VERSION 5.8 ;
BUSBITCHARS "[]" ;
DIVIDERCHAR "/" ;
UNITS
    DATABASE MICRONS 1000 ;
END UNITS

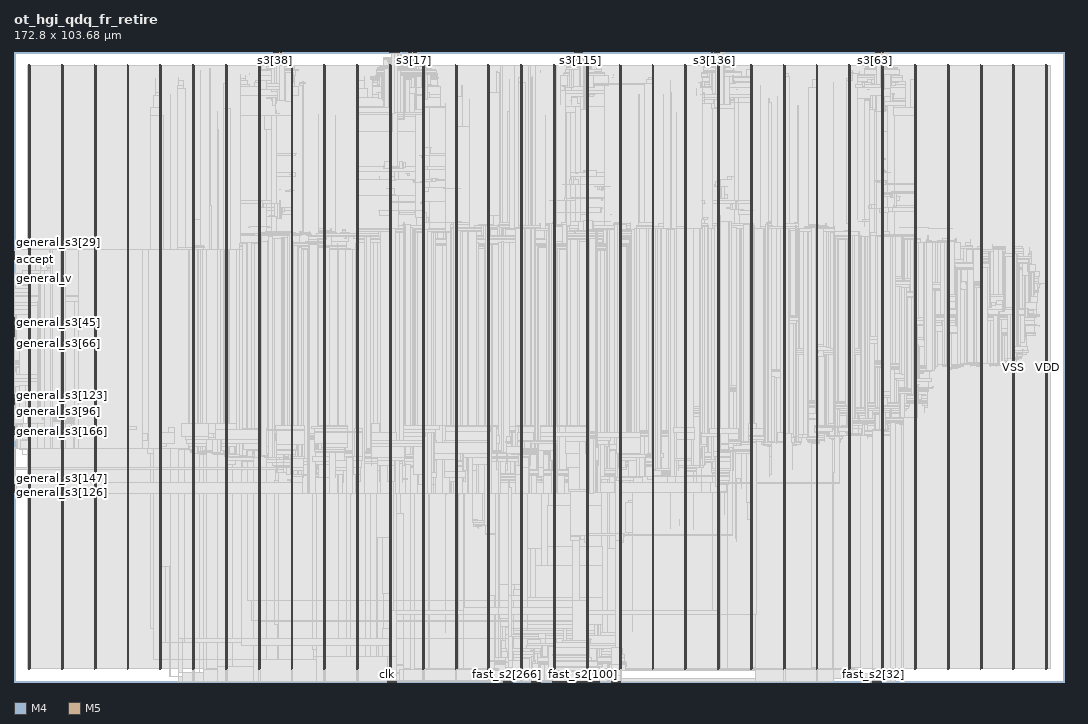
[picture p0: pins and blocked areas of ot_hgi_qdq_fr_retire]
MACRO ot_hgi_qdq_fr_retire
  FOREIGN ot_hgi_qdq_fr_retire 0 0 ;
  CLASS BLOCK ;
  SIZE 172.8 BY 103.68 ;
  PIN accept
    DIRECTION INPUT ;
    USE SIGNAL ;
    PORT
      LAYER M4 ;
        RECT  0 69.552 0.084 69.576 ;
    END
  END accept
  PIN accept_one
    DIRECTION INPUT ;
    USE SIGNAL ;
    PORT
      LAYER M4 ;
        RECT  0 69.6 0.084 69.624 ;
    END
  END accept_one
  PIN clk
    DIRECTION INPUT ;
    USE SIGNAL ;
    PORT
      LAYER M5 ;
        RECT  61.392 0 61.416 0.084 ;
    END
  END clk
  PIN fast_one
    DIRECTION INPUT ;
    USE SIGNAL ;
    PORT
      LAYER M5 ;
        RECT  61.44 0 61.464 0.084 ;
    END
  END fast_one
  PIN fast_s2[0]
    DIRECTION INPUT ;
    USE SIGNAL ;
    PORT
      LAYER M5 ;
        RECT  61.488 0 61.512 0.084 ;
    END
  END fast_s2[0]
  PIN fast_s2[100]
    DIRECTION INPUT ;
    USE SIGNAL ;
    PORT
      LAYER M5 ;
        RECT  93.552 0 93.576 0.084 ;
    END
  END fast_s2[100]
  PIN fast_s2[101]
    DIRECTION INPUT ;
    USE SIGNAL ;
    PORT
      LAYER M5 ;
        RECT  93.6 0 93.624 0.084 ;
    END
  END fast_s2[101]
  PIN fast_s2[102]
    DIRECTION INPUT ;
    USE SIGNAL ;
    PORT
      LAYER M5 ;
        RECT  93.648 0 93.672 0.084 ;
    END
  END fast_s2[102]
  PIN fast_s2[103]
    DIRECTION INPUT ;
    USE SIGNAL ;
    PORT
      LAYER M5 ;
        RECT  93.696 0 93.72 0.084 ;
    END
  END fast_s2[103]
  PIN fast_s2[104]
    DIRECTION INPUT ;
    USE SIGNAL ;
    PORT
      LAYER M5 ;
        RECT  93.744 0 93.768 0.084 ;
    END
  END fast_s2[104]
  PIN fast_s2[105]
    DIRECTION INPUT ;
    USE SIGNAL ;
    PORT
      LAYER M5 ;
        RECT  93.792 0 93.816 0.084 ;
    END
  END fast_s2[105]
  PIN fast_s2[106]
    DIRECTION INPUT ;
    USE SIGNAL ;
    PORT
      LAYER M5 ;
        RECT  93.84 0 93.864 0.084 ;
    END
  END fast_s2[106]
  PIN fast_s2[107]
    DIRECTION INPUT ;
    USE SIGNAL ;
    PORT
      LAYER M5 ;
        RECT  93.888 0 93.912 0.084 ;
    END
  END fast_s2[107]
  PIN fast_s2[108]
    DIRECTION INPUT ;
    USE SIGNAL ;
    PORT
      LAYER M5 ;
        RECT  93.936 0 93.96 0.084 ;
    END
  END fast_s2[108]
  PIN fast_s2[109]
    DIRECTION INPUT ;
    USE SIGNAL ;
    PORT
      LAYER M5 ;
        RECT  93.984 0 94.008 0.084 ;
    END
  END fast_s2[109]
  PIN fast_s2[10]
    DIRECTION INPUT ;
    USE SIGNAL ;
    PORT
      LAYER M5 ;
        RECT  61.968 0 61.992 0.084 ;
    END
  END fast_s2[10]
  PIN fast_s2[110]
    DIRECTION INPUT ;
    USE SIGNAL ;
    PORT
      LAYER M5 ;
        RECT  94.032 0 94.056 0.084 ;
    END
  END fast_s2[110]
  PIN fast_s2[111]
    DIRECTION INPUT ;
    USE SIGNAL ;
    PORT
      LAYER M5 ;
        RECT  94.08 0 94.104 0.084 ;
    END
  END fast_s2[111]
  PIN fast_s2[112]
    DIRECTION INPUT ;
    USE SIGNAL ;
    PORT
      LAYER M5 ;
        RECT  94.128 0 94.152 0.084 ;
    END
  END fast_s2[112]
  PIN fast_s2[113]
    DIRECTION INPUT ;
    USE SIGNAL ;
    PORT
      LAYER M5 ;
        RECT  94.176 0 94.2 0.084 ;
    END
  END fast_s2[113]
  PIN fast_s2[114]
    DIRECTION INPUT ;
    USE SIGNAL ;
    PORT
      LAYER M5 ;
        RECT  94.224 0 94.248 0.084 ;
    END
  END fast_s2[114]
  PIN fast_s2[115]
    DIRECTION INPUT ;
    USE SIGNAL ;
    PORT
      LAYER M5 ;
        RECT  94.272 0 94.296 0.084 ;
    END
  END fast_s2[115]
  PIN fast_s2[116]
    DIRECTION INPUT ;
    USE SIGNAL ;
    PORT
      LAYER M5 ;
        RECT  94.32 0 94.344 0.084 ;
    END
  END fast_s2[116]
  PIN fast_s2[117]
    DIRECTION INPUT ;
    USE SIGNAL ;
    PORT
      LAYER M5 ;
        RECT  94.368 0 94.392 0.084 ;
    END
  END fast_s2[117]
  PIN fast_s2[118]
    DIRECTION INPUT ;
    USE SIGNAL ;
    PORT
      LAYER M5 ;
        RECT  94.416 0 94.44 0.084 ;
    END
  END fast_s2[118]
  PIN fast_s2[119]
    DIRECTION INPUT ;
    USE SIGNAL ;
    PORT
      LAYER M5 ;
        RECT  94.464 0 94.488 0.084 ;
    END
  END fast_s2[119]
  PIN fast_s2[11]
    DIRECTION INPUT ;
    USE SIGNAL ;
    PORT
      LAYER M5 ;
        RECT  62.016 0 62.04 0.084 ;
    END
  END fast_s2[11]
  PIN fast_s2[120]
    DIRECTION INPUT ;
    USE SIGNAL ;
    PORT
      LAYER M5 ;
        RECT  94.512 0 94.536 0.084 ;
    END
  END fast_s2[120]
  PIN fast_s2[121]
    DIRECTION INPUT ;
    USE SIGNAL ;
    PORT
      LAYER M5 ;
        RECT  94.56 0 94.584 0.084 ;
    END
  END fast_s2[121]
  PIN fast_s2[122]
    DIRECTION INPUT ;
    USE SIGNAL ;
    PORT
      LAYER M5 ;
        RECT  94.608 0 94.632 0.084 ;
    END
  END fast_s2[122]
  PIN fast_s2[123]
    DIRECTION INPUT ;
    USE SIGNAL ;
    PORT
      LAYER M5 ;
        RECT  94.656 0 94.68 0.084 ;
    END
  END fast_s2[123]
  PIN fast_s2[124]
    DIRECTION INPUT ;
    USE SIGNAL ;
    PORT
      LAYER M5 ;
        RECT  94.704 0 94.728 0.084 ;
    END
  END fast_s2[124]
  PIN fast_s2[125]
    DIRECTION INPUT ;
    USE SIGNAL ;
    PORT
      LAYER M5 ;
        RECT  94.752 0 94.776 0.084 ;
    END
  END fast_s2[125]
  PIN fast_s2[126]
    DIRECTION INPUT ;
    USE SIGNAL ;
    PORT
      LAYER M5 ;
        RECT  90.192 0 90.216 0.084 ;
    END
  END fast_s2[126]
  PIN fast_s2[127]
    DIRECTION INPUT ;
    USE SIGNAL ;
    PORT
      LAYER M5 ;
        RECT  90.24 0 90.264 0.084 ;
    END
  END fast_s2[127]
  PIN fast_s2[128]
    DIRECTION INPUT ;
    USE SIGNAL ;
    PORT
      LAYER M5 ;
        RECT  90.288 0 90.312 0.084 ;
    END
  END fast_s2[128]
  PIN fast_s2[129]
    DIRECTION INPUT ;
    USE SIGNAL ;
    PORT
      LAYER M5 ;
        RECT  90.336 0 90.36 0.084 ;
    END
  END fast_s2[129]
  PIN fast_s2[12]
    DIRECTION INPUT ;
    USE SIGNAL ;
    PORT
      LAYER M5 ;
        RECT  62.064 0 62.088 0.084 ;
    END
  END fast_s2[12]
  PIN fast_s2[130]
    DIRECTION INPUT ;
    USE SIGNAL ;
    PORT
      LAYER M5 ;
        RECT  90.384 0 90.408 0.084 ;
    END
  END fast_s2[130]
  PIN fast_s2[131]
    DIRECTION INPUT ;
    USE SIGNAL ;
    PORT
      LAYER M5 ;
        RECT  90.432 0 90.456 0.084 ;
    END
  END fast_s2[131]
  PIN fast_s2[132]
    DIRECTION INPUT ;
    USE SIGNAL ;
    PORT
      LAYER M5 ;
        RECT  90.48 0 90.504 0.084 ;
    END
  END fast_s2[132]
  PIN fast_s2[133]
    DIRECTION INPUT ;
    USE SIGNAL ;
    PORT
      LAYER M5 ;
        RECT  90.528 0 90.552 0.084 ;
    END
  END fast_s2[133]
  PIN fast_s2[134]
    DIRECTION INPUT ;
    USE SIGNAL ;
    PORT
      LAYER M5 ;
        RECT  90.576 0 90.6 0.084 ;
    END
  END fast_s2[134]
  PIN fast_s2[135]
    DIRECTION INPUT ;
    USE SIGNAL ;
    PORT
      LAYER M5 ;
        RECT  90.624 0 90.648 0.084 ;
    END
  END fast_s2[135]
  PIN fast_s2[136]
    DIRECTION INPUT ;
    USE SIGNAL ;
    PORT
      LAYER M5 ;
        RECT  90.672 0 90.696 0.084 ;
    END
  END fast_s2[136]
  PIN fast_s2[137]
    DIRECTION INPUT ;
    USE SIGNAL ;
    PORT
      LAYER M5 ;
        RECT  90.72 0 90.744 0.084 ;
    END
  END fast_s2[137]
  PIN fast_s2[138]
    DIRECTION INPUT ;
    USE SIGNAL ;
    PORT
      LAYER M5 ;
        RECT  90.768 0 90.792 0.084 ;
    END
  END fast_s2[138]
  PIN fast_s2[139]
    DIRECTION INPUT ;
    USE SIGNAL ;
    PORT
      LAYER M5 ;
        RECT  90.816 0 90.84 0.084 ;
    END
  END fast_s2[139]
  PIN fast_s2[13]
    DIRECTION INPUT ;
    USE SIGNAL ;
    PORT
      LAYER M5 ;
        RECT  62.112 0 62.136 0.084 ;
    END
  END fast_s2[13]
  PIN fast_s2[140]
    DIRECTION INPUT ;
    USE SIGNAL ;
    PORT
      LAYER M5 ;
        RECT  90.864 0 90.888 0.084 ;
    END
  END fast_s2[140]
  PIN fast_s2[141]
    DIRECTION INPUT ;
    USE SIGNAL ;
    PORT
      LAYER M5 ;
        RECT  90.912 0 90.936 0.084 ;
    END
  END fast_s2[141]
  PIN fast_s2[142]
    DIRECTION INPUT ;
    USE SIGNAL ;
    PORT
      LAYER M5 ;
        RECT  90.96 0 90.984 0.084 ;
    END
  END fast_s2[142]
  PIN fast_s2[143]
    DIRECTION INPUT ;
    USE SIGNAL ;
    PORT
      LAYER M5 ;
        RECT  91.008 0 91.032 0.084 ;
    END
  END fast_s2[143]
  PIN fast_s2[144]
    DIRECTION INPUT ;
    USE SIGNAL ;
    PORT
      LAYER M5 ;
        RECT  91.056 0 91.08 0.084 ;
    END
  END fast_s2[144]
  PIN fast_s2[145]
    DIRECTION INPUT ;
    USE SIGNAL ;
    PORT
      LAYER M5 ;
        RECT  91.104 0 91.128 0.084 ;
    END
  END fast_s2[145]
  PIN fast_s2[146]
    DIRECTION INPUT ;
    USE SIGNAL ;
    PORT
      LAYER M5 ;
        RECT  91.152 0 91.176 0.084 ;
    END
  END fast_s2[146]
  PIN fast_s2[147]
    DIRECTION INPUT ;
    USE SIGNAL ;
    PORT
      LAYER M5 ;
        RECT  91.2 0 91.224 0.084 ;
    END
  END fast_s2[147]
  PIN fast_s2[148]
    DIRECTION INPUT ;
    USE SIGNAL ;
    PORT
      LAYER M5 ;
        RECT  91.248 0 91.272 0.084 ;
    END
  END fast_s2[148]
  PIN fast_s2[149]
    DIRECTION INPUT ;
    USE SIGNAL ;
    PORT
      LAYER M5 ;
        RECT  91.296 0 91.32 0.084 ;
    END
  END fast_s2[149]
  PIN fast_s2[14]
    DIRECTION INPUT ;
    USE SIGNAL ;
    PORT
      LAYER M5 ;
        RECT  62.16 0 62.184 0.084 ;
    END
  END fast_s2[14]
  PIN fast_s2[150]
    DIRECTION INPUT ;
    USE SIGNAL ;
    PORT
      LAYER M5 ;
        RECT  91.344 0 91.368 0.084 ;
    END
  END fast_s2[150]
  PIN fast_s2[151]
    DIRECTION INPUT ;
    USE SIGNAL ;
    PORT
      LAYER M5 ;
        RECT  91.392 0 91.416 0.084 ;
    END
  END fast_s2[151]
  PIN fast_s2[152]
    DIRECTION INPUT ;
    USE SIGNAL ;
    PORT
      LAYER M5 ;
        RECT  91.44 0 91.464 0.084 ;
    END
  END fast_s2[152]
  PIN fast_s2[153]
    DIRECTION INPUT ;
    USE SIGNAL ;
    PORT
      LAYER M5 ;
        RECT  91.488 0 91.512 0.084 ;
    END
  END fast_s2[153]
  PIN fast_s2[154]
    DIRECTION INPUT ;
    USE SIGNAL ;
    PORT
      LAYER M5 ;
        RECT  91.536 0 91.56 0.084 ;
    END
  END fast_s2[154]
  PIN fast_s2[155]
    DIRECTION INPUT ;
    USE SIGNAL ;
    PORT
      LAYER M5 ;
        RECT  91.584 0 91.608 0.084 ;
    END
  END fast_s2[155]
  PIN fast_s2[156]
    DIRECTION INPUT ;
    USE SIGNAL ;
    PORT
      LAYER M5 ;
        RECT  91.632 0 91.656 0.084 ;
    END
  END fast_s2[156]
  PIN fast_s2[157]
    DIRECTION INPUT ;
    USE SIGNAL ;
    PORT
      LAYER M5 ;
        RECT  91.68 0 91.704 0.084 ;
    END
  END fast_s2[157]
  PIN fast_s2[158]
    DIRECTION INPUT ;
    USE SIGNAL ;
    PORT
      LAYER M5 ;
        RECT  88.656 0 88.68 0.084 ;
    END
  END fast_s2[158]
  PIN fast_s2[159]
    DIRECTION INPUT ;
    USE SIGNAL ;
    PORT
      LAYER M5 ;
        RECT  88.704 0 88.728 0.084 ;
    END
  END fast_s2[159]
  PIN fast_s2[15]
    DIRECTION INPUT ;
    USE SIGNAL ;
    PORT
      LAYER M5 ;
        RECT  62.208 0 62.232 0.084 ;
    END
  END fast_s2[15]
  PIN fast_s2[160]
    DIRECTION INPUT ;
    USE SIGNAL ;
    PORT
      LAYER M5 ;
        RECT  88.752 0 88.776 0.084 ;
    END
  END fast_s2[160]
  PIN fast_s2[161]
    DIRECTION INPUT ;
    USE SIGNAL ;
    PORT
      LAYER M5 ;
        RECT  88.8 0 88.824 0.084 ;
    END
  END fast_s2[161]
  PIN fast_s2[162]
    DIRECTION INPUT ;
    USE SIGNAL ;
    PORT
      LAYER M5 ;
        RECT  88.848 0 88.872 0.084 ;
    END
  END fast_s2[162]
  PIN fast_s2[163]
    DIRECTION INPUT ;
    USE SIGNAL ;
    PORT
      LAYER M5 ;
        RECT  88.896 0 88.92 0.084 ;
    END
  END fast_s2[163]
  PIN fast_s2[164]
    DIRECTION INPUT ;
    USE SIGNAL ;
    PORT
      LAYER M5 ;
        RECT  88.944 0 88.968 0.084 ;
    END
  END fast_s2[164]
  PIN fast_s2[165]
    DIRECTION INPUT ;
    USE SIGNAL ;
    PORT
      LAYER M5 ;
        RECT  88.992 0 89.016 0.084 ;
    END
  END fast_s2[165]
  PIN fast_s2[166]
    DIRECTION INPUT ;
    USE SIGNAL ;
    PORT
      LAYER M5 ;
        RECT  89.04 0 89.064 0.084 ;
    END
  END fast_s2[166]
  PIN fast_s2[167]
    DIRECTION INPUT ;
    USE SIGNAL ;
    PORT
      LAYER M5 ;
        RECT  89.088 0 89.112 0.084 ;
    END
  END fast_s2[167]
  PIN fast_s2[168]
    DIRECTION INPUT ;
    USE SIGNAL ;
    PORT
      LAYER M5 ;
        RECT  89.136 0 89.16 0.084 ;
    END
  END fast_s2[168]
  PIN fast_s2[169]
    DIRECTION INPUT ;
    USE SIGNAL ;
    PORT
      LAYER M5 ;
        RECT  89.184 0 89.208 0.084 ;
    END
  END fast_s2[169]
  PIN fast_s2[16]
    DIRECTION INPUT ;
    USE SIGNAL ;
    PORT
      LAYER M5 ;
        RECT  62.256 0 62.28 0.084 ;
    END
  END fast_s2[16]
  PIN fast_s2[170]
    DIRECTION INPUT ;
    USE SIGNAL ;
    PORT
      LAYER M5 ;
        RECT  89.232 0 89.256 0.084 ;
    END
  END fast_s2[170]
  PIN fast_s2[171]
    DIRECTION INPUT ;
    USE SIGNAL ;
    PORT
      LAYER M5 ;
        RECT  89.28 0 89.304 0.084 ;
    END
  END fast_s2[171]
  PIN fast_s2[172]
    DIRECTION INPUT ;
    USE SIGNAL ;
    PORT
      LAYER M5 ;
        RECT  89.328 0 89.352 0.084 ;
    END
  END fast_s2[172]
  PIN fast_s2[173]
    DIRECTION INPUT ;
    USE SIGNAL ;
    PORT
      LAYER M5 ;
        RECT  89.376 0 89.4 0.084 ;
    END
  END fast_s2[173]
  PIN fast_s2[174]
    DIRECTION INPUT ;
    USE SIGNAL ;
    PORT
      LAYER M5 ;
        RECT  89.424 0 89.448 0.084 ;
    END
  END fast_s2[174]
  PIN fast_s2[175]
    DIRECTION INPUT ;
    USE SIGNAL ;
    PORT
      LAYER M5 ;
        RECT  89.472 0 89.496 0.084 ;
    END
  END fast_s2[175]
  PIN fast_s2[176]
    DIRECTION INPUT ;
    USE SIGNAL ;
    PORT
      LAYER M5 ;
        RECT  89.52 0 89.544 0.084 ;
    END
  END fast_s2[176]
  PIN fast_s2[177]
    DIRECTION INPUT ;
    USE SIGNAL ;
    PORT
      LAYER M5 ;
        RECT  89.568 0 89.592 0.084 ;
    END
  END fast_s2[177]
  PIN fast_s2[178]
    DIRECTION INPUT ;
    USE SIGNAL ;
    PORT
      LAYER M5 ;
        RECT  89.616 0 89.64 0.084 ;
    END
  END fast_s2[178]
  PIN fast_s2[179]
    DIRECTION INPUT ;
    USE SIGNAL ;
    PORT
      LAYER M5 ;
        RECT  89.664 0 89.688 0.084 ;
    END
  END fast_s2[179]
  PIN fast_s2[17]
    DIRECTION INPUT ;
    USE SIGNAL ;
    PORT
      LAYER M5 ;
        RECT  62.304 0 62.328 0.084 ;
    END
  END fast_s2[17]
  PIN fast_s2[180]
    DIRECTION INPUT ;
    USE SIGNAL ;
    PORT
      LAYER M5 ;
        RECT  89.712 0 89.736 0.084 ;
    END
  END fast_s2[180]
  PIN fast_s2[181]
    DIRECTION INPUT ;
    USE SIGNAL ;
    PORT
      LAYER M5 ;
        RECT  89.76 0 89.784 0.084 ;
    END
  END fast_s2[181]
  PIN fast_s2[182]
    DIRECTION INPUT ;
    USE SIGNAL ;
    PORT
      LAYER M5 ;
        RECT  89.808 0 89.832 0.084 ;
    END
  END fast_s2[182]
  PIN fast_s2[183]
    DIRECTION INPUT ;
    USE SIGNAL ;
    PORT
      LAYER M5 ;
        RECT  89.856 0 89.88 0.084 ;
    END
  END fast_s2[183]
  PIN fast_s2[184]
    DIRECTION INPUT ;
    USE SIGNAL ;
    PORT
      LAYER M5 ;
        RECT  89.904 0 89.928 0.084 ;
    END
  END fast_s2[184]
  PIN fast_s2[185]
    DIRECTION INPUT ;
    USE SIGNAL ;
    PORT
      LAYER M5 ;
        RECT  89.952 0 89.976 0.084 ;
    END
  END fast_s2[185]
  PIN fast_s2[186]
    DIRECTION INPUT ;
    USE SIGNAL ;
    PORT
      LAYER M5 ;
        RECT  90 0 90.024 0.084 ;
    END
  END fast_s2[186]
  PIN fast_s2[187]
    DIRECTION INPUT ;
    USE SIGNAL ;
    PORT
      LAYER M5 ;
        RECT  90.048 0 90.072 0.084 ;
    END
  END fast_s2[187]
  PIN fast_s2[188]
    DIRECTION INPUT ;
    USE SIGNAL ;
    PORT
      LAYER M5 ;
        RECT  90.096 0 90.12 0.084 ;
    END
  END fast_s2[188]
  PIN fast_s2[189]
    DIRECTION INPUT ;
    USE SIGNAL ;
    PORT
      LAYER M5 ;
        RECT  90.144 0 90.168 0.084 ;
    END
  END fast_s2[189]
  PIN fast_s2[18]
    DIRECTION INPUT ;
    USE SIGNAL ;
    PORT
      LAYER M5 ;
        RECT  62.352 0 62.376 0.084 ;
    END
  END fast_s2[18]
  PIN fast_s2[190]
    DIRECTION INPUT ;
    USE SIGNAL ;
    PORT
      LAYER M5 ;
        RECT  98.256 0 98.28 0.084 ;
    END
  END fast_s2[190]
  PIN fast_s2[191]
    DIRECTION INPUT ;
    USE SIGNAL ;
    PORT
      LAYER M5 ;
        RECT  98.304 0 98.328 0.084 ;
    END
  END fast_s2[191]
  PIN fast_s2[192]
    DIRECTION INPUT ;
    USE SIGNAL ;
    PORT
      LAYER M5 ;
        RECT  98.352 0 98.376 0.084 ;
    END
  END fast_s2[192]
  PIN fast_s2[193]
    DIRECTION INPUT ;
    USE SIGNAL ;
    PORT
      LAYER M5 ;
        RECT  98.4 0 98.424 0.084 ;
    END
  END fast_s2[193]
  PIN fast_s2[194]
    DIRECTION INPUT ;
    USE SIGNAL ;
    PORT
      LAYER M5 ;
        RECT  98.448 0 98.472 0.084 ;
    END
  END fast_s2[194]
  PIN fast_s2[195]
    DIRECTION INPUT ;
    USE SIGNAL ;
    PORT
      LAYER M5 ;
        RECT  98.496 0 98.52 0.084 ;
    END
  END fast_s2[195]
  PIN fast_s2[196]
    DIRECTION INPUT ;
    USE SIGNAL ;
    PORT
      LAYER M5 ;
        RECT  98.544 0 98.568 0.084 ;
    END
  END fast_s2[196]
  PIN fast_s2[197]
    DIRECTION INPUT ;
    USE SIGNAL ;
    PORT
      LAYER M5 ;
        RECT  98.592 0 98.616 0.084 ;
    END
  END fast_s2[197]
  PIN fast_s2[198]
    DIRECTION INPUT ;
    USE SIGNAL ;
    PORT
      LAYER M5 ;
        RECT  98.64 0 98.664 0.084 ;
    END
  END fast_s2[198]
  PIN fast_s2[199]
    DIRECTION INPUT ;
    USE SIGNAL ;
    PORT
      LAYER M5 ;
        RECT  98.688 0 98.712 0.084 ;
    END
  END fast_s2[199]
  PIN fast_s2[19]
    DIRECTION INPUT ;
    USE SIGNAL ;
    PORT
      LAYER M5 ;
        RECT  62.4 0 62.424 0.084 ;
    END
  END fast_s2[19]
  PIN fast_s2[1]
    DIRECTION INPUT ;
    USE SIGNAL ;
    PORT
      LAYER M5 ;
        RECT  61.536 0 61.56 0.084 ;
    END
  END fast_s2[1]
  PIN fast_s2[200]
    DIRECTION INPUT ;
    USE SIGNAL ;
    PORT
      LAYER M5 ;
        RECT  98.736 0 98.76 0.084 ;
    END
  END fast_s2[200]
  PIN fast_s2[201]
    DIRECTION INPUT ;
    USE SIGNAL ;
    PORT
      LAYER M5 ;
        RECT  98.784 0 98.808 0.084 ;
    END
  END fast_s2[201]
  PIN fast_s2[202]
    DIRECTION INPUT ;
    USE SIGNAL ;
    PORT
      LAYER M5 ;
        RECT  98.832 0 98.856 0.084 ;
    END
  END fast_s2[202]
  PIN fast_s2[203]
    DIRECTION INPUT ;
    USE SIGNAL ;
    PORT
      LAYER M5 ;
        RECT  98.88 0 98.904 0.084 ;
    END
  END fast_s2[203]
  PIN fast_s2[204]
    DIRECTION INPUT ;
    USE SIGNAL ;
    PORT
      LAYER M5 ;
        RECT  98.928 0 98.952 0.084 ;
    END
  END fast_s2[204]
  PIN fast_s2[205]
    DIRECTION INPUT ;
    USE SIGNAL ;
    PORT
      LAYER M5 ;
        RECT  98.976 0 99 0.084 ;
    END
  END fast_s2[205]
  PIN fast_s2[206]
    DIRECTION INPUT ;
    USE SIGNAL ;
    PORT
      LAYER M5 ;
        RECT  99.024 0 99.048 0.084 ;
    END
  END fast_s2[206]
  PIN fast_s2[207]
    DIRECTION INPUT ;
    USE SIGNAL ;
    PORT
      LAYER M5 ;
        RECT  99.072 0 99.096 0.084 ;
    END
  END fast_s2[207]
  PIN fast_s2[208]
    DIRECTION INPUT ;
    USE SIGNAL ;
    PORT
      LAYER M5 ;
        RECT  99.12 0 99.144 0.084 ;
    END
  END fast_s2[208]
  PIN fast_s2[209]
    DIRECTION INPUT ;
    USE SIGNAL ;
    PORT
      LAYER M5 ;
        RECT  99.168 0 99.192 0.084 ;
    END
  END fast_s2[209]
  PIN fast_s2[20]
    DIRECTION INPUT ;
    USE SIGNAL ;
    PORT
      LAYER M5 ;
        RECT  62.448 0 62.472 0.084 ;
    END
  END fast_s2[20]
  PIN fast_s2[210]
    DIRECTION INPUT ;
    USE SIGNAL ;
    PORT
      LAYER M5 ;
        RECT  99.216 0 99.24 0.084 ;
    END
  END fast_s2[210]
  PIN fast_s2[211]
    DIRECTION INPUT ;
    USE SIGNAL ;
    PORT
      LAYER M5 ;
        RECT  99.264 0 99.288 0.084 ;
    END
  END fast_s2[211]
  PIN fast_s2[212]
    DIRECTION INPUT ;
    USE SIGNAL ;
    PORT
      LAYER M5 ;
        RECT  99.312 0 99.336 0.084 ;
    END
  END fast_s2[212]
  PIN fast_s2[213]
    DIRECTION INPUT ;
    USE SIGNAL ;
    PORT
      LAYER M5 ;
        RECT  99.36 0 99.384 0.084 ;
    END
  END fast_s2[213]
  PIN fast_s2[214]
    DIRECTION INPUT ;
    USE SIGNAL ;
    PORT
      LAYER M5 ;
        RECT  99.408 0 99.432 0.084 ;
    END
  END fast_s2[214]
  PIN fast_s2[215]
    DIRECTION INPUT ;
    USE SIGNAL ;
    PORT
      LAYER M5 ;
        RECT  99.456 0 99.48 0.084 ;
    END
  END fast_s2[215]
  PIN fast_s2[216]
    DIRECTION INPUT ;
    USE SIGNAL ;
    PORT
      LAYER M5 ;
        RECT  99.504 0 99.528 0.084 ;
    END
  END fast_s2[216]
  PIN fast_s2[217]
    DIRECTION INPUT ;
    USE SIGNAL ;
    PORT
      LAYER M5 ;
        RECT  99.552 0 99.576 0.084 ;
    END
  END fast_s2[217]
  PIN fast_s2[218]
    DIRECTION INPUT ;
    USE SIGNAL ;
    PORT
      LAYER M5 ;
        RECT  99.6 0 99.624 0.084 ;
    END
  END fast_s2[218]
  PIN fast_s2[219]
    DIRECTION INPUT ;
    USE SIGNAL ;
    PORT
      LAYER M5 ;
        RECT  99.648 0 99.672 0.084 ;
    END
  END fast_s2[219]
  PIN fast_s2[21]
    DIRECTION INPUT ;
    USE SIGNAL ;
    PORT
      LAYER M5 ;
        RECT  62.496 0 62.52 0.084 ;
    END
  END fast_s2[21]
  PIN fast_s2[220]
    DIRECTION INPUT ;
    USE SIGNAL ;
    PORT
      LAYER M5 ;
        RECT  99.696 0 99.72 0.084 ;
    END
  END fast_s2[220]
  PIN fast_s2[221]
    DIRECTION INPUT ;
    USE SIGNAL ;
    PORT
      LAYER M5 ;
        RECT  99.744 0 99.768 0.084 ;
    END
  END fast_s2[221]
  PIN fast_s2[222]
    DIRECTION INPUT ;
    USE SIGNAL ;
    PORT
      LAYER M5 ;
        RECT  94.8 0 94.824 0.084 ;
    END
  END fast_s2[222]
  PIN fast_s2[223]
    DIRECTION INPUT ;
    USE SIGNAL ;
    PORT
      LAYER M5 ;
        RECT  94.848 0 94.872 0.084 ;
    END
  END fast_s2[223]
  PIN fast_s2[224]
    DIRECTION INPUT ;
    USE SIGNAL ;
    PORT
      LAYER M5 ;
        RECT  94.896 0 94.92 0.084 ;
    END
  END fast_s2[224]
  PIN fast_s2[225]
    DIRECTION INPUT ;
    USE SIGNAL ;
    PORT
      LAYER M5 ;
        RECT  94.944 0 94.968 0.084 ;
    END
  END fast_s2[225]
  PIN fast_s2[226]
    DIRECTION INPUT ;
    USE SIGNAL ;
    PORT
      LAYER M5 ;
        RECT  94.992 0 95.016 0.084 ;
    END
  END fast_s2[226]
  PIN fast_s2[227]
    DIRECTION INPUT ;
    USE SIGNAL ;
    PORT
      LAYER M5 ;
        RECT  95.04 0 95.064 0.084 ;
    END
  END fast_s2[227]
  PIN fast_s2[228]
    DIRECTION INPUT ;
    USE SIGNAL ;
    PORT
      LAYER M5 ;
        RECT  95.088 0 95.112 0.084 ;
    END
  END fast_s2[228]
  PIN fast_s2[229]
    DIRECTION INPUT ;
    USE SIGNAL ;
    PORT
      LAYER M5 ;
        RECT  95.136 0 95.16 0.084 ;
    END
  END fast_s2[229]
  PIN fast_s2[22]
    DIRECTION INPUT ;
    USE SIGNAL ;
    PORT
      LAYER M5 ;
        RECT  62.544 0 62.568 0.084 ;
    END
  END fast_s2[22]
  PIN fast_s2[230]
    DIRECTION INPUT ;
    USE SIGNAL ;
    PORT
      LAYER M5 ;
        RECT  95.184 0 95.208 0.084 ;
    END
  END fast_s2[230]
  PIN fast_s2[231]
    DIRECTION INPUT ;
    USE SIGNAL ;
    PORT
      LAYER M5 ;
        RECT  95.232 0 95.256 0.084 ;
    END
  END fast_s2[231]
  PIN fast_s2[232]
    DIRECTION INPUT ;
    USE SIGNAL ;
    PORT
      LAYER M5 ;
        RECT  95.28 0 95.304 0.084 ;
    END
  END fast_s2[232]
  PIN fast_s2[233]
    DIRECTION INPUT ;
    USE SIGNAL ;
    PORT
      LAYER M5 ;
        RECT  95.328 0 95.352 0.084 ;
    END
  END fast_s2[233]
  PIN fast_s2[234]
    DIRECTION INPUT ;
    USE SIGNAL ;
    PORT
      LAYER M5 ;
        RECT  95.376 0 95.4 0.084 ;
    END
  END fast_s2[234]
  PIN fast_s2[235]
    DIRECTION INPUT ;
    USE SIGNAL ;
    PORT
      LAYER M5 ;
        RECT  95.424 0 95.448 0.084 ;
    END
  END fast_s2[235]
  PIN fast_s2[236]
    DIRECTION INPUT ;
    USE SIGNAL ;
    PORT
      LAYER M5 ;
        RECT  95.472 0 95.496 0.084 ;
    END
  END fast_s2[236]
  PIN fast_s2[237]
    DIRECTION INPUT ;
    USE SIGNAL ;
    PORT
      LAYER M5 ;
        RECT  95.52 0 95.544 0.084 ;
    END
  END fast_s2[237]
  PIN fast_s2[238]
    DIRECTION INPUT ;
    USE SIGNAL ;
    PORT
      LAYER M5 ;
        RECT  95.568 0 95.592 0.084 ;
    END
  END fast_s2[238]
  PIN fast_s2[239]
    DIRECTION INPUT ;
    USE SIGNAL ;
    PORT
      LAYER M5 ;
        RECT  95.616 0 95.64 0.084 ;
    END
  END fast_s2[239]
  PIN fast_s2[23]
    DIRECTION INPUT ;
    USE SIGNAL ;
    PORT
      LAYER M5 ;
        RECT  62.592 0 62.616 0.084 ;
    END
  END fast_s2[23]
  PIN fast_s2[240]
    DIRECTION INPUT ;
    USE SIGNAL ;
    PORT
      LAYER M5 ;
        RECT  95.664 0 95.688 0.084 ;
    END
  END fast_s2[240]
  PIN fast_s2[241]
    DIRECTION INPUT ;
    USE SIGNAL ;
    PORT
      LAYER M5 ;
        RECT  95.712 0 95.736 0.084 ;
    END
  END fast_s2[241]
  PIN fast_s2[242]
    DIRECTION INPUT ;
    USE SIGNAL ;
    PORT
      LAYER M5 ;
        RECT  95.76 0 95.784 0.084 ;
    END
  END fast_s2[242]
  PIN fast_s2[243]
    DIRECTION INPUT ;
    USE SIGNAL ;
    PORT
      LAYER M5 ;
        RECT  95.808 0 95.832 0.084 ;
    END
  END fast_s2[243]
  PIN fast_s2[244]
    DIRECTION INPUT ;
    USE SIGNAL ;
    PORT
      LAYER M5 ;
        RECT  95.856 0 95.88 0.084 ;
    END
  END fast_s2[244]
  PIN fast_s2[245]
    DIRECTION INPUT ;
    USE SIGNAL ;
    PORT
      LAYER M5 ;
        RECT  95.904 0 95.928 0.084 ;
    END
  END fast_s2[245]
  PIN fast_s2[246]
    DIRECTION INPUT ;
    USE SIGNAL ;
    PORT
      LAYER M5 ;
        RECT  95.952 0 95.976 0.084 ;
    END
  END fast_s2[246]
  PIN fast_s2[247]
    DIRECTION INPUT ;
    USE SIGNAL ;
    PORT
      LAYER M5 ;
        RECT  96 0 96.024 0.084 ;
    END
  END fast_s2[247]
  PIN fast_s2[248]
    DIRECTION INPUT ;
    USE SIGNAL ;
    PORT
      LAYER M5 ;
        RECT  96.048 0 96.072 0.084 ;
    END
  END fast_s2[248]
  PIN fast_s2[249]
    DIRECTION INPUT ;
    USE SIGNAL ;
    PORT
      LAYER M5 ;
        RECT  96.096 0 96.12 0.084 ;
    END
  END fast_s2[249]
  PIN fast_s2[24]
    DIRECTION INPUT ;
    USE SIGNAL ;
    PORT
      LAYER M5 ;
        RECT  62.64 0 62.664 0.084 ;
    END
  END fast_s2[24]
  PIN fast_s2[250]
    DIRECTION INPUT ;
    USE SIGNAL ;
    PORT
      LAYER M5 ;
        RECT  96.144 0 96.168 0.084 ;
    END
  END fast_s2[250]
  PIN fast_s2[251]
    DIRECTION INPUT ;
    USE SIGNAL ;
    PORT
      LAYER M5 ;
        RECT  96.192 0 96.216 0.084 ;
    END
  END fast_s2[251]
  PIN fast_s2[252]
    DIRECTION INPUT ;
    USE SIGNAL ;
    PORT
      LAYER M5 ;
        RECT  96.24 0 96.264 0.084 ;
    END
  END fast_s2[252]
  PIN fast_s2[253]
    DIRECTION INPUT ;
    USE SIGNAL ;
    PORT
      LAYER M5 ;
        RECT  96.288 0 96.312 0.084 ;
    END
  END fast_s2[253]
  PIN fast_s2[254]
    DIRECTION INPUT ;
    USE SIGNAL ;
    PORT
      LAYER M5 ;
        RECT  80.592 0 80.616 0.084 ;
    END
  END fast_s2[254]
  PIN fast_s2[255]
    DIRECTION INPUT ;
    USE SIGNAL ;
    PORT
      LAYER M5 ;
        RECT  80.64 0 80.664 0.084 ;
    END
  END fast_s2[255]
  PIN fast_s2[256]
    DIRECTION INPUT ;
    USE SIGNAL ;
    PORT
      LAYER M5 ;
        RECT  80.688 0 80.712 0.084 ;
    END
  END fast_s2[256]
  PIN fast_s2[257]
    DIRECTION INPUT ;
    USE SIGNAL ;
    PORT
      LAYER M5 ;
        RECT  80.736 0 80.76 0.084 ;
    END
  END fast_s2[257]
  PIN fast_s2[258]
    DIRECTION INPUT ;
    USE SIGNAL ;
    PORT
      LAYER M5 ;
        RECT  80.784 0 80.808 0.084 ;
    END
  END fast_s2[258]
  PIN fast_s2[259]
    DIRECTION INPUT ;
    USE SIGNAL ;
    PORT
      LAYER M5 ;
        RECT  80.832 0 80.856 0.084 ;
    END
  END fast_s2[259]
  PIN fast_s2[25]
    DIRECTION INPUT ;
    USE SIGNAL ;
    PORT
      LAYER M5 ;
        RECT  62.688 0 62.712 0.084 ;
    END
  END fast_s2[25]
  PIN fast_s2[260]
    DIRECTION INPUT ;
    USE SIGNAL ;
    PORT
      LAYER M5 ;
        RECT  80.88 0 80.904 0.084 ;
    END
  END fast_s2[260]
  PIN fast_s2[261]
    DIRECTION INPUT ;
    USE SIGNAL ;
    PORT
      LAYER M5 ;
        RECT  80.928 0 80.952 0.084 ;
    END
  END fast_s2[261]
  PIN fast_s2[262]
    DIRECTION INPUT ;
    USE SIGNAL ;
    PORT
      LAYER M5 ;
        RECT  80.976 0 81 0.084 ;
    END
  END fast_s2[262]
  PIN fast_s2[263]
    DIRECTION INPUT ;
    USE SIGNAL ;
    PORT
      LAYER M5 ;
        RECT  81.024 0 81.048 0.084 ;
    END
  END fast_s2[263]
  PIN fast_s2[264]
    DIRECTION INPUT ;
    USE SIGNAL ;
    PORT
      LAYER M5 ;
        RECT  81.072 0 81.096 0.084 ;
    END
  END fast_s2[264]
  PIN fast_s2[265]
    DIRECTION INPUT ;
    USE SIGNAL ;
    PORT
      LAYER M5 ;
        RECT  81.12 0 81.144 0.084 ;
    END
  END fast_s2[265]
  PIN fast_s2[266]
    DIRECTION INPUT ;
    USE SIGNAL ;
    PORT
      LAYER M5 ;
        RECT  81.168 0 81.192 0.084 ;
    END
  END fast_s2[266]
  PIN fast_s2[267]
    DIRECTION INPUT ;
    USE SIGNAL ;
    PORT
      LAYER M5 ;
        RECT  81.216 0 81.24 0.084 ;
    END
  END fast_s2[267]
  PIN fast_s2[268]
    DIRECTION INPUT ;
    USE SIGNAL ;
    PORT
      LAYER M5 ;
        RECT  81.264 0 81.288 0.084 ;
    END
  END fast_s2[268]
  PIN fast_s2[269]
    DIRECTION INPUT ;
    USE SIGNAL ;
    PORT
      LAYER M5 ;
        RECT  81.312 0 81.336 0.084 ;
    END
  END fast_s2[269]
  PIN fast_s2[26]
    DIRECTION INPUT ;
    USE SIGNAL ;
    PORT
      LAYER M5 ;
        RECT  62.736 0 62.76 0.084 ;
    END
  END fast_s2[26]
  PIN fast_s2[270]
    DIRECTION INPUT ;
    USE SIGNAL ;
    PORT
      LAYER M5 ;
        RECT  81.36 0 81.384 0.084 ;
    END
  END fast_s2[270]
  PIN fast_s2[271]
    DIRECTION INPUT ;
    USE SIGNAL ;
    PORT
      LAYER M5 ;
        RECT  81.408 0 81.432 0.084 ;
    END
  END fast_s2[271]
  PIN fast_s2[272]
    DIRECTION INPUT ;
    USE SIGNAL ;
    PORT
      LAYER M5 ;
        RECT  81.456 0 81.48 0.084 ;
    END
  END fast_s2[272]
  PIN fast_s2[273]
    DIRECTION INPUT ;
    USE SIGNAL ;
    PORT
      LAYER M5 ;
        RECT  81.504 0 81.528 0.084 ;
    END
  END fast_s2[273]
  PIN fast_s2[274]
    DIRECTION INPUT ;
    USE SIGNAL ;
    PORT
      LAYER M5 ;
        RECT  81.552 0 81.576 0.084 ;
    END
  END fast_s2[274]
  PIN fast_s2[275]
    DIRECTION INPUT ;
    USE SIGNAL ;
    PORT
      LAYER M5 ;
        RECT  81.6 0 81.624 0.084 ;
    END
  END fast_s2[275]
  PIN fast_s2[276]
    DIRECTION INPUT ;
    USE SIGNAL ;
    PORT
      LAYER M5 ;
        RECT  81.648 0 81.672 0.084 ;
    END
  END fast_s2[276]
  PIN fast_s2[277]
    DIRECTION INPUT ;
    USE SIGNAL ;
    PORT
      LAYER M5 ;
        RECT  81.696 0 81.72 0.084 ;
    END
  END fast_s2[277]
  PIN fast_s2[278]
    DIRECTION INPUT ;
    USE SIGNAL ;
    PORT
      LAYER M5 ;
        RECT  81.744 0 81.768 0.084 ;
    END
  END fast_s2[278]
  PIN fast_s2[279]
    DIRECTION INPUT ;
    USE SIGNAL ;
    PORT
      LAYER M5 ;
        RECT  81.792 0 81.816 0.084 ;
    END
  END fast_s2[279]
  PIN fast_s2[27]
    DIRECTION INPUT ;
    USE SIGNAL ;
    PORT
      LAYER M5 ;
        RECT  62.784 0 62.808 0.084 ;
    END
  END fast_s2[27]
  PIN fast_s2[280]
    DIRECTION INPUT ;
    USE SIGNAL ;
    PORT
      LAYER M5 ;
        RECT  81.84 0 81.864 0.084 ;
    END
  END fast_s2[280]
  PIN fast_s2[281]
    DIRECTION INPUT ;
    USE SIGNAL ;
    PORT
      LAYER M5 ;
        RECT  81.888 0 81.912 0.084 ;
    END
  END fast_s2[281]
  PIN fast_s2[282]
    DIRECTION INPUT ;
    USE SIGNAL ;
    PORT
      LAYER M5 ;
        RECT  81.936 0 81.96 0.084 ;
    END
  END fast_s2[282]
  PIN fast_s2[283]
    DIRECTION INPUT ;
    USE SIGNAL ;
    PORT
      LAYER M5 ;
        RECT  81.984 0 82.008 0.084 ;
    END
  END fast_s2[283]
  PIN fast_s2[284]
    DIRECTION INPUT ;
    USE SIGNAL ;
    PORT
      LAYER M5 ;
        RECT  82.032 0 82.056 0.084 ;
    END
  END fast_s2[284]
  PIN fast_s2[285]
    DIRECTION INPUT ;
    USE SIGNAL ;
    PORT
      LAYER M5 ;
        RECT  82.08 0 82.104 0.084 ;
    END
  END fast_s2[285]
  PIN fast_s2[286]
    DIRECTION INPUT ;
    USE SIGNAL ;
    PORT
      LAYER M5 ;
        RECT  85.2 0 85.224 0.084 ;
    END
  END fast_s2[286]
  PIN fast_s2[287]
    DIRECTION INPUT ;
    USE SIGNAL ;
    PORT
      LAYER M5 ;
        RECT  85.248 0 85.272 0.084 ;
    END
  END fast_s2[287]
  PIN fast_s2[288]
    DIRECTION INPUT ;
    USE SIGNAL ;
    PORT
      LAYER M5 ;
        RECT  85.296 0 85.32 0.084 ;
    END
  END fast_s2[288]
  PIN fast_s2[289]
    DIRECTION INPUT ;
    USE SIGNAL ;
    PORT
      LAYER M5 ;
        RECT  85.344 0 85.368 0.084 ;
    END
  END fast_s2[289]
  PIN fast_s2[28]
    DIRECTION INPUT ;
    USE SIGNAL ;
    PORT
      LAYER M5 ;
        RECT  62.832 0 62.856 0.084 ;
    END
  END fast_s2[28]
  PIN fast_s2[290]
    DIRECTION INPUT ;
    USE SIGNAL ;
    PORT
      LAYER M5 ;
        RECT  85.392 0 85.416 0.084 ;
    END
  END fast_s2[290]
  PIN fast_s2[291]
    DIRECTION INPUT ;
    USE SIGNAL ;
    PORT
      LAYER M5 ;
        RECT  85.44 0 85.464 0.084 ;
    END
  END fast_s2[291]
  PIN fast_s2[292]
    DIRECTION INPUT ;
    USE SIGNAL ;
    PORT
      LAYER M5 ;
        RECT  85.488 0 85.512 0.084 ;
    END
  END fast_s2[292]
  PIN fast_s2[293]
    DIRECTION INPUT ;
    USE SIGNAL ;
    PORT
      LAYER M5 ;
        RECT  85.536 0 85.56 0.084 ;
    END
  END fast_s2[293]
  PIN fast_s2[294]
    DIRECTION INPUT ;
    USE SIGNAL ;
    PORT
      LAYER M5 ;
        RECT  85.584 0 85.608 0.084 ;
    END
  END fast_s2[294]
  PIN fast_s2[295]
    DIRECTION INPUT ;
    USE SIGNAL ;
    PORT
      LAYER M5 ;
        RECT  85.632 0 85.656 0.084 ;
    END
  END fast_s2[295]
  PIN fast_s2[296]
    DIRECTION INPUT ;
    USE SIGNAL ;
    PORT
      LAYER M5 ;
        RECT  85.68 0 85.704 0.084 ;
    END
  END fast_s2[296]
  PIN fast_s2[297]
    DIRECTION INPUT ;
    USE SIGNAL ;
    PORT
      LAYER M5 ;
        RECT  85.728 0 85.752 0.084 ;
    END
  END fast_s2[297]
  PIN fast_s2[298]
    DIRECTION INPUT ;
    USE SIGNAL ;
    PORT
      LAYER M5 ;
        RECT  85.776 0 85.8 0.084 ;
    END
  END fast_s2[298]
  PIN fast_s2[299]
    DIRECTION INPUT ;
    USE SIGNAL ;
    PORT
      LAYER M5 ;
        RECT  85.824 0 85.848 0.084 ;
    END
  END fast_s2[299]
  PIN fast_s2[29]
    DIRECTION INPUT ;
    USE SIGNAL ;
    PORT
      LAYER M5 ;
        RECT  62.88 0 62.904 0.084 ;
    END
  END fast_s2[29]
  PIN fast_s2[2]
    DIRECTION INPUT ;
    USE SIGNAL ;
    PORT
      LAYER M5 ;
        RECT  61.584 0 61.608 0.084 ;
    END
  END fast_s2[2]
  PIN fast_s2[300]
    DIRECTION INPUT ;
    USE SIGNAL ;
    PORT
      LAYER M5 ;
        RECT  85.872 0 85.896 0.084 ;
    END
  END fast_s2[300]
  PIN fast_s2[301]
    DIRECTION INPUT ;
    USE SIGNAL ;
    PORT
      LAYER M5 ;
        RECT  85.92 0 85.944 0.084 ;
    END
  END fast_s2[301]
  PIN fast_s2[302]
    DIRECTION INPUT ;
    USE SIGNAL ;
    PORT
      LAYER M5 ;
        RECT  85.968 0 85.992 0.084 ;
    END
  END fast_s2[302]
  PIN fast_s2[303]
    DIRECTION INPUT ;
    USE SIGNAL ;
    PORT
      LAYER M5 ;
        RECT  86.016 0 86.04 0.084 ;
    END
  END fast_s2[303]
  PIN fast_s2[304]
    DIRECTION INPUT ;
    USE SIGNAL ;
    PORT
      LAYER M5 ;
        RECT  86.064 0 86.088 0.084 ;
    END
  END fast_s2[304]
  PIN fast_s2[305]
    DIRECTION INPUT ;
    USE SIGNAL ;
    PORT
      LAYER M5 ;
        RECT  86.112 0 86.136 0.084 ;
    END
  END fast_s2[305]
  PIN fast_s2[306]
    DIRECTION INPUT ;
    USE SIGNAL ;
    PORT
      LAYER M5 ;
        RECT  86.16 0 86.184 0.084 ;
    END
  END fast_s2[306]
  PIN fast_s2[307]
    DIRECTION INPUT ;
    USE SIGNAL ;
    PORT
      LAYER M5 ;
        RECT  86.208 0 86.232 0.084 ;
    END
  END fast_s2[307]
  PIN fast_s2[308]
    DIRECTION INPUT ;
    USE SIGNAL ;
    PORT
      LAYER M5 ;
        RECT  86.256 0 86.28 0.084 ;
    END
  END fast_s2[308]
  PIN fast_s2[309]
    DIRECTION INPUT ;
    USE SIGNAL ;
    PORT
      LAYER M5 ;
        RECT  86.304 0 86.328 0.084 ;
    END
  END fast_s2[309]
  PIN fast_s2[30]
    DIRECTION INPUT ;
    USE SIGNAL ;
    PORT
      LAYER M5 ;
        RECT  141.264 0 141.288 0.084 ;
    END
  END fast_s2[30]
  PIN fast_s2[310]
    DIRECTION INPUT ;
    USE SIGNAL ;
    PORT
      LAYER M5 ;
        RECT  86.352 0 86.376 0.084 ;
    END
  END fast_s2[310]
  PIN fast_s2[311]
    DIRECTION INPUT ;
    USE SIGNAL ;
    PORT
      LAYER M5 ;
        RECT  86.4 0 86.424 0.084 ;
    END
  END fast_s2[311]
  PIN fast_s2[312]
    DIRECTION INPUT ;
    USE SIGNAL ;
    PORT
      LAYER M5 ;
        RECT  86.448 0 86.472 0.084 ;
    END
  END fast_s2[312]
  PIN fast_s2[313]
    DIRECTION INPUT ;
    USE SIGNAL ;
    PORT
      LAYER M5 ;
        RECT  86.496 0 86.52 0.084 ;
    END
  END fast_s2[313]
  PIN fast_s2[314]
    DIRECTION INPUT ;
    USE SIGNAL ;
    PORT
      LAYER M5 ;
        RECT  86.544 0 86.568 0.084 ;
    END
  END fast_s2[314]
  PIN fast_s2[315]
    DIRECTION INPUT ;
    USE SIGNAL ;
    PORT
      LAYER M5 ;
        RECT  86.592 0 86.616 0.084 ;
    END
  END fast_s2[315]
  PIN fast_s2[316]
    DIRECTION INPUT ;
    USE SIGNAL ;
    PORT
      LAYER M5 ;
        RECT  86.64 0 86.664 0.084 ;
    END
  END fast_s2[316]
  PIN fast_s2[317]
    DIRECTION INPUT ;
    USE SIGNAL ;
    PORT
      LAYER M5 ;
        RECT  86.688 0 86.712 0.084 ;
    END
  END fast_s2[317]
  PIN fast_s2[318]
    DIRECTION INPUT ;
    USE SIGNAL ;
    PORT
      LAYER M5 ;
        RECT  79.056 0 79.08 0.084 ;
    END
  END fast_s2[318]
  PIN fast_s2[319]
    DIRECTION INPUT ;
    USE SIGNAL ;
    PORT
      LAYER M5 ;
        RECT  79.104 0 79.128 0.084 ;
    END
  END fast_s2[319]
  PIN fast_s2[31]
    DIRECTION INPUT ;
    USE SIGNAL ;
    PORT
      LAYER M5 ;
        RECT  141.312 0 141.336 0.084 ;
    END
  END fast_s2[31]
  PIN fast_s2[320]
    DIRECTION INPUT ;
    USE SIGNAL ;
    PORT
      LAYER M5 ;
        RECT  79.152 0 79.176 0.084 ;
    END
  END fast_s2[320]
  PIN fast_s2[321]
    DIRECTION INPUT ;
    USE SIGNAL ;
    PORT
      LAYER M5 ;
        RECT  79.2 0 79.224 0.084 ;
    END
  END fast_s2[321]
  PIN fast_s2[322]
    DIRECTION INPUT ;
    USE SIGNAL ;
    PORT
      LAYER M5 ;
        RECT  79.248 0 79.272 0.084 ;
    END
  END fast_s2[322]
  PIN fast_s2[323]
    DIRECTION INPUT ;
    USE SIGNAL ;
    PORT
      LAYER M5 ;
        RECT  79.296 0 79.32 0.084 ;
    END
  END fast_s2[323]
  PIN fast_s2[324]
    DIRECTION INPUT ;
    USE SIGNAL ;
    PORT
      LAYER M5 ;
        RECT  79.344 0 79.368 0.084 ;
    END
  END fast_s2[324]
  PIN fast_s2[325]
    DIRECTION INPUT ;
    USE SIGNAL ;
    PORT
      LAYER M5 ;
        RECT  79.392 0 79.416 0.084 ;
    END
  END fast_s2[325]
  PIN fast_s2[326]
    DIRECTION INPUT ;
    USE SIGNAL ;
    PORT
      LAYER M5 ;
        RECT  79.44 0 79.464 0.084 ;
    END
  END fast_s2[326]
  PIN fast_s2[327]
    DIRECTION INPUT ;
    USE SIGNAL ;
    PORT
      LAYER M5 ;
        RECT  79.488 0 79.512 0.084 ;
    END
  END fast_s2[327]
  PIN fast_s2[328]
    DIRECTION INPUT ;
    USE SIGNAL ;
    PORT
      LAYER M5 ;
        RECT  79.536 0 79.56 0.084 ;
    END
  END fast_s2[328]
  PIN fast_s2[329]
    DIRECTION INPUT ;
    USE SIGNAL ;
    PORT
      LAYER M5 ;
        RECT  79.584 0 79.608 0.084 ;
    END
  END fast_s2[329]
  PIN fast_s2[32]
    DIRECTION INPUT ;
    USE SIGNAL ;
    PORT
      LAYER M5 ;
        RECT  141.36 0 141.384 0.084 ;
    END
  END fast_s2[32]
  PIN fast_s2[330]
    DIRECTION INPUT ;
    USE SIGNAL ;
    PORT
      LAYER M5 ;
        RECT  79.632 0 79.656 0.084 ;
    END
  END fast_s2[330]
  PIN fast_s2[331]
    DIRECTION INPUT ;
    USE SIGNAL ;
    PORT
      LAYER M5 ;
        RECT  79.68 0 79.704 0.084 ;
    END
  END fast_s2[331]
  PIN fast_s2[332]
    DIRECTION INPUT ;
    USE SIGNAL ;
    PORT
      LAYER M5 ;
        RECT  79.728 0 79.752 0.084 ;
    END
  END fast_s2[332]
  PIN fast_s2[33]
    DIRECTION INPUT ;
    USE SIGNAL ;
    PORT
      LAYER M5 ;
        RECT  141.408 0 141.432 0.084 ;
    END
  END fast_s2[33]
  PIN fast_s2[34]
    DIRECTION INPUT ;
    USE SIGNAL ;
    PORT
      LAYER M5 ;
        RECT  141.456 0 141.48 0.084 ;
    END
  END fast_s2[34]
  PIN fast_s2[35]
    DIRECTION INPUT ;
    USE SIGNAL ;
    PORT
      LAYER M5 ;
        RECT  141.504 0 141.528 0.084 ;
    END
  END fast_s2[35]
  PIN fast_s2[36]
    DIRECTION INPUT ;
    USE SIGNAL ;
    PORT
      LAYER M5 ;
        RECT  141.552 0 141.576 0.084 ;
    END
  END fast_s2[36]
  PIN fast_s2[37]
    DIRECTION INPUT ;
    USE SIGNAL ;
    PORT
      LAYER M5 ;
        RECT  141.6 0 141.624 0.084 ;
    END
  END fast_s2[37]
  PIN fast_s2[38]
    DIRECTION INPUT ;
    USE SIGNAL ;
    PORT
      LAYER M5 ;
        RECT  141.648 0 141.672 0.084 ;
    END
  END fast_s2[38]
  PIN fast_s2[39]
    DIRECTION INPUT ;
    USE SIGNAL ;
    PORT
      LAYER M5 ;
        RECT  141.696 0 141.72 0.084 ;
    END
  END fast_s2[39]
  PIN fast_s2[3]
    DIRECTION INPUT ;
    USE SIGNAL ;
    PORT
      LAYER M5 ;
        RECT  61.632 0 61.656 0.084 ;
    END
  END fast_s2[3]
  PIN fast_s2[40]
    DIRECTION INPUT ;
    USE SIGNAL ;
    PORT
      LAYER M5 ;
        RECT  141.744 0 141.768 0.084 ;
    END
  END fast_s2[40]
  PIN fast_s2[41]
    DIRECTION INPUT ;
    USE SIGNAL ;
    PORT
      LAYER M5 ;
        RECT  141.792 0 141.816 0.084 ;
    END
  END fast_s2[41]
  PIN fast_s2[42]
    DIRECTION INPUT ;
    USE SIGNAL ;
    PORT
      LAYER M5 ;
        RECT  141.84 0 141.864 0.084 ;
    END
  END fast_s2[42]
  PIN fast_s2[43]
    DIRECTION INPUT ;
    USE SIGNAL ;
    PORT
      LAYER M5 ;
        RECT  141.888 0 141.912 0.084 ;
    END
  END fast_s2[43]
  PIN fast_s2[44]
    DIRECTION INPUT ;
    USE SIGNAL ;
    PORT
      LAYER M5 ;
        RECT  141.936 0 141.96 0.084 ;
    END
  END fast_s2[44]
  PIN fast_s2[45]
    DIRECTION INPUT ;
    USE SIGNAL ;
    PORT
      LAYER M5 ;
        RECT  141.984 0 142.008 0.084 ;
    END
  END fast_s2[45]
  PIN fast_s2[46]
    DIRECTION INPUT ;
    USE SIGNAL ;
    PORT
      LAYER M5 ;
        RECT  142.032 0 142.056 0.084 ;
    END
  END fast_s2[46]
  PIN fast_s2[47]
    DIRECTION INPUT ;
    USE SIGNAL ;
    PORT
      LAYER M5 ;
        RECT  142.08 0 142.104 0.084 ;
    END
  END fast_s2[47]
  PIN fast_s2[48]
    DIRECTION INPUT ;
    USE SIGNAL ;
    PORT
      LAYER M5 ;
        RECT  142.128 0 142.152 0.084 ;
    END
  END fast_s2[48]
  PIN fast_s2[49]
    DIRECTION INPUT ;
    USE SIGNAL ;
    PORT
      LAYER M5 ;
        RECT  142.176 0 142.2 0.084 ;
    END
  END fast_s2[49]
  PIN fast_s2[4]
    DIRECTION INPUT ;
    USE SIGNAL ;
    PORT
      LAYER M5 ;
        RECT  61.68 0 61.704 0.084 ;
    END
  END fast_s2[4]
  PIN fast_s2[50]
    DIRECTION INPUT ;
    USE SIGNAL ;
    PORT
      LAYER M5 ;
        RECT  142.224 0 142.248 0.084 ;
    END
  END fast_s2[50]
  PIN fast_s2[51]
    DIRECTION INPUT ;
    USE SIGNAL ;
    PORT
      LAYER M5 ;
        RECT  142.272 0 142.296 0.084 ;
    END
  END fast_s2[51]
  PIN fast_s2[52]
    DIRECTION INPUT ;
    USE SIGNAL ;
    PORT
      LAYER M5 ;
        RECT  142.32 0 142.344 0.084 ;
    END
  END fast_s2[52]
  PIN fast_s2[53]
    DIRECTION INPUT ;
    USE SIGNAL ;
    PORT
      LAYER M5 ;
        RECT  142.368 0 142.392 0.084 ;
    END
  END fast_s2[53]
  PIN fast_s2[54]
    DIRECTION INPUT ;
    USE SIGNAL ;
    PORT
      LAYER M5 ;
        RECT  142.416 0 142.44 0.084 ;
    END
  END fast_s2[54]
  PIN fast_s2[55]
    DIRECTION INPUT ;
    USE SIGNAL ;
    PORT
      LAYER M5 ;
        RECT  142.464 0 142.488 0.084 ;
    END
  END fast_s2[55]
  PIN fast_s2[56]
    DIRECTION INPUT ;
    USE SIGNAL ;
    PORT
      LAYER M5 ;
        RECT  142.512 0 142.536 0.084 ;
    END
  END fast_s2[56]
  PIN fast_s2[57]
    DIRECTION INPUT ;
    USE SIGNAL ;
    PORT
      LAYER M5 ;
        RECT  142.56 0 142.584 0.084 ;
    END
  END fast_s2[57]
  PIN fast_s2[58]
    DIRECTION INPUT ;
    USE SIGNAL ;
    PORT
      LAYER M5 ;
        RECT  142.608 0 142.632 0.084 ;
    END
  END fast_s2[58]
  PIN fast_s2[59]
    DIRECTION INPUT ;
    USE SIGNAL ;
    PORT
      LAYER M5 ;
        RECT  142.656 0 142.68 0.084 ;
    END
  END fast_s2[59]
  PIN fast_s2[5]
    DIRECTION INPUT ;
    USE SIGNAL ;
    PORT
      LAYER M5 ;
        RECT  61.728 0 61.752 0.084 ;
    END
  END fast_s2[5]
  PIN fast_s2[60]
    DIRECTION INPUT ;
    USE SIGNAL ;
    PORT
      LAYER M5 ;
        RECT  142.704 0 142.728 0.084 ;
    END
  END fast_s2[60]
  PIN fast_s2[61]
    DIRECTION INPUT ;
    USE SIGNAL ;
    PORT
      LAYER M5 ;
        RECT  142.752 0 142.776 0.084 ;
    END
  END fast_s2[61]
  PIN fast_s2[62]
    DIRECTION INPUT ;
    USE SIGNAL ;
    PORT
      LAYER M5 ;
        RECT  91.728 0 91.752 0.084 ;
    END
  END fast_s2[62]
  PIN fast_s2[63]
    DIRECTION INPUT ;
    USE SIGNAL ;
    PORT
      LAYER M5 ;
        RECT  91.776 0 91.8 0.084 ;
    END
  END fast_s2[63]
  PIN fast_s2[64]
    DIRECTION INPUT ;
    USE SIGNAL ;
    PORT
      LAYER M5 ;
        RECT  91.824 0 91.848 0.084 ;
    END
  END fast_s2[64]
  PIN fast_s2[65]
    DIRECTION INPUT ;
    USE SIGNAL ;
    PORT
      LAYER M5 ;
        RECT  91.872 0 91.896 0.084 ;
    END
  END fast_s2[65]
  PIN fast_s2[66]
    DIRECTION INPUT ;
    USE SIGNAL ;
    PORT
      LAYER M5 ;
        RECT  91.92 0 91.944 0.084 ;
    END
  END fast_s2[66]
  PIN fast_s2[67]
    DIRECTION INPUT ;
    USE SIGNAL ;
    PORT
      LAYER M5 ;
        RECT  91.968 0 91.992 0.084 ;
    END
  END fast_s2[67]
  PIN fast_s2[68]
    DIRECTION INPUT ;
    USE SIGNAL ;
    PORT
      LAYER M5 ;
        RECT  92.016 0 92.04 0.084 ;
    END
  END fast_s2[68]
  PIN fast_s2[69]
    DIRECTION INPUT ;
    USE SIGNAL ;
    PORT
      LAYER M5 ;
        RECT  92.064 0 92.088 0.084 ;
    END
  END fast_s2[69]
  PIN fast_s2[6]
    DIRECTION INPUT ;
    USE SIGNAL ;
    PORT
      LAYER M5 ;
        RECT  61.776 0 61.8 0.084 ;
    END
  END fast_s2[6]
  PIN fast_s2[70]
    DIRECTION INPUT ;
    USE SIGNAL ;
    PORT
      LAYER M5 ;
        RECT  92.112 0 92.136 0.084 ;
    END
  END fast_s2[70]
  PIN fast_s2[71]
    DIRECTION INPUT ;
    USE SIGNAL ;
    PORT
      LAYER M5 ;
        RECT  92.16 0 92.184 0.084 ;
    END
  END fast_s2[71]
  PIN fast_s2[72]
    DIRECTION INPUT ;
    USE SIGNAL ;
    PORT
      LAYER M5 ;
        RECT  92.208 0 92.232 0.084 ;
    END
  END fast_s2[72]
  PIN fast_s2[73]
    DIRECTION INPUT ;
    USE SIGNAL ;
    PORT
      LAYER M5 ;
        RECT  92.256 0 92.28 0.084 ;
    END
  END fast_s2[73]
  PIN fast_s2[74]
    DIRECTION INPUT ;
    USE SIGNAL ;
    PORT
      LAYER M5 ;
        RECT  92.304 0 92.328 0.084 ;
    END
  END fast_s2[74]
  PIN fast_s2[75]
    DIRECTION INPUT ;
    USE SIGNAL ;
    PORT
      LAYER M5 ;
        RECT  92.352 0 92.376 0.084 ;
    END
  END fast_s2[75]
  PIN fast_s2[76]
    DIRECTION INPUT ;
    USE SIGNAL ;
    PORT
      LAYER M5 ;
        RECT  92.4 0 92.424 0.084 ;
    END
  END fast_s2[76]
  PIN fast_s2[77]
    DIRECTION INPUT ;
    USE SIGNAL ;
    PORT
      LAYER M5 ;
        RECT  92.448 0 92.472 0.084 ;
    END
  END fast_s2[77]
  PIN fast_s2[78]
    DIRECTION INPUT ;
    USE SIGNAL ;
    PORT
      LAYER M5 ;
        RECT  92.496 0 92.52 0.084 ;
    END
  END fast_s2[78]
  PIN fast_s2[79]
    DIRECTION INPUT ;
    USE SIGNAL ;
    PORT
      LAYER M5 ;
        RECT  92.544 0 92.568 0.084 ;
    END
  END fast_s2[79]
  PIN fast_s2[7]
    DIRECTION INPUT ;
    USE SIGNAL ;
    PORT
      LAYER M5 ;
        RECT  61.824 0 61.848 0.084 ;
    END
  END fast_s2[7]
  PIN fast_s2[80]
    DIRECTION INPUT ;
    USE SIGNAL ;
    PORT
      LAYER M5 ;
        RECT  92.592 0 92.616 0.084 ;
    END
  END fast_s2[80]
  PIN fast_s2[81]
    DIRECTION INPUT ;
    USE SIGNAL ;
    PORT
      LAYER M5 ;
        RECT  92.64 0 92.664 0.084 ;
    END
  END fast_s2[81]
  PIN fast_s2[82]
    DIRECTION INPUT ;
    USE SIGNAL ;
    PORT
      LAYER M5 ;
        RECT  92.688 0 92.712 0.084 ;
    END
  END fast_s2[82]
  PIN fast_s2[83]
    DIRECTION INPUT ;
    USE SIGNAL ;
    PORT
      LAYER M5 ;
        RECT  92.736 0 92.76 0.084 ;
    END
  END fast_s2[83]
  PIN fast_s2[84]
    DIRECTION INPUT ;
    USE SIGNAL ;
    PORT
      LAYER M5 ;
        RECT  92.784 0 92.808 0.084 ;
    END
  END fast_s2[84]
  PIN fast_s2[85]
    DIRECTION INPUT ;
    USE SIGNAL ;
    PORT
      LAYER M5 ;
        RECT  92.832 0 92.856 0.084 ;
    END
  END fast_s2[85]
  PIN fast_s2[86]
    DIRECTION INPUT ;
    USE SIGNAL ;
    PORT
      LAYER M5 ;
        RECT  92.88 0 92.904 0.084 ;
    END
  END fast_s2[86]
  PIN fast_s2[87]
    DIRECTION INPUT ;
    USE SIGNAL ;
    PORT
      LAYER M5 ;
        RECT  92.928 0 92.952 0.084 ;
    END
  END fast_s2[87]
  PIN fast_s2[88]
    DIRECTION INPUT ;
    USE SIGNAL ;
    PORT
      LAYER M5 ;
        RECT  92.976 0 93 0.084 ;
    END
  END fast_s2[88]
  PIN fast_s2[89]
    DIRECTION INPUT ;
    USE SIGNAL ;
    PORT
      LAYER M5 ;
        RECT  93.024 0 93.048 0.084 ;
    END
  END fast_s2[89]
  PIN fast_s2[8]
    DIRECTION INPUT ;
    USE SIGNAL ;
    PORT
      LAYER M5 ;
        RECT  61.872 0 61.896 0.084 ;
    END
  END fast_s2[8]
  PIN fast_s2[90]
    DIRECTION INPUT ;
    USE SIGNAL ;
    PORT
      LAYER M5 ;
        RECT  93.072 0 93.096 0.084 ;
    END
  END fast_s2[90]
  PIN fast_s2[91]
    DIRECTION INPUT ;
    USE SIGNAL ;
    PORT
      LAYER M5 ;
        RECT  93.12 0 93.144 0.084 ;
    END
  END fast_s2[91]
  PIN fast_s2[92]
    DIRECTION INPUT ;
    USE SIGNAL ;
    PORT
      LAYER M5 ;
        RECT  93.168 0 93.192 0.084 ;
    END
  END fast_s2[92]
  PIN fast_s2[93]
    DIRECTION INPUT ;
    USE SIGNAL ;
    PORT
      LAYER M5 ;
        RECT  93.216 0 93.24 0.084 ;
    END
  END fast_s2[93]
  PIN fast_s2[94]
    DIRECTION INPUT ;
    USE SIGNAL ;
    PORT
      LAYER M5 ;
        RECT  93.264 0 93.288 0.084 ;
    END
  END fast_s2[94]
  PIN fast_s2[95]
    DIRECTION INPUT ;
    USE SIGNAL ;
    PORT
      LAYER M5 ;
        RECT  93.312 0 93.336 0.084 ;
    END
  END fast_s2[95]
  PIN fast_s2[96]
    DIRECTION INPUT ;
    USE SIGNAL ;
    PORT
      LAYER M5 ;
        RECT  93.36 0 93.384 0.084 ;
    END
  END fast_s2[96]
  PIN fast_s2[97]
    DIRECTION INPUT ;
    USE SIGNAL ;
    PORT
      LAYER M5 ;
        RECT  93.408 0 93.432 0.084 ;
    END
  END fast_s2[97]
  PIN fast_s2[98]
    DIRECTION INPUT ;
    USE SIGNAL ;
    PORT
      LAYER M5 ;
        RECT  93.456 0 93.48 0.084 ;
    END
  END fast_s2[98]
  PIN fast_s2[99]
    DIRECTION INPUT ;
    USE SIGNAL ;
    PORT
      LAYER M5 ;
        RECT  93.504 0 93.528 0.084 ;
    END
  END fast_s2[99]
  PIN fast_s2[9]
    DIRECTION INPUT ;
    USE SIGNAL ;
    PORT
      LAYER M5 ;
        RECT  61.92 0 61.944 0.084 ;
    END
  END fast_s2[9]
  PIN fast_v
    DIRECTION INPUT ;
    USE SIGNAL ;
    PORT
      LAYER M5 ;
        RECT  79.776 0 79.8 0.084 ;
    END
  END fast_v
  PIN general_s3[0]
    DIRECTION INPUT ;
    USE SIGNAL ;
    PORT
      LAYER M4 ;
        RECT  0 69.648 0.084 69.672 ;
    END
  END general_s3[0]
  PIN general_s3[100]
    DIRECTION INPUT ;
    USE SIGNAL ;
    PORT
      LAYER M4 ;
        RECT  0 46.032 0.084 46.056 ;
    END
  END general_s3[100]
  PIN general_s3[101]
    DIRECTION INPUT ;
    USE SIGNAL ;
    PORT
      LAYER M4 ;
        RECT  0 46.08 0.084 46.104 ;
    END
  END general_s3[101]
  PIN general_s3[102]
    DIRECTION INPUT ;
    USE SIGNAL ;
    PORT
      LAYER M4 ;
        RECT  0 46.128 0.084 46.152 ;
    END
  END general_s3[102]
  PIN general_s3[103]
    DIRECTION INPUT ;
    USE SIGNAL ;
    PORT
      LAYER M4 ;
        RECT  0 46.176 0.084 46.2 ;
    END
  END general_s3[103]
  PIN general_s3[104]
    DIRECTION INPUT ;
    USE SIGNAL ;
    PORT
      LAYER M4 ;
        RECT  0 46.224 0.084 46.248 ;
    END
  END general_s3[104]
  PIN general_s3[105]
    DIRECTION INPUT ;
    USE SIGNAL ;
    PORT
      LAYER M4 ;
        RECT  0 46.272 0.084 46.296 ;
    END
  END general_s3[105]
  PIN general_s3[106]
    DIRECTION INPUT ;
    USE SIGNAL ;
    PORT
      LAYER M4 ;
        RECT  0 46.32 0.084 46.344 ;
    END
  END general_s3[106]
  PIN general_s3[107]
    DIRECTION INPUT ;
    USE SIGNAL ;
    PORT
      LAYER M4 ;
        RECT  0 46.368 0.084 46.392 ;
    END
  END general_s3[107]
  PIN general_s3[108]
    DIRECTION INPUT ;
    USE SIGNAL ;
    PORT
      LAYER M4 ;
        RECT  0 46.416 0.084 46.44 ;
    END
  END general_s3[108]
  PIN general_s3[109]
    DIRECTION INPUT ;
    USE SIGNAL ;
    PORT
      LAYER M4 ;
        RECT  0 46.464 0.084 46.488 ;
    END
  END general_s3[109]
  PIN general_s3[10]
    DIRECTION INPUT ;
    USE SIGNAL ;
    PORT
      LAYER M4 ;
        RECT  0 70.128 0.084 70.152 ;
    END
  END general_s3[10]
  PIN general_s3[110]
    DIRECTION INPUT ;
    USE SIGNAL ;
    PORT
      LAYER M4 ;
        RECT  0 46.512 0.084 46.536 ;
    END
  END general_s3[110]
  PIN general_s3[111]
    DIRECTION INPUT ;
    USE SIGNAL ;
    PORT
      LAYER M4 ;
        RECT  0 46.56 0.084 46.584 ;
    END
  END general_s3[111]
  PIN general_s3[112]
    DIRECTION INPUT ;
    USE SIGNAL ;
    PORT
      LAYER M4 ;
        RECT  0 46.608 0.084 46.632 ;
    END
  END general_s3[112]
  PIN general_s3[113]
    DIRECTION INPUT ;
    USE SIGNAL ;
    PORT
      LAYER M4 ;
        RECT  0 46.656 0.084 46.68 ;
    END
  END general_s3[113]
  PIN general_s3[114]
    DIRECTION INPUT ;
    USE SIGNAL ;
    PORT
      LAYER M4 ;
        RECT  0 46.704 0.084 46.728 ;
    END
  END general_s3[114]
  PIN general_s3[115]
    DIRECTION INPUT ;
    USE SIGNAL ;
    PORT
      LAYER M4 ;
        RECT  0 46.752 0.084 46.776 ;
    END
  END general_s3[115]
  PIN general_s3[116]
    DIRECTION INPUT ;
    USE SIGNAL ;
    PORT
      LAYER M4 ;
        RECT  0 46.8 0.084 46.824 ;
    END
  END general_s3[116]
  PIN general_s3[117]
    DIRECTION INPUT ;
    USE SIGNAL ;
    PORT
      LAYER M4 ;
        RECT  0 46.848 0.084 46.872 ;
    END
  END general_s3[117]
  PIN general_s3[118]
    DIRECTION INPUT ;
    USE SIGNAL ;
    PORT
      LAYER M4 ;
        RECT  0 46.896 0.084 46.92 ;
    END
  END general_s3[118]
  PIN general_s3[119]
    DIRECTION INPUT ;
    USE SIGNAL ;
    PORT
      LAYER M4 ;
        RECT  0 46.944 0.084 46.968 ;
    END
  END general_s3[119]
  PIN general_s3[11]
    DIRECTION INPUT ;
    USE SIGNAL ;
    PORT
      LAYER M4 ;
        RECT  0 70.176 0.084 70.2 ;
    END
  END general_s3[11]
  PIN general_s3[120]
    DIRECTION INPUT ;
    USE SIGNAL ;
    PORT
      LAYER M4 ;
        RECT  0 46.992 0.084 47.016 ;
    END
  END general_s3[120]
  PIN general_s3[121]
    DIRECTION INPUT ;
    USE SIGNAL ;
    PORT
      LAYER M4 ;
        RECT  0 47.04 0.084 47.064 ;
    END
  END general_s3[121]
  PIN general_s3[122]
    DIRECTION INPUT ;
    USE SIGNAL ;
    PORT
      LAYER M4 ;
        RECT  0 47.088 0.084 47.112 ;
    END
  END general_s3[122]
  PIN general_s3[123]
    DIRECTION INPUT ;
    USE SIGNAL ;
    PORT
      LAYER M4 ;
        RECT  0 47.136 0.084 47.16 ;
    END
  END general_s3[123]
  PIN general_s3[124]
    DIRECTION INPUT ;
    USE SIGNAL ;
    PORT
      LAYER M4 ;
        RECT  0 47.184 0.084 47.208 ;
    END
  END general_s3[124]
  PIN general_s3[125]
    DIRECTION INPUT ;
    USE SIGNAL ;
    PORT
      LAYER M4 ;
        RECT  0 47.232 0.084 47.256 ;
    END
  END general_s3[125]
  PIN general_s3[126]
    DIRECTION INPUT ;
    USE SIGNAL ;
    PORT
      LAYER M4 ;
        RECT  0 31.152 0.084 31.176 ;
    END
  END general_s3[126]
  PIN general_s3[127]
    DIRECTION INPUT ;
    USE SIGNAL ;
    PORT
      LAYER M4 ;
        RECT  0 31.2 0.084 31.224 ;
    END
  END general_s3[127]
  PIN general_s3[128]
    DIRECTION INPUT ;
    USE SIGNAL ;
    PORT
      LAYER M4 ;
        RECT  0 31.248 0.084 31.272 ;
    END
  END general_s3[128]
  PIN general_s3[129]
    DIRECTION INPUT ;
    USE SIGNAL ;
    PORT
      LAYER M4 ;
        RECT  0 31.296 0.084 31.32 ;
    END
  END general_s3[129]
  PIN general_s3[12]
    DIRECTION INPUT ;
    USE SIGNAL ;
    PORT
      LAYER M4 ;
        RECT  0 70.224 0.084 70.248 ;
    END
  END general_s3[12]
  PIN general_s3[130]
    DIRECTION INPUT ;
    USE SIGNAL ;
    PORT
      LAYER M4 ;
        RECT  0 31.344 0.084 31.368 ;
    END
  END general_s3[130]
  PIN general_s3[131]
    DIRECTION INPUT ;
    USE SIGNAL ;
    PORT
      LAYER M4 ;
        RECT  0 31.392 0.084 31.416 ;
    END
  END general_s3[131]
  PIN general_s3[132]
    DIRECTION INPUT ;
    USE SIGNAL ;
    PORT
      LAYER M4 ;
        RECT  0 31.44 0.084 31.464 ;
    END
  END general_s3[132]
  PIN general_s3[133]
    DIRECTION INPUT ;
    USE SIGNAL ;
    PORT
      LAYER M4 ;
        RECT  0 31.488 0.084 31.512 ;
    END
  END general_s3[133]
  PIN general_s3[134]
    DIRECTION INPUT ;
    USE SIGNAL ;
    PORT
      LAYER M4 ;
        RECT  0 31.536 0.084 31.56 ;
    END
  END general_s3[134]
  PIN general_s3[135]
    DIRECTION INPUT ;
    USE SIGNAL ;
    PORT
      LAYER M4 ;
        RECT  0 31.584 0.084 31.608 ;
    END
  END general_s3[135]
  PIN general_s3[136]
    DIRECTION INPUT ;
    USE SIGNAL ;
    PORT
      LAYER M4 ;
        RECT  0 31.632 0.084 31.656 ;
    END
  END general_s3[136]
  PIN general_s3[137]
    DIRECTION INPUT ;
    USE SIGNAL ;
    PORT
      LAYER M4 ;
        RECT  0 31.68 0.084 31.704 ;
    END
  END general_s3[137]
  PIN general_s3[138]
    DIRECTION INPUT ;
    USE SIGNAL ;
    PORT
      LAYER M4 ;
        RECT  0 31.728 0.084 31.752 ;
    END
  END general_s3[138]
  PIN general_s3[139]
    DIRECTION INPUT ;
    USE SIGNAL ;
    PORT
      LAYER M4 ;
        RECT  0 31.776 0.084 31.8 ;
    END
  END general_s3[139]
  PIN general_s3[13]
    DIRECTION INPUT ;
    USE SIGNAL ;
    PORT
      LAYER M4 ;
        RECT  0 70.272 0.084 70.296 ;
    END
  END general_s3[13]
  PIN general_s3[140]
    DIRECTION INPUT ;
    USE SIGNAL ;
    PORT
      LAYER M4 ;
        RECT  0 31.824 0.084 31.848 ;
    END
  END general_s3[140]
  PIN general_s3[141]
    DIRECTION INPUT ;
    USE SIGNAL ;
    PORT
      LAYER M4 ;
        RECT  0 31.872 0.084 31.896 ;
    END
  END general_s3[141]
  PIN general_s3[142]
    DIRECTION INPUT ;
    USE SIGNAL ;
    PORT
      LAYER M4 ;
        RECT  0 31.92 0.084 31.944 ;
    END
  END general_s3[142]
  PIN general_s3[143]
    DIRECTION INPUT ;
    USE SIGNAL ;
    PORT
      LAYER M4 ;
        RECT  0 31.968 0.084 31.992 ;
    END
  END general_s3[143]
  PIN general_s3[144]
    DIRECTION INPUT ;
    USE SIGNAL ;
    PORT
      LAYER M4 ;
        RECT  0 32.016 0.084 32.04 ;
    END
  END general_s3[144]
  PIN general_s3[145]
    DIRECTION INPUT ;
    USE SIGNAL ;
    PORT
      LAYER M4 ;
        RECT  0 32.064 0.084 32.088 ;
    END
  END general_s3[145]
  PIN general_s3[146]
    DIRECTION INPUT ;
    USE SIGNAL ;
    PORT
      LAYER M4 ;
        RECT  0 32.112 0.084 32.136 ;
    END
  END general_s3[146]
  PIN general_s3[147]
    DIRECTION INPUT ;
    USE SIGNAL ;
    PORT
      LAYER M4 ;
        RECT  0 32.16 0.084 32.184 ;
    END
  END general_s3[147]
  PIN general_s3[148]
    DIRECTION INPUT ;
    USE SIGNAL ;
    PORT
      LAYER M4 ;
        RECT  0 32.208 0.084 32.232 ;
    END
  END general_s3[148]
  PIN general_s3[149]
    DIRECTION INPUT ;
    USE SIGNAL ;
    PORT
      LAYER M4 ;
        RECT  0 32.256 0.084 32.28 ;
    END
  END general_s3[149]
  PIN general_s3[14]
    DIRECTION INPUT ;
    USE SIGNAL ;
    PORT
      LAYER M4 ;
        RECT  0 70.32 0.084 70.344 ;
    END
  END general_s3[14]
  PIN general_s3[150]
    DIRECTION INPUT ;
    USE SIGNAL ;
    PORT
      LAYER M4 ;
        RECT  0 32.304 0.084 32.328 ;
    END
  END general_s3[150]
  PIN general_s3[151]
    DIRECTION INPUT ;
    USE SIGNAL ;
    PORT
      LAYER M4 ;
        RECT  0 32.352 0.084 32.376 ;
    END
  END general_s3[151]
  PIN general_s3[152]
    DIRECTION INPUT ;
    USE SIGNAL ;
    PORT
      LAYER M4 ;
        RECT  0 32.4 0.084 32.424 ;
    END
  END general_s3[152]
  PIN general_s3[153]
    DIRECTION INPUT ;
    USE SIGNAL ;
    PORT
      LAYER M4 ;
        RECT  0 32.448 0.084 32.472 ;
    END
  END general_s3[153]
  PIN general_s3[154]
    DIRECTION INPUT ;
    USE SIGNAL ;
    PORT
      LAYER M4 ;
        RECT  0 32.496 0.084 32.52 ;
    END
  END general_s3[154]
  PIN general_s3[155]
    DIRECTION INPUT ;
    USE SIGNAL ;
    PORT
      LAYER M4 ;
        RECT  0 32.544 0.084 32.568 ;
    END
  END general_s3[155]
  PIN general_s3[156]
    DIRECTION INPUT ;
    USE SIGNAL ;
    PORT
      LAYER M4 ;
        RECT  0 32.592 0.084 32.616 ;
    END
  END general_s3[156]
  PIN general_s3[157]
    DIRECTION INPUT ;
    USE SIGNAL ;
    PORT
      LAYER M4 ;
        RECT  0 32.64 0.084 32.664 ;
    END
  END general_s3[157]
  PIN general_s3[158]
    DIRECTION INPUT ;
    USE SIGNAL ;
    PORT
      LAYER M4 ;
        RECT  0 40.752 0.084 40.776 ;
    END
  END general_s3[158]
  PIN general_s3[159]
    DIRECTION INPUT ;
    USE SIGNAL ;
    PORT
      LAYER M4 ;
        RECT  0 40.8 0.084 40.824 ;
    END
  END general_s3[159]
  PIN general_s3[15]
    DIRECTION INPUT ;
    USE SIGNAL ;
    PORT
      LAYER M4 ;
        RECT  0 70.368 0.084 70.392 ;
    END
  END general_s3[15]
  PIN general_s3[160]
    DIRECTION INPUT ;
    USE SIGNAL ;
    PORT
      LAYER M4 ;
        RECT  0 40.848 0.084 40.872 ;
    END
  END general_s3[160]
  PIN general_s3[161]
    DIRECTION INPUT ;
    USE SIGNAL ;
    PORT
      LAYER M4 ;
        RECT  0 40.896 0.084 40.92 ;
    END
  END general_s3[161]
  PIN general_s3[162]
    DIRECTION INPUT ;
    USE SIGNAL ;
    PORT
      LAYER M4 ;
        RECT  0 40.944 0.084 40.968 ;
    END
  END general_s3[162]
  PIN general_s3[163]
    DIRECTION INPUT ;
    USE SIGNAL ;
    PORT
      LAYER M4 ;
        RECT  0 40.992 0.084 41.016 ;
    END
  END general_s3[163]
  PIN general_s3[164]
    DIRECTION INPUT ;
    USE SIGNAL ;
    PORT
      LAYER M4 ;
        RECT  0 41.04 0.084 41.064 ;
    END
  END general_s3[164]
  PIN general_s3[165]
    DIRECTION INPUT ;
    USE SIGNAL ;
    PORT
      LAYER M4 ;
        RECT  0 41.088 0.084 41.112 ;
    END
  END general_s3[165]
  PIN general_s3[166]
    DIRECTION INPUT ;
    USE SIGNAL ;
    PORT
      LAYER M4 ;
        RECT  0 41.136 0.084 41.16 ;
    END
  END general_s3[166]
  PIN general_s3[167]
    DIRECTION INPUT ;
    USE SIGNAL ;
    PORT
      LAYER M4 ;
        RECT  0 41.184 0.084 41.208 ;
    END
  END general_s3[167]
  PIN general_s3[168]
    DIRECTION INPUT ;
    USE SIGNAL ;
    PORT
      LAYER M4 ;
        RECT  0 41.232 0.084 41.256 ;
    END
  END general_s3[168]
  PIN general_s3[169]
    DIRECTION INPUT ;
    USE SIGNAL ;
    PORT
      LAYER M4 ;
        RECT  0 41.28 0.084 41.304 ;
    END
  END general_s3[169]
  PIN general_s3[16]
    DIRECTION INPUT ;
    USE SIGNAL ;
    PORT
      LAYER M4 ;
        RECT  0 70.416 0.084 70.44 ;
    END
  END general_s3[16]
  PIN general_s3[170]
    DIRECTION INPUT ;
    USE SIGNAL ;
    PORT
      LAYER M4 ;
        RECT  0 41.328 0.084 41.352 ;
    END
  END general_s3[170]
  PIN general_s3[171]
    DIRECTION INPUT ;
    USE SIGNAL ;
    PORT
      LAYER M4 ;
        RECT  0 41.376 0.084 41.4 ;
    END
  END general_s3[171]
  PIN general_s3[172]
    DIRECTION INPUT ;
    USE SIGNAL ;
    PORT
      LAYER M4 ;
        RECT  0 41.424 0.084 41.448 ;
    END
  END general_s3[172]
  PIN general_s3[173]
    DIRECTION INPUT ;
    USE SIGNAL ;
    PORT
      LAYER M4 ;
        RECT  0 41.472 0.084 41.496 ;
    END
  END general_s3[173]
  PIN general_s3[174]
    DIRECTION INPUT ;
    USE SIGNAL ;
    PORT
      LAYER M4 ;
        RECT  0 41.52 0.084 41.544 ;
    END
  END general_s3[174]
  PIN general_s3[175]
    DIRECTION INPUT ;
    USE SIGNAL ;
    PORT
      LAYER M4 ;
        RECT  0 41.568 0.084 41.592 ;
    END
  END general_s3[175]
  PIN general_s3[176]
    DIRECTION INPUT ;
    USE SIGNAL ;
    PORT
      LAYER M4 ;
        RECT  0 41.616 0.084 41.64 ;
    END
  END general_s3[176]
  PIN general_s3[177]
    DIRECTION INPUT ;
    USE SIGNAL ;
    PORT
      LAYER M4 ;
        RECT  0 41.664 0.084 41.688 ;
    END
  END general_s3[177]
  PIN general_s3[178]
    DIRECTION INPUT ;
    USE SIGNAL ;
    PORT
      LAYER M4 ;
        RECT  0 41.712 0.084 41.736 ;
    END
  END general_s3[178]
  PIN general_s3[179]
    DIRECTION INPUT ;
    USE SIGNAL ;
    PORT
      LAYER M4 ;
        RECT  0 41.76 0.084 41.784 ;
    END
  END general_s3[179]
  PIN general_s3[17]
    DIRECTION INPUT ;
    USE SIGNAL ;
    PORT
      LAYER M4 ;
        RECT  0 70.464 0.084 70.488 ;
    END
  END general_s3[17]
  PIN general_s3[180]
    DIRECTION INPUT ;
    USE SIGNAL ;
    PORT
      LAYER M4 ;
        RECT  0 41.808 0.084 41.832 ;
    END
  END general_s3[180]
  PIN general_s3[181]
    DIRECTION INPUT ;
    USE SIGNAL ;
    PORT
      LAYER M4 ;
        RECT  0 41.856 0.084 41.88 ;
    END
  END general_s3[181]
  PIN general_s3[182]
    DIRECTION INPUT ;
    USE SIGNAL ;
    PORT
      LAYER M4 ;
        RECT  0 41.904 0.084 41.928 ;
    END
  END general_s3[182]
  PIN general_s3[183]
    DIRECTION INPUT ;
    USE SIGNAL ;
    PORT
      LAYER M4 ;
        RECT  0 41.952 0.084 41.976 ;
    END
  END general_s3[183]
  PIN general_s3[184]
    DIRECTION INPUT ;
    USE SIGNAL ;
    PORT
      LAYER M4 ;
        RECT  0 42 0.084 42.024 ;
    END
  END general_s3[184]
  PIN general_s3[185]
    DIRECTION INPUT ;
    USE SIGNAL ;
    PORT
      LAYER M4 ;
        RECT  0 42.048 0.084 42.072 ;
    END
  END general_s3[185]
  PIN general_s3[186]
    DIRECTION INPUT ;
    USE SIGNAL ;
    PORT
      LAYER M4 ;
        RECT  0 42.096 0.084 42.12 ;
    END
  END general_s3[186]
  PIN general_s3[187]
    DIRECTION INPUT ;
    USE SIGNAL ;
    PORT
      LAYER M4 ;
        RECT  0 42.144 0.084 42.168 ;
    END
  END general_s3[187]
  PIN general_s3[188]
    DIRECTION INPUT ;
    USE SIGNAL ;
    PORT
      LAYER M4 ;
        RECT  0 42.192 0.084 42.216 ;
    END
  END general_s3[188]
  PIN general_s3[189]
    DIRECTION INPUT ;
    USE SIGNAL ;
    PORT
      LAYER M4 ;
        RECT  0 42.24 0.084 42.264 ;
    END
  END general_s3[189]
  PIN general_s3[18]
    DIRECTION INPUT ;
    USE SIGNAL ;
    PORT
      LAYER M4 ;
        RECT  0 70.512 0.084 70.536 ;
    END
  END general_s3[18]
  PIN general_s3[19]
    DIRECTION INPUT ;
    USE SIGNAL ;
    PORT
      LAYER M4 ;
        RECT  0 70.56 0.084 70.584 ;
    END
  END general_s3[19]
  PIN general_s3[1]
    DIRECTION INPUT ;
    USE SIGNAL ;
    PORT
      LAYER M4 ;
        RECT  0 69.696 0.084 69.72 ;
    END
  END general_s3[1]
  PIN general_s3[20]
    DIRECTION INPUT ;
    USE SIGNAL ;
    PORT
      LAYER M4 ;
        RECT  0 70.608 0.084 70.632 ;
    END
  END general_s3[20]
  PIN general_s3[21]
    DIRECTION INPUT ;
    USE SIGNAL ;
    PORT
      LAYER M4 ;
        RECT  0 70.656 0.084 70.68 ;
    END
  END general_s3[21]
  PIN general_s3[22]
    DIRECTION INPUT ;
    USE SIGNAL ;
    PORT
      LAYER M4 ;
        RECT  0 70.704 0.084 70.728 ;
    END
  END general_s3[22]
  PIN general_s3[23]
    DIRECTION INPUT ;
    USE SIGNAL ;
    PORT
      LAYER M4 ;
        RECT  0 70.752 0.084 70.776 ;
    END
  END general_s3[23]
  PIN general_s3[24]
    DIRECTION INPUT ;
    USE SIGNAL ;
    PORT
      LAYER M4 ;
        RECT  0 70.8 0.084 70.824 ;
    END
  END general_s3[24]
  PIN general_s3[25]
    DIRECTION INPUT ;
    USE SIGNAL ;
    PORT
      LAYER M4 ;
        RECT  0 70.848 0.084 70.872 ;
    END
  END general_s3[25]
  PIN general_s3[26]
    DIRECTION INPUT ;
    USE SIGNAL ;
    PORT
      LAYER M4 ;
        RECT  0 70.896 0.084 70.92 ;
    END
  END general_s3[26]
  PIN general_s3[27]
    DIRECTION INPUT ;
    USE SIGNAL ;
    PORT
      LAYER M4 ;
        RECT  0 70.944 0.084 70.968 ;
    END
  END general_s3[27]
  PIN general_s3[28]
    DIRECTION INPUT ;
    USE SIGNAL ;
    PORT
      LAYER M4 ;
        RECT  0 70.992 0.084 71.016 ;
    END
  END general_s3[28]
  PIN general_s3[29]
    DIRECTION INPUT ;
    USE SIGNAL ;
    PORT
      LAYER M4 ;
        RECT  0 71.04 0.084 71.064 ;
    END
  END general_s3[29]
  PIN general_s3[2]
    DIRECTION INPUT ;
    USE SIGNAL ;
    PORT
      LAYER M4 ;
        RECT  0 69.744 0.084 69.768 ;
    END
  END general_s3[2]
  PIN general_s3[30]
    DIRECTION INPUT ;
    USE SIGNAL ;
    PORT
      LAYER M4 ;
        RECT  0 58.416 0.084 58.44 ;
    END
  END general_s3[30]
  PIN general_s3[31]
    DIRECTION INPUT ;
    USE SIGNAL ;
    PORT
      LAYER M4 ;
        RECT  0 58.464 0.084 58.488 ;
    END
  END general_s3[31]
  PIN general_s3[32]
    DIRECTION INPUT ;
    USE SIGNAL ;
    PORT
      LAYER M4 ;
        RECT  0 58.512 0.084 58.536 ;
    END
  END general_s3[32]
  PIN general_s3[33]
    DIRECTION INPUT ;
    USE SIGNAL ;
    PORT
      LAYER M4 ;
        RECT  0 58.56 0.084 58.584 ;
    END
  END general_s3[33]
  PIN general_s3[34]
    DIRECTION INPUT ;
    USE SIGNAL ;
    PORT
      LAYER M4 ;
        RECT  0 58.608 0.084 58.632 ;
    END
  END general_s3[34]
  PIN general_s3[35]
    DIRECTION INPUT ;
    USE SIGNAL ;
    PORT
      LAYER M4 ;
        RECT  0 58.656 0.084 58.68 ;
    END
  END general_s3[35]
  PIN general_s3[36]
    DIRECTION INPUT ;
    USE SIGNAL ;
    PORT
      LAYER M4 ;
        RECT  0 58.704 0.084 58.728 ;
    END
  END general_s3[36]
  PIN general_s3[37]
    DIRECTION INPUT ;
    USE SIGNAL ;
    PORT
      LAYER M4 ;
        RECT  0 58.752 0.084 58.776 ;
    END
  END general_s3[37]
  PIN general_s3[38]
    DIRECTION INPUT ;
    USE SIGNAL ;
    PORT
      LAYER M4 ;
        RECT  0 58.8 0.084 58.824 ;
    END
  END general_s3[38]
  PIN general_s3[39]
    DIRECTION INPUT ;
    USE SIGNAL ;
    PORT
      LAYER M4 ;
        RECT  0 58.848 0.084 58.872 ;
    END
  END general_s3[39]
  PIN general_s3[3]
    DIRECTION INPUT ;
    USE SIGNAL ;
    PORT
      LAYER M4 ;
        RECT  0 69.792 0.084 69.816 ;
    END
  END general_s3[3]
  PIN general_s3[40]
    DIRECTION INPUT ;
    USE SIGNAL ;
    PORT
      LAYER M4 ;
        RECT  0 58.896 0.084 58.92 ;
    END
  END general_s3[40]
  PIN general_s3[41]
    DIRECTION INPUT ;
    USE SIGNAL ;
    PORT
      LAYER M4 ;
        RECT  0 58.944 0.084 58.968 ;
    END
  END general_s3[41]
  PIN general_s3[42]
    DIRECTION INPUT ;
    USE SIGNAL ;
    PORT
      LAYER M4 ;
        RECT  0 58.992 0.084 59.016 ;
    END
  END general_s3[42]
  PIN general_s3[43]
    DIRECTION INPUT ;
    USE SIGNAL ;
    PORT
      LAYER M4 ;
        RECT  0 59.04 0.084 59.064 ;
    END
  END general_s3[43]
  PIN general_s3[44]
    DIRECTION INPUT ;
    USE SIGNAL ;
    PORT
      LAYER M4 ;
        RECT  0 59.088 0.084 59.112 ;
    END
  END general_s3[44]
  PIN general_s3[45]
    DIRECTION INPUT ;
    USE SIGNAL ;
    PORT
      LAYER M4 ;
        RECT  0 59.136 0.084 59.16 ;
    END
  END general_s3[45]
  PIN general_s3[46]
    DIRECTION INPUT ;
    USE SIGNAL ;
    PORT
      LAYER M4 ;
        RECT  0 59.184 0.084 59.208 ;
    END
  END general_s3[46]
  PIN general_s3[47]
    DIRECTION INPUT ;
    USE SIGNAL ;
    PORT
      LAYER M4 ;
        RECT  0 59.232 0.084 59.256 ;
    END
  END general_s3[47]
  PIN general_s3[48]
    DIRECTION INPUT ;
    USE SIGNAL ;
    PORT
      LAYER M4 ;
        RECT  0 59.28 0.084 59.304 ;
    END
  END general_s3[48]
  PIN general_s3[49]
    DIRECTION INPUT ;
    USE SIGNAL ;
    PORT
      LAYER M4 ;
        RECT  0 59.328 0.084 59.352 ;
    END
  END general_s3[49]
  PIN general_s3[4]
    DIRECTION INPUT ;
    USE SIGNAL ;
    PORT
      LAYER M4 ;
        RECT  0 69.84 0.084 69.864 ;
    END
  END general_s3[4]
  PIN general_s3[50]
    DIRECTION INPUT ;
    USE SIGNAL ;
    PORT
      LAYER M4 ;
        RECT  0 59.376 0.084 59.4 ;
    END
  END general_s3[50]
  PIN general_s3[51]
    DIRECTION INPUT ;
    USE SIGNAL ;
    PORT
      LAYER M4 ;
        RECT  0 59.424 0.084 59.448 ;
    END
  END general_s3[51]
  PIN general_s3[52]
    DIRECTION INPUT ;
    USE SIGNAL ;
    PORT
      LAYER M4 ;
        RECT  0 59.472 0.084 59.496 ;
    END
  END general_s3[52]
  PIN general_s3[53]
    DIRECTION INPUT ;
    USE SIGNAL ;
    PORT
      LAYER M4 ;
        RECT  0 59.52 0.084 59.544 ;
    END
  END general_s3[53]
  PIN general_s3[54]
    DIRECTION INPUT ;
    USE SIGNAL ;
    PORT
      LAYER M4 ;
        RECT  0 59.568 0.084 59.592 ;
    END
  END general_s3[54]
  PIN general_s3[55]
    DIRECTION INPUT ;
    USE SIGNAL ;
    PORT
      LAYER M4 ;
        RECT  0 59.616 0.084 59.64 ;
    END
  END general_s3[55]
  PIN general_s3[56]
    DIRECTION INPUT ;
    USE SIGNAL ;
    PORT
      LAYER M4 ;
        RECT  0 59.664 0.084 59.688 ;
    END
  END general_s3[56]
  PIN general_s3[57]
    DIRECTION INPUT ;
    USE SIGNAL ;
    PORT
      LAYER M4 ;
        RECT  0 59.712 0.084 59.736 ;
    END
  END general_s3[57]
  PIN general_s3[58]
    DIRECTION INPUT ;
    USE SIGNAL ;
    PORT
      LAYER M4 ;
        RECT  0 59.76 0.084 59.784 ;
    END
  END general_s3[58]
  PIN general_s3[59]
    DIRECTION INPUT ;
    USE SIGNAL ;
    PORT
      LAYER M4 ;
        RECT  0 59.808 0.084 59.832 ;
    END
  END general_s3[59]
  PIN general_s3[5]
    DIRECTION INPUT ;
    USE SIGNAL ;
    PORT
      LAYER M4 ;
        RECT  0 69.888 0.084 69.912 ;
    END
  END general_s3[5]
  PIN general_s3[60]
    DIRECTION INPUT ;
    USE SIGNAL ;
    PORT
      LAYER M4 ;
        RECT  0 59.856 0.084 59.88 ;
    END
  END general_s3[60]
  PIN general_s3[61]
    DIRECTION INPUT ;
    USE SIGNAL ;
    PORT
      LAYER M4 ;
        RECT  0 59.904 0.084 59.928 ;
    END
  END general_s3[61]
  PIN general_s3[62]
    DIRECTION INPUT ;
    USE SIGNAL ;
    PORT
      LAYER M4 ;
        RECT  0 56.88 0.084 56.904 ;
    END
  END general_s3[62]
  PIN general_s3[63]
    DIRECTION INPUT ;
    USE SIGNAL ;
    PORT
      LAYER M4 ;
        RECT  0 56.928 0.084 56.952 ;
    END
  END general_s3[63]
  PIN general_s3[64]
    DIRECTION INPUT ;
    USE SIGNAL ;
    PORT
      LAYER M4 ;
        RECT  0 56.976 0.084 57 ;
    END
  END general_s3[64]
  PIN general_s3[65]
    DIRECTION INPUT ;
    USE SIGNAL ;
    PORT
      LAYER M4 ;
        RECT  0 57.024 0.084 57.048 ;
    END
  END general_s3[65]
  PIN general_s3[66]
    DIRECTION INPUT ;
    USE SIGNAL ;
    PORT
      LAYER M4 ;
        RECT  0 57.072 0.084 57.096 ;
    END
  END general_s3[66]
  PIN general_s3[67]
    DIRECTION INPUT ;
    USE SIGNAL ;
    PORT
      LAYER M4 ;
        RECT  0 57.12 0.084 57.144 ;
    END
  END general_s3[67]
  PIN general_s3[68]
    DIRECTION INPUT ;
    USE SIGNAL ;
    PORT
      LAYER M4 ;
        RECT  0 57.168 0.084 57.192 ;
    END
  END general_s3[68]
  PIN general_s3[69]
    DIRECTION INPUT ;
    USE SIGNAL ;
    PORT
      LAYER M4 ;
        RECT  0 57.216 0.084 57.24 ;
    END
  END general_s3[69]
  PIN general_s3[6]
    DIRECTION INPUT ;
    USE SIGNAL ;
    PORT
      LAYER M4 ;
        RECT  0 69.936 0.084 69.96 ;
    END
  END general_s3[6]
  PIN general_s3[70]
    DIRECTION INPUT ;
    USE SIGNAL ;
    PORT
      LAYER M4 ;
        RECT  0 57.264 0.084 57.288 ;
    END
  END general_s3[70]
  PIN general_s3[71]
    DIRECTION INPUT ;
    USE SIGNAL ;
    PORT
      LAYER M4 ;
        RECT  0 57.312 0.084 57.336 ;
    END
  END general_s3[71]
  PIN general_s3[72]
    DIRECTION INPUT ;
    USE SIGNAL ;
    PORT
      LAYER M4 ;
        RECT  0 57.36 0.084 57.384 ;
    END
  END general_s3[72]
  PIN general_s3[73]
    DIRECTION INPUT ;
    USE SIGNAL ;
    PORT
      LAYER M4 ;
        RECT  0 57.408 0.084 57.432 ;
    END
  END general_s3[73]
  PIN general_s3[74]
    DIRECTION INPUT ;
    USE SIGNAL ;
    PORT
      LAYER M4 ;
        RECT  0 57.456 0.084 57.48 ;
    END
  END general_s3[74]
  PIN general_s3[75]
    DIRECTION INPUT ;
    USE SIGNAL ;
    PORT
      LAYER M4 ;
        RECT  0 57.504 0.084 57.528 ;
    END
  END general_s3[75]
  PIN general_s3[76]
    DIRECTION INPUT ;
    USE SIGNAL ;
    PORT
      LAYER M4 ;
        RECT  0 57.552 0.084 57.576 ;
    END
  END general_s3[76]
  PIN general_s3[77]
    DIRECTION INPUT ;
    USE SIGNAL ;
    PORT
      LAYER M4 ;
        RECT  0 57.6 0.084 57.624 ;
    END
  END general_s3[77]
  PIN general_s3[78]
    DIRECTION INPUT ;
    USE SIGNAL ;
    PORT
      LAYER M4 ;
        RECT  0 57.648 0.084 57.672 ;
    END
  END general_s3[78]
  PIN general_s3[79]
    DIRECTION INPUT ;
    USE SIGNAL ;
    PORT
      LAYER M4 ;
        RECT  0 57.696 0.084 57.72 ;
    END
  END general_s3[79]
  PIN general_s3[7]
    DIRECTION INPUT ;
    USE SIGNAL ;
    PORT
      LAYER M4 ;
        RECT  0 69.984 0.084 70.008 ;
    END
  END general_s3[7]
  PIN general_s3[80]
    DIRECTION INPUT ;
    USE SIGNAL ;
    PORT
      LAYER M4 ;
        RECT  0 57.744 0.084 57.768 ;
    END
  END general_s3[80]
  PIN general_s3[81]
    DIRECTION INPUT ;
    USE SIGNAL ;
    PORT
      LAYER M4 ;
        RECT  0 57.792 0.084 57.816 ;
    END
  END general_s3[81]
  PIN general_s3[82]
    DIRECTION INPUT ;
    USE SIGNAL ;
    PORT
      LAYER M4 ;
        RECT  0 57.84 0.084 57.864 ;
    END
  END general_s3[82]
  PIN general_s3[83]
    DIRECTION INPUT ;
    USE SIGNAL ;
    PORT
      LAYER M4 ;
        RECT  0 57.888 0.084 57.912 ;
    END
  END general_s3[83]
  PIN general_s3[84]
    DIRECTION INPUT ;
    USE SIGNAL ;
    PORT
      LAYER M4 ;
        RECT  0 57.936 0.084 57.96 ;
    END
  END general_s3[84]
  PIN general_s3[85]
    DIRECTION INPUT ;
    USE SIGNAL ;
    PORT
      LAYER M4 ;
        RECT  0 57.984 0.084 58.008 ;
    END
  END general_s3[85]
  PIN general_s3[86]
    DIRECTION INPUT ;
    USE SIGNAL ;
    PORT
      LAYER M4 ;
        RECT  0 58.032 0.084 58.056 ;
    END
  END general_s3[86]
  PIN general_s3[87]
    DIRECTION INPUT ;
    USE SIGNAL ;
    PORT
      LAYER M4 ;
        RECT  0 58.08 0.084 58.104 ;
    END
  END general_s3[87]
  PIN general_s3[88]
    DIRECTION INPUT ;
    USE SIGNAL ;
    PORT
      LAYER M4 ;
        RECT  0 58.128 0.084 58.152 ;
    END
  END general_s3[88]
  PIN general_s3[89]
    DIRECTION INPUT ;
    USE SIGNAL ;
    PORT
      LAYER M4 ;
        RECT  0 58.176 0.084 58.2 ;
    END
  END general_s3[89]
  PIN general_s3[8]
    DIRECTION INPUT ;
    USE SIGNAL ;
    PORT
      LAYER M4 ;
        RECT  0 70.032 0.084 70.056 ;
    END
  END general_s3[8]
  PIN general_s3[90]
    DIRECTION INPUT ;
    USE SIGNAL ;
    PORT
      LAYER M4 ;
        RECT  0 58.224 0.084 58.248 ;
    END
  END general_s3[90]
  PIN general_s3[91]
    DIRECTION INPUT ;
    USE SIGNAL ;
    PORT
      LAYER M4 ;
        RECT  0 58.272 0.084 58.296 ;
    END
  END general_s3[91]
  PIN general_s3[92]
    DIRECTION INPUT ;
    USE SIGNAL ;
    PORT
      LAYER M4 ;
        RECT  0 58.32 0.084 58.344 ;
    END
  END general_s3[92]
  PIN general_s3[93]
    DIRECTION INPUT ;
    USE SIGNAL ;
    PORT
      LAYER M4 ;
        RECT  0 58.368 0.084 58.392 ;
    END
  END general_s3[93]
  PIN general_s3[94]
    DIRECTION INPUT ;
    USE SIGNAL ;
    PORT
      LAYER M4 ;
        RECT  0 45.744 0.084 45.768 ;
    END
  END general_s3[94]
  PIN general_s3[95]
    DIRECTION INPUT ;
    USE SIGNAL ;
    PORT
      LAYER M4 ;
        RECT  0 45.792 0.084 45.816 ;
    END
  END general_s3[95]
  PIN general_s3[96]
    DIRECTION INPUT ;
    USE SIGNAL ;
    PORT
      LAYER M4 ;
        RECT  0 45.84 0.084 45.864 ;
    END
  END general_s3[96]
  PIN general_s3[97]
    DIRECTION INPUT ;
    USE SIGNAL ;
    PORT
      LAYER M4 ;
        RECT  0 45.888 0.084 45.912 ;
    END
  END general_s3[97]
  PIN general_s3[98]
    DIRECTION INPUT ;
    USE SIGNAL ;
    PORT
      LAYER M4 ;
        RECT  0 45.936 0.084 45.96 ;
    END
  END general_s3[98]
  PIN general_s3[99]
    DIRECTION INPUT ;
    USE SIGNAL ;
    PORT
      LAYER M4 ;
        RECT  0 45.984 0.084 46.008 ;
    END
  END general_s3[99]
  PIN general_s3[9]
    DIRECTION INPUT ;
    USE SIGNAL ;
    PORT
      LAYER M4 ;
        RECT  0 70.08 0.084 70.104 ;
    END
  END general_s3[9]
  PIN general_v
    DIRECTION INPUT ;
    USE SIGNAL ;
    PORT
      LAYER M4 ;
        RECT  0 66.432 0.084 66.456 ;
    END
    PORT
      LAYER M4 ;
        RECT  0.06 66.432 0.133 66.456 ;
    END
  END general_v
  PIN overflow
    DIRECTION OUTPUT ;
    USE SIGNAL ;
    PORT
      LAYER M5 ;
        RECT  64.944 103.596 64.968 103.68 ;
    END
  END overflow
  PIN rst_n
    DIRECTION INPUT ;
    USE SIGNAL ;
    PORT
      LAYER M5 ;
        RECT  79.824 0 79.848 0.084 ;
    END
  END rst_n
  PIN s3[0]
    DIRECTION OUTPUT ;
    USE SIGNAL ;
    PORT
      LAYER M5 ;
        RECT  64.992 103.596 65.016 103.68 ;
    END
  END s3[0]
  PIN s3[100]
    DIRECTION OUTPUT ;
    USE SIGNAL ;
    PORT
      LAYER M5 ;
        RECT  92.448 103.596 92.472 103.68 ;
    END
  END s3[100]
  PIN s3[101]
    DIRECTION OUTPUT ;
    USE SIGNAL ;
    PORT
      LAYER M5 ;
        RECT  92.496 103.596 92.52 103.68 ;
    END
  END s3[101]
  PIN s3[102]
    DIRECTION OUTPUT ;
    USE SIGNAL ;
    PORT
      LAYER M5 ;
        RECT  92.544 103.596 92.568 103.68 ;
    END
  END s3[102]
  PIN s3[103]
    DIRECTION OUTPUT ;
    USE SIGNAL ;
    PORT
      LAYER M5 ;
        RECT  92.592 103.596 92.616 103.68 ;
    END
  END s3[103]
  PIN s3[104]
    DIRECTION OUTPUT ;
    USE SIGNAL ;
    PORT
      LAYER M5 ;
        RECT  92.64 103.596 92.664 103.68 ;
    END
  END s3[104]
  PIN s3[105]
    DIRECTION OUTPUT ;
    USE SIGNAL ;
    PORT
      LAYER M5 ;
        RECT  92.688 103.596 92.712 103.68 ;
    END
  END s3[105]
  PIN s3[106]
    DIRECTION OUTPUT ;
    USE SIGNAL ;
    PORT
      LAYER M5 ;
        RECT  92.736 103.596 92.76 103.68 ;
    END
  END s3[106]
  PIN s3[107]
    DIRECTION OUTPUT ;
    USE SIGNAL ;
    PORT
      LAYER M5 ;
        RECT  92.784 103.596 92.808 103.68 ;
    END
  END s3[107]
  PIN s3[108]
    DIRECTION OUTPUT ;
    USE SIGNAL ;
    PORT
      LAYER M5 ;
        RECT  92.832 103.596 92.856 103.68 ;
    END
  END s3[108]
  PIN s3[109]
    DIRECTION OUTPUT ;
    USE SIGNAL ;
    PORT
      LAYER M5 ;
        RECT  92.88 103.596 92.904 103.68 ;
    END
  END s3[109]
  PIN s3[10]
    DIRECTION OUTPUT ;
    USE SIGNAL ;
    PORT
      LAYER M5 ;
        RECT  65.472 103.596 65.496 103.68 ;
    END
  END s3[10]
  PIN s3[110]
    DIRECTION OUTPUT ;
    USE SIGNAL ;
    PORT
      LAYER M5 ;
        RECT  92.928 103.596 92.952 103.68 ;
    END
  END s3[110]
  PIN s3[111]
    DIRECTION OUTPUT ;
    USE SIGNAL ;
    PORT
      LAYER M5 ;
        RECT  92.976 103.596 93 103.68 ;
    END
  END s3[111]
  PIN s3[112]
    DIRECTION OUTPUT ;
    USE SIGNAL ;
    PORT
      LAYER M5 ;
        RECT  93.024 103.596 93.048 103.68 ;
    END
  END s3[112]
  PIN s3[113]
    DIRECTION OUTPUT ;
    USE SIGNAL ;
    PORT
      LAYER M5 ;
        RECT  93.072 103.596 93.096 103.68 ;
    END
  END s3[113]
  PIN s3[114]
    DIRECTION OUTPUT ;
    USE SIGNAL ;
    PORT
      LAYER M5 ;
        RECT  93.12 103.596 93.144 103.68 ;
    END
  END s3[114]
  PIN s3[115]
    DIRECTION OUTPUT ;
    USE SIGNAL ;
    PORT
      LAYER M5 ;
        RECT  93.168 103.596 93.192 103.68 ;
    END
  END s3[115]
  PIN s3[116]
    DIRECTION OUTPUT ;
    USE SIGNAL ;
    PORT
      LAYER M5 ;
        RECT  93.216 103.596 93.24 103.68 ;
    END
  END s3[116]
  PIN s3[117]
    DIRECTION OUTPUT ;
    USE SIGNAL ;
    PORT
      LAYER M5 ;
        RECT  93.264 103.596 93.288 103.68 ;
    END
  END s3[117]
  PIN s3[118]
    DIRECTION OUTPUT ;
    USE SIGNAL ;
    PORT
      LAYER M5 ;
        RECT  93.312 103.596 93.336 103.68 ;
    END
  END s3[118]
  PIN s3[119]
    DIRECTION OUTPUT ;
    USE SIGNAL ;
    PORT
      LAYER M5 ;
        RECT  93.36 103.596 93.384 103.68 ;
    END
  END s3[119]
  PIN s3[11]
    DIRECTION OUTPUT ;
    USE SIGNAL ;
    PORT
      LAYER M5 ;
        RECT  65.52 103.596 65.544 103.68 ;
    END
  END s3[11]
  PIN s3[120]
    DIRECTION OUTPUT ;
    USE SIGNAL ;
    PORT
      LAYER M5 ;
        RECT  93.408 103.596 93.432 103.68 ;
    END
  END s3[120]
  PIN s3[121]
    DIRECTION OUTPUT ;
    USE SIGNAL ;
    PORT
      LAYER M5 ;
        RECT  93.456 103.596 93.48 103.68 ;
    END
  END s3[121]
  PIN s3[122]
    DIRECTION OUTPUT ;
    USE SIGNAL ;
    PORT
      LAYER M5 ;
        RECT  93.504 103.596 93.528 103.68 ;
    END
  END s3[122]
  PIN s3[123]
    DIRECTION OUTPUT ;
    USE SIGNAL ;
    PORT
      LAYER M5 ;
        RECT  93.552 103.596 93.576 103.68 ;
    END
  END s3[123]
  PIN s3[124]
    DIRECTION OUTPUT ;
    USE SIGNAL ;
    PORT
      LAYER M5 ;
        RECT  93.6 103.596 93.624 103.68 ;
    END
  END s3[124]
  PIN s3[125]
    DIRECTION OUTPUT ;
    USE SIGNAL ;
    PORT
      LAYER M5 ;
        RECT  93.648 103.596 93.672 103.68 ;
    END
  END s3[125]
  PIN s3[126]
    DIRECTION OUTPUT ;
    USE SIGNAL ;
    PORT
      LAYER M5 ;
        RECT  93.696 103.596 93.72 103.68 ;
    END
  END s3[126]
  PIN s3[127]
    DIRECTION OUTPUT ;
    USE SIGNAL ;
    PORT
      LAYER M5 ;
        RECT  114.864 103.596 114.888 103.68 ;
    END
  END s3[127]
  PIN s3[128]
    DIRECTION OUTPUT ;
    USE SIGNAL ;
    PORT
      LAYER M5 ;
        RECT  114.912 103.596 114.936 103.68 ;
    END
  END s3[128]
  PIN s3[129]
    DIRECTION OUTPUT ;
    USE SIGNAL ;
    PORT
      LAYER M5 ;
        RECT  114.96 103.596 114.984 103.68 ;
    END
  END s3[129]
  PIN s3[12]
    DIRECTION OUTPUT ;
    USE SIGNAL ;
    PORT
      LAYER M5 ;
        RECT  65.568 103.596 65.592 103.68 ;
    END
  END s3[12]
  PIN s3[130]
    DIRECTION OUTPUT ;
    USE SIGNAL ;
    PORT
      LAYER M5 ;
        RECT  115.008 103.596 115.032 103.68 ;
    END
  END s3[130]
  PIN s3[131]
    DIRECTION OUTPUT ;
    USE SIGNAL ;
    PORT
      LAYER M5 ;
        RECT  115.056 103.596 115.08 103.68 ;
    END
  END s3[131]
  PIN s3[132]
    DIRECTION OUTPUT ;
    USE SIGNAL ;
    PORT
      LAYER M5 ;
        RECT  115.104 103.596 115.128 103.68 ;
    END
  END s3[132]
  PIN s3[133]
    DIRECTION OUTPUT ;
    USE SIGNAL ;
    PORT
      LAYER M5 ;
        RECT  115.152 103.596 115.176 103.68 ;
    END
  END s3[133]
  PIN s3[134]
    DIRECTION OUTPUT ;
    USE SIGNAL ;
    PORT
      LAYER M5 ;
        RECT  115.2 103.596 115.224 103.68 ;
    END
  END s3[134]
  PIN s3[135]
    DIRECTION OUTPUT ;
    USE SIGNAL ;
    PORT
      LAYER M5 ;
        RECT  115.248 103.596 115.272 103.68 ;
    END
  END s3[135]
  PIN s3[136]
    DIRECTION OUTPUT ;
    USE SIGNAL ;
    PORT
      LAYER M5 ;
        RECT  115.296 103.596 115.32 103.68 ;
    END
  END s3[136]
  PIN s3[137]
    DIRECTION OUTPUT ;
    USE SIGNAL ;
    PORT
      LAYER M5 ;
        RECT  115.344 103.596 115.368 103.68 ;
    END
  END s3[137]
  PIN s3[138]
    DIRECTION OUTPUT ;
    USE SIGNAL ;
    PORT
      LAYER M5 ;
        RECT  115.392 103.596 115.416 103.68 ;
    END
  END s3[138]
  PIN s3[139]
    DIRECTION OUTPUT ;
    USE SIGNAL ;
    PORT
      LAYER M5 ;
        RECT  115.44 103.596 115.464 103.68 ;
    END
  END s3[139]
  PIN s3[13]
    DIRECTION OUTPUT ;
    USE SIGNAL ;
    PORT
      LAYER M5 ;
        RECT  65.616 103.596 65.64 103.68 ;
    END
  END s3[13]
  PIN s3[140]
    DIRECTION OUTPUT ;
    USE SIGNAL ;
    PORT
      LAYER M5 ;
        RECT  115.488 103.596 115.512 103.68 ;
    END
  END s3[140]
  PIN s3[141]
    DIRECTION OUTPUT ;
    USE SIGNAL ;
    PORT
      LAYER M5 ;
        RECT  115.536 103.596 115.56 103.68 ;
    END
  END s3[141]
  PIN s3[142]
    DIRECTION OUTPUT ;
    USE SIGNAL ;
    PORT
      LAYER M5 ;
        RECT  115.584 103.596 115.608 103.68 ;
    END
  END s3[142]
  PIN s3[143]
    DIRECTION OUTPUT ;
    USE SIGNAL ;
    PORT
      LAYER M5 ;
        RECT  115.632 103.596 115.656 103.68 ;
    END
  END s3[143]
  PIN s3[144]
    DIRECTION OUTPUT ;
    USE SIGNAL ;
    PORT
      LAYER M5 ;
        RECT  115.68 103.596 115.704 103.68 ;
    END
  END s3[144]
  PIN s3[145]
    DIRECTION OUTPUT ;
    USE SIGNAL ;
    PORT
      LAYER M5 ;
        RECT  115.728 103.596 115.752 103.68 ;
    END
  END s3[145]
  PIN s3[146]
    DIRECTION OUTPUT ;
    USE SIGNAL ;
    PORT
      LAYER M5 ;
        RECT  115.776 103.596 115.8 103.68 ;
    END
  END s3[146]
  PIN s3[147]
    DIRECTION OUTPUT ;
    USE SIGNAL ;
    PORT
      LAYER M5 ;
        RECT  115.824 103.596 115.848 103.68 ;
    END
  END s3[147]
  PIN s3[148]
    DIRECTION OUTPUT ;
    USE SIGNAL ;
    PORT
      LAYER M5 ;
        RECT  115.872 103.596 115.896 103.68 ;
    END
  END s3[148]
  PIN s3[149]
    DIRECTION OUTPUT ;
    USE SIGNAL ;
    PORT
      LAYER M5 ;
        RECT  115.92 103.596 115.944 103.68 ;
    END
  END s3[149]
  PIN s3[14]
    DIRECTION OUTPUT ;
    USE SIGNAL ;
    PORT
      LAYER M5 ;
        RECT  65.664 103.596 65.688 103.68 ;
    END
  END s3[14]
  PIN s3[150]
    DIRECTION OUTPUT ;
    USE SIGNAL ;
    PORT
      LAYER M5 ;
        RECT  115.968 103.596 115.992 103.68 ;
    END
  END s3[150]
  PIN s3[151]
    DIRECTION OUTPUT ;
    USE SIGNAL ;
    PORT
      LAYER M5 ;
        RECT  116.016 103.596 116.04 103.68 ;
    END
  END s3[151]
  PIN s3[152]
    DIRECTION OUTPUT ;
    USE SIGNAL ;
    PORT
      LAYER M5 ;
        RECT  116.064 103.596 116.088 103.68 ;
    END
  END s3[152]
  PIN s3[153]
    DIRECTION OUTPUT ;
    USE SIGNAL ;
    PORT
      LAYER M5 ;
        RECT  116.112 103.596 116.136 103.68 ;
    END
  END s3[153]
  PIN s3[154]
    DIRECTION OUTPUT ;
    USE SIGNAL ;
    PORT
      LAYER M5 ;
        RECT  116.16 103.596 116.184 103.68 ;
    END
  END s3[154]
  PIN s3[155]
    DIRECTION OUTPUT ;
    USE SIGNAL ;
    PORT
      LAYER M5 ;
        RECT  116.208 103.596 116.232 103.68 ;
    END
  END s3[155]
  PIN s3[156]
    DIRECTION OUTPUT ;
    USE SIGNAL ;
    PORT
      LAYER M5 ;
        RECT  116.256 103.596 116.28 103.68 ;
    END
  END s3[156]
  PIN s3[157]
    DIRECTION OUTPUT ;
    USE SIGNAL ;
    PORT
      LAYER M5 ;
        RECT  116.304 103.596 116.328 103.68 ;
    END
  END s3[157]
  PIN s3[158]
    DIRECTION OUTPUT ;
    USE SIGNAL ;
    PORT
      LAYER M5 ;
        RECT  116.352 103.596 116.376 103.68 ;
    END
  END s3[158]
  PIN s3[159]
    DIRECTION OUTPUT ;
    USE SIGNAL ;
    PORT
      LAYER M5 ;
        RECT  61.872 103.596 61.896 103.68 ;
    END
  END s3[159]
  PIN s3[15]
    DIRECTION OUTPUT ;
    USE SIGNAL ;
    PORT
      LAYER M5 ;
        RECT  65.712 103.596 65.736 103.68 ;
    END
  END s3[15]
  PIN s3[160]
    DIRECTION OUTPUT ;
    USE SIGNAL ;
    PORT
      LAYER M5 ;
        RECT  61.92 103.596 61.944 103.68 ;
    END
  END s3[160]
  PIN s3[161]
    DIRECTION OUTPUT ;
    USE SIGNAL ;
    PORT
      LAYER M5 ;
        RECT  61.968 103.596 61.992 103.68 ;
    END
  END s3[161]
  PIN s3[162]
    DIRECTION OUTPUT ;
    USE SIGNAL ;
    PORT
      LAYER M5 ;
        RECT  62.016 103.596 62.04 103.68 ;
    END
  END s3[162]
  PIN s3[163]
    DIRECTION OUTPUT ;
    USE SIGNAL ;
    PORT
      LAYER M5 ;
        RECT  62.064 103.596 62.088 103.68 ;
    END
  END s3[163]
  PIN s3[164]
    DIRECTION OUTPUT ;
    USE SIGNAL ;
    PORT
      LAYER M5 ;
        RECT  62.112 103.596 62.136 103.68 ;
    END
  END s3[164]
  PIN s3[165]
    DIRECTION OUTPUT ;
    USE SIGNAL ;
    PORT
      LAYER M5 ;
        RECT  62.16 103.596 62.184 103.68 ;
    END
  END s3[165]
  PIN s3[166]
    DIRECTION OUTPUT ;
    USE SIGNAL ;
    PORT
      LAYER M5 ;
        RECT  62.208 103.596 62.232 103.68 ;
    END
  END s3[166]
  PIN s3[167]
    DIRECTION OUTPUT ;
    USE SIGNAL ;
    PORT
      LAYER M5 ;
        RECT  62.256 103.596 62.28 103.68 ;
    END
  END s3[167]
  PIN s3[168]
    DIRECTION OUTPUT ;
    USE SIGNAL ;
    PORT
      LAYER M5 ;
        RECT  62.304 103.596 62.328 103.68 ;
    END
  END s3[168]
  PIN s3[169]
    DIRECTION OUTPUT ;
    USE SIGNAL ;
    PORT
      LAYER M5 ;
        RECT  62.352 103.596 62.376 103.68 ;
    END
  END s3[169]
  PIN s3[16]
    DIRECTION OUTPUT ;
    USE SIGNAL ;
    PORT
      LAYER M5 ;
        RECT  65.76 103.596 65.784 103.68 ;
    END
  END s3[16]
  PIN s3[170]
    DIRECTION OUTPUT ;
    USE SIGNAL ;
    PORT
      LAYER M5 ;
        RECT  62.4 103.596 62.424 103.68 ;
    END
  END s3[170]
  PIN s3[171]
    DIRECTION OUTPUT ;
    USE SIGNAL ;
    PORT
      LAYER M5 ;
        RECT  62.448 103.596 62.472 103.68 ;
    END
  END s3[171]
  PIN s3[172]
    DIRECTION OUTPUT ;
    USE SIGNAL ;
    PORT
      LAYER M5 ;
        RECT  62.496 103.596 62.52 103.68 ;
    END
  END s3[172]
  PIN s3[173]
    DIRECTION OUTPUT ;
    USE SIGNAL ;
    PORT
      LAYER M5 ;
        RECT  62.544 103.596 62.568 103.68 ;
    END
  END s3[173]
  PIN s3[174]
    DIRECTION OUTPUT ;
    USE SIGNAL ;
    PORT
      LAYER M5 ;
        RECT  62.592 103.596 62.616 103.68 ;
    END
  END s3[174]
  PIN s3[175]
    DIRECTION OUTPUT ;
    USE SIGNAL ;
    PORT
      LAYER M5 ;
        RECT  62.64 103.596 62.664 103.68 ;
    END
  END s3[175]
  PIN s3[176]
    DIRECTION OUTPUT ;
    USE SIGNAL ;
    PORT
      LAYER M5 ;
        RECT  62.688 103.596 62.712 103.68 ;
    END
  END s3[176]
  PIN s3[177]
    DIRECTION OUTPUT ;
    USE SIGNAL ;
    PORT
      LAYER M5 ;
        RECT  62.736 103.596 62.76 103.68 ;
    END
  END s3[177]
  PIN s3[178]
    DIRECTION OUTPUT ;
    USE SIGNAL ;
    PORT
      LAYER M5 ;
        RECT  62.784 103.596 62.808 103.68 ;
    END
  END s3[178]
  PIN s3[179]
    DIRECTION OUTPUT ;
    USE SIGNAL ;
    PORT
      LAYER M5 ;
        RECT  62.832 103.596 62.856 103.68 ;
    END
  END s3[179]
  PIN s3[17]
    DIRECTION OUTPUT ;
    USE SIGNAL ;
    PORT
      LAYER M5 ;
        RECT  65.808 103.596 65.832 103.68 ;
    END
  END s3[17]
  PIN s3[180]
    DIRECTION OUTPUT ;
    USE SIGNAL ;
    PORT
      LAYER M5 ;
        RECT  62.88 103.596 62.904 103.68 ;
    END
  END s3[180]
  PIN s3[181]
    DIRECTION OUTPUT ;
    USE SIGNAL ;
    PORT
      LAYER M5 ;
        RECT  62.928 103.596 62.952 103.68 ;
    END
  END s3[181]
  PIN s3[182]
    DIRECTION OUTPUT ;
    USE SIGNAL ;
    PORT
      LAYER M5 ;
        RECT  62.976 103.596 63 103.68 ;
    END
  END s3[182]
  PIN s3[183]
    DIRECTION OUTPUT ;
    USE SIGNAL ;
    PORT
      LAYER M5 ;
        RECT  63.024 103.596 63.048 103.68 ;
    END
  END s3[183]
  PIN s3[184]
    DIRECTION OUTPUT ;
    USE SIGNAL ;
    PORT
      LAYER M5 ;
        RECT  63.072 103.596 63.096 103.68 ;
    END
  END s3[184]
  PIN s3[185]
    DIRECTION OUTPUT ;
    USE SIGNAL ;
    PORT
      LAYER M5 ;
        RECT  63.12 103.596 63.144 103.68 ;
    END
  END s3[185]
  PIN s3[186]
    DIRECTION OUTPUT ;
    USE SIGNAL ;
    PORT
      LAYER M5 ;
        RECT  63.168 103.596 63.192 103.68 ;
    END
  END s3[186]
  PIN s3[187]
    DIRECTION OUTPUT ;
    USE SIGNAL ;
    PORT
      LAYER M5 ;
        RECT  63.216 103.596 63.24 103.68 ;
    END
  END s3[187]
  PIN s3[188]
    DIRECTION OUTPUT ;
    USE SIGNAL ;
    PORT
      LAYER M5 ;
        RECT  63.264 103.596 63.288 103.68 ;
    END
  END s3[188]
  PIN s3[189]
    DIRECTION OUTPUT ;
    USE SIGNAL ;
    PORT
      LAYER M5 ;
        RECT  63.312 103.596 63.336 103.68 ;
    END
  END s3[189]
  PIN s3[18]
    DIRECTION OUTPUT ;
    USE SIGNAL ;
    PORT
      LAYER M5 ;
        RECT  65.856 103.596 65.88 103.68 ;
    END
  END s3[18]
  PIN s3[19]
    DIRECTION OUTPUT ;
    USE SIGNAL ;
    PORT
      LAYER M5 ;
        RECT  65.904 103.596 65.928 103.68 ;
    END
  END s3[19]
  PIN s3[1]
    DIRECTION OUTPUT ;
    USE SIGNAL ;
    PORT
      LAYER M5 ;
        RECT  65.04 103.596 65.064 103.68 ;
    END
  END s3[1]
  PIN s3[20]
    DIRECTION OUTPUT ;
    USE SIGNAL ;
    PORT
      LAYER M5 ;
        RECT  65.952 103.596 65.976 103.68 ;
    END
  END s3[20]
  PIN s3[21]
    DIRECTION OUTPUT ;
    USE SIGNAL ;
    PORT
      LAYER M5 ;
        RECT  66 103.596 66.024 103.68 ;
    END
  END s3[21]
  PIN s3[22]
    DIRECTION OUTPUT ;
    USE SIGNAL ;
    PORT
      LAYER M5 ;
        RECT  66.048 103.596 66.072 103.68 ;
    END
  END s3[22]
  PIN s3[23]
    DIRECTION OUTPUT ;
    USE SIGNAL ;
    PORT
      LAYER M5 ;
        RECT  66.096 103.596 66.12 103.68 ;
    END
  END s3[23]
  PIN s3[24]
    DIRECTION OUTPUT ;
    USE SIGNAL ;
    PORT
      LAYER M5 ;
        RECT  66.144 103.596 66.168 103.68 ;
    END
  END s3[24]
  PIN s3[25]
    DIRECTION OUTPUT ;
    USE SIGNAL ;
    PORT
      LAYER M5 ;
        RECT  66.192 103.596 66.216 103.68 ;
    END
  END s3[25]
  PIN s3[26]
    DIRECTION OUTPUT ;
    USE SIGNAL ;
    PORT
      LAYER M5 ;
        RECT  66.24 103.596 66.264 103.68 ;
    END
  END s3[26]
  PIN s3[27]
    DIRECTION OUTPUT ;
    USE SIGNAL ;
    PORT
      LAYER M5 ;
        RECT  66.288 103.596 66.312 103.68 ;
    END
  END s3[27]
  PIN s3[28]
    DIRECTION OUTPUT ;
    USE SIGNAL ;
    PORT
      LAYER M5 ;
        RECT  66.336 103.596 66.36 103.68 ;
    END
  END s3[28]
  PIN s3[29]
    DIRECTION OUTPUT ;
    USE SIGNAL ;
    PORT
      LAYER M5 ;
        RECT  66.384 103.596 66.408 103.68 ;
    END
  END s3[29]
  PIN s3[2]
    DIRECTION OUTPUT ;
    USE SIGNAL ;
    PORT
      LAYER M5 ;
        RECT  65.088 103.596 65.112 103.68 ;
    END
  END s3[2]
  PIN s3[30]
    DIRECTION OUTPUT ;
    USE SIGNAL ;
    PORT
      LAYER M5 ;
        RECT  66.432 103.596 66.456 103.68 ;
    END
  END s3[30]
  PIN s3[31]
    DIRECTION OUTPUT ;
    USE SIGNAL ;
    PORT
      LAYER M5 ;
        RECT  42.672 103.596 42.696 103.68 ;
    END
  END s3[31]
  PIN s3[32]
    DIRECTION OUTPUT ;
    USE SIGNAL ;
    PORT
      LAYER M5 ;
        RECT  42.72 103.596 42.744 103.68 ;
    END
  END s3[32]
  PIN s3[33]
    DIRECTION OUTPUT ;
    USE SIGNAL ;
    PORT
      LAYER M5 ;
        RECT  42.768 103.596 42.792 103.68 ;
    END
  END s3[33]
  PIN s3[34]
    DIRECTION OUTPUT ;
    USE SIGNAL ;
    PORT
      LAYER M5 ;
        RECT  42.816 103.596 42.84 103.68 ;
    END
  END s3[34]
  PIN s3[35]
    DIRECTION OUTPUT ;
    USE SIGNAL ;
    PORT
      LAYER M5 ;
        RECT  42.864 103.596 42.888 103.68 ;
    END
  END s3[35]
  PIN s3[36]
    DIRECTION OUTPUT ;
    USE SIGNAL ;
    PORT
      LAYER M5 ;
        RECT  42.912 103.596 42.936 103.68 ;
    END
  END s3[36]
  PIN s3[37]
    DIRECTION OUTPUT ;
    USE SIGNAL ;
    PORT
      LAYER M5 ;
        RECT  42.96 103.596 42.984 103.68 ;
    END
  END s3[37]
  PIN s3[38]
    DIRECTION OUTPUT ;
    USE SIGNAL ;
    PORT
      LAYER M5 ;
        RECT  43.008 103.596 43.032 103.68 ;
    END
  END s3[38]
  PIN s3[39]
    DIRECTION OUTPUT ;
    USE SIGNAL ;
    PORT
      LAYER M5 ;
        RECT  43.056 103.596 43.08 103.68 ;
    END
  END s3[39]
  PIN s3[3]
    DIRECTION OUTPUT ;
    USE SIGNAL ;
    PORT
      LAYER M5 ;
        RECT  65.136 103.596 65.16 103.68 ;
    END
  END s3[3]
  PIN s3[40]
    DIRECTION OUTPUT ;
    USE SIGNAL ;
    PORT
      LAYER M5 ;
        RECT  43.104 103.596 43.128 103.68 ;
    END
  END s3[40]
  PIN s3[41]
    DIRECTION OUTPUT ;
    USE SIGNAL ;
    PORT
      LAYER M5 ;
        RECT  43.152 103.596 43.176 103.68 ;
    END
  END s3[41]
  PIN s3[42]
    DIRECTION OUTPUT ;
    USE SIGNAL ;
    PORT
      LAYER M5 ;
        RECT  43.2 103.596 43.224 103.68 ;
    END
  END s3[42]
  PIN s3[43]
    DIRECTION OUTPUT ;
    USE SIGNAL ;
    PORT
      LAYER M5 ;
        RECT  43.248 103.596 43.272 103.68 ;
    END
  END s3[43]
  PIN s3[44]
    DIRECTION OUTPUT ;
    USE SIGNAL ;
    PORT
      LAYER M5 ;
        RECT  43.296 103.596 43.32 103.68 ;
    END
  END s3[44]
  PIN s3[45]
    DIRECTION OUTPUT ;
    USE SIGNAL ;
    PORT
      LAYER M5 ;
        RECT  43.344 103.596 43.368 103.68 ;
    END
  END s3[45]
  PIN s3[46]
    DIRECTION OUTPUT ;
    USE SIGNAL ;
    PORT
      LAYER M5 ;
        RECT  43.392 103.596 43.416 103.68 ;
    END
  END s3[46]
  PIN s3[47]
    DIRECTION OUTPUT ;
    USE SIGNAL ;
    PORT
      LAYER M5 ;
        RECT  43.44 103.596 43.464 103.68 ;
    END
  END s3[47]
  PIN s3[48]
    DIRECTION OUTPUT ;
    USE SIGNAL ;
    PORT
      LAYER M5 ;
        RECT  43.488 103.596 43.512 103.68 ;
    END
  END s3[48]
  PIN s3[49]
    DIRECTION OUTPUT ;
    USE SIGNAL ;
    PORT
      LAYER M5 ;
        RECT  43.536 103.596 43.56 103.68 ;
    END
  END s3[49]
  PIN s3[4]
    DIRECTION OUTPUT ;
    USE SIGNAL ;
    PORT
      LAYER M5 ;
        RECT  65.184 103.596 65.208 103.68 ;
    END
  END s3[4]
  PIN s3[50]
    DIRECTION OUTPUT ;
    USE SIGNAL ;
    PORT
      LAYER M5 ;
        RECT  43.584 103.596 43.608 103.68 ;
    END
  END s3[50]
  PIN s3[51]
    DIRECTION OUTPUT ;
    USE SIGNAL ;
    PORT
      LAYER M5 ;
        RECT  43.632 103.596 43.656 103.68 ;
    END
  END s3[51]
  PIN s3[52]
    DIRECTION OUTPUT ;
    USE SIGNAL ;
    PORT
      LAYER M5 ;
        RECT  43.68 103.596 43.704 103.68 ;
    END
  END s3[52]
  PIN s3[53]
    DIRECTION OUTPUT ;
    USE SIGNAL ;
    PORT
      LAYER M5 ;
        RECT  43.728 103.596 43.752 103.68 ;
    END
  END s3[53]
  PIN s3[54]
    DIRECTION OUTPUT ;
    USE SIGNAL ;
    PORT
      LAYER M5 ;
        RECT  43.776 103.596 43.8 103.68 ;
    END
  END s3[54]
  PIN s3[55]
    DIRECTION OUTPUT ;
    USE SIGNAL ;
    PORT
      LAYER M5 ;
        RECT  43.824 103.596 43.848 103.68 ;
    END
  END s3[55]
  PIN s3[56]
    DIRECTION OUTPUT ;
    USE SIGNAL ;
    PORT
      LAYER M5 ;
        RECT  43.872 103.596 43.896 103.68 ;
    END
  END s3[56]
  PIN s3[57]
    DIRECTION OUTPUT ;
    USE SIGNAL ;
    PORT
      LAYER M5 ;
        RECT  43.92 103.596 43.944 103.68 ;
    END
  END s3[57]
  PIN s3[58]
    DIRECTION OUTPUT ;
    USE SIGNAL ;
    PORT
      LAYER M5 ;
        RECT  43.968 103.596 43.992 103.68 ;
    END
  END s3[58]
  PIN s3[59]
    DIRECTION OUTPUT ;
    USE SIGNAL ;
    PORT
      LAYER M5 ;
        RECT  44.016 103.596 44.04 103.68 ;
    END
  END s3[59]
  PIN s3[5]
    DIRECTION OUTPUT ;
    USE SIGNAL ;
    PORT
      LAYER M5 ;
        RECT  65.232 103.596 65.256 103.68 ;
    END
  END s3[5]
  PIN s3[60]
    DIRECTION OUTPUT ;
    USE SIGNAL ;
    PORT
      LAYER M5 ;
        RECT  44.064 103.596 44.088 103.68 ;
    END
  END s3[60]
  PIN s3[61]
    DIRECTION OUTPUT ;
    USE SIGNAL ;
    PORT
      LAYER M5 ;
        RECT  44.112 103.596 44.136 103.68 ;
    END
  END s3[61]
  PIN s3[62]
    DIRECTION OUTPUT ;
    USE SIGNAL ;
    PORT
      LAYER M5 ;
        RECT  44.16 103.596 44.184 103.68 ;
    END
  END s3[62]
  PIN s3[63]
    DIRECTION OUTPUT ;
    USE SIGNAL ;
    PORT
      LAYER M5 ;
        RECT  141.744 103.596 141.768 103.68 ;
    END
  END s3[63]
  PIN s3[64]
    DIRECTION OUTPUT ;
    USE SIGNAL ;
    PORT
      LAYER M5 ;
        RECT  141.792 103.596 141.816 103.68 ;
    END
  END s3[64]
  PIN s3[65]
    DIRECTION OUTPUT ;
    USE SIGNAL ;
    PORT
      LAYER M5 ;
        RECT  141.84 103.596 141.864 103.68 ;
    END
  END s3[65]
  PIN s3[66]
    DIRECTION OUTPUT ;
    USE SIGNAL ;
    PORT
      LAYER M5 ;
        RECT  141.888 103.596 141.912 103.68 ;
    END
  END s3[66]
  PIN s3[67]
    DIRECTION OUTPUT ;
    USE SIGNAL ;
    PORT
      LAYER M5 ;
        RECT  141.936 103.596 141.96 103.68 ;
    END
  END s3[67]
  PIN s3[68]
    DIRECTION OUTPUT ;
    USE SIGNAL ;
    PORT
      LAYER M5 ;
        RECT  141.984 103.596 142.008 103.68 ;
    END
  END s3[68]
  PIN s3[69]
    DIRECTION OUTPUT ;
    USE SIGNAL ;
    PORT
      LAYER M5 ;
        RECT  142.032 103.596 142.056 103.68 ;
    END
  END s3[69]
  PIN s3[6]
    DIRECTION OUTPUT ;
    USE SIGNAL ;
    PORT
      LAYER M5 ;
        RECT  65.28 103.596 65.304 103.68 ;
    END
  END s3[6]
  PIN s3[70]
    DIRECTION OUTPUT ;
    USE SIGNAL ;
    PORT
      LAYER M5 ;
        RECT  142.08 103.596 142.104 103.68 ;
    END
  END s3[70]
  PIN s3[71]
    DIRECTION OUTPUT ;
    USE SIGNAL ;
    PORT
      LAYER M5 ;
        RECT  142.128 103.596 142.152 103.68 ;
    END
  END s3[71]
  PIN s3[72]
    DIRECTION OUTPUT ;
    USE SIGNAL ;
    PORT
      LAYER M5 ;
        RECT  142.176 103.596 142.2 103.68 ;
    END
  END s3[72]
  PIN s3[73]
    DIRECTION OUTPUT ;
    USE SIGNAL ;
    PORT
      LAYER M5 ;
        RECT  142.224 103.596 142.248 103.68 ;
    END
  END s3[73]
  PIN s3[74]
    DIRECTION OUTPUT ;
    USE SIGNAL ;
    PORT
      LAYER M5 ;
        RECT  142.272 103.596 142.296 103.68 ;
    END
  END s3[74]
  PIN s3[75]
    DIRECTION OUTPUT ;
    USE SIGNAL ;
    PORT
      LAYER M5 ;
        RECT  142.32 103.596 142.344 103.68 ;
    END
  END s3[75]
  PIN s3[76]
    DIRECTION OUTPUT ;
    USE SIGNAL ;
    PORT
      LAYER M5 ;
        RECT  142.368 103.596 142.392 103.68 ;
    END
  END s3[76]
  PIN s3[77]
    DIRECTION OUTPUT ;
    USE SIGNAL ;
    PORT
      LAYER M5 ;
        RECT  142.416 103.596 142.44 103.68 ;
    END
  END s3[77]
  PIN s3[78]
    DIRECTION OUTPUT ;
    USE SIGNAL ;
    PORT
      LAYER M5 ;
        RECT  142.464 103.596 142.488 103.68 ;
    END
  END s3[78]
  PIN s3[79]
    DIRECTION OUTPUT ;
    USE SIGNAL ;
    PORT
      LAYER M5 ;
        RECT  142.512 103.596 142.536 103.68 ;
    END
  END s3[79]
  PIN s3[7]
    DIRECTION OUTPUT ;
    USE SIGNAL ;
    PORT
      LAYER M5 ;
        RECT  65.328 103.596 65.352 103.68 ;
    END
  END s3[7]
  PIN s3[80]
    DIRECTION OUTPUT ;
    USE SIGNAL ;
    PORT
      LAYER M5 ;
        RECT  142.56 103.596 142.584 103.68 ;
    END
  END s3[80]
  PIN s3[81]
    DIRECTION OUTPUT ;
    USE SIGNAL ;
    PORT
      LAYER M5 ;
        RECT  142.608 103.596 142.632 103.68 ;
    END
  END s3[81]
  PIN s3[82]
    DIRECTION OUTPUT ;
    USE SIGNAL ;
    PORT
      LAYER M5 ;
        RECT  142.656 103.596 142.68 103.68 ;
    END
  END s3[82]
  PIN s3[83]
    DIRECTION OUTPUT ;
    USE SIGNAL ;
    PORT
      LAYER M5 ;
        RECT  142.704 103.596 142.728 103.68 ;
    END
  END s3[83]
  PIN s3[84]
    DIRECTION OUTPUT ;
    USE SIGNAL ;
    PORT
      LAYER M5 ;
        RECT  142.752 103.596 142.776 103.68 ;
    END
  END s3[84]
  PIN s3[85]
    DIRECTION OUTPUT ;
    USE SIGNAL ;
    PORT
      LAYER M5 ;
        RECT  142.8 103.596 142.824 103.68 ;
    END
  END s3[85]
  PIN s3[86]
    DIRECTION OUTPUT ;
    USE SIGNAL ;
    PORT
      LAYER M5 ;
        RECT  142.848 103.596 142.872 103.68 ;
    END
  END s3[86]
  PIN s3[87]
    DIRECTION OUTPUT ;
    USE SIGNAL ;
    PORT
      LAYER M5 ;
        RECT  142.896 103.596 142.92 103.68 ;
    END
  END s3[87]
  PIN s3[88]
    DIRECTION OUTPUT ;
    USE SIGNAL ;
    PORT
      LAYER M5 ;
        RECT  142.944 103.596 142.968 103.68 ;
    END
  END s3[88]
  PIN s3[89]
    DIRECTION OUTPUT ;
    USE SIGNAL ;
    PORT
      LAYER M5 ;
        RECT  142.992 103.596 143.016 103.68 ;
    END
  END s3[89]
  PIN s3[8]
    DIRECTION OUTPUT ;
    USE SIGNAL ;
    PORT
      LAYER M5 ;
        RECT  65.376 103.596 65.4 103.68 ;
    END
  END s3[8]
  PIN s3[90]
    DIRECTION OUTPUT ;
    USE SIGNAL ;
    PORT
      LAYER M5 ;
        RECT  143.04 103.596 143.064 103.68 ;
    END
  END s3[90]
  PIN s3[91]
    DIRECTION OUTPUT ;
    USE SIGNAL ;
    PORT
      LAYER M5 ;
        RECT  143.088 103.596 143.112 103.68 ;
    END
  END s3[91]
  PIN s3[92]
    DIRECTION OUTPUT ;
    USE SIGNAL ;
    PORT
      LAYER M5 ;
        RECT  143.136 103.596 143.16 103.68 ;
    END
  END s3[92]
  PIN s3[93]
    DIRECTION OUTPUT ;
    USE SIGNAL ;
    PORT
      LAYER M5 ;
        RECT  143.184 103.596 143.208 103.68 ;
    END
  END s3[93]
  PIN s3[94]
    DIRECTION OUTPUT ;
    USE SIGNAL ;
    PORT
      LAYER M5 ;
        RECT  143.232 103.596 143.256 103.68 ;
    END
  END s3[94]
  PIN s3[95]
    DIRECTION OUTPUT ;
    USE SIGNAL ;
    PORT
      LAYER M5 ;
        RECT  92.208 103.596 92.232 103.68 ;
    END
  END s3[95]
  PIN s3[96]
    DIRECTION OUTPUT ;
    USE SIGNAL ;
    PORT
      LAYER M5 ;
        RECT  92.256 103.596 92.28 103.68 ;
    END
  END s3[96]
  PIN s3[97]
    DIRECTION OUTPUT ;
    USE SIGNAL ;
    PORT
      LAYER M5 ;
        RECT  92.304 103.596 92.328 103.68 ;
    END
  END s3[97]
  PIN s3[98]
    DIRECTION OUTPUT ;
    USE SIGNAL ;
    PORT
      LAYER M5 ;
        RECT  92.352 103.596 92.376 103.68 ;
    END
  END s3[98]
  PIN s3[99]
    DIRECTION OUTPUT ;
    USE SIGNAL ;
    PORT
      LAYER M5 ;
        RECT  92.4 103.596 92.424 103.68 ;
    END
  END s3[99]
  PIN s3[9]
    DIRECTION OUTPUT ;
    USE SIGNAL ;
    PORT
      LAYER M5 ;
        RECT  65.424 103.596 65.448 103.68 ;
    END
  END s3[9]
  PIN s3_v
    DIRECTION OUTPUT ;
    USE SIGNAL ;
    PORT
      LAYER M5 ;
        RECT  63.36 103.596 63.384 103.68 ;
    END
  END s3_v
  PIN VDD
    DIRECTION INOUT ;
    USE POWER ;
    PORT
      LAYER M5 ;
        RECT  169.992 2.151 170.112 101.529 ;
        RECT  164.592 2.151 164.712 101.529 ;
        RECT  159.192 2.151 159.312 101.529 ;
        RECT  153.792 2.151 153.912 101.529 ;
        RECT  148.392 2.151 148.512 101.529 ;
        RECT  142.992 2.151 143.112 101.529 ;
        RECT  137.592 2.151 137.712 101.529 ;
        RECT  132.192 2.151 132.312 101.529 ;
        RECT  126.792 2.151 126.912 101.529 ;
        RECT  121.392 2.151 121.512 101.529 ;
        RECT  115.992 2.151 116.112 101.529 ;
        RECT  110.592 2.151 110.712 101.529 ;
        RECT  105.192 2.151 105.312 101.529 ;
        RECT  99.792 2.151 99.912 101.529 ;
        RECT  94.392 2.151 94.512 101.529 ;
        RECT  88.992 2.151 89.112 101.529 ;
        RECT  83.592 2.151 83.712 101.529 ;
        RECT  78.192 2.151 78.312 101.529 ;
        RECT  72.792 2.151 72.912 101.529 ;
        RECT  67.392 2.151 67.512 101.529 ;
        RECT  61.992 2.151 62.112 101.529 ;
        RECT  56.592 2.151 56.712 101.529 ;
        RECT  51.192 2.151 51.312 101.529 ;
        RECT  45.792 2.151 45.912 101.529 ;
        RECT  40.392 2.151 40.512 101.529 ;
        RECT  34.992 2.151 35.112 101.529 ;
        RECT  29.592 2.151 29.712 101.529 ;
        RECT  24.192 2.151 24.312 101.529 ;
        RECT  18.792 2.151 18.912 101.529 ;
        RECT  13.392 2.151 13.512 101.529 ;
        RECT  7.992 2.151 8.112 101.529 ;
        RECT  2.592 2.151 2.712 101.529 ;
    END
  END VDD
  PIN VSS
    DIRECTION INOUT ;
    USE GROUND ;
    PORT
      LAYER M5 ;
        RECT  169.8 2.137 169.92 101.543 ;
        RECT  164.4 2.137 164.52 101.543 ;
        RECT  159 2.137 159.12 101.543 ;
        RECT  153.6 2.137 153.72 101.543 ;
        RECT  148.2 2.137 148.32 101.543 ;
        RECT  142.8 2.137 142.92 101.543 ;
        RECT  137.4 2.137 137.52 101.543 ;
        RECT  132 2.137 132.12 101.543 ;
        RECT  126.6 2.137 126.72 101.543 ;
        RECT  121.2 2.137 121.32 101.543 ;
        RECT  115.8 2.137 115.92 101.543 ;
        RECT  110.4 2.137 110.52 101.543 ;
        RECT  105 2.137 105.12 101.543 ;
        RECT  99.6 2.137 99.72 101.543 ;
        RECT  94.2 2.137 94.32 101.543 ;
        RECT  88.8 2.137 88.92 101.543 ;
        RECT  83.4 2.137 83.52 101.543 ;
        RECT  78 2.137 78.12 101.543 ;
        RECT  72.6 2.137 72.72 101.543 ;
        RECT  67.2 2.137 67.32 101.543 ;
        RECT  61.8 2.137 61.92 101.543 ;
        RECT  56.4 2.137 56.52 101.543 ;
        RECT  51 2.137 51.12 101.543 ;
        RECT  45.6 2.137 45.72 101.543 ;
        RECT  40.2 2.137 40.32 101.543 ;
        RECT  34.8 2.137 34.92 101.543 ;
        RECT  29.4 2.137 29.52 101.543 ;
        RECT  24 2.137 24.12 101.543 ;
        RECT  18.6 2.137 18.72 101.543 ;
        RECT  13.2 2.137 13.32 101.543 ;
        RECT  7.8 2.137 7.92 101.543 ;
        RECT  2.4 2.137 2.52 101.543 ;
    END
  END VSS
  # OT_OBS_CLOSED layer=M5 d_um=1.536 added=1022
  OBS
    LAYER RVTN ;
     RECT  2.16 2.16 170.64 2.295 ;
     RECT  2.16 2.565 170.64 2.835 ;
     RECT  2.16 3.105 170.64 3.375 ;
     RECT  2.16 3.645 170.64 3.915 ;
     RECT  2.16 4.185 170.64 4.455 ;
     RECT  2.16 4.725 170.64 4.995 ;
     RECT  2.16 5.265 170.64 5.535 ;
     RECT  2.16 5.805 170.64 6.075 ;
     RECT  2.16 6.345 170.64 6.615 ;
     RECT  2.16 6.885 170.64 7.155 ;
     RECT  2.16 7.425 170.64 7.695 ;
     RECT  2.16 7.965 170.64 8.235 ;
     RECT  2.16 8.505 170.64 8.775 ;
     RECT  2.16 9.045 170.64 9.315 ;
     RECT  2.16 9.585 170.64 9.855 ;
     RECT  2.16 10.125 170.64 10.395 ;
     RECT  2.16 10.665 170.64 10.935 ;
     RECT  2.16 11.205 170.64 11.475 ;
     RECT  2.16 11.745 170.64 12.015 ;
     RECT  2.16 12.285 170.64 12.555 ;
     RECT  2.16 12.825 170.64 13.095 ;
     RECT  2.16 13.365 170.64 13.635 ;
     RECT  2.16 13.905 170.64 14.175 ;
     RECT  2.16 14.445 170.64 14.715 ;
     RECT  2.16 14.985 170.64 15.255 ;
     RECT  2.16 15.525 170.64 15.795 ;
     RECT  2.16 16.065 170.64 16.335 ;
     RECT  2.16 16.605 170.64 16.875 ;
     RECT  2.16 17.145 170.64 17.415 ;
     RECT  2.16 17.685 170.64 17.955 ;
     RECT  2.16 18.225 170.64 18.495 ;
     RECT  2.16 18.765 170.64 19.035 ;
     RECT  2.16 19.305 170.64 19.575 ;
     RECT  2.16 19.845 170.64 20.115 ;
     RECT  2.16 20.385 170.64 20.655 ;
     RECT  2.16 20.925 170.64 21.195 ;
     RECT  2.16 21.465 170.64 21.735 ;
     RECT  2.16 22.005 170.64 22.275 ;
     RECT  2.16 22.545 170.64 22.815 ;
     RECT  2.16 23.085 170.64 23.355 ;
     RECT  2.16 23.625 170.64 23.895 ;
     RECT  2.16 24.165 170.64 24.435 ;
     RECT  2.16 24.705 170.64 24.975 ;
     RECT  2.16 25.245 170.64 25.515 ;
     RECT  2.16 25.785 170.64 26.055 ;
     RECT  2.16 26.325 170.64 26.595 ;
     RECT  2.16 26.865 170.64 27.135 ;
     RECT  2.16 27.405 170.64 27.675 ;
     RECT  2.16 27.945 170.64 28.215 ;
     RECT  2.16 28.485 170.64 28.755 ;
     RECT  2.16 29.025 170.64 29.295 ;
     RECT  2.16 29.565 170.64 29.835 ;
     RECT  2.16 30.105 170.64 30.375 ;
     RECT  2.16 30.645 170.64 30.915 ;
     RECT  2.16 31.185 170.64 31.455 ;
     RECT  2.16 31.725 170.64 31.995 ;
     RECT  2.16 32.265 170.64 32.535 ;
     RECT  2.16 32.805 170.64 33.075 ;
     RECT  2.16 33.345 170.64 33.615 ;
     RECT  2.16 33.885 170.64 34.155 ;
     RECT  2.16 34.425 170.64 34.695 ;
     RECT  2.16 34.965 170.64 35.235 ;
     RECT  2.16 35.505 170.64 35.775 ;
     RECT  2.16 36.045 170.64 36.315 ;
     RECT  2.16 36.585 170.64 36.855 ;
     RECT  2.16 37.125 170.64 37.395 ;
     RECT  2.16 37.665 170.64 37.935 ;
     RECT  2.16 38.205 170.64 38.475 ;
     RECT  2.16 38.745 170.64 39.015 ;
     RECT  2.16 39.285 170.64 39.555 ;
     RECT  2.16 39.825 170.64 40.095 ;
     RECT  2.16 40.365 170.64 40.635 ;
     RECT  2.16 40.905 170.64 41.175 ;
     RECT  2.16 41.445 170.64 41.715 ;
     RECT  2.16 41.985 170.64 42.255 ;
     RECT  2.16 42.525 170.64 42.795 ;
     RECT  2.16 43.065 170.64 43.335 ;
     RECT  2.16 43.605 170.64 43.875 ;
     RECT  2.16 44.145 170.64 44.415 ;
     RECT  2.16 44.685 170.64 44.955 ;
     RECT  2.16 45.225 170.64 45.495 ;
     RECT  2.16 45.765 170.64 46.035 ;
     RECT  2.16 46.305 170.64 46.575 ;
     RECT  2.16 46.845 170.64 47.115 ;
     RECT  2.16 47.385 170.64 47.655 ;
     RECT  2.16 47.925 170.64 48.195 ;
     RECT  2.16 48.465 170.64 48.735 ;
     RECT  2.16 49.005 170.64 49.275 ;
     RECT  2.16 49.545 170.64 49.815 ;
     RECT  2.16 50.085 170.64 50.355 ;
     RECT  2.16 50.625 170.64 50.895 ;
     RECT  2.16 51.165 170.64 51.435 ;
     RECT  2.16 51.705 170.64 51.975 ;
     RECT  2.16 52.245 170.64 52.515 ;
     RECT  2.16 52.785 170.64 53.055 ;
     RECT  2.16 53.325 170.64 53.595 ;
     RECT  2.16 53.865 170.64 54.135 ;
     RECT  2.16 54.405 170.64 54.675 ;
     RECT  2.16 54.945 170.64 55.215 ;
     RECT  2.16 55.485 170.64 55.755 ;
     RECT  2.16 56.025 170.64 56.295 ;
     RECT  2.16 56.565 170.64 56.835 ;
     RECT  2.16 57.105 170.64 57.375 ;
     RECT  2.16 57.645 170.64 57.915 ;
     RECT  2.16 58.185 170.64 58.455 ;
     RECT  2.16 58.725 170.64 58.995 ;
     RECT  2.16 59.265 170.64 59.535 ;
     RECT  2.16 59.805 170.64 60.075 ;
     RECT  2.16 60.345 170.64 60.615 ;
     RECT  2.16 60.885 170.64 61.155 ;
     RECT  2.16 61.425 170.64 61.695 ;
     RECT  2.16 61.965 170.64 62.235 ;
     RECT  2.16 62.505 170.64 62.775 ;
     RECT  2.16 63.045 170.64 63.315 ;
     RECT  2.16 63.585 170.64 63.855 ;
     RECT  2.16 64.125 170.64 64.395 ;
     RECT  2.16 64.665 170.64 64.935 ;
     RECT  2.16 65.205 170.64 65.475 ;
     RECT  2.16 65.745 170.64 66.015 ;
     RECT  2.16 66.285 170.64 66.555 ;
     RECT  2.16 66.825 170.64 67.095 ;
     RECT  2.16 67.365 170.64 67.635 ;
     RECT  2.16 67.905 170.64 68.175 ;
     RECT  2.16 68.445 170.64 68.715 ;
     RECT  2.16 68.985 170.64 69.255 ;
     RECT  2.16 69.525 170.64 69.795 ;
     RECT  2.16 70.065 170.64 70.335 ;
     RECT  2.16 70.605 170.64 70.875 ;
     RECT  2.16 71.145 170.64 71.415 ;
     RECT  2.16 71.685 170.64 71.955 ;
     RECT  2.16 72.225 170.64 72.495 ;
     RECT  2.16 72.765 170.64 73.035 ;
     RECT  2.16 73.305 170.64 73.575 ;
     RECT  2.16 73.845 170.64 74.115 ;
     RECT  2.16 74.385 170.64 74.655 ;
     RECT  2.16 74.925 170.64 75.195 ;
     RECT  2.16 75.465 170.64 75.735 ;
     RECT  2.16 76.005 170.64 76.275 ;
     RECT  2.16 76.545 170.64 76.815 ;
     RECT  2.16 77.085 170.64 77.355 ;
     RECT  2.16 77.625 170.64 77.895 ;
     RECT  2.16 78.165 170.64 78.435 ;
     RECT  2.16 78.705 170.64 78.975 ;
     RECT  2.16 79.245 170.64 79.515 ;
     RECT  2.16 79.785 170.64 80.055 ;
     RECT  2.16 80.325 170.64 80.595 ;
     RECT  2.16 80.865 170.64 81.135 ;
     RECT  2.16 81.405 170.64 81.675 ;
     RECT  2.16 81.945 170.64 82.215 ;
     RECT  2.16 82.485 170.64 82.755 ;
     RECT  2.16 83.025 170.64 83.295 ;
     RECT  2.16 83.565 170.64 83.835 ;
     RECT  2.16 84.105 170.64 84.375 ;
     RECT  2.16 84.645 170.64 84.915 ;
     RECT  2.16 85.185 170.64 85.455 ;
     RECT  2.16 85.725 170.64 85.995 ;
     RECT  2.16 86.265 170.64 86.535 ;
     RECT  2.16 86.805 170.64 87.075 ;
     RECT  2.16 87.345 170.64 87.615 ;
     RECT  2.16 87.885 170.64 88.155 ;
     RECT  2.16 88.425 170.64 88.695 ;
     RECT  2.16 88.965 170.64 89.235 ;
     RECT  2.16 89.505 170.64 89.775 ;
     RECT  2.16 90.045 170.64 90.315 ;
     RECT  2.16 90.585 170.64 90.855 ;
     RECT  2.16 91.125 170.64 91.395 ;
     RECT  2.16 91.665 170.64 91.935 ;
     RECT  2.16 92.205 170.64 92.475 ;
     RECT  2.16 92.745 170.64 93.015 ;
     RECT  2.16 93.285 170.64 93.555 ;
     RECT  2.16 93.825 170.64 94.095 ;
     RECT  2.16 94.365 170.64 94.635 ;
     RECT  2.16 94.905 170.64 95.175 ;
     RECT  2.16 95.445 170.64 95.715 ;
     RECT  2.16 95.985 170.64 96.255 ;
     RECT  2.16 96.525 170.64 96.795 ;
     RECT  2.16 97.065 170.64 97.335 ;
     RECT  2.16 97.605 170.64 97.875 ;
     RECT  2.16 98.145 170.64 98.415 ;
     RECT  2.16 98.685 170.64 98.955 ;
     RECT  2.16 99.225 170.64 99.495 ;
     RECT  2.16 99.765 170.64 100.035 ;
     RECT  2.16 100.305 170.64 100.575 ;
     RECT  2.16 100.845 170.64 101.115 ;
     RECT  2.16 101.385 170.64 101.52 ;
    LAYER RVTP ;
     RECT  2.16 2.295 170.64 2.565 ;
     RECT  2.16 2.835 170.64 3.105 ;
     RECT  2.16 3.375 170.64 3.645 ;
     RECT  2.16 3.915 170.64 4.185 ;
     RECT  2.16 4.455 170.64 4.725 ;
     RECT  2.16 4.995 170.64 5.265 ;
     RECT  2.16 5.535 170.64 5.805 ;
     RECT  2.16 6.075 170.64 6.345 ;
     RECT  2.16 6.615 170.64 6.885 ;
     RECT  2.16 7.155 170.64 7.425 ;
     RECT  2.16 7.695 170.64 7.965 ;
     RECT  2.16 8.235 170.64 8.505 ;
     RECT  2.16 8.775 170.64 9.045 ;
     RECT  2.16 9.315 170.64 9.585 ;
     RECT  2.16 9.855 170.64 10.125 ;
     RECT  2.16 10.395 170.64 10.665 ;
     RECT  2.16 10.935 170.64 11.205 ;
     RECT  2.16 11.475 170.64 11.745 ;
     RECT  2.16 12.015 170.64 12.285 ;
     RECT  2.16 12.555 170.64 12.825 ;
     RECT  2.16 13.095 170.64 13.365 ;
     RECT  2.16 13.635 170.64 13.905 ;
     RECT  2.16 14.175 170.64 14.445 ;
     RECT  2.16 14.715 170.64 14.985 ;
     RECT  2.16 15.255 170.64 15.525 ;
     RECT  2.16 15.795 170.64 16.065 ;
     RECT  2.16 16.335 170.64 16.605 ;
     RECT  2.16 16.875 170.64 17.145 ;
     RECT  2.16 17.415 170.64 17.685 ;
     RECT  2.16 17.955 170.64 18.225 ;
     RECT  2.16 18.495 170.64 18.765 ;
     RECT  2.16 19.035 170.64 19.305 ;
     RECT  2.16 19.575 170.64 19.845 ;
     RECT  2.16 20.115 170.64 20.385 ;
     RECT  2.16 20.655 170.64 20.925 ;
     RECT  2.16 21.195 170.64 21.465 ;
     RECT  2.16 21.735 170.64 22.005 ;
     RECT  2.16 22.275 170.64 22.545 ;
     RECT  2.16 22.815 170.64 23.085 ;
     RECT  2.16 23.355 170.64 23.625 ;
     RECT  2.16 23.895 170.64 24.165 ;
     RECT  2.16 24.435 170.64 24.705 ;
     RECT  2.16 24.975 170.64 25.245 ;
     RECT  2.16 25.515 170.64 25.785 ;
     RECT  2.16 26.055 170.64 26.325 ;
     RECT  2.16 26.595 170.64 26.865 ;
     RECT  2.16 27.135 170.64 27.405 ;
     RECT  2.16 27.675 170.64 27.945 ;
     RECT  2.16 28.215 170.64 28.485 ;
     RECT  2.16 28.755 170.64 29.025 ;
     RECT  2.16 29.295 170.64 29.565 ;
     RECT  2.16 29.835 170.64 30.105 ;
     RECT  2.16 30.375 170.64 30.645 ;
     RECT  2.16 30.915 170.64 31.185 ;
     RECT  2.16 31.455 170.64 31.725 ;
     RECT  2.16 31.995 170.64 32.265 ;
     RECT  2.16 32.535 170.64 32.805 ;
     RECT  2.16 33.075 170.64 33.345 ;
     RECT  2.16 33.615 170.64 33.885 ;
     RECT  2.16 34.155 170.64 34.425 ;
     RECT  2.16 34.695 170.64 34.965 ;
     RECT  2.16 35.235 170.64 35.505 ;
     RECT  2.16 35.775 170.64 36.045 ;
     RECT  2.16 36.315 170.64 36.585 ;
     RECT  2.16 36.855 170.64 37.125 ;
     RECT  2.16 37.395 170.64 37.665 ;
     RECT  2.16 37.935 170.64 38.205 ;
     RECT  2.16 38.475 170.64 38.745 ;
     RECT  2.16 39.015 170.64 39.285 ;
     RECT  2.16 39.555 170.64 39.825 ;
     RECT  2.16 40.095 170.64 40.365 ;
     RECT  2.16 40.635 170.64 40.905 ;
     RECT  2.16 41.175 170.64 41.445 ;
     RECT  2.16 41.715 170.64 41.985 ;
     RECT  2.16 42.255 170.64 42.525 ;
     RECT  2.16 42.795 170.64 43.065 ;
     RECT  2.16 43.335 170.64 43.605 ;
     RECT  2.16 43.875 170.64 44.145 ;
     RECT  2.16 44.415 170.64 44.685 ;
     RECT  2.16 44.955 170.64 45.225 ;
     RECT  2.16 45.495 170.64 45.765 ;
     RECT  2.16 46.035 170.64 46.305 ;
     RECT  2.16 46.575 170.64 46.845 ;
     RECT  2.16 47.115 170.64 47.385 ;
     RECT  2.16 47.655 170.64 47.925 ;
     RECT  2.16 48.195 170.64 48.465 ;
     RECT  2.16 48.735 170.64 49.005 ;
     RECT  2.16 49.275 170.64 49.545 ;
     RECT  2.16 49.815 170.64 50.085 ;
     RECT  2.16 50.355 170.64 50.625 ;
     RECT  2.16 50.895 170.64 51.165 ;
     RECT  2.16 51.435 170.64 51.705 ;
     RECT  2.16 51.975 170.64 52.245 ;
     RECT  2.16 52.515 170.64 52.785 ;
     RECT  2.16 53.055 170.64 53.325 ;
     RECT  2.16 53.595 170.64 53.865 ;
     RECT  2.16 54.135 170.64 54.405 ;
     RECT  2.16 54.675 170.64 54.945 ;
     RECT  2.16 55.215 170.64 55.485 ;
     RECT  2.16 55.755 170.64 56.025 ;
     RECT  2.16 56.295 170.64 56.565 ;
     RECT  2.16 56.835 170.64 57.105 ;
     RECT  2.16 57.375 170.64 57.645 ;
     RECT  2.16 57.915 170.64 58.185 ;
     RECT  2.16 58.455 170.64 58.725 ;
     RECT  2.16 58.995 170.64 59.265 ;
     RECT  2.16 59.535 170.64 59.805 ;
     RECT  2.16 60.075 170.64 60.345 ;
     RECT  2.16 60.615 170.64 60.885 ;
     RECT  2.16 61.155 170.64 61.425 ;
     RECT  2.16 61.695 170.64 61.965 ;
     RECT  2.16 62.235 170.64 62.505 ;
     RECT  2.16 62.775 170.64 63.045 ;
     RECT  2.16 63.315 170.64 63.585 ;
     RECT  2.16 63.855 170.64 64.125 ;
     RECT  2.16 64.395 170.64 64.665 ;
     RECT  2.16 64.935 170.64 65.205 ;
     RECT  2.16 65.475 170.64 65.745 ;
     RECT  2.16 66.015 170.64 66.285 ;
     RECT  2.16 66.555 170.64 66.825 ;
     RECT  2.16 67.095 170.64 67.365 ;
     RECT  2.16 67.635 170.64 67.905 ;
     RECT  2.16 68.175 170.64 68.445 ;
     RECT  2.16 68.715 170.64 68.985 ;
     RECT  2.16 69.255 170.64 69.525 ;
     RECT  2.16 69.795 170.64 70.065 ;
     RECT  2.16 70.335 170.64 70.605 ;
     RECT  2.16 70.875 170.64 71.145 ;
     RECT  2.16 71.415 170.64 71.685 ;
     RECT  2.16 71.955 170.64 72.225 ;
     RECT  2.16 72.495 170.64 72.765 ;
     RECT  2.16 73.035 170.64 73.305 ;
     RECT  2.16 73.575 170.64 73.845 ;
     RECT  2.16 74.115 170.64 74.385 ;
     RECT  2.16 74.655 170.64 74.925 ;
     RECT  2.16 75.195 170.64 75.465 ;
     RECT  2.16 75.735 170.64 76.005 ;
     RECT  2.16 76.275 170.64 76.545 ;
     RECT  2.16 76.815 170.64 77.085 ;
     RECT  2.16 77.355 170.64 77.625 ;
     RECT  2.16 77.895 170.64 78.165 ;
     RECT  2.16 78.435 170.64 78.705 ;
     RECT  2.16 78.975 170.64 79.245 ;
     RECT  2.16 79.515 170.64 79.785 ;
     RECT  2.16 80.055 170.64 80.325 ;
     RECT  2.16 80.595 170.64 80.865 ;
     RECT  2.16 81.135 170.64 81.405 ;
     RECT  2.16 81.675 170.64 81.945 ;
     RECT  2.16 82.215 170.64 82.485 ;
     RECT  2.16 82.755 170.64 83.025 ;
     RECT  2.16 83.295 170.64 83.565 ;
     RECT  2.16 83.835 170.64 84.105 ;
     RECT  2.16 84.375 170.64 84.645 ;
     RECT  2.16 84.915 170.64 85.185 ;
     RECT  2.16 85.455 170.64 85.725 ;
     RECT  2.16 85.995 170.64 86.265 ;
     RECT  2.16 86.535 170.64 86.805 ;
     RECT  2.16 87.075 170.64 87.345 ;
     RECT  2.16 87.615 170.64 87.885 ;
     RECT  2.16 88.155 170.64 88.425 ;
     RECT  2.16 88.695 170.64 88.965 ;
     RECT  2.16 89.235 170.64 89.505 ;
     RECT  2.16 89.775 170.64 90.045 ;
     RECT  2.16 90.315 170.64 90.585 ;
     RECT  2.16 90.855 170.64 91.125 ;
     RECT  2.16 91.395 170.64 91.665 ;
     RECT  2.16 91.935 170.64 92.205 ;
     RECT  2.16 92.475 170.64 92.745 ;
     RECT  2.16 93.015 170.64 93.285 ;
     RECT  2.16 93.555 170.64 93.825 ;
     RECT  2.16 94.095 170.64 94.365 ;
     RECT  2.16 94.635 170.64 94.905 ;
     RECT  2.16 95.175 170.64 95.445 ;
     RECT  2.16 95.715 170.64 95.985 ;
     RECT  2.16 96.255 170.64 96.525 ;
     RECT  2.16 96.795 170.64 97.065 ;
     RECT  2.16 97.335 170.64 97.605 ;
     RECT  2.16 97.875 170.64 98.145 ;
     RECT  2.16 98.415 170.64 98.685 ;
     RECT  2.16 98.955 170.64 99.225 ;
     RECT  2.16 99.495 170.64 99.765 ;
     RECT  2.16 100.035 170.64 100.305 ;
     RECT  2.16 100.575 170.64 100.845 ;
     RECT  2.16 101.115 170.64 101.385 ;
    LAYER M1 ;
     RECT  2.16 2.151 170.64 101.529 ;
    LAYER M2 ;
     RECT  0.031 66.726 0.067 66.744 ;
     RECT  0.067 41.571 0.103 41.589 ;
     RECT  0.031 46.116 0.103 46.134 ;
     RECT  0.031 58.581 0.103 58.869 ;
     RECT  0.103 31.581 0.139 31.599 ;
     RECT  0.103 41.571 0.139 41.976 ;
     RECT  0.031 57.006 0.139 57.024 ;
     RECT  0.067 57.816 0.139 57.834 ;
     RECT  0.103 58.581 0.139 59.409 ;
     RECT  0.031 60.246 0.139 60.264 ;
     RECT  0.139 41.571 0.167 42.588 ;
     RECT  0.139 57.006 0.167 60.264 ;
     RECT  0.067 44.226 0.175 44.244 ;
     RECT  0.067 62.631 0.175 62.649 ;
     RECT  0.103 63.396 0.175 63.414 ;
     RECT  0.103 46.116 0.203 46.872 ;
     RECT  0.067 66.726 0.203 67.194 ;
     RECT  0.139 31.536 0.211 32.094 ;
     RECT  0.139 69.426 0.211 69.444 ;
     RECT  0.203 46.116 0.239 46.8 ;
     RECT  0.167 58.464 0.239 60.264 ;
     RECT  0.175 40.446 0.247 40.464 ;
     RECT  0.031 61.236 0.247 61.254 ;
     RECT  0.031 34.74 0.275 34.758 ;
     RECT  0.211 31.536 0.283 32.256 ;
     RECT  0.211 69.381 0.283 69.444 ;
     RECT  0.175 33.354 0.311 33.444 ;
     RECT  0.167 41.886 0.311 42.588 ;
     RECT  0.247 61.236 0.347 61.614 ;
     RECT  0.175 62.631 0.383 63.414 ;
     RECT  0.283 31.122 0.391 32.256 ;
     RECT  0.391 31.122 0.419 32.364 ;
     RECT  0.167 57.348 0.419 57.708 ;
     RECT  0.239 46.782 0.455 46.8 ;
     RECT  0.419 57.546 0.455 57.708 ;
     RECT  0.247 40.41 0.499 40.464 ;
     RECT  0.499 40.41 0.535 40.824 ;
     RECT  0.283 68.886 0.535 69.444 ;
     RECT  0.383 62.631 0.563 62.649 ;
     RECT  0.419 31.77 0.571 32.364 ;
     RECT  0.311 33.354 0.571 33.372 ;
     RECT  0.239 58.464 0.599 60.174 ;
     RECT  0.463 38.826 0.823 38.844 ;
     RECT  0.535 40.176 0.859 40.824 ;
     RECT  0.859 39.906 0.895 40.824 ;
     RECT  0.103 51.714 0.895 51.732 ;
     RECT  0.895 39.906 0.995 41.004 ;
     RECT  0.535 55.836 1.471 55.854 ;
     RECT  1.363 47.16 1.507 47.178 ;
     RECT  1.003 65.556 1.507 65.574 ;
     RECT  1.507 47.052 1.579 47.178 ;
     RECT  0.931 48.006 1.579 48.024 ;
     RECT  1.543 64.674 1.579 64.692 ;
     RECT  1.975 52.992 2.011 53.01 ;
     RECT  0.283 53.838 2.011 53.856 ;
     RECT  0.599 58.464 2.047 58.482 ;
     RECT  0.895 51.714 2.155 51.768 ;
     RECT  2.011 52.992 2.155 53.856 ;
     RECT  0.571 31.77 2.16 33.372 ;
     RECT  1.399 37.476 2.16 37.494 ;
     RECT  0.823 38.25 2.16 38.844 ;
     RECT  0.995 39.906 2.16 40.824 ;
     RECT  0.311 42.57 2.16 42.588 ;
     RECT  0.175 44.226 2.16 44.748 ;
     RECT  1.435 45.81 2.16 45.828 ;
     RECT  1.579 47.052 2.16 48.024 ;
     RECT  2.083 49.356 2.16 49.374 ;
     RECT  2.155 51.714 2.16 53.856 ;
     RECT  0.859 54.612 2.16 54.63 ;
     RECT  1.471 55.836 2.16 56.358 ;
     RECT  0.455 57.69 2.16 57.708 ;
     RECT  2.047 58.464 2.16 58.716 ;
     RECT  0.599 59.85 2.16 60.174 ;
     RECT  0.347 61.236 2.16 61.524 ;
     RECT  0.383 63.396 2.16 63.414 ;
     RECT  1.579 64.206 2.16 64.692 ;
     RECT  1.507 65.556 2.16 65.97 ;
     RECT  0.203 67.176 2.16 67.194 ;
     RECT  0.535 68.886 2.16 69.516 ;
     RECT  0.175 70.506 2.16 70.524 ;
     RECT  2.16 2.151 41.503 101.529 ;
     RECT  42.079 102.546 42.179 102.564 ;
     RECT  41.503 1.422 43.411 101.529 ;
     RECT  43.411 1.422 43.547 101.574 ;
     RECT  60.763 102.546 60.835 102.564 ;
     RECT  60.835 102.51 60.935 102.564 ;
     RECT  60.935 102.546 60.971 102.564 ;
     RECT  43.547 1.422 62.123 101.529 ;
     RECT  57.811 0.036 65.263 0.054 ;
     RECT  65.263 0.036 65.911 0.09 ;
     RECT  62.123 2.151 79.987 101.529 ;
     RECT  79.987 2.034 80.375 101.529 ;
     RECT  80.375 2.106 82.291 101.529 ;
     RECT  82.291 2.034 84.631 101.529 ;
     RECT  84.631 1.998 84.955 101.529 ;
     RECT  84.955 1.926 85.883 101.529 ;
     RECT  65.911 0.036 86.683 0.126 ;
     RECT  86.683 0.036 86.719 0.432 ;
     RECT  86.719 0.036 86.819 0.468 ;
     RECT  86.819 0.036 86.855 0.432 ;
     RECT  86.855 0.036 89.131 0.126 ;
     RECT  89.131 0.036 89.231 0.324 ;
     RECT  85.883 1.998 89.339 101.529 ;
     RECT  89.231 0.036 90.499 0.126 ;
     RECT  90.499 0.036 90.599 0.549 ;
     RECT  91.435 102.546 92.551 102.564 ;
     RECT  92.551 102.474 92.795 102.564 ;
     RECT  92.795 102.546 93.371 102.564 ;
     RECT  90.599 0.036 93.947 0.126 ;
     RECT  93.947 0.072 94.199 0.126 ;
     RECT  94.199 0.108 94.235 0.126 ;
     RECT  89.339 2.034 96.035 101.529 ;
     RECT  96.035 2.07 96.107 101.529 ;
     RECT  96.107 2.106 96.179 101.529 ;
     RECT  96.115 0.216 96.323 0.234 ;
     RECT  98.563 0.531 99.743 0.549 ;
     RECT  115.303 102.591 115.339 102.609 ;
     RECT  115.339 102.51 115.439 102.609 ;
     RECT  96.179 2.151 116.239 101.529 ;
     RECT  116.347 102.546 116.519 102.564 ;
     RECT  116.239 2.151 117.419 101.574 ;
     RECT  143.239 102.546 143.843 102.564 ;
     RECT  117.419 2.151 170.64 101.529 ;
    LAYER M3 ;
     RECT  93.924 0.031 93.942 0.067 ;
     RECT  78.732 0.043 78.75 0.091 ;
     RECT  86.112 0.043 86.13 0.091 ;
     RECT  91.908 0.043 91.926 0.091 ;
     RECT  93.924 0.067 94.194 0.091 ;
     RECT  65.268 0.067 65.286 0.103 ;
     RECT  27.108 0.091 27.126 0.139 ;
     RECT  61.92 0.091 61.938 0.139 ;
     RECT  82.656 0.043 82.674 0.139 ;
     RECT  86.112 0.091 86.418 0.139 ;
     RECT  89.28 0.091 89.298 0.139 ;
     RECT  91.62 0.091 91.926 0.139 ;
     RECT  93.456 0.091 94.554 0.139 ;
     RECT  96.084 0.043 96.102 0.139 ;
     RECT  99.864 0.043 99.882 0.139 ;
     RECT  99.756 0.139 99.882 0.173 ;
     RECT  141.516 0.043 141.534 0.173 ;
     RECT  61.272 0.139 61.938 0.187 ;
     RECT  86.04 0.139 86.526 0.187 ;
     RECT  89.172 0.139 90.198 0.187 ;
     RECT  91.044 0.139 91.926 0.187 ;
     RECT  95.976 0.139 96.102 0.187 ;
     RECT  131.22 0.139 131.238 0.187 ;
     RECT  143.964 0.139 143.982 0.187 ;
     RECT  61.272 0.187 62.118 0.235 ;
     RECT  99.756 0.173 99.774 0.235 ;
     RECT  61.164 0.235 62.118 0.269 ;
     RECT  86.04 0.187 87.246 0.283 ;
     RECT  89.172 0.187 91.926 0.283 ;
     RECT  78.66 0.091 78.75 0.317 ;
     RECT  89.136 0.283 91.926 0.329 ;
     RECT  89.172 0.329 91.926 0.331 ;
     RECT  98.604 0.043 98.622 0.331 ;
     RECT  82.08 0.139 82.674 0.379 ;
     RECT  98.568 0.331 98.622 0.379 ;
     RECT  84.924 0.379 84.942 0.427 ;
     RECT  85.824 0.283 87.246 0.427 ;
     RECT  93.348 0.139 95.166 0.427 ;
     RECT  95.976 0.187 96.318 0.427 ;
     RECT  97.992 0.379 98.622 0.427 ;
     RECT  58.716 0.331 58.734 0.461 ;
     RECT  61.992 0.269 62.118 0.461 ;
     RECT  82.08 0.379 82.962 0.475 ;
     RECT  93.348 0.427 96.318 0.475 ;
     RECT  93.348 0.475 96.606 0.509 ;
     RECT  61.164 0.269 61.254 0.523 ;
     RECT  78.732 0.317 78.75 0.523 ;
     RECT  80.028 0.139 80.046 0.523 ;
     RECT  80.964 0.187 80.982 0.523 ;
     RECT  97.74 0.427 98.622 0.523 ;
     RECT  99.36 0.235 99.774 0.523 ;
     RECT  89.172 0.331 91.962 0.557 ;
     RECT  89.172 0.557 91.278 0.605 ;
     RECT  84.924 0.427 87.498 0.763 ;
     RECT  57.816 0.031 57.834 0.859 ;
     RECT  63.252 0.235 63.27 0.907 ;
     RECT  57.816 0.859 57.978 0.955 ;
     RECT  35.64 0.235 35.658 1.003 ;
     RECT  78.732 0.523 80.046 1.051 ;
     RECT  78.624 1.051 80.046 1.099 ;
     RECT  80.856 0.523 80.982 1.099 ;
     RECT  97.74 0.523 99.774 1.099 ;
     RECT  84.924 0.763 88.218 1.147 ;
     RECT  146.376 0.811 146.394 1.147 ;
     RECT  143.352 0.187 143.982 1.195 ;
     RECT  57.816 0.955 58.482 1.387 ;
     RECT  97.704 1.099 99.774 1.387 ;
     RECT  62.028 0.461 62.118 1.445 ;
     RECT  27.036 0.139 27.126 1.483 ;
     RECT  62.964 0.907 63.27 1.483 ;
     RECT  64.116 0.187 64.134 1.483 ;
     RECT  84.348 1.147 88.218 1.723 ;
     RECT  89.208 0.605 91.278 1.723 ;
     RECT  31.644 0.187 31.662 1.963 ;
     RECT  138.24 0.811 138.258 1.963 ;
     RECT  139.356 0.523 139.374 1.963 ;
     RECT  35.64 1.003 35.91 2.011 ;
     RECT  93.348 0.509 93.834 2.101 ;
     RECT  35.568 2.011 35.91 2.143 ;
     RECT  60.696 0.523 61.254 2.143 ;
     RECT  62.028 1.445 62.046 2.143 ;
     RECT  73.152 1.003 73.17 2.143 ;
     RECT  78.624 1.099 80.982 2.143 ;
     RECT  81.9 0.475 82.962 2.143 ;
     RECT  92.628 2.101 93.834 2.143 ;
     RECT  94.572 0.509 96.606 2.143 ;
     RECT  131.22 0.187 131.49 2.143 ;
     RECT  143.352 1.195 144.306 2.143 ;
     RECT  92.628 2.143 96.606 2.263 ;
     RECT  59.616 1.435 59.634 2.299 ;
     RECT  78.015 2.143 80.982 2.299 ;
     RECT  81.9 2.143 83.505 2.299 ;
     RECT  84.348 1.723 91.638 2.299 ;
     RECT  97.704 1.387 99.954 2.371 ;
     RECT  2.415 2.143 2.505 2.413 ;
     RECT  7.815 2.143 7.905 2.413 ;
     RECT  13.215 2.143 13.305 2.413 ;
     RECT  18.615 2.143 18.705 2.413 ;
     RECT  24.015 2.143 24.105 2.413 ;
     RECT  29.415 2.143 29.505 2.413 ;
     RECT  40.215 2.143 40.305 2.413 ;
     RECT  45.615 2.143 45.705 2.413 ;
     RECT  51.015 2.143 51.105 2.413 ;
     RECT  56.415 2.143 56.505 2.413 ;
     RECT  60.696 2.143 62.046 2.413 ;
     RECT  67.215 2.143 67.305 2.413 ;
     RECT  105.015 2.143 105.105 2.413 ;
     RECT  110.415 2.143 110.505 2.413 ;
     RECT  115.815 2.143 115.905 2.413 ;
     RECT  121.215 2.143 121.305 2.413 ;
     RECT  122.04 1.387 122.058 2.413 ;
     RECT  126.615 2.143 126.705 2.413 ;
     RECT  131.22 2.143 132.105 2.413 ;
     RECT  137.415 2.143 137.505 2.413 ;
     RECT  138.24 1.963 139.374 2.413 ;
     RECT  148.215 2.143 148.305 2.413 ;
     RECT  153.615 2.143 153.705 2.413 ;
     RECT  159.015 2.143 159.105 2.413 ;
     RECT  164.415 2.143 164.505 2.413 ;
     RECT  169.815 2.143 169.905 2.413 ;
     RECT  59.616 2.299 59.85 2.533 ;
     RECT  92.52 2.263 96.606 2.533 ;
     RECT  97.704 2.371 100.494 2.533 ;
     RECT  78.015 2.299 91.638 2.605 ;
     RECT  97.704 2.533 100.746 2.641 ;
     RECT  59.616 2.533 59.886 2.731 ;
     RECT  60.696 2.413 62.097 2.731 ;
     RECT  62.964 1.483 64.134 2.731 ;
     RECT  60.696 2.731 64.134 2.831 ;
     RECT  78.015 2.605 91.746 2.839 ;
     RECT  92.52 2.533 96.894 2.839 ;
     RECT  78.015 2.839 96.894 2.911 ;
     RECT  78.015 2.911 96.93 3.073 ;
     RECT  97.704 2.641 100.818 3.073 ;
     RECT  78.015 3.073 100.818 3.173 ;
     RECT  78.015 3.173 100.674 3.245 ;
     RECT  81.9 3.245 100.674 3.299 ;
     RECT  78.015 3.245 80.982 3.335 ;
     RECT  82.26 3.299 100.674 3.407 ;
     RECT  78.015 3.335 80.946 3.605 ;
     RECT  79.128 3.605 80.946 3.965 ;
     RECT  82.26 3.407 100.53 4.019 ;
     RECT  80.028 3.965 80.946 4.081 ;
     RECT  80.028 4.081 81.198 4.109 ;
     RECT  49.284 0.811 49.302 4.219 ;
     RECT  82.26 4.019 100.458 4.487 ;
     RECT  80.172 4.109 81.198 4.955 ;
     RECT  82.26 4.487 100.098 5.071 ;
     RECT  49.284 4.219 49.842 5.341 ;
     RECT  81.936 5.071 100.098 5.459 ;
     RECT  80.172 4.955 80.982 5.531 ;
     RECT  82.26 5.459 100.098 5.531 ;
     RECT  84.42 5.531 100.098 5.567 ;
     RECT  84.42 5.567 99.897 6.035 ;
     RECT  84.492 6.035 99.897 6.341 ;
     RECT  57.816 1.387 58.626 6.379 ;
     RECT  34.815 2.143 35.91 6.511 ;
     RECT  45.615 2.413 45.897 6.511 ;
     RECT  56.415 2.413 56.697 6.511 ;
     RECT  24.015 2.413 24.297 6.523 ;
     RECT  34.704 6.511 35.91 6.557 ;
     RECT  45.504 6.511 45.897 6.557 ;
     RECT  56.304 6.511 56.697 6.557 ;
     RECT  57.816 6.379 58.734 6.557 ;
     RECT  59.616 2.731 59.958 6.719 ;
     RECT  80.172 5.531 80.946 6.817 ;
     RECT  80.064 6.817 80.946 6.845 ;
     RECT  84.492 6.341 86.706 6.989 ;
     RECT  27.036 1.483 27.774 7.147 ;
     RECT  82.26 5.531 83.697 7.231 ;
     RECT  84.492 6.989 86.382 7.231 ;
     RECT  82.26 7.231 86.382 7.435 ;
     RECT  87.48 6.341 99.897 7.691 ;
     RECT  80.856 6.845 80.946 7.771 ;
     RECT  81.936 7.435 86.382 7.771 ;
     RECT  80.856 7.771 86.382 7.889 ;
     RECT  82.26 7.889 86.382 7.933 ;
     RECT  87.48 7.691 95.562 7.933 ;
     RECT  96.588 7.691 99.897 8.159 ;
     RECT  82.26 7.933 95.562 8.465 ;
     RECT  84.492 8.465 95.562 8.501 ;
     RECT  23.004 3.643 23.022 8.815 ;
     RECT  60.696 2.831 62.097 8.843 ;
     RECT  80.856 7.889 81.486 9.041 ;
     RECT  80.064 6.845 80.082 9.121 ;
     RECT  80.856 9.041 81.378 9.121 ;
     RECT  43.452 1.993 43.47 9.391 ;
     RECT  84.528 8.501 95.562 9.481 ;
     RECT  96.588 8.159 96.858 9.481 ;
     RECT  40.215 2.413 40.497 10.027 ;
     RECT  39.348 3.115 39.366 10.123 ;
     RECT  40.215 10.027 40.59 10.157 ;
     RECT  80.064 9.121 81.378 10.471 ;
     RECT  74.016 0.379 74.034 12.235 ;
     RECT  39.024 10.123 39.366 13.339 ;
     RECT  101.736 8.275 101.754 13.945 ;
     RECT  84.528 9.481 96.858 13.973 ;
     RECT  78.015 3.605 78.297 14.215 ;
     RECT  79.128 3.965 79.182 14.215 ;
     RECT  60.732 8.843 62.097 14.521 ;
     RECT  82.26 8.465 83.697 15.215 ;
     RECT  79.92 10.471 81.378 15.979 ;
     RECT  82.332 15.215 83.697 15.979 ;
     RECT  24.015 6.523 24.93 19.075 ;
     RECT  25.668 0.907 25.686 19.075 ;
     RECT  85.824 13.973 96.858 19.103 ;
     RECT  84.528 13.973 84.942 21.901 ;
     RECT  85.824 19.103 86.778 21.901 ;
     RECT  97.74 8.159 99.897 21.965 ;
     RECT  87.876 19.103 96.858 22.271 ;
     RECT  99.036 21.965 99.897 22.891 ;
     RECT  118.836 23.053 118.854 23.629 ;
     RECT  59.616 6.719 59.886 23.701 ;
     RECT  60.696 14.521 62.097 23.701 ;
     RECT  99.036 22.891 100.35 23.947 ;
     RECT  78.015 14.215 79.182 24.331 ;
     RECT  101.736 13.945 101.826 24.331 ;
     RECT  99.036 23.947 100.422 24.359 ;
     RECT  77.652 24.331 79.182 24.431 ;
     RECT  101.16 24.331 101.826 24.637 ;
     RECT  76.428 25.321 76.446 25.411 ;
     RECT  76.356 25.411 76.446 25.591 ;
     RECT  75.636 25.591 76.878 25.861 ;
     RECT  77.652 24.431 78.297 25.861 ;
     RECT  75.636 25.861 78.297 26.257 ;
     RECT  75.492 26.257 78.297 26.519 ;
     RECT  75.492 26.519 77.274 26.555 ;
     RECT  75.492 26.555 77.13 26.627 ;
     RECT  75.492 26.627 76.23 26.663 ;
     RECT  75.492 26.663 75.51 26.717 ;
     RECT  121.215 2.413 122.058 26.761 ;
     RECT  109.476 25.717 109.494 26.825 ;
     RECT  62.964 2.831 64.134 27.671 ;
     RECT  87.876 22.271 96.606 29.093 ;
     RECT  120.672 26.761 122.058 29.461 ;
     RECT  100.62 24.637 101.826 29.525 ;
     RECT  101.16 29.525 101.826 29.939 ;
     RECT  55.404 0.331 55.422 30.811 ;
     RECT  71.064 8.131 71.082 30.811 ;
     RECT  72.615 2.143 73.17 30.811 ;
     RECT  55.404 30.811 55.494 30.839 ;
     RECT  71.064 30.811 71.154 30.839 ;
     RECT  0.396 31.099 0.414 31.117 ;
     RECT  0.288 31.117 0.414 31.147 ;
     RECT  114.912 11.659 114.93 31.147 ;
     RECT  116.856 27.643 116.874 31.147 ;
     RECT  13.215 2.413 13.497 31.243 ;
     RECT  24.015 19.075 25.686 31.243 ;
     RECT  34.815 6.557 35.91 31.243 ;
     RECT  45.615 6.557 45.897 31.243 ;
     RECT  67.215 2.413 67.497 31.243 ;
     RECT  78.015 26.519 78.297 31.243 ;
     RECT  110.415 2.413 110.697 31.243 ;
     RECT  2.415 2.413 2.697 31.261 ;
     RECT  114.588 31.147 114.93 31.277 ;
     RECT  84.528 21.901 86.778 31.289 ;
     RECT  110.304 31.243 110.697 31.289 ;
     RECT  115.815 2.413 116.097 31.387 ;
     RECT  116.856 31.147 117.306 31.387 ;
     RECT  0.288 31.147 0.486 31.435 ;
     RECT  111.744 25.141 111.762 31.435 ;
     RECT  0.144 31.435 0.486 31.576 ;
     RECT  2.304 31.261 2.697 31.627 ;
     RECT  97.74 21.965 98.01 31.627 ;
     RECT  99.036 24.359 99.897 31.627 ;
     RECT  2.304 31.627 2.79 31.657 ;
     RECT  77.112 26.627 77.13 31.723 ;
     RECT  77.904 31.243 78.297 31.723 ;
     RECT  101.736 29.939 101.826 31.723 ;
     RECT  2.304 31.657 2.898 31.757 ;
     RECT  97.74 31.627 99.897 31.757 ;
     RECT  0.108 31.576 0.486 31.765 ;
     RECT  7.815 2.413 8.097 31.867 ;
     RECT  18.615 2.413 18.897 31.867 ;
     RECT  29.415 2.413 29.697 31.867 ;
     RECT  40.215 10.157 40.497 31.867 ;
     RECT  51.015 2.413 51.297 31.867 ;
     RECT  56.415 6.557 56.697 31.867 ;
     RECT  72.615 30.811 73.242 31.867 ;
     RECT  97.74 31.757 98.01 31.867 ;
     RECT  57.816 6.557 58.626 31.915 ;
     RECT  7.704 31.867 8.097 31.919 ;
     RECT  18.504 31.867 18.897 31.919 ;
     RECT  29.304 31.867 29.697 31.919 ;
     RECT  40.104 31.867 40.497 31.919 ;
     RECT  56.304 31.867 56.697 31.919 ;
     RECT  71.136 30.839 71.154 31.927 ;
     RECT  54.648 1.579 54.666 31.963 ;
     RECT  55.476 30.839 55.494 31.963 ;
     RECT  74.016 12.235 74.07 31.999 ;
     RECT  50.904 31.867 51.297 32.071 ;
     RECT  70.524 31.927 71.154 32.071 ;
     RECT  84.528 31.289 85.554 32.161 ;
     RECT  86.364 31.289 86.778 32.161 ;
     RECT  101.736 31.723 102.042 32.161 ;
     RECT  4.536 31.999 4.554 32.189 ;
     RECT  119.664 31.765 119.682 32.197 ;
     RECT  77.112 31.723 78.297 32.225 ;
     RECT  65.268 0.103 65.934 32.233 ;
     RECT  108.036 25.321 108.054 32.233 ;
     RECT  57.816 31.915 58.662 32.269 ;
     RECT  59.616 23.701 62.097 32.269 ;
     RECT  67.104 31.243 67.497 32.269 ;
     RECT  68.292 1.579 68.31 32.269 ;
     RECT  65.268 32.233 66.33 32.305 ;
     RECT  67.104 32.269 68.958 32.305 ;
     RECT  111.744 31.435 112.302 32.305 ;
     RECT  50.724 32.071 51.297 32.333 ;
     RECT  54.648 31.963 55.494 32.341 ;
     RECT  70.452 32.071 71.154 32.341 ;
     RECT  0.108 31.765 0.558 32.347 ;
     RECT  34.704 31.243 35.91 32.431 ;
     RECT  72.504 31.867 73.242 32.431 ;
     RECT  74.016 31.999 74.142 32.431 ;
     RECT  115.815 31.387 117.306 32.431 ;
     RECT  65.268 32.305 68.958 32.443 ;
     RECT  62.964 27.671 63.558 32.467 ;
     RECT  2.304 31.757 2.697 32.477 ;
     RECT  13.104 31.243 13.497 32.477 ;
     RECT  23.904 31.243 25.686 32.477 ;
     RECT  34.632 32.431 35.91 32.477 ;
     RECT  53.46 7.099 53.478 32.491 ;
     RECT  70.38 32.341 71.154 32.539 ;
     RECT  99.036 31.757 99.897 32.539 ;
     RECT  54.612 32.341 55.494 32.575 ;
     RECT  57.816 32.269 62.097 32.575 ;
     RECT  62.964 32.467 63.918 32.575 ;
     RECT  57.816 32.575 63.918 32.611 ;
     RECT  65.268 32.443 69.282 32.611 ;
     RECT  70.272 32.539 71.154 32.611 ;
     RECT  72.504 32.431 74.142 32.635 ;
     RECT  0.108 32.347 0.594 32.639 ;
     RECT  54.612 32.575 55.638 32.701 ;
     RECT  56.415 31.919 56.697 32.701 ;
     RECT  84.528 32.161 86.778 32.731 ;
     RECT  70.236 32.611 71.154 32.737 ;
     RECT  108.036 32.233 108.126 32.737 ;
     RECT  84.492 32.731 86.778 32.773 ;
     RECT  70.2 32.737 71.154 32.809 ;
     RECT  119.664 32.197 119.718 32.809 ;
     RECT  79.92 15.979 83.697 32.827 ;
     RECT  84.456 32.773 86.778 32.827 ;
     RECT  101.304 32.161 102.042 32.837 ;
     RECT  107.568 32.737 108.126 32.845 ;
     RECT  108.864 32.299 108.882 32.845 ;
     RECT  106.02 31.483 106.038 32.873 ;
     RECT  70.164 32.809 71.154 32.881 ;
     RECT  71.892 32.635 74.142 32.881 ;
     RECT  54.612 32.701 56.826 32.971 ;
     RECT  57.816 32.611 69.282 32.971 ;
     RECT  70.164 32.881 74.142 32.971 ;
     RECT  87.948 29.093 96.606 33.007 ;
     RECT  57.816 32.971 74.142 33.043 ;
     RECT  87.66 33.007 96.606 33.043 ;
     RECT  77.112 32.225 77.13 33.067 ;
     RECT  99.036 32.539 100.098 33.067 ;
     RECT  41.508 1.417 41.526 33.079 ;
     RECT  53.46 32.491 53.802 33.079 ;
     RECT  54.612 32.971 57.006 33.079 ;
     RECT  76.716 33.067 77.13 33.079 ;
     RECT  79.164 24.431 79.182 33.079 ;
     RECT  79.92 32.827 86.778 33.079 ;
     RECT  98.892 33.067 100.098 33.079 ;
     RECT  101.304 32.837 102.006 33.079 ;
     RECT  41.508 33.079 41.598 33.107 ;
     RECT  42.948 9.391 43.47 33.107 ;
     RECT  49.068 5.341 49.842 33.115 ;
     RECT  51.015 32.333 51.297 33.115 ;
     RECT  53.46 33.079 57.006 33.115 ;
     RECT  57.78 33.043 74.142 33.115 ;
     RECT  79.164 33.079 86.778 33.115 ;
     RECT  87.516 33.043 96.606 33.115 ;
     RECT  45.504 31.243 45.897 33.151 ;
     RECT  53.46 33.115 74.25 33.163 ;
     RECT  49.068 33.115 51.297 33.241 ;
     RECT  75.708 33.079 77.13 33.241 ;
     RECT  115.815 32.431 117.594 33.241 ;
     RECT  52.344 33.241 52.362 33.277 ;
     RECT  49.068 33.241 51.354 33.313 ;
     RECT  52.344 33.277 52.47 33.313 ;
     RECT  75.708 33.241 77.166 33.313 ;
     RECT  49.068 33.313 52.47 33.349 ;
     RECT  75.204 33.313 77.166 33.349 ;
     RECT  78.015 32.225 78.297 33.349 ;
     RECT  79.164 33.115 96.606 33.349 ;
     RECT  97.596 31.867 98.01 33.349 ;
     RECT  45.036 33.151 45.897 33.377 ;
     RECT  79.164 33.349 98.01 33.377 ;
     RECT  79.164 33.377 86.85 33.385 ;
     RECT  105.015 2.413 105.297 33.385 ;
     RECT  75.204 33.349 78.39 33.403 ;
     RECT  49.068 33.349 52.578 33.421 ;
     RECT  53.46 33.163 74.322 33.421 ;
     RECT  118.656 23.629 118.854 33.421 ;
     RECT  119.628 32.809 119.718 33.421 ;
     RECT  0.108 32.639 0.306 33.449 ;
     RECT  75.168 33.403 78.39 33.547 ;
     RECT  47.448 33.547 47.466 33.583 ;
     RECT  49.068 33.421 74.322 33.583 ;
     RECT  75.132 33.547 78.39 33.583 ;
     RECT  47.448 33.583 78.39 33.619 ;
     RECT  79.128 33.385 86.85 33.619 ;
     RECT  98.892 33.079 102.006 33.655 ;
     RECT  103.356 32.611 103.374 33.655 ;
     RECT  107.568 32.845 108.882 33.781 ;
     RECT  45.615 33.377 45.897 33.817 ;
     RECT  107.568 33.781 108.918 33.817 ;
     RECT  45.615 33.817 46.35 33.853 ;
     RECT  45.615 33.853 46.53 33.889 ;
     RECT  47.448 33.619 86.85 33.889 ;
     RECT  98.892 33.655 103.374 33.889 ;
     RECT  104.328 33.385 105.297 33.889 ;
     RECT  114.912 31.277 114.93 33.961 ;
     RECT  87.588 33.377 98.01 34.051 ;
     RECT  98.892 33.889 105.297 34.051 ;
     RECT  107.568 33.817 109.026 34.087 ;
     RECT  45.615 33.889 86.85 34.123 ;
     RECT  107.568 34.087 109.278 34.123 ;
     RECT  107.136 34.123 109.278 34.159 ;
     RECT  107.136 34.159 109.386 34.171 ;
     RECT  44.892 34.123 86.85 34.195 ;
     RECT  87.588 34.051 105.297 34.195 ;
     RECT  107.136 34.171 109.458 34.195 ;
     RECT  124.308 33.853 124.326 34.195 ;
     RECT  114.912 33.961 115.002 34.231 ;
     RECT  115.815 33.241 117.81 34.231 ;
     RECT  110.415 31.289 110.697 34.321 ;
     RECT  44.892 34.195 105.297 34.349 ;
     RECT  106.524 34.195 109.458 34.393 ;
     RECT  110.376 34.321 110.697 34.393 ;
     RECT  44.892 34.349 83.697 34.465 ;
     RECT  114.912 34.231 117.81 34.465 ;
     RECT  43.02 33.107 43.47 34.501 ;
     RECT  44.46 34.465 83.697 34.501 ;
     RECT  106.524 34.393 110.697 34.501 ;
     RECT  134.784 0.091 134.802 34.501 ;
     RECT  106.488 34.501 110.697 34.591 ;
     RECT  111.744 32.305 112.374 34.591 ;
     RECT  0.108 33.449 0.27 34.735 ;
     RECT  0.036 34.735 0.27 34.763 ;
     RECT  37.404 5.995 37.422 34.771 ;
     RECT  84.456 34.349 105.297 34.771 ;
     RECT  106.488 34.591 112.374 34.771 ;
     RECT  114.804 34.465 117.81 34.771 ;
     RECT  37.404 34.771 37.53 34.799 ;
     RECT  13.215 32.477 13.497 35.032 ;
     RECT  24.015 32.477 25.686 35.032 ;
     RECT  34.815 32.477 35.91 35.032 ;
     RECT  13.104 35.032 13.497 35.069 ;
     RECT  23.904 35.032 25.686 35.069 ;
     RECT  34.704 35.032 35.91 35.069 ;
     RECT  114.804 34.771 117.882 35.069 ;
     RECT  84.456 34.771 112.374 35.195 ;
     RECT  0.036 34.763 0.198 35.261 ;
     RECT  84.6 35.195 112.374 35.275 ;
     RECT  113.112 31.147 113.13 35.275 ;
     RECT  84.6 35.275 113.13 35.311 ;
     RECT  84.6 35.311 113.454 35.357 ;
     RECT  43.02 34.501 83.697 35.401 ;
     RECT  84.6 35.357 87.066 35.429 ;
     RECT  42.948 35.401 83.697 35.437 ;
     RECT  84.744 35.429 87.066 35.537 ;
     RECT  84.78 35.537 87.066 35.573 ;
     RECT  42.84 35.437 83.697 35.581 ;
     RECT  87.804 35.357 113.454 35.581 ;
     RECT  42.588 35.581 83.697 35.609 ;
     RECT  87.804 35.581 113.526 35.659 ;
     RECT  87.804 35.659 113.634 35.779 ;
     RECT  34.815 35.069 35.91 35.851 ;
     RECT  42.588 35.609 46.854 36.077 ;
     RECT  84.816 35.573 87.066 36.085 ;
     RECT  87.804 35.779 113.742 36.085 ;
     RECT  41.58 33.107 41.598 36.121 ;
     RECT  42.588 36.077 46.746 36.121 ;
     RECT  84.816 36.085 113.742 36.121 ;
     RECT  114.804 35.069 114.93 36.121 ;
     RECT  37.512 34.799 37.53 36.211 ;
     RECT  38.448 13.339 39.366 36.211 ;
     RECT  84.816 36.121 114.93 36.283 ;
     RECT  115.815 35.069 117.882 36.283 ;
     RECT  47.592 35.609 83.697 36.355 ;
     RECT  34.815 35.851 36.486 36.517 ;
     RECT  37.512 36.211 39.366 36.517 ;
     RECT  41.58 36.121 46.746 36.653 ;
     RECT  44.424 36.653 46.746 36.823 ;
     RECT  47.484 36.355 83.697 36.823 ;
     RECT  34.815 36.517 39.366 36.931 ;
     RECT  40.215 31.919 40.497 36.931 ;
     RECT  41.58 36.653 43.686 36.931 ;
     RECT  44.424 36.823 83.697 36.931 ;
     RECT  84.816 36.283 117.882 36.931 ;
     RECT  44.424 36.931 117.882 37.037 ;
     RECT  34.815 36.931 40.497 37.057 ;
     RECT  41.22 36.931 43.686 37.057 ;
     RECT  124.308 34.195 124.722 37.085 ;
     RECT  34.815 37.057 43.686 37.147 ;
     RECT  33.48 2.539 33.498 37.363 ;
     RECT  30.456 1.531 30.474 37.399 ;
     RECT  31.212 1.963 31.662 37.399 ;
     RECT  33.48 37.363 33.93 37.435 ;
     RECT  34.704 37.147 43.686 37.435 ;
     RECT  29.415 31.919 29.697 37.561 ;
     RECT  30.456 37.399 31.662 37.561 ;
     RECT  118.656 33.421 119.718 37.597 ;
     RECT  120.528 29.461 122.058 37.597 ;
     RECT  32.832 37.435 43.686 37.633 ;
     RECT  22.5 8.815 23.022 37.669 ;
     RECT  32.544 37.633 43.686 37.669 ;
     RECT  44.424 37.037 106.362 37.669 ;
     RECT  29.415 37.561 31.662 37.741 ;
     RECT  107.1 37.037 117.882 37.741 ;
     RECT  29.088 37.741 31.662 37.831 ;
     RECT  32.544 37.669 106.362 37.831 ;
     RECT  29.088 37.831 106.362 37.867 ;
     RECT  107.1 37.741 117.918 37.867 ;
     RECT  28.98 37.867 117.918 38.011 ;
     RECT  118.656 37.597 122.058 38.011 ;
     RECT  28.98 38.011 122.058 38.173 ;
     RECT  1.404 37.471 1.422 38.245 ;
     RECT  28.8 38.173 122.058 38.245 ;
     RECT  27.036 7.147 28.026 38.281 ;
     RECT  28.764 38.245 122.058 38.281 ;
     RECT  0.036 35.261 0.054 38.525 ;
     RECT  2.415 32.477 2.697 38.539 ;
     RECT  2.415 38.539 2.79 38.717 ;
     RECT  135.9 32.731 135.918 38.749 ;
     RECT  141.732 1.675 141.75 38.749 ;
     RECT  141.732 38.749 141.822 38.777 ;
     RECT  0.828 38.245 1.422 38.821 ;
     RECT  21.996 37.669 23.022 38.821 ;
     RECT  24.015 35.069 25.686 38.821 ;
     RECT  124.38 37.085 124.722 38.821 ;
     RECT  24.015 38.821 26.19 38.947 ;
     RECT  124.02 38.821 124.722 38.947 ;
     RECT  128.088 35.041 128.106 38.947 ;
     RECT  128.088 38.947 128.718 39.019 ;
     RECT  21.996 38.821 23.058 39.055 ;
     RECT  128.088 39.019 128.754 39.055 ;
     RECT  24.015 38.947 26.298 39.091 ;
     RECT  27.036 38.281 122.058 39.091 ;
     RECT  123.3 38.947 124.722 39.091 ;
     RECT  131.22 2.413 132.297 39.325 ;
     RECT  24.015 39.091 122.058 39.353 ;
     RECT  123.084 39.091 124.722 39.355 ;
     RECT  125.46 39.325 125.55 39.355 ;
     RECT  128.088 39.055 129.438 39.361 ;
     RECT  123.084 39.355 125.55 39.451 ;
     RECT  126.615 2.413 126.897 39.451 ;
     RECT  127.908 39.361 129.438 39.451 ;
     RECT  131.22 39.325 132.57 39.451 ;
     RECT  135.828 38.749 135.918 39.451 ;
     RECT  24.015 39.353 43.254 39.515 ;
     RECT  21.996 39.055 23.094 39.523 ;
     RECT  44.064 39.353 122.058 39.523 ;
     RECT  123.084 39.451 126.897 39.523 ;
     RECT  24.015 39.515 43.074 39.56 ;
     RECT  130.824 39.451 132.57 39.595 ;
     RECT  130.752 39.595 132.57 39.631 ;
     RECT  0.468 38.821 1.422 39.739 ;
     RECT  24.015 39.56 43.038 39.749 ;
     RECT  130.644 39.631 132.57 39.757 ;
     RECT  133.308 39.631 133.326 39.757 ;
     RECT  21.996 39.523 23.166 39.829 ;
     RECT  134.784 34.501 135.018 39.829 ;
     RECT  135.828 39.451 135.99 39.865 ;
     RECT  21.996 39.829 23.238 39.901 ;
     RECT  130.644 39.757 133.326 39.901 ;
     RECT  134.604 39.829 135.018 39.901 ;
     RECT  135.828 39.865 136.134 39.901 ;
     RECT  135.828 39.901 136.206 40.027 ;
     RECT  44.064 39.523 126.897 40.135 ;
     RECT  134.46 39.901 135.018 40.135 ;
     RECT  127.908 39.451 129.654 40.171 ;
     RECT  130.428 39.901 133.326 40.171 ;
     RECT  24.015 39.749 43.002 40.199 ;
     RECT  21.996 39.901 23.274 40.261 ;
     RECT  24.015 40.199 31.986 40.261 ;
     RECT  44.064 40.135 126.954 40.261 ;
     RECT  127.908 40.171 133.326 40.289 ;
     RECT  135.828 40.027 136.314 40.333 ;
     RECT  43.992 40.261 126.954 40.363 ;
     RECT  140.472 40.027 140.49 40.369 ;
     RECT  141.804 38.777 141.822 40.369 ;
     RECT  134.172 40.135 135.018 40.441 ;
     RECT  135.828 40.333 136.53 40.441 ;
     RECT  0.144 39.739 1.422 40.469 ;
     RECT  13.215 35.069 13.497 40.531 ;
     RECT  137.415 2.413 139.374 40.531 ;
     RECT  142.815 2.143 144.306 40.531 ;
     RECT  18.615 31.919 18.897 40.567 ;
     RECT  43.992 40.363 126.99 40.567 ;
     RECT  134.172 40.441 136.53 40.567 ;
     RECT  137.376 40.531 139.59 40.567 ;
     RECT  13.104 40.531 13.497 40.603 ;
     RECT  43.884 40.567 126.99 40.603 ;
     RECT  134.136 40.567 139.59 40.603 ;
     RECT  140.472 40.369 141.822 40.603 ;
     RECT  130.572 40.289 133.326 40.631 ;
     RECT  13.104 40.603 13.842 40.639 ;
     RECT  21.168 40.531 21.186 40.639 ;
     RECT  2.415 38.717 2.697 40.675 ;
     RECT  21.168 40.639 21.222 40.675 ;
     RECT  134.136 40.603 141.822 40.675 ;
     RECT  142.668 40.531 144.306 40.675 ;
     RECT  21.132 40.675 21.222 40.699 ;
     RECT  2.415 40.675 2.862 40.829 ;
     RECT  32.76 40.199 43.002 40.837 ;
     RECT  43.884 40.603 127.026 40.837 ;
     RECT  17.028 40.801 17.442 40.873 ;
     RECT  13.068 40.639 13.842 40.909 ;
     RECT  0.144 40.469 1.062 40.925 ;
     RECT  12.132 40.945 12.15 40.981 ;
     RECT  13.068 40.909 14.166 40.981 ;
     RECT  0.144 40.925 0.99 41.009 ;
     RECT  0.144 41.009 0.918 41.021 ;
     RECT  12.132 40.981 14.166 41.021 ;
     RECT  17.028 40.873 17.658 41.071 ;
     RECT  32.76 40.837 127.026 41.071 ;
     RECT  18.615 40.567 19.566 41.107 ;
     RECT  21.096 40.699 21.222 41.107 ;
     RECT  21.996 40.261 31.986 41.107 ;
     RECT  32.724 41.071 127.026 41.107 ;
     RECT  127.908 40.289 129.798 41.107 ;
     RECT  12.564 41.021 14.166 41.143 ;
     RECT  15.948 41.071 17.838 41.143 ;
     RECT  21.096 41.107 127.026 41.143 ;
     RECT  131.112 40.631 133.326 41.215 ;
     RECT  134.136 40.675 144.306 41.215 ;
     RECT  18.615 41.107 20.214 41.251 ;
     RECT  21.096 41.143 127.062 41.251 ;
     RECT  12.564 41.143 14.526 41.279 ;
     RECT  7.815 31.919 8.097 41.341 ;
     RECT  18.615 41.251 127.062 41.377 ;
     RECT  127.908 41.107 130.374 41.377 ;
     RECT  18.615 41.377 130.374 41.405 ;
     RECT  9.684 41.179 10.278 41.413 ;
     RECT  18.615 41.405 126.897 41.449 ;
     RECT  2.415 40.829 2.697 41.512 ;
     RECT  12.852 41.279 14.526 41.521 ;
     RECT  15.264 41.143 17.838 41.521 ;
     RECT  0.144 41.021 0.882 41.566 ;
     RECT  12.852 41.521 17.838 41.639 ;
     RECT  9.684 41.413 10.386 41.647 ;
     RECT  7.815 41.341 8.154 41.719 ;
     RECT  127.656 41.405 130.374 41.719 ;
     RECT  131.112 41.215 144.306 41.719 ;
     RECT  9.576 41.647 10.386 41.755 ;
     RECT  7.704 41.719 8.154 41.917 ;
     RECT  18.576 41.449 126.897 42.061 ;
     RECT  12.852 41.639 17.694 42.139 ;
     RECT  18.468 42.061 126.897 42.181 ;
     RECT  127.656 41.719 144.306 42.181 ;
     RECT  12.204 42.139 17.694 42.223 ;
     RECT  7.416 41.917 8.154 42.295 ;
     RECT  146.016 1.147 146.394 42.295 ;
     RECT  7.38 42.295 8.154 42.331 ;
     RECT  5.148 42.421 5.166 42.475 ;
     RECT  12.06 42.223 17.694 42.475 ;
     RECT  18.468 42.181 144.306 42.475 ;
     RECT  0.072 41.566 0.882 42.523 ;
     RECT  9.144 41.755 10.386 42.601 ;
     RECT  145.044 0.043 145.062 42.601 ;
     RECT  145.8 42.295 146.394 42.601 ;
     RECT  7.38 42.331 8.334 42.715 ;
     RECT  3.888 42.571 3.906 42.719 ;
     RECT  2.304 41.512 2.697 42.755 ;
     RECT  7.344 42.715 8.334 42.763 ;
     RECT  9.144 42.601 10.566 42.763 ;
     RECT  12.06 42.475 144.306 42.763 ;
     RECT  145.044 42.601 146.394 42.763 ;
     RECT  5.148 42.475 5.202 42.799 ;
     RECT  12.06 42.763 146.466 42.835 ;
     RECT  7.272 42.763 10.566 42.952 ;
     RECT  6.48 42.871 6.498 42.961 ;
     RECT  6.372 42.961 6.498 42.997 ;
     RECT  7.272 42.952 10.854 42.997 ;
     RECT  11.844 42.835 146.466 42.997 ;
     RECT  6.372 42.997 10.854 43.033 ;
     RECT  11.808 42.997 146.466 43.069 ;
     RECT  5.04 42.799 5.202 43.105 ;
     RECT  5.04 43.105 5.238 43.141 ;
     RECT  6.192 43.033 10.854 43.141 ;
     RECT  5.04 43.141 10.854 43.267 ;
     RECT  4.68 43.267 10.854 43.295 ;
     RECT  6.156 43.295 10.854 43.303 ;
     RECT  11.628 43.069 146.466 43.373 ;
     RECT  6.156 43.303 10.89 43.387 ;
     RECT  11.628 43.373 14.526 43.387 ;
     RECT  4.68 43.295 4.698 43.501 ;
     RECT  6.156 43.387 14.526 43.529 ;
     RECT  148.215 2.413 148.497 43.537 ;
     RECT  6.192 43.529 14.526 44.107 ;
     RECT  15.372 43.373 146.466 44.107 ;
     RECT  6.192 44.107 146.466 44.141 ;
     RECT  4.464 43.501 4.698 44.185 ;
     RECT  15.48 44.141 146.466 44.221 ;
     RECT  0.072 42.523 1.494 44.249 ;
     RECT  15.48 44.221 146.502 44.299 ;
     RECT  15.48 44.299 146.574 44.375 ;
     RECT  2.415 42.755 2.697 44.443 ;
     RECT  6.192 44.141 14.742 44.443 ;
     RECT  5.724 44.443 14.742 44.483 ;
     RECT  2.415 44.443 2.898 44.491 ;
     RECT  4.464 44.185 4.77 44.491 ;
     RECT  5.724 44.483 14.562 44.491 ;
     RECT  15.516 44.375 146.574 44.653 ;
     RECT  4.176 44.491 14.562 44.725 ;
     RECT  15.516 44.653 146.718 44.725 ;
     RECT  3.996 44.725 14.562 44.753 ;
     RECT  2.415 44.491 3.222 44.761 ;
     RECT  3.996 44.753 14.526 44.761 ;
     RECT  2.415 44.761 14.526 45.023 ;
     RECT  15.516 44.725 146.862 45.031 ;
     RECT  149.832 44.419 149.85 45.193 ;
     RECT  15.516 45.031 147.222 45.265 ;
     RECT  15.48 45.265 147.222 45.301 ;
     RECT  15.48 45.301 147.294 45.391 ;
     RECT  149.832 45.193 150.282 45.463 ;
     RECT  3.996 45.023 14.526 45.493 ;
     RECT  15.444 45.391 147.294 45.493 ;
     RECT  0.108 44.249 1.494 45.643 ;
     RECT  148.215 43.537 148.698 45.697 ;
     RECT  3.996 45.493 147.294 45.769 ;
     RECT  148.215 45.697 148.734 45.769 ;
     RECT  0.072 45.643 1.494 45.787 ;
     RECT  2.415 45.023 3.258 45.787 ;
     RECT  3.996 45.769 148.734 45.841 ;
     RECT  149.58 45.463 150.282 45.841 ;
     RECT  0.072 45.787 3.258 45.931 ;
     RECT  3.996 45.841 150.282 45.931 ;
     RECT  0.072 45.931 150.282 46.111 ;
     RECT  0.036 46.111 150.282 46.337 ;
     RECT  0.036 46.337 14.382 46.607 ;
     RECT  15.444 46.337 150.282 46.607 ;
     RECT  15.516 46.607 150.282 47.075 ;
     RECT  15.552 47.075 150.282 47.821 ;
     RECT  15.408 47.821 150.534 47.893 ;
     RECT  15.084 47.893 150.534 48.071 ;
     RECT  0.036 46.607 14.238 48.091 ;
     RECT  15.012 48.071 150.534 48.127 ;
     RECT  0.036 48.091 14.274 48.163 ;
     RECT  15.012 48.127 150.57 48.163 ;
     RECT  0.036 48.163 150.57 48.235 ;
     RECT  0.036 48.235 150.606 48.271 ;
     RECT  0.036 48.271 151.146 48.533 ;
     RECT  151.236 48.541 151.254 48.695 ;
     RECT  0.036 48.533 150.498 49.477 ;
     RECT  0.036 49.477 151.074 50.009 ;
     RECT  0.036 50.009 150.678 51.061 ;
     RECT  0.036 51.061 150.93 51.205 ;
     RECT  0.036 51.205 151.182 51.307 ;
     RECT  153.615 2.413 153.897 51.475 ;
     RECT  153.615 51.475 154.278 51.511 ;
     RECT  153.615 51.511 154.458 51.601 ;
     RECT  155.196 51.511 155.214 51.601 ;
     RECT  0.036 51.307 151.434 51.673 ;
     RECT  153.615 51.601 155.214 51.739 ;
     RECT  0.036 51.673 151.686 51.773 ;
     RECT  153.576 51.739 155.214 51.781 ;
     RECT  0.072 51.773 151.686 51.871 ;
     RECT  153.576 51.781 155.79 51.871 ;
     RECT  159.015 2.413 159.297 51.871 ;
     RECT  158.544 51.871 159.297 51.907 ;
     RECT  153.432 51.871 156.294 51.943 ;
     RECT  153.144 51.943 156.294 51.979 ;
     RECT  158.544 51.907 159.39 51.979 ;
     RECT  163.332 51.907 163.35 51.979 ;
     RECT  152.784 51.979 156.294 52.015 ;
     RECT  160.704 51.907 160.722 52.015 ;
     RECT  163.224 51.979 163.35 52.015 ;
     RECT  157.356 51.943 157.374 52.051 ;
     RECT  158.472 51.979 159.39 52.051 ;
     RECT  160.704 52.015 160.758 52.051 ;
     RECT  161.712 51.907 161.73 52.051 ;
     RECT  162.468 51.907 162.486 52.051 ;
     RECT  160.704 52.051 162.486 52.141 ;
     RECT  152.784 52.015 156.33 52.177 ;
     RECT  152.784 52.177 156.474 52.213 ;
     RECT  152.748 52.213 156.474 52.249 ;
     RECT  157.356 52.051 159.39 52.249 ;
     RECT  160.524 52.141 162.486 52.285 ;
     RECT  0.072 51.871 152.01 52.321 ;
     RECT  152.748 52.249 159.39 52.321 ;
     RECT  160.488 52.285 162.486 52.321 ;
     RECT  163.224 52.015 163.386 52.321 ;
     RECT  0.072 52.321 159.39 52.447 ;
     RECT  160.488 52.321 163.386 52.447 ;
     RECT  0.072 52.447 163.386 52.591 ;
     RECT  0.072 52.591 163.458 52.681 ;
     RECT  164.415 2.413 164.697 52.825 ;
     RECT  0.072 52.681 163.566 52.987 ;
     RECT  164.304 52.825 165.006 53.131 ;
     RECT  0.036 52.987 163.566 53.227 ;
     RECT  164.304 53.131 165.33 53.227 ;
     RECT  0.036 53.227 165.33 53.257 ;
     RECT  0.036 53.257 165.618 53.293 ;
     RECT  0.036 53.293 165.726 53.393 ;
     RECT  133.092 53.393 165.726 53.555 ;
     RECT  133.164 53.555 165.726 53.563 ;
     RECT  133.164 53.563 165.942 53.833 ;
     RECT  133.164 53.833 166.626 54.175 ;
     RECT  0.036 53.393 132.297 54.301 ;
     RECT  0.036 54.301 132.354 54.571 ;
     RECT  133.164 54.175 167.022 54.571 ;
     RECT  0.036 54.571 167.022 54.599 ;
     RECT  0.036 54.599 166.842 55.283 ;
     RECT  0.036 55.283 136.17 56.371 ;
     RECT  137.124 55.283 166.698 56.371 ;
     RECT  0.036 56.371 166.698 57.029 ;
     RECT  0.108 57.029 166.698 57.181 ;
     RECT  0.108 57.181 167.094 57.335 ;
     RECT  4.5 57.335 167.094 57.403 ;
     RECT  168.12 57.019 168.138 57.403 ;
     RECT  4.5 57.403 168.138 57.569 ;
     RECT  0.108 57.335 3.33 57.811 ;
     RECT  0.072 57.811 3.33 58.576 ;
     RECT  4.5 57.569 167.886 58.657 ;
     RECT  168.804 58.531 168.822 58.657 ;
     RECT  4.5 58.657 168.822 58.685 ;
     RECT  4.5 58.685 6.39 58.699 ;
     RECT  7.308 58.685 168.822 58.721 ;
     RECT  0.036 58.576 3.33 58.801 ;
     RECT  4.356 58.699 6.39 58.801 ;
     RECT  7.308 58.721 168.318 58.829 ;
     RECT  0.036 58.801 6.39 59.431 ;
     RECT  7.308 58.829 167.922 59.431 ;
     RECT  0.036 59.431 167.922 60.007 ;
     RECT  0.036 60.007 168.282 60.151 ;
     RECT  0.036 60.151 168.822 60.269 ;
     RECT  0.072 60.269 168.822 60.413 ;
     RECT  0.072 60.413 168.246 61.231 ;
     RECT  0.036 61.231 168.246 62.509 ;
     RECT  0.036 62.509 168.498 63.419 ;
     RECT  0.036 63.419 166.122 64.049 ;
     RECT  167.004 63.419 168.498 64.165 ;
     RECT  167.004 64.165 168.534 64.201 ;
     RECT  138.96 64.049 166.122 64.229 ;
     RECT  138.96 64.229 158.094 64.301 ;
     RECT  167.004 64.201 168.606 64.561 ;
     RECT  139.104 64.301 158.094 64.589 ;
     RECT  166.968 64.561 168.606 64.733 ;
     RECT  139.104 64.589 155.862 64.769 ;
     RECT  158.868 64.229 166.122 64.891 ;
     RECT  166.968 64.733 167.922 64.891 ;
     RECT  0.036 64.049 138.222 65.101 ;
     RECT  156.744 64.589 158.094 65.281 ;
     RECT  158.868 64.891 167.922 65.281 ;
     RECT  168.66 64.939 168.678 65.371 ;
     RECT  156.744 65.281 167.922 65.399 ;
     RECT  0.036 65.101 138.294 65.407 ;
     RECT  139.104 64.769 155.718 65.407 ;
     RECT  168.66 65.371 169.002 65.549 ;
     RECT  156.744 65.399 166.122 65.551 ;
     RECT  166.896 65.399 167.922 65.551 ;
     RECT  168.66 65.549 168.678 65.551 ;
     RECT  156.672 65.551 166.122 65.677 ;
     RECT  0.036 65.407 155.718 65.911 ;
     RECT  156.6 65.677 166.122 65.911 ;
     RECT  166.896 65.551 168.678 65.939 ;
     RECT  0.036 65.911 166.122 66.047 ;
     RECT  166.896 65.939 168.606 66.361 ;
     RECT  0.036 66.047 166.05 66.389 ;
     RECT  166.788 66.361 168.606 66.479 ;
     RECT  4.32 66.389 166.05 66.659 ;
     RECT  0.036 66.389 3.546 66.749 ;
     RECT  4.68 66.659 166.05 66.785 ;
     RECT  166.932 66.479 168.606 66.793 ;
     RECT  4.824 66.785 166.014 66.929 ;
     RECT  4.824 66.929 159.714 67.019 ;
     RECT  160.488 66.929 166.014 67.163 ;
     RECT  5.148 67.019 159.714 67.181 ;
     RECT  0.072 66.749 3.546 67.199 ;
     RECT  166.932 66.793 168.714 67.567 ;
     RECT  166.86 67.567 168.714 67.595 ;
     RECT  5.436 67.181 159.714 67.675 ;
     RECT  160.488 67.163 165.978 67.675 ;
     RECT  5.436 67.675 165.978 67.981 ;
     RECT  5.436 67.981 166.05 68.143 ;
     RECT  5.364 68.143 166.05 68.251 ;
     RECT  4.5 68.071 4.518 68.347 ;
     RECT  4.356 68.347 4.518 68.369 ;
     RECT  166.86 67.595 168.174 68.639 ;
     RECT  4.356 68.369 4.374 68.675 ;
     RECT  166.86 68.639 168.03 68.783 ;
     RECT  5.292 68.251 166.05 68.791 ;
     RECT  166.86 68.783 167.418 68.791 ;
     RECT  5.292 68.791 167.418 68.945 ;
     RECT  11.592 68.945 167.418 68.957 ;
     RECT  0.18 67.199 3.546 68.981 ;
     RECT  5.292 68.945 10.854 68.981 ;
     RECT  7.056 68.981 10.854 69.215 ;
     RECT  0.18 68.981 3.33 69.404 ;
     RECT  0.18 69.404 0.918 69.421 ;
     RECT  5.292 68.981 5.706 69.449 ;
     RECT  11.592 68.957 21.726 69.485 ;
     RECT  5.292 69.449 5.562 69.521 ;
     RECT  22.464 68.957 167.418 69.565 ;
     RECT  7.416 69.215 10.854 69.629 ;
     RECT  14.436 69.485 21.726 69.677 ;
     RECT  5.292 69.521 5.346 69.691 ;
     RECT  11.592 69.485 13.497 69.719 ;
     RECT  14.436 69.677 21.654 69.719 ;
     RECT  22.464 69.565 167.526 69.719 ;
     RECT  11.592 69.719 12.15 69.755 ;
     RECT  14.436 69.719 21.546 69.755 ;
     RECT  56.088 69.719 167.526 69.755 ;
     RECT  12.924 69.719 13.497 69.791 ;
     RECT  0.144 69.421 0.918 69.821 ;
     RECT  22.464 69.719 55.35 69.863 ;
     RECT  14.436 69.755 21.474 69.899 ;
     RECT  36.612 69.863 55.35 69.917 ;
     RECT  7.815 69.629 10.854 69.989 ;
     RECT  18.072 69.899 21.474 69.989 ;
     RECT  56.088 69.755 167.49 69.989 ;
     RECT  1.98 69.404 3.33 70.013 ;
     RECT  22.464 69.863 35.802 70.013 ;
     RECT  56.088 69.989 166.122 70.025 ;
     RECT  0.18 69.821 0.918 70.061 ;
     RECT  7.815 69.989 8.298 70.061 ;
     RECT  22.464 70.013 35.55 70.061 ;
     RECT  9.108 69.989 10.854 70.097 ;
     RECT  36.756 69.917 55.35 70.097 ;
     RECT  2.304 70.013 3.33 70.109 ;
     RECT  22.536 70.061 35.55 70.133 ;
     RECT  9.108 70.097 9.918 70.259 ;
     RECT  10.836 70.097 10.854 70.259 ;
     RECT  14.436 69.899 17.334 70.259 ;
     RECT  18.072 69.989 21.114 70.259 ;
     RECT  26.712 70.133 35.55 70.259 ;
     RECT  9.108 70.259 9.666 70.295 ;
     RECT  14.436 70.259 15.426 70.295 ;
     RECT  16.416 70.259 17.118 70.295 ;
     RECT  5.148 69.691 5.346 70.301 ;
     RECT  9.54 70.295 9.666 70.301 ;
     RECT  18.072 70.259 20.394 70.367 ;
     RECT  166.896 69.989 167.454 70.367 ;
     RECT  13.104 69.791 13.497 70.375 ;
     RECT  9.648 70.301 9.666 70.397 ;
     RECT  22.536 70.133 25.866 70.403 ;
     RECT  18.504 70.367 20.394 70.439 ;
     RECT  167.004 70.367 167.454 70.439 ;
     RECT  0.18 70.061 0.882 70.445 ;
     RECT  7.815 70.061 8.19 70.493 ;
     RECT  13.104 70.375 13.59 70.493 ;
     RECT  15.084 70.295 15.426 70.529 ;
     RECT  19.656 70.439 20.394 70.529 ;
     RECT  26.892 70.259 35.55 70.529 ;
     RECT  56.124 70.025 166.122 70.529 ;
     RECT  32.184 70.529 35.55 70.565 ;
     RECT  0.18 70.445 0.378 70.589 ;
     RECT  16.416 70.295 16.434 70.589 ;
     RECT  163.908 70.529 166.122 70.601 ;
     RECT  5.148 70.301 5.274 70.637 ;
     RECT  26.892 70.529 31.338 70.637 ;
     RECT  32.184 70.565 33.714 70.637 ;
     RECT  15.408 70.529 15.426 70.673 ;
     RECT  7.815 70.493 8.097 70.747 ;
     RECT  2.304 70.109 2.862 70.799 ;
     RECT  7.704 70.747 8.097 70.799 ;
     RECT  13.104 70.493 13.497 70.799 ;
     RECT  18.504 70.439 18.897 70.799 ;
     RECT  36.936 70.097 55.35 70.835 ;
     RECT  0.18 70.589 0.342 70.877 ;
     RECT  36.936 70.835 40.626 70.907 ;
     RECT  167.148 70.439 167.454 70.907 ;
     RECT  164.415 70.601 166.122 70.915 ;
     RECT  0.18 70.877 0.234 70.939 ;
     RECT  2.415 70.799 2.862 71.069 ;
     RECT  56.124 70.529 163.098 71.105 ;
     RECT  0.144 70.939 0.234 71.165 ;
     RECT  32.22 70.637 33.714 71.177 ;
     RECT  0.144 71.165 0.162 71.213 ;
     RECT  22.536 70.403 25.83 71.213 ;
     RECT  160.74 71.105 163.098 71.213 ;
     RECT  56.124 71.105 159.297 71.339 ;
     RECT  160.992 71.213 163.098 71.347 ;
     RECT  41.4 70.835 55.35 71.411 ;
     RECT  164.415 70.915 166.194 71.411 ;
     RECT  26.892 70.637 31.122 71.447 ;
     RECT  29.088 71.447 31.122 71.491 ;
     RECT  29.088 71.491 31.338 71.519 ;
     RECT  160.992 71.347 163.206 71.519 ;
     RECT  167.148 70.907 167.166 71.519 ;
     RECT  29.415 71.519 31.338 71.609 ;
     RECT  56.124 71.339 157.734 71.609 ;
     RECT  56.124 71.609 155.79 71.645 ;
     RECT  158.508 71.339 159.297 71.645 ;
     RECT  164.415 71.411 165.978 71.645 ;
     RECT  37.044 70.907 40.626 71.689 ;
     RECT  41.4 71.411 54.702 71.689 ;
     RECT  160.992 71.519 163.17 71.717 ;
     RECT  162.144 71.717 163.062 71.753 ;
     RECT  165.96 71.645 165.978 71.753 ;
     RECT  29.415 71.609 31.23 71.789 ;
     RECT  156.672 71.609 157.734 71.789 ;
     RECT  56.16 71.645 155.79 71.795 ;
     RECT  37.044 71.689 54.702 71.879 ;
     RECT  56.16 71.795 155.754 72.059 ;
     RECT  160.992 71.717 161.01 72.059 ;
     RECT  56.16 72.059 155.682 72.149 ;
     RECT  37.08 71.879 51.297 72.221 ;
     RECT  156.672 71.789 157.482 72.257 ;
     RECT  150.084 72.149 155.682 72.269 ;
     RECT  150.084 72.269 155.61 72.293 ;
     RECT  156.672 72.257 156.69 72.293 ;
     RECT  157.428 72.257 157.482 72.293 ;
     RECT  37.26 72.221 51.297 72.329 ;
     RECT  52.308 71.879 54.702 72.427 ;
     RECT  150.084 72.293 155.142 72.455 ;
     RECT  151.92 72.455 155.142 72.527 ;
     RECT  47.988 72.329 51.297 72.563 ;
     RECT  151.92 72.527 155.106 72.563 ;
     RECT  52.308 72.427 54.846 72.571 ;
     RECT  150.228 72.455 150.93 72.689 ;
     RECT  152.028 72.563 155.106 72.689 ;
     RECT  150.228 72.689 150.822 72.725 ;
     RECT  152.028 72.689 152.046 72.725 ;
     RECT  150.228 72.725 150.426 72.761 ;
     RECT  154.836 72.689 155.106 72.833 ;
     RECT  157.464 72.293 157.482 72.833 ;
     RECT  48.42 72.563 51.297 72.841 ;
     RECT  56.415 72.149 149.166 72.869 ;
     RECT  56.415 72.869 149.13 72.959 ;
     RECT  152.784 72.689 153.897 72.959 ;
     RECT  154.944 72.833 155.106 72.959 ;
     RECT  56.415 72.959 148.497 72.995 ;
     RECT  152.784 72.959 152.802 72.995 ;
     RECT  154.944 72.959 154.962 72.995 ;
     RECT  56.415 72.995 139.086 73.039 ;
     RECT  52.308 72.571 55.062 73.237 ;
     RECT  55.908 73.039 139.086 73.237 ;
     RECT  139.932 72.995 148.497 73.265 ;
     RECT  139.932 73.265 139.986 73.301 ;
     RECT  139.932 73.301 139.95 73.337 ;
     RECT  48.42 72.841 51.39 73.381 ;
     RECT  52.308 73.237 139.086 73.381 ;
     RECT  140.724 73.265 148.497 73.409 ;
     RECT  150.408 72.761 150.426 73.409 ;
     RECT  48.42 73.381 139.086 73.499 ;
     RECT  48.42 73.499 101.862 73.507 ;
     RECT  37.26 72.329 47.034 73.531 ;
     RECT  48.204 73.507 101.862 73.535 ;
     RECT  142.815 73.409 148.497 73.643 ;
     RECT  37.26 73.531 47.358 73.651 ;
     RECT  48.204 73.535 49.014 73.651 ;
     RECT  37.26 73.651 49.014 73.679 ;
     RECT  37.26 73.679 48.87 73.769 ;
     RECT  49.824 73.535 101.862 73.769 ;
     RECT  49.824 73.769 53.01 73.805 ;
     RECT  53.748 73.769 55.494 73.805 ;
     RECT  56.415 73.769 101.718 73.805 ;
     RECT  37.26 73.769 46.278 73.841 ;
     RECT  49.86 73.805 53.01 73.841 ;
     RECT  140.724 73.409 142.002 73.913 ;
     RECT  41.328 73.841 46.278 73.949 ;
     RECT  47.052 73.769 48.87 73.949 ;
     RECT  53.748 73.805 55.206 73.949 ;
     RECT  48.6 73.949 48.762 74.039 ;
     RECT  50.112 73.841 53.01 74.039 ;
     RECT  41.328 73.949 45.897 74.075 ;
     RECT  47.052 73.949 47.574 74.075 ;
     RECT  48.6 74.039 48.618 74.075 ;
     RECT  102.708 73.499 139.086 74.075 ;
     RECT  139.068 74.075 139.086 74.093 ;
     RECT  112.176 74.075 135.414 74.111 ;
     RECT  136.728 74.075 138.222 74.111 ;
     RECT  142.815 73.643 144.018 74.111 ;
     RECT  50.112 74.039 52.938 74.183 ;
     RECT  122.796 74.111 135.414 74.183 ;
     RECT  56.415 73.805 101.682 74.219 ;
     RECT  50.112 74.183 52.182 74.309 ;
     RECT  54.072 73.949 54.594 74.309 ;
     RECT  136.728 74.111 137.697 74.309 ;
     RECT  71.892 74.219 101.682 74.345 ;
     RECT  54.144 74.309 54.594 74.417 ;
     RECT  112.176 74.111 121.95 74.417 ;
     RECT  112.212 74.417 121.95 74.429 ;
     RECT  112.428 74.429 121.95 74.453 ;
     RECT  112.86 74.453 121.95 74.489 ;
     RECT  56.415 74.219 70.974 74.525 ;
     RECT  50.112 74.309 51.297 74.579 ;
     RECT  52.164 74.309 52.182 74.579 ;
     RECT  112.932 74.489 121.95 74.579 ;
     RECT  122.796 74.183 135.09 74.579 ;
     RECT  71.892 74.345 101.466 74.615 ;
     RECT  102.708 74.075 110.97 74.615 ;
     RECT  113.184 74.579 121.95 74.615 ;
     RECT  56.415 74.525 67.497 74.621 ;
     RECT  82.476 74.615 86.634 74.621 ;
     RECT  122.796 74.579 129.258 74.624 ;
     RECT  68.22 74.525 70.974 74.651 ;
     RECT  102.708 74.615 110.697 74.651 ;
     RECT  113.184 74.615 121.914 74.651 ;
     RECT  122.796 74.624 129.078 74.651 ;
     RECT  102.708 74.651 108.126 74.669 ;
     RECT  102.708 74.669 106.902 74.683 ;
     RECT  82.548 74.621 86.634 74.687 ;
     RECT  114.948 74.651 121.914 74.687 ;
     RECT  82.584 74.687 86.634 74.759 ;
     RECT  41.58 74.075 42.354 74.821 ;
     RECT  71.892 74.615 81.486 74.849 ;
     RECT  130.104 74.579 135.09 74.849 ;
     RECT  41.58 74.821 42.39 74.861 ;
     RECT  150.48 74.683 150.498 74.861 ;
     RECT  102.42 74.683 106.902 74.885 ;
     RECT  108.972 74.651 110.697 74.885 ;
     RECT  122.796 74.651 129.042 74.885 ;
     RECT  122.796 74.885 125.874 74.921 ;
     RECT  108.972 74.885 109.422 74.957 ;
     RECT  130.104 74.849 134.118 74.957 ;
     RECT  122.796 74.921 124.866 74.993 ;
     RECT  134.892 74.849 135.09 74.993 ;
     RECT  125.712 74.921 125.874 75.029 ;
     RECT  130.14 74.957 134.118 75.029 ;
     RECT  87.444 74.615 101.466 75.091 ;
     RECT  75.744 74.849 81.486 75.119 ;
     RECT  82.98 74.759 86.634 75.119 ;
     RECT  87.444 75.091 101.538 75.119 ;
     RECT  113.184 74.651 114.174 75.119 ;
     RECT  123.696 74.993 124.866 75.119 ;
     RECT  130.68 75.029 133.686 75.119 ;
     RECT  63.288 74.621 67.497 75.155 ;
     RECT  79.704 75.119 81.486 75.155 ;
     RECT  82.98 75.119 85.626 75.155 ;
     RECT  87.444 75.119 97.686 75.155 ;
     RECT  102.42 74.885 105.297 75.155 ;
     RECT  123.696 75.119 124.722 75.155 ;
     RECT  130.68 75.119 132.462 75.155 ;
     RECT  75.744 75.119 78.966 75.191 ;
     RECT  114.948 74.687 121.806 75.191 ;
     RECT  79.812 75.155 81.486 75.227 ;
     RECT  130.68 75.155 132.318 75.227 ;
     RECT  71.892 74.849 74.97 75.263 ;
     RECT  76.464 75.191 78.966 75.263 ;
     RECT  77.724 75.263 78.966 75.299 ;
     RECT  87.444 75.155 90.846 75.299 ;
     RECT  86.436 75.119 86.634 75.389 ;
     RECT  98.676 75.119 101.538 75.389 ;
     RECT  113.184 75.119 114.102 75.389 ;
     RECT  123.912 75.155 124.722 75.389 ;
     RECT  87.444 75.299 89.334 75.395 ;
     RECT  98.676 75.389 100.458 75.425 ;
     RECT  106.02 74.885 106.902 75.425 ;
     RECT  113.184 75.389 114.03 75.425 ;
     RECT  114.948 75.191 121.734 75.425 ;
     RECT  133.56 75.119 133.686 75.425 ;
     RECT  106.02 75.425 106.038 75.497 ;
     RECT  133.56 75.425 133.578 75.497 ;
     RECT  137.415 74.309 137.697 75.505 ;
     RECT  86.616 75.389 86.634 75.533 ;
     RECT  98.676 75.425 99.897 75.533 ;
     RECT  114.948 75.425 121.497 75.533 ;
     RECT  126.615 74.885 129.042 75.533 ;
     RECT  79.956 75.227 81.486 75.569 ;
     RECT  90.108 75.299 90.846 75.569 ;
     RECT  128.412 75.533 129.042 75.569 ;
     RECT  88.596 75.395 89.334 75.659 ;
     RECT  98.856 75.533 99.897 75.659 ;
     RECT  101.448 75.389 101.538 75.659 ;
     RECT  102.852 75.155 105.297 75.659 ;
     RECT  71.964 75.263 74.97 75.677 ;
     RECT  98.856 75.659 98.874 75.695 ;
     RECT  101.448 75.659 101.466 75.695 ;
     RECT  123.912 75.389 124.65 75.695 ;
     RECT  88.815 75.659 89.19 75.731 ;
     RECT  124.236 75.695 124.65 75.731 ;
     RECT  91.656 75.155 97.146 75.821 ;
     RECT  139.896 74.929 139.914 75.835 ;
     RECT  140.724 73.913 140.742 75.835 ;
     RECT  29.415 71.789 30.654 76.109 ;
     RECT  113.184 75.425 113.562 76.109 ;
     RECT  139.896 75.835 140.742 76.115 ;
     RECT  113.292 76.109 113.562 76.165 ;
     RECT  113.292 76.165 113.922 76.205 ;
     RECT  114.192 76.363 114.21 76.469 ;
     RECT  41.58 74.861 42.354 76.621 ;
     RECT  41.58 76.621 42.462 76.685 ;
     RECT  78.015 75.299 78.966 76.819 ;
     RECT  79.956 75.569 79.974 76.819 ;
     RECT  43.236 74.075 45.897 76.885 ;
     RECT  63.288 75.155 66.222 76.891 ;
     RECT  119.34 75.533 121.497 76.891 ;
     RECT  63.288 76.891 66.366 76.939 ;
     RECT  67.215 75.155 67.497 76.939 ;
     RECT  98.136 76.939 98.154 77.009 ;
     RECT  90.828 75.569 90.846 77.227 ;
     RECT  142.815 74.111 143.766 77.251 ;
     RECT  90.252 77.227 90.846 77.275 ;
     RECT  89.928 77.275 90.846 77.279 ;
     RECT  63.288 76.939 67.497 77.309 ;
     RECT  89.928 77.279 89.946 77.315 ;
     RECT  142.815 77.251 143.874 77.467 ;
     RECT  144.828 73.643 148.497 77.467 ;
     RECT  41.58 76.685 42.354 77.515 ;
     RECT  43.164 76.885 45.897 77.515 ;
     RECT  41.58 77.515 45.897 77.555 ;
     RECT  63.288 77.309 66.366 77.597 ;
     RECT  140.724 76.115 140.742 77.947 ;
     RECT  142.815 77.467 148.497 78.089 ;
     RECT  140.688 77.947 140.742 78.359 ;
     RECT  144.792 78.089 148.497 78.359 ;
     RECT  32.22 71.177 32.49 78.395 ;
     RECT  140.724 78.359 140.742 78.511 ;
     RECT  141.552 73.913 142.002 78.511 ;
     RECT  140.724 78.511 142.002 78.653 ;
     RECT  37.26 73.841 40.497 78.667 ;
     RECT  41.58 77.555 42.354 78.667 ;
     RECT  67.215 77.309 67.497 78.667 ;
     RECT  113.292 76.205 113.31 78.667 ;
     RECT  114.948 75.533 118.494 78.781 ;
     RECT  119.268 76.891 121.497 78.781 ;
     RECT  63.288 77.597 66.15 78.859 ;
     RECT  66.924 78.667 67.497 78.899 ;
     RECT  63.252 78.859 66.15 79.045 ;
     RECT  67.14 78.899 67.497 79.051 ;
     RECT  68.4 74.651 70.974 79.051 ;
     RECT  67.14 79.051 70.974 79.079 ;
     RECT  62.928 79.045 66.15 79.085 ;
     RECT  113.292 78.667 113.346 79.141 ;
     RECT  114.948 78.781 121.497 79.181 ;
     RECT  37.26 78.667 42.354 79.229 ;
     RECT  113.292 79.141 113.634 79.229 ;
     RECT  90.828 77.279 90.846 79.243 ;
     RECT  91.656 75.821 92.466 79.243 ;
     RECT  90.828 79.243 92.466 79.591 ;
     RECT  93.204 75.821 97.146 79.591 ;
     RECT  90.828 79.591 97.146 79.619 ;
     RECT  91.656 79.619 97.146 79.805 ;
     RECT  56.415 74.621 62.154 80.131 ;
     RECT  63.288 79.085 66.15 80.131 ;
     RECT  142.815 78.089 143.766 80.203 ;
     RECT  142.815 80.203 143.874 80.395 ;
     RECT  144.828 78.359 148.497 80.395 ;
     RECT  142.815 80.395 148.497 80.519 ;
     RECT  144.612 80.519 148.497 80.717 ;
     RECT  67.215 79.079 70.974 81.341 ;
     RECT  142.815 80.519 143.766 81.835 ;
     RECT  144.828 80.717 148.497 81.835 ;
     RECT  91.656 79.805 92.466 81.841 ;
     RECT  93.204 79.805 97.146 81.841 ;
     RECT  91.656 81.841 97.146 81.917 ;
     RECT  142.815 81.835 148.497 82.061 ;
     RECT  67.215 81.341 67.497 82.219 ;
     RECT  142.815 82.061 143.766 82.219 ;
     RECT  67.176 82.219 67.497 82.291 ;
     RECT  141.552 78.653 142.002 82.291 ;
     RECT  142.776 82.219 143.766 82.291 ;
     RECT  66.888 82.291 67.497 82.445 ;
     RECT  141.552 82.291 143.766 82.541 ;
     RECT  67.215 82.445 67.497 82.561 ;
     RECT  68.4 81.341 70.974 82.561 ;
     RECT  56.415 80.131 66.15 82.637 ;
     RECT  67.215 82.561 70.974 82.637 ;
     RECT  91.656 81.917 92.466 83.191 ;
     RECT  93.204 81.917 97.146 83.191 ;
     RECT  43.236 77.555 45.897 83.227 ;
     RECT  43.236 83.227 46.242 83.789 ;
     RECT  91.656 83.191 97.146 83.789 ;
     RECT  142.815 82.541 143.766 83.803 ;
     RECT  142.812 83.803 143.766 84.029 ;
     RECT  56.415 82.637 62.55 84.073 ;
     RECT  63.288 82.637 66.15 84.073 ;
     RECT  67.215 82.637 67.497 84.379 ;
     RECT  68.4 82.637 70.974 84.379 ;
     RECT  56.415 84.073 66.15 84.839 ;
     RECT  67.215 84.379 70.974 84.839 ;
     RECT  67.215 84.839 67.497 86.299 ;
     RECT  43.236 83.789 45.897 86.635 ;
     RECT  67.215 86.299 67.626 86.635 ;
     RECT  68.4 84.839 70.974 86.635 ;
     RECT  43.236 86.635 46.206 86.965 ;
     RECT  67.215 86.635 70.974 86.999 ;
     RECT  43.236 86.965 46.53 87.005 ;
     RECT  56.415 84.839 62.154 90.625 ;
     RECT  142.815 84.029 143.766 90.625 ;
     RECT  63.036 84.839 66.15 90.653 ;
     RECT  41.58 79.229 42.354 90.895 ;
     RECT  33.552 71.177 33.714 90.923 ;
     RECT  72.615 75.677 74.97 91.499 ;
     RECT  63.108 90.653 66.15 93.091 ;
     RECT  37.26 79.229 40.497 93.181 ;
     RECT  41.292 90.895 42.354 93.181 ;
     RECT  43.236 87.005 45.897 93.181 ;
     RECT  144.828 82.061 148.497 93.181 ;
     RECT  22.536 71.213 24.534 93.209 ;
     RECT  52.92 74.183 52.938 93.209 ;
     RECT  87.444 75.395 87.462 93.245 ;
     RECT  50.112 74.579 50.13 93.317 ;
     RECT  56.415 90.625 62.226 93.361 ;
     RECT  63.036 93.091 66.15 93.361 ;
     RECT  67.215 86.999 67.497 93.361 ;
     RECT  56.415 93.361 62.298 93.721 ;
     RECT  63.036 93.361 67.497 93.721 ;
     RECT  90.828 79.619 90.846 93.757 ;
     RECT  91.656 83.789 92.466 93.757 ;
     RECT  108.972 74.957 108.99 93.785 ;
     RECT  141.552 82.541 142.002 93.835 ;
     RECT  81.252 75.569 81.486 93.857 ;
     RECT  33.552 90.923 33.57 93.929 ;
     RECT  141.552 93.835 142.038 94.027 ;
     RECT  142.815 90.625 143.802 94.027 ;
     RECT  141.552 94.027 143.802 94.171 ;
     RECT  140.724 78.653 140.742 94.261 ;
     RECT  141.48 94.171 143.802 94.261 ;
     RECT  34.524 70.565 35.55 94.433 ;
     RECT  114.948 79.181 118.494 94.441 ;
     RECT  144.684 93.181 148.497 94.469 ;
     RECT  56.415 93.721 67.497 94.567 ;
     RECT  68.4 86.999 70.974 94.567 ;
     RECT  22.536 93.209 24.297 94.595 ;
     RECT  90.828 93.757 92.466 94.675 ;
     RECT  93.204 83.789 97.146 94.675 ;
     RECT  56.415 94.567 70.974 94.739 ;
     RECT  129.024 75.569 129.042 94.901 ;
     RECT  140.724 94.261 143.802 94.945 ;
     RECT  144.684 94.469 146.754 94.945 ;
     RECT  32.22 78.395 32.274 95.009 ;
     RECT  113.292 79.229 113.31 95.179 ;
     RECT  70.956 94.739 70.974 95.279 ;
     RECT  114.732 94.441 118.494 95.323 ;
     RECT  114.48 95.323 118.494 95.341 ;
     RECT  119.268 79.181 121.497 95.341 ;
     RECT  124.236 75.731 124.614 95.369 ;
     RECT  114.48 95.341 121.497 95.441 ;
     RECT  140.724 94.945 146.754 95.477 ;
     RECT  113.292 95.179 113.67 95.683 ;
     RECT  114.48 95.441 118.494 95.683 ;
     RECT  139.896 76.115 139.914 95.755 ;
     RECT  140.724 95.477 146.718 95.755 ;
     RECT  74.952 91.499 74.97 95.819 ;
     RECT  138.78 76.081 138.798 96.025 ;
     RECT  124.236 95.369 124.254 96.053 ;
     RECT  138.78 96.025 139.086 96.061 ;
     RECT  139.896 95.755 146.718 96.061 ;
     RECT  113.292 95.683 118.494 96.187 ;
     RECT  119.268 95.441 121.497 96.187 ;
     RECT  106.812 75.425 106.902 96.215 ;
     RECT  56.415 94.739 70.218 96.251 ;
     RECT  72.615 91.499 73.746 96.359 ;
     RECT  125.712 75.029 125.73 96.359 ;
     RECT  37.26 93.181 45.897 96.529 ;
     RECT  22.896 94.595 24.297 96.557 ;
     RECT  37.26 96.529 46.278 96.601 ;
     RECT  102.852 75.659 102.87 96.629 ;
     RECT  106.884 96.215 106.902 96.629 ;
     RECT  113.292 96.187 121.497 96.667 ;
     RECT  58.968 96.251 70.218 96.719 ;
     RECT  113.076 96.667 121.497 96.719 ;
     RECT  25.812 71.213 25.83 96.755 ;
     RECT  90.828 94.675 97.146 96.835 ;
     RECT  108 74.669 108.126 97.025 ;
     RECT  23.256 96.557 24.297 97.097 ;
     RECT  78.015 76.819 79.974 97.097 ;
     RECT  90 94.981 90.018 97.375 ;
     RECT  90.756 96.835 97.146 97.375 ;
     RECT  26.892 71.447 28.242 97.637 ;
     RECT  112.284 96.601 112.302 97.637 ;
     RECT  56.415 96.251 58.122 97.709 ;
     RECT  113.292 96.719 121.497 97.771 ;
     RECT  138.78 96.061 146.718 97.843 ;
     RECT  130.68 75.227 132.297 97.871 ;
     RECT  58.968 96.719 70.146 97.979 ;
     RECT  37.26 96.601 46.746 98.069 ;
     RECT  58.968 97.979 69.822 98.105 ;
     RECT  90 97.375 97.146 98.149 ;
     RECT  26.892 97.637 27.846 98.213 ;
     RECT  122.796 74.993 122.814 98.213 ;
     RECT  47.556 74.075 47.574 98.221 ;
     RECT  73.728 96.359 73.746 98.249 ;
     RECT  138.528 97.843 146.718 98.339 ;
     RECT  37.26 98.069 38.79 98.375 ;
     RECT  103.788 75.659 105.297 98.429 ;
     RECT  47.052 98.221 47.574 98.491 ;
     RECT  34.524 94.433 35.097 98.519 ;
     RECT  47.052 98.491 47.934 98.609 ;
     RECT  112.968 97.771 121.497 98.617 ;
     RECT  82.98 75.155 84.114 98.645 ;
     RECT  112.788 98.617 121.497 98.669 ;
     RECT  39.6 98.069 46.17 98.717 ;
     RECT  134.892 74.993 134.91 98.717 ;
     RECT  113.22 98.669 121.497 98.765 ;
     RECT  47.556 98.609 47.574 98.789 ;
     RECT  138.78 98.339 146.718 98.879 ;
     RECT  27.108 98.213 27.846 98.951 ;
     RECT  56.415 97.709 57.69 98.951 ;
     RECT  108 97.025 108.018 98.951 ;
     RECT  39.744 98.717 46.17 99.023 ;
     RECT  137.052 75.505 137.697 99.031 ;
     RECT  37.26 98.375 38.466 99.059 ;
     RECT  104.076 98.429 105.297 99.149 ;
     RECT  131.364 97.871 132.297 99.149 ;
     RECT  147.6 94.469 148.497 99.149 ;
     RECT  81.468 93.857 81.486 99.185 ;
     RECT  58.968 98.105 69.678 99.229 ;
     RECT  37.26 99.059 38.07 99.293 ;
     RECT  58.716 99.229 69.678 99.301 ;
     RECT  23.256 97.097 23.274 99.329 ;
     RECT  137.052 99.031 138.006 99.329 ;
     RECT  58.716 99.301 69.786 99.391 ;
     RECT  85.212 75.155 85.302 99.419 ;
     RECT  82.98 98.645 83.697 99.455 ;
     RECT  58.716 99.391 69.858 99.491 ;
     RECT  104.472 99.149 105.297 99.491 ;
     RECT  138.78 98.879 146.286 99.491 ;
     RECT  27.108 98.951 27.126 99.527 ;
     RECT  113.256 98.765 121.497 99.535 ;
     RECT  98.568 99.463 98.586 99.563 ;
     RECT  57.672 98.951 57.69 99.599 ;
     RECT  58.716 99.491 69.714 99.599 ;
     RECT  59.364 99.599 69.714 99.689 ;
     RECT  85.284 99.419 85.302 99.725 ;
     RECT  113.22 99.535 121.497 99.725 ;
     RECT  126.615 75.533 127.602 99.725 ;
     RECT  59.544 99.689 69.714 99.761 ;
     RECT  138.78 99.491 146.214 99.761 ;
     RECT  40.215 99.023 46.17 99.805 ;
     RECT  38.052 99.293 38.07 99.833 ;
     RECT  138.78 99.761 145.746 99.833 ;
     RECT  90 98.149 97.758 99.869 ;
     RECT  59.58 99.761 69.714 99.959 ;
     RECT  37.26 99.293 37.278 100.031 ;
     RECT  98.604 99.769 98.622 100.031 ;
     RECT  138.78 99.833 145.674 100.031 ;
     RECT  137.415 99.329 138.006 100.075 ;
     RECT  138.78 100.031 139.158 100.075 ;
     RECT  38.772 100.003 38.79 100.103 ;
     RECT  59.58 99.959 69.678 100.103 ;
     RECT  137.415 100.075 139.158 100.103 ;
     RECT  90.36 99.869 97.146 100.139 ;
     RECT  126.615 99.725 127.422 100.139 ;
     RECT  90.648 100.139 97.146 100.229 ;
     RECT  113.22 99.725 119.79 100.229 ;
     RECT  137.415 100.103 138.15 100.229 ;
     RECT  90.828 100.229 97.146 100.265 ;
     RECT  139.068 100.103 139.158 100.265 ;
     RECT  113.4 100.229 119.646 100.301 ;
     RECT  59.58 100.103 69.606 100.337 ;
     RECT  79.488 97.097 79.974 100.373 ;
     RECT  79.488 100.373 79.506 100.409 ;
     RECT  113.436 100.301 119.646 100.499 ;
     RECT  113.436 100.499 118.854 100.535 ;
     RECT  139.068 100.265 139.086 100.535 ;
     RECT  86.652 100.381 86.67 100.571 ;
     RECT  30.636 76.109 30.654 100.607 ;
     RECT  113.436 100.535 118.638 100.607 ;
     RECT  59.688 100.337 69.606 100.643 ;
     RECT  40.215 99.805 46.35 100.651 ;
     RECT  137.415 100.229 138.006 100.679 ;
     RECT  40.215 100.651 46.746 100.769 ;
     RECT  59.688 100.643 69.39 100.769 ;
     RECT  90.828 100.265 96.714 100.769 ;
     RECT  120.528 99.725 121.497 100.805 ;
     RECT  40.215 100.769 46.098 100.841 ;
     RECT  59.796 100.769 69.39 100.841 ;
     RECT  140.04 100.031 145.674 100.841 ;
     RECT  41.508 100.841 46.098 100.925 ;
     RECT  32.256 95.009 32.274 100.949 ;
     RECT  59.796 100.841 68.742 101.039 ;
     RECT  140.04 100.841 145.458 101.039 ;
     RECT  59.796 101.039 68.526 101.075 ;
     RECT  95.94 100.769 96.714 101.075 ;
     RECT  113.436 100.607 118.458 101.111 ;
     RECT  140.112 101.039 145.458 101.111 ;
     RECT  90.972 100.769 95.058 101.147 ;
     RECT  96.696 101.075 96.714 101.183 ;
     RECT  140.112 101.111 144.774 101.183 ;
     RECT  40.215 100.841 40.77 101.219 ;
     RECT  95.94 101.075 95.958 101.219 ;
     RECT  2.415 71.069 2.697 101.267 ;
     RECT  7.815 70.799 8.097 101.267 ;
     RECT  13.215 70.799 13.497 101.267 ;
     RECT  18.615 70.799 18.897 101.267 ;
     RECT  24.015 97.097 24.297 101.267 ;
     RECT  29.415 76.109 29.697 101.267 ;
     RECT  34.815 98.519 35.097 101.267 ;
     RECT  40.215 101.219 40.497 101.267 ;
     RECT  51.015 74.579 51.297 101.267 ;
     RECT  56.415 98.951 56.697 101.267 ;
     RECT  72.615 96.359 72.897 101.267 ;
     RECT  78.015 97.097 78.297 101.267 ;
     RECT  83.415 99.455 83.697 101.267 ;
     RECT  88.815 75.731 89.097 101.267 ;
     RECT  99.615 75.659 99.897 101.267 ;
     RECT  105.015 99.491 105.297 101.267 ;
     RECT  110.415 74.885 110.697 101.267 ;
     RECT  121.215 100.805 121.497 101.267 ;
     RECT  126.615 100.139 126.897 101.267 ;
     RECT  132.015 99.149 132.297 101.267 ;
     RECT  137.415 100.679 137.697 101.267 ;
     RECT  148.215 99.149 148.497 101.267 ;
     RECT  153.615 72.959 153.897 101.267 ;
     RECT  159.015 71.645 159.297 101.267 ;
     RECT  164.415 71.645 164.697 101.267 ;
     RECT  169.815 2.413 170.097 101.267 ;
     RECT  41.616 100.925 46.098 101.309 ;
     RECT  60.228 101.075 68.526 101.309 ;
     RECT  90.972 101.147 94.986 101.309 ;
     RECT  140.112 101.183 144.702 101.309 ;
     RECT  42.84 101.309 45.705 101.345 ;
     RECT  60.228 101.309 67.662 101.345 ;
     RECT  68.508 101.309 68.526 101.345 ;
     RECT  113.436 101.111 118.386 101.345 ;
     RECT  140.256 101.309 144.702 101.345 ;
     RECT  60.768 101.345 67.554 101.381 ;
     RECT  90.972 101.309 94.878 101.381 ;
     RECT  91.152 101.381 94.878 101.417 ;
     RECT  113.904 101.345 118.386 101.417 ;
     RECT  140.796 101.345 144.702 101.417 ;
     RECT  64.8 101.381 67.554 101.453 ;
     RECT  91.44 101.417 94.878 101.453 ;
     RECT  113.904 101.417 118.134 101.453 ;
     RECT  141.336 101.417 144.018 101.453 ;
     RECT  42.84 101.345 44.766 101.459 ;
     RECT  2.415 101.267 2.505 101.537 ;
     RECT  7.815 101.267 7.905 101.537 ;
     RECT  13.215 101.267 13.305 101.537 ;
     RECT  18.615 101.267 18.705 101.537 ;
     RECT  24.015 101.267 24.105 101.537 ;
     RECT  29.415 101.267 29.505 101.537 ;
     RECT  34.815 101.267 34.905 101.537 ;
     RECT  40.215 101.267 40.305 101.537 ;
     RECT  45.615 101.345 45.705 101.537 ;
     RECT  51.015 101.267 51.105 101.537 ;
     RECT  56.415 101.267 56.505 101.537 ;
     RECT  67.215 101.453 67.305 101.537 ;
     RECT  72.615 101.267 72.705 101.537 ;
     RECT  78.015 101.267 78.105 101.537 ;
     RECT  83.415 101.267 83.505 101.537 ;
     RECT  88.815 101.267 88.905 101.537 ;
     RECT  91.44 101.453 94.305 101.537 ;
     RECT  99.615 101.267 99.705 101.537 ;
     RECT  105.015 101.267 105.105 101.537 ;
     RECT  110.415 101.267 110.505 101.537 ;
     RECT  121.215 101.267 121.305 101.537 ;
     RECT  126.615 101.267 126.705 101.537 ;
     RECT  132.015 101.267 132.105 101.537 ;
     RECT  137.415 101.267 137.505 101.537 ;
     RECT  148.215 101.267 148.305 101.537 ;
     RECT  153.615 101.267 153.705 101.537 ;
     RECT  159.015 101.267 159.105 101.537 ;
     RECT  164.415 101.267 164.505 101.537 ;
     RECT  169.815 101.267 169.905 101.537 ;
     RECT  42.84 101.459 44.19 101.549 ;
     RECT  114.336 101.453 118.134 101.579 ;
     RECT  114.336 101.579 117.27 101.693 ;
     RECT  91.44 101.537 93.978 102.077 ;
     RECT  114.336 101.693 116.838 102.077 ;
     RECT  118.116 101.579 118.134 102.077 ;
     RECT  91.44 102.077 93.834 102.317 ;
     RECT  60.768 101.381 64.026 102.509 ;
     RECT  42.084 101.309 42.102 102.541 ;
     RECT  141.372 101.453 144.018 102.557 ;
     RECT  42.084 102.541 42.174 102.569 ;
     RECT  60.768 102.509 63.81 102.569 ;
     RECT  91.44 102.317 93.798 102.569 ;
     RECT  91.656 102.569 93.798 102.605 ;
     RECT  114.444 102.077 116.838 102.605 ;
     RECT  141.408 102.557 144.018 102.605 ;
     RECT  42.156 102.569 42.174 102.653 ;
     RECT  43.02 101.549 44.19 102.653 ;
     RECT  64.944 101.453 66.438 102.653 ;
     RECT  114.444 102.605 115.506 102.653 ;
     RECT  141.408 102.605 142.506 102.653 ;
     RECT  60.84 102.569 63.81 102.701 ;
     RECT  91.656 102.605 93.222 102.701 ;
     RECT  115.344 102.653 115.506 102.701 ;
     RECT  61.272 102.701 63.81 102.749 ;
     RECT  114.444 102.653 114.462 102.749 ;
     RECT  115.452 102.701 115.506 102.749 ;
     RECT  141.66 102.653 142.506 102.749 ;
     RECT  61.272 102.749 61.29 102.797 ;
     RECT  92.376 102.701 93.222 102.797 ;
     RECT  115.488 102.749 115.506 102.845 ;
     RECT  92.376 102.797 92.79 103.373 ;
     RECT  65.304 102.653 66.438 103.421 ;
     RECT  116.244 102.605 116.838 103.421 ;
     RECT  43.056 102.653 43.29 103.469 ;
     RECT  62.172 102.749 63.81 103.469 ;
     RECT  92.376 103.373 92.394 103.469 ;
     RECT  143.244 102.605 143.838 103.469 ;
     RECT  43.056 103.469 43.074 103.517 ;
     RECT  44.172 102.653 44.19 103.517 ;
     RECT  62.172 103.469 62.586 103.517 ;
     RECT  63.792 103.469 63.81 103.517 ;
     RECT  65.412 103.421 66.114 103.517 ;
     RECT  116.496 103.421 116.838 103.517 ;
     RECT  142.056 102.749 142.506 103.517 ;
     RECT  143.244 103.469 143.262 103.517 ;
     RECT  116.82 103.517 116.838 103.565 ;
    LAYER M4 ;
     RECT  0.06 45.744 0.061 47.256 ;
     RECT  0.025 52.992 0.061 53.016 ;
     RECT  0.06 31.152 0.133 32.664 ;
     RECT  0.061 45.648 0.133 47.256 ;
     RECT  0.061 52.992 0.133 53.88 ;
     RECT  0.06 56.88 0.133 59.928 ;
     RECT  0.06 69.552 0.133 71.064 ;
     RECT  0.097 34.944 0.169 34.968 ;
     RECT  0.133 45.264 0.169 47.256 ;
     RECT  0.133 56.88 0.169 60.36 ;
     RECT  0.025 51.744 0.205 51.768 ;
     RECT  0.169 64.704 0.205 64.728 ;
     RECT  0.06 40.752 0.241 42.264 ;
     RECT  0.169 44.448 0.241 47.976 ;
     RECT  0.241 43.92 0.277 47.976 ;
     RECT  0.133 31.152 0.385 32.856 ;
     RECT  0.133 39.744 0.421 39.768 ;
     RECT  0.241 40.752 0.421 42.312 ;
     RECT  0.205 51.408 0.421 51.768 ;
     RECT  0.169 56.304 0.421 60.36 ;
     RECT  0.421 50.64 0.457 51.768 ;
     RECT  0.025 38.496 0.565 38.52 ;
     RECT  0.421 39.744 0.565 42.312 ;
     RECT  0.277 43.92 0.889 48.696 ;
     RECT  0.457 50.544 0.961 51.768 ;
     RECT  0.133 52.992 0.961 55.272 ;
     RECT  0.565 38.496 1.073 42.312 ;
     RECT  0.133 66.432 1.393 67.176 ;
     RECT  1.073 40.752 1.465 42.312 ;
     RECT  0.889 43.92 1.969 48.744 ;
     RECT  0.385 31.104 2.408 32.856 ;
     RECT  0.169 34.944 2.408 35.256 ;
     RECT  1.073 38.496 2.408 39.768 ;
     RECT  1.465 40.752 2.408 42.552 ;
     RECT  1.969 43.92 2.408 48.792 ;
     RECT  0.961 50.544 2.408 55.272 ;
     RECT  0.421 56.304 2.408 60.408 ;
     RECT  0.061 61.968 2.408 61.992 ;
     RECT  0.241 63.6 2.408 63.624 ;
     RECT  0.205 64.704 2.408 65.208 ;
     RECT  1.393 66.432 2.408 67.656 ;
     RECT  0.133 69.552 2.408 71.208 ;
     RECT  2.408 2.148 2.512 101.532 ;
     RECT  2.512 2.418 2.704 101.262 ;
     RECT  2.704 50.592 3.841 61.992 ;
     RECT  2.704 38.496 3.877 42.552 ;
     RECT  2.704 43.92 3.877 49.464 ;
     RECT  3.841 50.592 3.877 62.568 ;
     RECT  3.877 43.92 3.985 62.568 ;
     RECT  2.704 63.6 3.985 65.976 ;
     RECT  3.985 43.92 4.273 65.976 ;
     RECT  4.273 43.92 4.309 66.12 ;
     RECT  2.704 67.152 4.309 67.656 ;
     RECT  4.309 43.92 4.396 68.376 ;
     RECT  3.877 38.496 5.065 42.6 ;
     RECT  4.396 43.92 5.065 67.656 ;
     RECT  2.704 69.552 5.821 71.208 ;
     RECT  5.065 38.496 5.929 67.656 ;
     RECT  5.821 68.736 5.929 71.208 ;
     RECT  5.929 38.496 6.371 71.208 ;
     RECT  6.371 38.496 7.729 42.792 ;
     RECT  6.371 43.776 7.729 71.208 ;
     RECT  2.704 31.104 7.808 32.856 ;
     RECT  2.704 35.04 7.808 35.256 ;
     RECT  7.729 38.496 7.808 71.208 ;
     RECT  7.808 2.148 7.912 101.532 ;
     RECT  7.912 2.418 8.104 101.262 ;
     RECT  8.104 38.496 8.417 71.208 ;
     RECT  8.417 43.92 8.531 71.208 ;
     RECT  8.417 38.496 9.817 42.6 ;
     RECT  9.817 38.496 9.925 42.744 ;
     RECT  8.531 43.92 9.925 62.616 ;
     RECT  9.925 38.496 10.645 62.616 ;
     RECT  8.531 63.6 10.645 71.208 ;
     RECT  8.104 31.104 13.208 32.856 ;
     RECT  8.104 35.04 13.208 35.256 ;
     RECT  10.645 38.496 13.208 71.208 ;
     RECT  13.208 2.148 13.312 101.532 ;
     RECT  13.312 2.418 13.504 101.262 ;
     RECT  13.504 31.104 18.608 32.856 ;
     RECT  13.504 35.04 18.608 35.256 ;
     RECT  13.504 38.496 18.608 71.208 ;
     RECT  18.608 2.148 18.712 101.532 ;
     RECT  18.712 2.418 18.904 101.262 ;
     RECT  18.904 38.496 21.125 71.208 ;
     RECT  21.125 38.496 22.129 39.768 ;
     RECT  21.125 40.848 22.129 71.208 ;
     RECT  22.993 3.648 24.008 3.672 ;
     RECT  18.904 31.104 24.008 32.856 ;
     RECT  18.904 35.04 24.008 35.256 ;
     RECT  22.129 38.496 24.008 71.208 ;
     RECT  24.008 2.148 24.112 101.532 ;
     RECT  24.112 2.418 24.304 101.262 ;
     RECT  25.657 0.912 27.025 0.936 ;
     RECT  27.025 0.144 27.097 0.936 ;
     RECT  27.097 0.096 27.745 0.936 ;
     RECT  24.304 6.528 27.997 6.552 ;
     RECT  24.304 38.496 28.789 71.256 ;
     RECT  28.789 38.448 28.861 71.256 ;
     RECT  27.745 0.096 29.408 1.512 ;
     RECT  24.304 3.648 29.408 3.672 ;
     RECT  27.997 6.528 29.408 7.176 ;
     RECT  24.304 31.104 29.408 32.856 ;
     RECT  24.304 35.04 29.408 35.256 ;
     RECT  28.861 38.256 29.408 71.256 ;
     RECT  29.408 0.096 29.512 101.532 ;
     RECT  29.512 0.096 29.704 101.262 ;
     RECT  29.704 37.584 30.275 71.256 ;
     RECT  30.275 37.92 30.377 71.256 ;
     RECT  30.377 37.92 30.701 71.208 ;
     RECT  30.701 38.016 30.989 71.208 ;
     RECT  29.704 0.096 31.201 1.56 ;
     RECT  30.989 38.16 31.745 71.208 ;
     RECT  31.745 38.16 32.677 39.912 ;
     RECT  31.201 0.096 33.469 1.992 ;
     RECT  32.677 37.728 33.541 39.912 ;
     RECT  31.745 40.896 33.541 71.208 ;
     RECT  33.541 37.728 34.009 71.208 ;
     RECT  34.009 37.68 34.513 71.208 ;
     RECT  34.513 37.632 34.693 71.208 ;
     RECT  33.469 0.096 34.808 2.568 ;
     RECT  29.704 3.648 34.808 3.672 ;
     RECT  29.704 6.528 34.808 7.176 ;
     RECT  29.704 31.104 34.808 32.856 ;
     RECT  29.704 35.04 34.808 35.256 ;
     RECT  34.693 37.152 34.808 71.208 ;
     RECT  34.808 0.096 34.912 101.532 ;
     RECT  34.912 0.096 35.104 101.262 ;
     RECT  35.104 37.152 35.237 71.208 ;
     RECT  35.237 37.536 35.417 71.208 ;
     RECT  35.417 37.536 36.349 39.768 ;
     RECT  36.349 37.44 36.385 39.768 ;
     RECT  36.385 37.44 36.601 39.816 ;
     RECT  35.417 40.896 36.601 71.208 ;
     RECT  36.601 37.44 37.141 71.208 ;
     RECT  35.104 6.528 37.393 7.176 ;
     RECT  37.141 37.2 37.525 71.208 ;
     RECT  37.525 37.2 38.185 72.168 ;
     RECT  38.185 37.2 38.405 72.312 ;
     RECT  38.629 74.832 38.761 74.856 ;
     RECT  38.761 74.832 38.801 74.952 ;
     RECT  38.405 38.112 39.053 72.312 ;
     RECT  35.104 0.096 39.337 2.568 ;
     RECT  35.104 3.648 39.337 3.672 ;
     RECT  39.157 37.008 39.625 37.032 ;
     RECT  39.053 38.112 39.625 72.168 ;
     RECT  38.509 73.536 39.637 73.56 ;
     RECT  39.337 0.096 40.208 3.672 ;
     RECT  37.393 6 40.208 7.176 ;
     RECT  39.013 10.128 40.208 10.152 ;
     RECT  38.437 13.344 40.208 13.368 ;
     RECT  35.104 31.104 40.208 32.856 ;
     RECT  35.104 35.04 40.208 35.256 ;
     RECT  39.625 37.008 40.208 72.168 ;
     RECT  39.637 73.536 40.208 73.8 ;
     RECT  38.801 74.928 40.208 74.952 ;
     RECT  40.208 0.096 40.312 101.532 ;
     RECT  40.312 0.096 40.504 101.262 ;
     RECT  40.504 10.032 40.601 10.152 ;
     RECT  40.504 37.344 40.739 73.896 ;
     RECT  40.504 96.48 40.931 96.504 ;
     RECT  40.504 78.048 40.969 79.224 ;
     RECT  40.969 78.048 41.027 78.744 ;
     RECT  40.504 97.488 41.603 99.048 ;
     RECT  40.739 37.344 41.701 72.456 ;
     RECT  40.739 73.872 41.747 73.896 ;
     RECT  41.701 37.344 41.804 72.6 ;
     RECT  41.804 36.672 41.821 72.6 ;
     RECT  41.821 36.672 41.891 73.272 ;
     RECT  40.504 74.928 42.005 74.952 ;
     RECT  41.027 78.048 42.325 78.072 ;
     RECT  41.557 96.096 42.361 96.12 ;
     RECT  41.603 98.496 42.361 99.048 ;
     RECT  42.325 74.832 42.412 74.856 ;
     RECT  42.073 76.704 42.421 76.728 ;
     RECT  41.603 97.488 42.428 97.512 ;
     RECT  42.361 98.496 42.433 99.768 ;
     RECT  41.497 100.896 42.433 100.92 ;
     RECT  41.891 37.008 42.467 73.272 ;
     RECT  42.361 95.664 42.469 96.12 ;
     RECT  42.433 98.496 42.829 100.92 ;
     RECT  42.145 102.624 42.853 102.648 ;
     RECT  42.421 76.656 42.901 76.728 ;
     RECT  42.325 78.048 42.901 78.696 ;
     RECT  42.467 37.008 42.941 72.984 ;
     RECT  42.469 94.8 43.009 96.12 ;
     RECT  43.009 94.032 43.091 96.12 ;
     RECT  43.091 94.032 43.093 94.056 ;
     RECT  43.093 93.504 43.139 94.056 ;
     RECT  42.829 98.496 43.139 101.544 ;
     RECT  40.504 35.04 43.196 35.256 ;
     RECT  43.139 98.496 43.229 101.496 ;
     RECT  43.091 95.136 43.235 96.12 ;
     RECT  43.196 35.04 43.237 35.304 ;
     RECT  43.237 34.512 43.283 35.304 ;
     RECT  43.235 95.664 43.297 96.12 ;
     RECT  42.853 102.624 43.325 103.512 ;
     RECT  42.901 76.656 43.369 78.696 ;
     RECT  43.297 95.664 43.369 96.264 ;
     RECT  42.428 97.248 43.369 97.512 ;
     RECT  43.283 34.512 43.373 35.256 ;
     RECT  43.325 102.528 43.409 103.512 ;
     RECT  43.369 95.664 43.619 97.512 ;
     RECT  43.139 93.504 43.667 93.528 ;
     RECT  43.619 95.76 43.717 97.512 ;
     RECT  43.229 98.496 43.717 101.448 ;
     RECT  43.369 76.32 43.757 78.696 ;
     RECT  42.941 37.008 43.811 39.768 ;
     RECT  43.724 81.024 43.811 81.048 ;
     RECT  43.757 76.32 43.841 79.224 ;
     RECT  43.841 76.32 43.955 78.072 ;
     RECT  42.941 40.896 43.981 72.984 ;
     RECT  43.981 40.896 44.125 73.128 ;
     RECT  43.955 76.944 44.129 78.072 ;
     RECT  43.409 102.576 44.129 103.512 ;
     RECT  44.129 103.488 44.201 103.512 ;
     RECT  43.811 37.152 44.377 39.768 ;
     RECT  44.125 40.752 44.377 73.128 ;
     RECT  43.373 35.04 44.389 35.256 ;
     RECT  44.129 77.424 44.453 78.072 ;
     RECT  44.377 37.152 44.461 73.128 ;
     RECT  43.717 95.76 44.525 101.448 ;
     RECT  44.461 37.152 44.561 39.768 ;
     RECT  44.525 95.76 44.684 100.296 ;
     RECT  44.389 34.512 44.881 35.256 ;
     RECT  44.461 40.752 44.989 73.128 ;
     RECT  44.561 37.152 45.133 39.672 ;
     RECT  45.133 37.104 45.169 39.672 ;
     RECT  44.725 80.784 45.301 80.808 ;
     RECT  44.989 40.752 45.308 73.56 ;
     RECT  44.881 34.128 45.493 35.256 ;
     RECT  45.493 34.128 45.529 35.352 ;
     RECT  45.169 36.864 45.529 39.672 ;
     RECT  40.504 0.096 45.608 3.672 ;
     RECT  40.504 6 45.608 7.176 ;
     RECT  40.601 10.032 45.608 10.056 ;
     RECT  40.504 13.344 45.608 13.368 ;
     RECT  40.504 31.104 45.608 32.856 ;
     RECT  45.529 34.128 45.608 39.672 ;
     RECT  45.308 40.752 45.608 74.04 ;
     RECT  44.453 78.048 45.608 78.072 ;
     RECT  45.301 80.784 45.608 81.048 ;
     RECT  45.397 83.52 45.608 83.544 ;
     RECT  44.684 95.568 45.608 100.296 ;
     RECT  44.525 101.424 45.608 101.448 ;
     RECT  45.608 0.096 45.712 101.532 ;
     RECT  45.712 0.096 45.904 101.262 ;
     RECT  45.904 98.64 46.019 100.344 ;
     RECT  45.904 34.128 46.073 72.456 ;
     RECT  46.019 99.552 46.181 99.576 ;
     RECT  45.904 80.832 46.211 80.856 ;
     RECT  45.904 83.232 46.253 83.784 ;
     RECT  46.253 83.76 46.259 83.784 ;
     RECT  45.904 86.64 46.261 87 ;
     RECT  45.904 73.536 46.547 73.656 ;
     RECT  46.261 86.976 46.547 87 ;
     RECT  45.904 96.48 46.547 96.504 ;
     RECT  46.073 34.128 46.588 71.88 ;
     RECT  46.588 37.056 46.739 71.88 ;
     RECT  46.588 34.128 46.793 36.072 ;
     RECT  46.739 37.056 47.363 71.496 ;
     RECT  46.547 73.536 47.369 73.56 ;
     RECT  45.904 31.104 47.437 32.856 ;
     RECT  46.793 34.128 47.437 35.736 ;
     RECT  47.363 37.056 47.653 71.256 ;
     RECT  47.437 31.104 48.373 35.736 ;
     RECT  47.653 36.768 48.373 71.256 ;
     RECT  48.373 31.104 48.409 71.256 ;
     RECT  47.977 72.528 48.409 72.552 ;
     RECT  48.409 31.104 48.557 72.552 ;
     RECT  48.557 40.896 48.611 72.552 ;
     RECT  48.557 31.104 49.673 39.912 ;
     RECT  49.673 34.656 49.781 39.912 ;
     RECT  45.904 0.096 49.813 3.672 ;
     RECT  49.781 35.04 49.921 39.912 ;
     RECT  48.611 40.896 49.921 72.072 ;
     RECT  49.921 35.04 49.985 72.072 ;
     RECT  49.985 35.04 50.033 73.032 ;
     RECT  49.813 0.096 51.008 4.248 ;
     RECT  45.904 6 51.008 7.176 ;
     RECT  45.904 10.032 51.008 10.056 ;
     RECT  45.904 13.344 51.008 13.368 ;
     RECT  49.673 31.104 51.008 33.672 ;
     RECT  50.033 35.04 51.008 71.544 ;
     RECT  50.033 73.008 51.008 73.032 ;
     RECT  50.317 74.16 51.008 74.184 ;
     RECT  51.008 0.096 51.112 101.532 ;
     RECT  51.112 0.096 51.304 101.262 ;
     RECT  51.304 74.064 51.635 74.184 ;
     RECT  51.304 31.104 51.905 71.496 ;
     RECT  51.905 31.104 53.228 71.256 ;
     RECT  53.228 31.104 53.315 72.168 ;
     RECT  53.233 73.536 53.317 73.56 ;
     RECT  53.315 31.104 53.481 71.208 ;
     RECT  53.481 31.104 53.987 37.512 ;
     RECT  53.481 38.496 54.529 71.208 ;
     RECT  54.385 72.96 54.637 72.984 ;
     RECT  53.987 31.104 54.641 37.032 ;
     RECT  54.637 72.96 54.749 73.56 ;
     RECT  54.641 31.104 55.789 36.984 ;
     RECT  54.529 38.064 55.789 71.208 ;
     RECT  55.789 31.104 56.252 71.208 ;
     RECT  51.304 0.096 56.408 4.248 ;
     RECT  51.304 6 56.408 7.176 ;
     RECT  51.304 10.032 56.408 10.056 ;
     RECT  51.304 13.344 56.408 13.368 ;
     RECT  56.252 31.104 56.408 71.304 ;
     RECT  54.749 73.536 56.408 73.56 ;
     RECT  56.408 0.096 56.512 101.532 ;
     RECT  56.512 0.096 56.704 101.262 ;
     RECT  56.704 31.104 57.733 72.408 ;
     RECT  57.733 31.104 57.737 73.272 ;
     RECT  57.737 37.92 57.953 73.272 ;
     RECT  57.953 38.496 58.691 73.272 ;
     RECT  58.691 73.248 58.705 73.272 ;
     RECT  58.705 73.248 58.745 73.368 ;
     RECT  59.065 37.104 59.101 37.128 ;
     RECT  59.101 37.008 59.137 37.128 ;
     RECT  58.691 38.496 59.137 72.264 ;
     RECT  58.957 98.688 59.245 98.712 ;
     RECT  59.245 98.688 59.785 98.952 ;
     RECT  57.737 31.104 59.821 35.88 ;
     RECT  59.137 37.008 59.821 72.264 ;
     RECT  59.677 96.96 59.929 96.984 ;
     RECT  59.857 82.704 59.989 82.728 ;
     RECT  58.745 73.344 60.044 73.368 ;
     RECT  59.929 96.864 60.044 96.984 ;
     RECT  59.965 77.568 60.085 77.592 ;
     RECT  59.785 98.4 60.085 98.952 ;
     RECT  60.085 98.064 60.109 98.952 ;
     RECT  59.989 82.656 60.133 82.728 ;
     RECT  60.133 82.656 60.179 83.112 ;
     RECT  60.179 82.704 60.22 83.112 ;
     RECT  59.821 31.104 60.397 72.264 ;
     RECT  60.044 73.344 60.397 74.088 ;
     RECT  60.044 96.048 60.469 96.984 ;
     RECT  60.109 98.064 60.469 99.672 ;
     RECT  60.469 96.048 60.577 99.72 ;
     RECT  60.721 94.512 60.793 94.536 ;
     RECT  60.577 95.712 60.793 99.72 ;
     RECT  60.853 85.056 60.865 85.08 ;
     RECT  60.865 84.576 60.901 85.08 ;
     RECT  60.829 102.672 60.937 102.696 ;
     RECT  60.793 94.512 60.997 100.2 ;
     RECT  60.901 84.576 61.045 85.176 ;
     RECT  60.997 94.512 61.045 100.92 ;
     RECT  60.937 102.624 61.261 102.696 ;
     RECT  61.261 102.624 61.441 102.792 ;
     RECT  60.22 82.704 61.525 82.728 ;
     RECT  61.045 94.512 61.669 101.016 ;
     RECT  61.441 102.048 61.669 102.792 ;
     RECT  61.669 94.512 61.729 102.792 ;
     RECT  56.704 0.096 61.808 4.248 ;
     RECT  56.704 6 61.808 7.176 ;
     RECT  56.704 10.032 61.808 10.056 ;
     RECT  56.704 13.344 61.808 13.368 ;
     RECT  60.397 31.104 61.808 74.088 ;
     RECT  60.085 76.704 61.808 77.592 ;
     RECT  61.261 81.168 61.808 81.192 ;
     RECT  61.525 82.704 61.808 82.776 ;
     RECT  61.045 84.576 61.808 85.656 ;
     RECT  61.729 94.128 61.808 102.792 ;
     RECT  61.808 0.096 61.949 102.792 ;
     RECT  61.949 0.144 62.104 102.792 ;
     RECT  62.104 93.504 62.117 102.792 ;
     RECT  62.104 2.544 62.243 3.672 ;
     RECT  62.243 2.832 62.291 3.672 ;
     RECT  62.104 0.144 62.435 1.464 ;
     RECT  62.104 82.608 62.561 83.208 ;
     RECT  62.104 6 62.579 7.176 ;
     RECT  62.579 6.384 62.627 7.176 ;
     RECT  62.104 80.16 62.627 81.192 ;
     RECT  62.627 80.16 62.668 80.472 ;
     RECT  62.117 93.504 62.675 103.512 ;
     RECT  62.627 7.104 62.689 7.176 ;
     RECT  62.668 80.16 62.689 80.232 ;
     RECT  62.291 2.832 62.723 3.144 ;
     RECT  62.561 82.608 62.723 82.728 ;
     RECT  62.689 80.16 62.741 80.184 ;
     RECT  62.723 82.608 62.764 82.632 ;
     RECT  62.723 2.832 62.819 2.856 ;
     RECT  62.104 31.104 62.819 74.616 ;
     RECT  62.104 78.864 62.957 79.08 ;
     RECT  62.675 93.744 63.173 103.512 ;
     RECT  63.173 102 63.245 103.512 ;
     RECT  62.957 78.864 63.281 78.888 ;
     RECT  62.435 0.192 63.385 1.464 ;
     RECT  62.104 77.568 63.385 77.592 ;
     RECT  62.104 84.576 63.457 84.6 ;
     RECT  63.445 85.584 63.457 85.608 ;
     RECT  63.385 76.992 63.491 77.592 ;
     RECT  62.819 31.104 63.497 74.04 ;
     RECT  63.245 102.48 63.533 103.512 ;
     RECT  63.173 93.744 63.569 100.68 ;
     RECT  63.533 103.488 63.821 103.512 ;
     RECT  63.457 84.576 63.885 85.608 ;
     RECT  63.885 84.576 64.037 85.512 ;
     RECT  63.533 102.48 64.037 102.504 ;
     RECT  63.569 93.744 64.115 99.816 ;
     RECT  63.205 92.64 64.141 92.664 ;
     RECT  64.115 93.744 64.141 99.192 ;
     RECT  63.385 0.192 64.145 2.04 ;
     RECT  63.497 37.056 64.165 74.04 ;
     RECT  63.889 75.216 64.165 75.24 ;
     RECT  64.165 37.056 64.172 75.24 ;
     RECT  64.141 92.64 64.225 99.192 ;
     RECT  64.172 37.056 64.259 75.624 ;
     RECT  64.225 92.64 64.259 92.664 ;
     RECT  64.225 93.744 64.403 99.192 ;
     RECT  64.037 84.72 64.451 85.512 ;
     RECT  63.497 31.104 64.505 35.88 ;
     RECT  64.259 37.056 64.505 75.24 ;
     RECT  64.405 83.664 64.741 83.688 ;
     RECT  64.837 103.488 64.933 103.512 ;
     RECT  64.741 83.28 65.009 83.688 ;
     RECT  64.892 100.896 65.016 100.92 ;
     RECT  65.016 100.896 65.069 101.496 ;
     RECT  64.933 102.624 65.069 103.512 ;
     RECT  64.403 93.744 65.117 99.096 ;
     RECT  64.505 31.104 65.189 35.736 ;
     RECT  65.189 31.104 65.333 35.496 ;
     RECT  64.505 37.44 65.333 75.24 ;
     RECT  65.117 97.92 65.365 99.096 ;
     RECT  65.333 37.44 65.657 74.808 ;
     RECT  65.069 100.896 65.795 103.512 ;
     RECT  65.657 37.44 65.797 74.664 ;
     RECT  65.653 82.608 65.797 82.632 ;
     RECT  65.797 82.224 65.843 82.632 ;
     RECT  65.797 37.392 65.905 74.664 ;
     RECT  65.905 37.344 65.941 74.664 ;
     RECT  65.365 97.92 65.941 99.528 ;
     RECT  65.117 93.744 65.945 96.888 ;
     RECT  63.491 77.568 65.989 77.592 ;
     RECT  65.989 77.232 66.013 77.592 ;
     RECT  65.941 36.96 66.035 74.664 ;
     RECT  66.035 36.96 66.085 74.04 ;
     RECT  65.795 100.896 66.089 101.448 ;
     RECT  65.945 94.176 66.092 96.888 ;
     RECT  65.941 97.92 66.092 99.672 ;
     RECT  65.795 102.576 66.125 103.512 ;
     RECT  66.092 94.176 66.179 99.672 ;
     RECT  66.089 100.896 66.193 101.352 ;
     RECT  66.179 97.92 66.229 99.672 ;
     RECT  65.333 31.104 66.409 35.352 ;
     RECT  66.085 36.576 66.409 74.04 ;
     RECT  66.125 102.576 66.449 103.416 ;
     RECT  66.449 102.576 66.457 103.32 ;
     RECT  66.457 103.296 66.515 103.32 ;
     RECT  66.193 100.848 66.517 101.352 ;
     RECT  65.843 82.224 66.877 82.248 ;
     RECT  66.757 86.592 66.997 86.616 ;
     RECT  66.229 97.92 67.021 99.72 ;
     RECT  64.145 0.24 67.208 2.04 ;
     RECT  62.689 7.104 67.208 7.128 ;
     RECT  62.104 10.032 67.208 10.056 ;
     RECT  62.104 11.136 67.208 11.688 ;
     RECT  62.104 13.344 67.208 13.368 ;
     RECT  66.409 31.104 67.208 74.04 ;
     RECT  66.013 76.464 67.208 77.592 ;
     RECT  66.913 78.672 67.208 78.696 ;
     RECT  66.877 82.224 67.208 82.44 ;
     RECT  66.997 86.304 67.208 86.616 ;
     RECT  66.179 94.176 67.208 96.6 ;
     RECT  67.021 97.92 67.208 99.768 ;
     RECT  66.517 100.752 67.208 101.352 ;
     RECT  67.208 0.24 67.312 101.532 ;
     RECT  67.312 0.24 67.349 101.352 ;
     RECT  67.349 0.24 67.504 101.262 ;
     RECT  67.504 75.648 67.619 77.592 ;
     RECT  67.504 86.304 67.637 88.008 ;
     RECT  67.504 95.904 67.745 101.16 ;
     RECT  67.619 75.648 67.811 77.304 ;
     RECT  67.745 101.136 67.853 101.16 ;
     RECT  67.745 95.904 67.997 99.96 ;
     RECT  67.504 31.104 68.003 74.52 ;
     RECT  67.504 84.384 68.033 84.792 ;
     RECT  67.997 95.904 68.099 97.032 ;
     RECT  67.811 75.648 68.147 76.488 ;
     RECT  67.504 80.688 68.147 81.336 ;
     RECT  68.033 84.768 68.357 84.792 ;
     RECT  68.099 96.144 68.393 96.936 ;
     RECT  67.637 86.592 68.435 88.008 ;
     RECT  68.435 87.168 68.465 88.008 ;
     RECT  67.997 98.304 68.501 99.96 ;
     RECT  68.501 98.304 68.537 99.192 ;
     RECT  67.504 82.416 68.629 82.632 ;
     RECT  68.629 82.416 68.677 82.824 ;
     RECT  68.393 96.144 68.723 96.168 ;
     RECT  68.537 98.304 68.723 98.328 ;
     RECT  68.003 31.104 68.771 74.088 ;
     RECT  68.465 87.984 68.789 88.008 ;
     RECT  68.677 82.416 68.819 82.92 ;
     RECT  68.771 31.104 69.005 74.04 ;
     RECT  68.819 82.416 69.395 82.824 ;
     RECT  69.005 31.104 69.401 73.944 ;
     RECT  69.395 82.656 69.437 82.824 ;
     RECT  69.401 72.96 69.725 73.944 ;
     RECT  69.725 72.96 69.731 73.896 ;
     RECT  69.437 82.8 69.761 82.824 ;
     RECT  69.401 31.104 70.481 71.784 ;
     RECT  69.731 73.008 70.693 73.896 ;
     RECT  68.147 81.312 70.693 81.336 ;
     RECT  70.693 81.168 70.733 81.336 ;
     RECT  70.693 72.912 71.017 73.896 ;
     RECT  71.017 72.816 71.125 73.896 ;
     RECT  70.481 38.304 71.233 71.784 ;
     RECT  71.125 72.768 71.233 73.896 ;
     RECT  70.481 31.104 71.629 36.888 ;
     RECT  71.629 31.104 71.773 37.032 ;
     RECT  71.233 38.304 71.773 73.896 ;
     RECT  71.773 31.104 71.989 73.896 ;
     RECT  71.989 31.104 72.325 74.664 ;
     RECT  68.147 75.648 72.325 75.672 ;
     RECT  67.504 0.24 72.608 2.04 ;
     RECT  67.504 7.104 72.608 7.128 ;
     RECT  67.504 10.032 72.608 10.056 ;
     RECT  67.504 11.136 72.608 11.688 ;
     RECT  67.504 13.344 72.608 13.368 ;
     RECT  72.325 31.104 72.608 75.672 ;
     RECT  70.733 81.168 72.608 81.192 ;
     RECT  72.608 0.24 72.712 101.532 ;
     RECT  72.712 0.24 72.904 101.262 ;
     RECT  72.904 81.168 73.523 81.192 ;
     RECT  72.904 36.528 73.541 74.328 ;
     RECT  72.904 75.792 73.564 75.816 ;
     RECT  72.904 31.104 73.868 35.544 ;
     RECT  73.541 36.528 73.868 74.088 ;
     RECT  72.904 11.136 74.041 11.688 ;
     RECT  73.868 31.104 74.653 74.088 ;
     RECT  74.653 31.104 74.765 74.376 ;
     RECT  75.445 26.688 75.532 26.712 ;
     RECT  74.765 31.104 76.169 74.184 ;
     RECT  76.169 31.104 76.493 72.264 ;
     RECT  76.169 73.488 76.885 74.184 ;
     RECT  76.705 75.168 76.885 75.192 ;
     RECT  76.885 73.488 77.317 75.192 ;
     RECT  76.493 31.104 77.461 71.304 ;
     RECT  77.461 31.104 77.533 71.64 ;
     RECT  77.317 72.768 77.533 75.192 ;
     RECT  72.904 0.24 78.008 2.04 ;
     RECT  72.904 7.104 78.008 7.128 ;
     RECT  72.904 10.032 78.008 10.056 ;
     RECT  74.041 11.136 78.008 12.264 ;
     RECT  72.904 13.344 78.008 13.368 ;
     RECT  75.985 25.824 78.008 25.848 ;
     RECT  77.533 31.104 78.008 75.192 ;
     RECT  78.008 0.24 78.112 101.532 ;
     RECT  78.112 0.24 78.304 101.262 ;
     RECT  78.304 73.536 78.419 74.712 ;
     RECT  78.304 31.104 78.545 71.976 ;
     RECT  78.545 31.104 78.617 71.928 ;
     RECT  78.304 0.24 78.649 3.432 ;
     RECT  78.649 0.096 78.721 3.432 ;
     RECT  78.617 37.632 78.797 71.928 ;
     RECT  78.721 0.048 79.139 3.432 ;
     RECT  78.419 73.536 79.525 74.472 ;
     RECT  78.797 38.16 79.657 71.928 ;
     RECT  79.729 3.936 79.813 3.96 ;
     RECT  79.525 73.536 79.913 74.952 ;
     RECT  78.617 31.104 80.021 36.312 ;
     RECT  79.657 38.16 80.161 72.312 ;
     RECT  80.161 38.16 80.197 72.408 ;
     RECT  79.913 73.536 80.197 74.76 ;
     RECT  80.197 38.16 80.305 72.504 ;
     RECT  80.197 73.488 80.381 74.76 ;
     RECT  80.381 73.488 80.489 74.712 ;
     RECT  80.305 37.728 80.633 72.504 ;
     RECT  79.139 0.048 80.881 2.856 ;
     RECT  80.489 73.488 80.885 74.568 ;
     RECT  78.304 10.032 81.025 10.056 ;
     RECT  78.304 13.344 81.397 13.368 ;
     RECT  80.021 31.104 81.413 32.856 ;
     RECT  80.633 37.728 81.493 72.408 ;
     RECT  81.413 31.104 81.497 33.096 ;
     RECT  81.493 37.584 81.539 72.408 ;
     RECT  80.021 34.32 81.677 36.312 ;
     RECT  81.781 15.984 81.865 16.008 ;
     RECT  81.539 37.584 81.889 41.016 ;
     RECT  78.304 7.104 81.925 7.128 ;
     RECT  81.925 7.104 82.019 7.464 ;
     RECT  80.881 0.048 82.021 3.24 ;
     RECT  82.021 0.048 82.069 3.432 ;
     RECT  81.889 37.488 82.108 41.016 ;
     RECT  81.677 34.32 82.321 36.264 ;
     RECT  81.497 31.104 82.465 32.856 ;
     RECT  82.321 34.176 82.465 36.264 ;
     RECT  80.885 73.488 82.465 74.472 ;
     RECT  82.108 38.496 82.501 41.016 ;
     RECT  81.539 42.048 82.501 72.408 ;
     RECT  82.501 38.496 82.565 72.408 ;
     RECT  82.465 73.488 82.565 74.616 ;
     RECT  82.069 0.048 83.408 3.528 ;
     RECT  82.019 7.104 83.408 7.128 ;
     RECT  81.349 8.784 83.408 8.808 ;
     RECT  81.025 10.032 83.408 10.104 ;
     RECT  78.304 11.136 83.408 12.264 ;
     RECT  81.397 13.344 83.408 14.28 ;
     RECT  82.465 31.104 83.408 36.264 ;
     RECT  82.108 37.488 83.408 37.512 ;
     RECT  82.565 38.496 83.408 74.616 ;
     RECT  83.408 0.048 83.512 101.532 ;
     RECT  83.512 0.048 83.704 101.262 ;
     RECT  83.704 5.232 83.837 5.256 ;
     RECT  83.704 38.496 84.089 74.616 ;
     RECT  84.089 41.712 84.197 74.616 ;
     RECT  83.704 31.104 84.733 35.256 ;
     RECT  83.704 0.048 84.769 3.816 ;
     RECT  84.733 31.104 84.769 35.448 ;
     RECT  84.769 31.104 84.805 35.544 ;
     RECT  83.704 37.056 84.805 37.368 ;
     RECT  84.769 0.048 84.841 3.912 ;
     RECT  83.704 7.104 84.913 7.128 ;
     RECT  84.805 31.104 84.917 37.368 ;
     RECT  84.197 41.952 84.997 74.616 ;
     RECT  84.913 7.056 85.025 7.128 ;
     RECT  84.985 5.136 85.093 5.16 ;
     RECT  84.917 31.104 85.169 34.056 ;
     RECT  84.841 0.048 85.237 4.056 ;
     RECT  84.089 38.496 85.237 40.584 ;
     RECT  84.997 41.952 85.237 74.712 ;
     RECT  85.237 0.048 85.573 4.152 ;
     RECT  85.093 5.136 85.573 5.496 ;
     RECT  85.573 0.048 85.637 5.496 ;
     RECT  85.237 38.496 85.637 74.712 ;
     RECT  85.637 38.496 85.781 74.616 ;
     RECT  85.781 38.496 85.853 74.52 ;
     RECT  85.169 31.104 86.033 33.912 ;
     RECT  84.917 35.04 86.065 37.368 ;
     RECT  86.065 34.944 86.101 37.368 ;
     RECT  85.853 38.496 86.101 71.88 ;
     RECT  85.637 0.048 86.141 4.632 ;
     RECT  86.101 34.944 86.147 71.88 ;
     RECT  86.141 0.096 86.177 4.632 ;
     RECT  86.033 33.888 86.245 33.912 ;
     RECT  86.147 34.944 86.245 71.544 ;
     RECT  86.245 33.888 86.332 71.544 ;
     RECT  86.177 0.096 86.357 3 ;
     RECT  86.357 0.096 86.429 2.904 ;
     RECT  86.429 0.144 86.627 2.904 ;
     RECT  86.177 4.032 86.681 4.632 ;
     RECT  86.681 4.128 86.713 4.632 ;
     RECT  86.713 4.128 86.821 5.4 ;
     RECT  86.821 4.128 87.037 5.88 ;
     RECT  86.033 31.104 87.181 32.856 ;
     RECT  86.332 33.888 87.181 37.368 ;
     RECT  87.181 31.104 87.221 37.368 ;
     RECT  86.627 0.192 87.257 2.904 ;
     RECT  85.853 72.912 87.325 74.28 ;
     RECT  86.332 38.496 87.677 71.544 ;
     RECT  87.325 72.816 87.677 74.28 ;
     RECT  87.037 4.128 87.725 5.928 ;
     RECT  87.221 35.04 87.901 37.368 ;
     RECT  87.677 38.496 87.901 74.28 ;
     RECT  87.257 0.24 87.973 2.904 ;
     RECT  87.901 35.04 88.009 74.28 ;
     RECT  87.713 75.264 88.009 75.288 ;
     RECT  87.973 0.24 88.045 3.144 ;
     RECT  87.725 4.128 88.045 5.88 ;
     RECT  88.009 35.04 88.076 75.288 ;
     RECT  87.221 31.104 88.405 33.912 ;
     RECT  88.076 35.04 88.405 75.384 ;
     RECT  88.045 0.24 88.808 5.88 ;
     RECT  85.025 7.104 88.808 7.128 ;
     RECT  83.704 8.784 88.808 8.808 ;
     RECT  83.704 10.032 88.808 10.104 ;
     RECT  83.704 11.136 88.808 12.264 ;
     RECT  83.704 13.344 88.808 13.368 ;
     RECT  88.405 31.104 88.808 75.384 ;
     RECT  88.117 79.248 88.808 79.272 ;
     RECT  88.808 0.24 88.912 101.532 ;
     RECT  88.912 0.24 89.077 101.262 ;
     RECT  89.077 0.192 89.104 101.262 ;
     RECT  89.104 0.192 89.132 7.128 ;
     RECT  89.132 0.144 89.218 7.128 ;
     RECT  89.104 31.104 89.237 71.448 ;
     RECT  89.218 0.096 89.315 7.128 ;
     RECT  89.237 31.104 89.417 71.4 ;
     RECT  89.417 34.944 89.705 71.4 ;
     RECT  89.104 72.528 90.205 75 ;
     RECT  89.104 77.28 90.229 77.304 ;
     RECT  90.205 72.528 90.277 75.288 ;
     RECT  90.229 77.232 90.371 77.304 ;
     RECT  89.315 0.144 90.457 7.128 ;
     RECT  89.104 8.784 90.457 8.808 ;
     RECT  90.277 98.064 90.496 98.088 ;
     RECT  90.496 98.016 90.529 98.088 ;
     RECT  90.529 97.488 90.637 98.088 ;
     RECT  89.104 79.248 90.661 79.272 ;
     RECT  89.417 31.104 90.677 33.912 ;
     RECT  90.637 97.392 90.721 98.088 ;
     RECT  90.277 72.192 90.899 75.288 ;
     RECT  90.661 79.248 90.899 79.8 ;
     RECT  89.705 34.944 90.961 71.16 ;
     RECT  90.899 72.192 90.961 75 ;
     RECT  90.457 0.144 91.001 8.808 ;
     RECT  90.899 79.248 91.001 79.608 ;
     RECT  90.961 34.944 91.037 75 ;
     RECT  90.721 97.776 91.105 98.088 ;
     RECT  91.033 99.744 91.105 99.768 ;
     RECT  91.001 79.584 91.289 79.608 ;
     RECT  90.325 81.888 91.429 81.912 ;
     RECT  91.105 97.776 91.465 99.768 ;
     RECT  91.249 100.752 91.465 100.776 ;
     RECT  91.037 74.112 91.475 75 ;
     RECT  91.001 0.144 91.609 7.128 ;
     RECT  90.677 33.888 91.609 33.912 ;
     RECT  91.037 34.944 91.609 72.888 ;
     RECT  91.573 95.712 91.676 95.736 ;
     RECT  91.429 81.888 91.717 82.68 ;
     RECT  91.676 95.088 91.717 95.736 ;
     RECT  91.465 97.776 91.724 100.776 ;
     RECT  91.717 95.088 91.753 95.928 ;
     RECT  91.753 95.088 91.763 96.312 ;
     RECT  91.724 97.392 91.811 100.776 ;
     RECT  91.763 95.712 91.829 96.312 ;
     RECT  91.609 0.096 91.897 7.128 ;
     RECT  91.645 102.672 92.005 102.696 ;
     RECT  91.897 0.048 92.009 7.128 ;
     RECT  91.811 97.776 92.009 100.776 ;
     RECT  92.009 97.872 92.051 100.776 ;
     RECT  92.051 97.968 92.077 100.776 ;
     RECT  91.717 81.888 92.153 83.112 ;
     RECT  91.475 74.112 92.3 74.136 ;
     RECT  92.3 74.016 92.387 74.136 ;
     RECT  92.005 102.048 92.579 103.512 ;
     RECT  91.829 96.144 92.581 96.312 ;
     RECT  90.677 31.104 92.689 32.856 ;
     RECT  91.609 33.888 92.689 72.888 ;
     RECT  92.689 74.256 92.725 74.52 ;
     RECT  92.581 96.144 92.797 96.408 ;
     RECT  92.341 83.76 92.801 83.784 ;
     RECT  92.579 102.048 92.801 103.368 ;
     RECT  92.153 81.888 92.917 82.68 ;
     RECT  92.725 74.256 92.941 74.616 ;
     RECT  92.897 75.792 92.941 75.816 ;
     RECT  92.917 81.84 92.963 82.68 ;
     RECT  92.689 31.104 93.017 72.888 ;
     RECT  92.917 79.632 93.049 79.656 ;
     RECT  93.017 31.104 93.059 72.696 ;
     RECT  92.077 97.968 93.061 100.872 ;
     RECT  91.621 23.376 93.116 23.4 ;
     RECT  91.001 8.784 93.155 8.808 ;
     RECT  93.116 23.376 93.157 23.928 ;
     RECT  92.801 102.048 93.251 102.792 ;
     RECT  93.061 97.968 93.253 100.92 ;
     RECT  93.251 102.048 93.253 102.6 ;
     RECT  90.371 77.28 93.301 77.304 ;
     RECT  92.797 95.184 93.301 96.408 ;
     RECT  93.301 94.272 93.653 96.408 ;
     RECT  93.653 94.272 93.692 96.936 ;
     RECT  93.253 97.968 93.692 102.6 ;
     RECT  92.941 74.256 93.733 75.816 ;
     RECT  93.685 84.192 93.769 84.216 ;
     RECT  93.692 94.272 93.809 102.6 ;
     RECT  92.009 7.104 93.841 7.128 ;
     RECT  93.809 94.272 93.845 102.312 ;
     RECT  93.157 23.376 93.877 24.408 ;
     RECT  93.845 94.272 93.989 102.072 ;
     RECT  92.009 0.048 94.021 6.12 ;
     RECT  93.841 7.104 94.021 7.224 ;
     RECT  94.021 0.048 94.208 7.224 ;
     RECT  89.104 10.032 94.208 10.104 ;
     RECT  89.104 11.136 94.208 12.264 ;
     RECT  89.104 13.344 94.208 13.368 ;
     RECT  93.877 23.04 94.208 24.408 ;
     RECT  93.059 31.104 94.208 72.552 ;
     RECT  93.733 74.256 94.208 75.96 ;
     RECT  93.301 76.944 94.208 77.304 ;
     RECT  93.049 79.632 94.208 79.8 ;
     RECT  92.963 81.84 94.208 81.864 ;
     RECT  93.769 84.048 94.208 84.216 ;
     RECT  93.989 94.272 94.208 101.532 ;
     RECT  94.208 0.048 94.312 101.532 ;
     RECT  94.312 0.048 94.499 101.262 ;
     RECT  94.499 1.632 94.504 101.262 ;
     RECT  94.504 1.632 94.547 7.224 ;
     RECT  94.504 96.288 94.643 96.744 ;
     RECT  94.499 0.048 94.709 0.552 ;
     RECT  94.547 1.728 94.745 7.224 ;
     RECT  94.504 31.104 94.745 73.032 ;
     RECT  94.745 6.576 94.925 7.224 ;
     RECT  94.504 100.896 94.961 100.92 ;
     RECT  94.925 6.96 94.997 6.984 ;
     RECT  94.504 74.4 95.177 75.96 ;
     RECT  94.643 96.384 95.315 96.744 ;
     RECT  94.745 31.104 95.321 40.152 ;
     RECT  94.504 97.92 95.321 99.768 ;
     RECT  95.177 74.4 95.363 75.864 ;
     RECT  95.321 99.744 95.459 99.768 ;
     RECT  95.321 97.92 95.5 98.424 ;
     RECT  94.745 41.232 95.641 73.032 ;
     RECT  95.363 74.4 95.641 74.52 ;
     RECT  95.315 96.72 95.692 96.744 ;
     RECT  95.321 31.152 95.713 40.152 ;
     RECT  95.641 41.232 95.713 74.52 ;
     RECT  94.709 0.048 95.785 0.504 ;
     RECT  94.745 1.728 95.785 5.448 ;
     RECT  94.504 83.232 95.789 84.216 ;
     RECT  95.713 31.152 95.825 74.52 ;
     RECT  95.825 72.336 95.861 74.52 ;
     RECT  95.533 81.504 95.893 81.528 ;
     RECT  95.785 0.048 95.939 5.448 ;
     RECT  95.789 83.232 95.939 83.256 ;
     RECT  95.893 81.504 95.989 81.576 ;
     RECT  95.825 31.152 96.035 71.256 ;
     RECT  95.861 72.384 96.035 74.52 ;
     RECT  95.939 1.728 96.077 5.448 ;
     RECT  95.939 0.048 96.113 0.6 ;
     RECT  96.113 0.096 96.275 0.6 ;
     RECT  96.077 1.728 96.293 2.568 ;
     RECT  95.989 81.024 96.364 81.576 ;
     RECT  96.077 4.08 96.365 5.448 ;
     RECT  96.293 1.968 96.401 2.568 ;
     RECT  96.277 79.776 96.437 79.8 ;
     RECT  96.035 31.152 96.509 70.968 ;
     RECT  94.504 77.28 96.545 78.072 ;
     RECT  96.545 77.28 96.617 78.024 ;
     RECT  95.5 98.4 96.62 98.424 ;
     RECT  96.365 4.176 96.653 5.448 ;
     RECT  96.364 81.024 96.685 81.528 ;
     RECT  96.62 98.304 96.707 98.424 ;
     RECT  95.569 100.464 96.707 100.488 ;
     RECT  96.709 79.632 96.721 79.656 ;
     RECT  96.685 80.928 96.769 81.528 ;
     RECT  96.721 79.248 96.796 79.656 ;
     RECT  96.653 5.28 96.797 5.448 ;
     RECT  96.617 78 96.803 78.024 ;
     RECT  96.796 79.248 96.805 79.272 ;
     RECT  96.035 72.384 96.829 72.84 ;
     RECT  96.797 5.28 96.941 5.304 ;
     RECT  96.769 81.024 97.013 81.528 ;
     RECT  96.829 72.24 97.045 72.84 ;
     RECT  96.035 74.304 97.045 74.52 ;
     RECT  96.509 33.888 97.229 70.968 ;
     RECT  97.045 72.24 97.477 74.52 ;
     RECT  97.477 72.24 97.513 74.712 ;
     RECT  97.229 35.136 97.585 70.968 ;
     RECT  97.513 71.952 97.585 74.712 ;
     RECT  96.275 0.096 97.693 0.504 ;
     RECT  96.401 1.968 97.693 1.992 ;
     RECT  97.585 35.136 97.697 74.712 ;
     RECT  97.693 0.096 97.801 1.992 ;
     RECT  97.697 35.136 97.949 74.52 ;
     RECT  97.801 0.096 98.053 2.856 ;
     RECT  96.653 4.176 98.053 4.2 ;
     RECT  95.363 75.84 98.195 75.864 ;
     RECT  97.013 81.504 98.195 81.528 ;
     RECT  98.053 0.096 98.269 2.952 ;
     RECT  98.269 0.096 98.377 3.144 ;
     RECT  98.053 4.176 98.377 4.488 ;
     RECT  98.111 76.944 98.387 76.968 ;
     RECT  98.305 5.712 98.435 5.736 ;
     RECT  98.377 0.096 98.593 4.488 ;
     RECT  97.949 39.12 98.773 74.52 ;
     RECT  96.509 31.152 98.881 32.76 ;
     RECT  97.229 33.888 98.881 33.912 ;
     RECT  98.881 31.152 98.989 33.912 ;
     RECT  97.949 35.136 98.989 38.136 ;
     RECT  94.504 24.192 99.157 24.408 ;
     RECT  98.989 31.152 99.244 38.136 ;
     RECT  98.773 39.12 99.244 75.288 ;
     RECT  99.157 23.952 99.313 24.408 ;
     RECT  99.269 21.648 99.493 21.672 ;
     RECT  99.313 22.8 99.493 24.408 ;
     RECT  98.593 0.048 99.608 4.488 ;
     RECT  94.504 11.136 99.608 11.688 ;
     RECT  99.493 21.648 99.608 24.408 ;
     RECT  99.244 31.152 99.608 75.288 ;
     RECT  96.707 98.4 99.608 98.424 ;
     RECT  99.608 0.048 99.712 101.532 ;
     RECT  99.712 0.048 99.893 101.262 ;
     RECT  99.893 0.096 99.904 101.262 ;
     RECT  99.904 0.096 99.965 2.808 ;
     RECT  99.904 36.72 100.019 73.128 ;
     RECT  100.019 72.816 100.181 73.128 ;
     RECT  99.904 23.328 100.259 24.408 ;
     RECT  100.259 23.952 100.433 24.216 ;
     RECT  99.965 1.968 100.613 2.808 ;
     RECT  99.904 74.4 100.729 75.288 ;
     RECT  100.019 36.72 100.757 71.688 ;
     RECT  100.757 38.736 101.027 71.688 ;
     RECT  99.904 33.888 101.113 35.448 ;
     RECT  100.757 36.72 101.113 37.368 ;
     RECT  101.027 38.928 101.113 71.688 ;
     RECT  101.113 38.928 101.365 71.832 ;
     RECT  100.181 72.96 101.365 73.128 ;
     RECT  101.365 38.928 101.437 73.128 ;
     RECT  101.437 38.928 101.545 73.224 ;
     RECT  100.729 74.4 101.545 74.424 ;
     RECT  101.545 38.928 102.037 74.424 ;
     RECT  102.037 38.928 102.049 74.712 ;
     RECT  101.113 33.888 102.38 37.368 ;
     RECT  102.049 38.736 102.38 74.712 ;
     RECT  102.38 38.544 102.449 74.712 ;
     RECT  102.449 38.544 102.917 74.664 ;
     RECT  102.38 33.888 102.985 37.464 ;
     RECT  102.917 38.544 102.985 40.392 ;
     RECT  102.985 33.888 103.709 40.392 ;
     RECT  103.709 33.888 103.745 36.12 ;
     RECT  99.904 98.4 103.817 98.424 ;
     RECT  103.745 33.888 103.853 36.072 ;
     RECT  103.853 33.888 103.889 35.832 ;
     RECT  103.889 33.888 103.961 35.544 ;
     RECT  102.917 41.424 104.065 74.664 ;
     RECT  103.709 37.344 104.425 40.392 ;
     RECT  104.065 41.376 104.425 74.664 ;
     RECT  104.425 37.344 104.857 74.664 ;
     RECT  100.613 1.968 105.008 1.992 ;
     RECT  99.904 11.136 105.008 11.688 ;
     RECT  100.433 24.192 105.008 24.216 ;
     RECT  99.904 31.152 105.008 32.76 ;
     RECT  103.961 33.888 105.008 35.448 ;
     RECT  104.857 36.816 105.008 74.664 ;
     RECT  105.008 1.968 105.112 101.532 ;
     RECT  105.112 1.968 105.304 101.262 ;
     RECT  105.304 34.944 105.581 74.712 ;
     RECT  105.581 34.992 105.653 74.712 ;
     RECT  105.653 35.088 105.971 74.712 ;
     RECT  105.971 35.088 106.381 74.664 ;
     RECT  106.381 35.136 106.625 74.664 ;
     RECT  106.625 41.424 107.417 74.664 ;
     RECT  106.625 35.136 107.737 40.392 ;
     RECT  107.417 41.424 107.737 74.424 ;
     RECT  105.304 33.888 108.097 33.912 ;
     RECT  107.737 35.136 108.097 74.424 ;
     RECT  108.097 33.888 108.661 74.424 ;
     RECT  108.661 33.888 109.105 74.568 ;
     RECT  105.304 1.968 110.408 1.992 ;
     RECT  105.304 11.136 110.408 11.688 ;
     RECT  105.304 24.192 110.408 24.216 ;
     RECT  105.304 31.152 110.408 32.76 ;
     RECT  109.105 33.888 110.408 74.664 ;
     RECT  110.408 1.968 110.512 101.532 ;
     RECT  110.512 1.968 110.704 101.262 ;
     RECT  110.704 35.568 111.845 74.664 ;
     RECT  111.845 45.264 112.741 74.664 ;
     RECT  111.845 35.568 112.885 43.656 ;
     RECT  112.741 45.264 112.885 74.712 ;
     RECT  112.597 98.64 112.957 98.664 ;
     RECT  112.885 35.328 112.969 74.712 ;
     RECT  110.704 31.152 113.141 32.76 ;
     RECT  112.957 97.776 113.209 98.664 ;
     RECT  112.969 35.568 113.276 74.712 ;
     RECT  113.077 79.2 113.317 79.224 ;
     RECT  113.276 35.568 113.321 75 ;
     RECT  113.209 97.776 113.357 98.76 ;
     RECT  113.036 96.672 113.497 96.696 ;
     RECT  113.269 76.368 113.533 76.392 ;
     RECT  113.497 96.672 113.564 96.984 ;
     RECT  113.357 97.968 113.573 98.76 ;
     RECT  113.321 35.664 113.609 75 ;
     RECT  113.564 96.144 113.641 96.984 ;
     RECT  113.609 35.664 113.645 35.688 ;
     RECT  113.317 78.672 113.645 79.224 ;
     RECT  113.641 95.184 113.651 96.984 ;
     RECT  113.609 36.672 113.681 75 ;
     RECT  113.645 78.672 113.843 78.696 ;
     RECT  113.389 100.176 113.857 100.2 ;
     RECT  113.681 37.776 114.133 75 ;
     RECT  113.857 100.176 114.145 100.248 ;
     RECT  113.533 76.128 114.179 76.392 ;
     RECT  114.145 99.84 114.181 100.248 ;
     RECT  114.133 37.776 114.22 75.096 ;
     RECT  114.179 76.368 114.221 76.392 ;
     RECT  113.893 101.424 114.325 101.448 ;
     RECT  114.325 101.424 114.433 102.072 ;
     RECT  113.573 97.968 114.541 98.28 ;
     RECT  114.181 99.6 114.541 100.248 ;
     RECT  113.141 31.2 114.577 32.76 ;
     RECT  114.541 97.968 114.721 100.248 ;
     RECT  114.721 97.968 114.793 100.296 ;
     RECT  113.681 36.672 114.865 36.696 ;
     RECT  114.22 37.776 114.865 74.664 ;
     RECT  114.793 97.584 115.004 100.296 ;
     RECT  113.651 95.184 115.045 95.784 ;
     RECT  114.865 36.672 115.292 74.664 ;
     RECT  115.297 81.6 115.333 81.624 ;
     RECT  115.045 95.136 115.34 95.784 ;
     RECT  115.333 81.6 115.381 81.864 ;
     RECT  115.004 96.864 115.381 100.296 ;
     RECT  115.381 96.768 115.477 100.296 ;
     RECT  114.433 101.424 115.477 102.744 ;
     RECT  115.477 96.768 115.717 102.84 ;
     RECT  110.704 1.968 115.808 1.992 ;
     RECT  110.704 11.136 115.808 11.688 ;
     RECT  110.704 24.192 115.808 24.216 ;
     RECT  114.577 31.152 115.808 32.76 ;
     RECT  110.704 33.888 115.808 33.912 ;
     RECT  115.292 36.672 115.808 75.048 ;
     RECT  115.729 76.752 115.808 76.776 ;
     RECT  115.381 81.6 115.808 82.296 ;
     RECT  115.34 94.56 115.808 95.784 ;
     RECT  115.717 96.768 115.808 103.512 ;
     RECT  115.808 1.968 115.955 103.512 ;
     RECT  115.955 1.968 116.104 102.168 ;
     RECT  115.955 103.152 116.197 103.512 ;
     RECT  116.104 37.872 116.243 76.776 ;
     RECT  116.197 103.152 116.243 103.56 ;
     RECT  116.243 37.872 116.291 38.28 ;
     RECT  116.243 103.248 116.291 103.56 ;
     RECT  116.104 79.632 116.345 82.68 ;
     RECT  116.345 79.632 116.483 81.624 ;
     RECT  116.291 103.488 116.525 103.56 ;
     RECT  116.104 31.152 116.561 31.416 ;
     RECT  116.104 95.088 116.741 102.168 ;
     RECT  116.525 103.536 116.849 103.56 ;
     RECT  116.741 95.088 116.885 102.072 ;
     RECT  116.483 79.632 116.915 81.576 ;
     RECT  116.915 81.504 117.065 81.576 ;
     RECT  116.885 100.896 117.065 102.072 ;
     RECT  116.561 31.152 117.245 31.224 ;
     RECT  117.065 101.664 117.281 102.072 ;
     RECT  117.245 31.152 117.317 31.176 ;
     RECT  117.065 81.552 117.347 81.576 ;
     RECT  116.915 79.632 117.389 80.184 ;
     RECT  117.389 79.632 117.395 79.656 ;
     RECT  116.345 82.656 117.445 82.68 ;
     RECT  116.104 33.888 117.533 33.912 ;
     RECT  116.291 38.256 117.596 38.28 ;
     RECT  116.243 39.264 117.596 75.816 ;
     RECT  116.885 95.088 117.677 99.72 ;
     RECT  117.596 38.256 117.745 75.816 ;
     RECT  117.677 95.088 117.821 97.032 ;
     RECT  117.745 38.16 117.827 75.816 ;
     RECT  117.301 78 117.917 78.024 ;
     RECT  117.821 95.088 117.971 96.168 ;
     RECT  117.917 78 117.973 78.648 ;
     RECT  117.827 48.864 118.019 75.816 ;
     RECT  118.019 48.864 118.109 75.144 ;
     RECT  117.445 82.656 118.145 83.208 ;
     RECT  117.281 102.048 118.145 102.072 ;
     RECT  117.973 77.76 118.213 78.648 ;
     RECT  116.104 24.192 118.259 24.216 ;
     RECT  117.677 98.448 118.321 99.72 ;
     RECT  118.213 34.8 118.355 34.824 ;
     RECT  117.971 95.808 118.361 96.168 ;
     RECT  118.321 98.448 118.405 99.768 ;
     RECT  117.827 38.16 118.451 47.736 ;
     RECT  118.145 83.184 118.469 83.208 ;
     RECT  118.405 98.448 118.541 99 ;
     RECT  118.541 98.448 118.685 98.472 ;
     RECT  118.213 77.76 118.693 78.696 ;
     RECT  118.693 77.712 118.789 78.696 ;
     RECT  118.109 48.864 118.829 74.76 ;
     RECT  118.789 77.712 118.835 79.176 ;
     RECT  118.361 96.144 118.835 96.168 ;
     RECT  118.825 100.32 118.909 100.344 ;
     RECT  118.451 38.88 118.969 47.736 ;
     RECT  118.829 48.864 118.969 74.664 ;
     RECT  118.861 97.488 119.027 97.512 ;
     RECT  118.835 79.152 119.153 79.176 ;
     RECT  118.969 38.88 119.477 74.664 ;
     RECT  119.477 38.928 119.585 74.664 ;
     RECT  118.835 77.712 119.617 77.736 ;
     RECT  119.585 38.976 119.765 74.664 ;
     RECT  119.617 77.568 119.981 77.736 ;
     RECT  119.765 39.552 120.121 74.664 ;
     RECT  120.121 39.552 121.013 75.288 ;
     RECT  121.013 39.408 121.165 75.288 ;
     RECT  116.104 1.968 121.208 1.992 ;
     RECT  116.104 11.136 121.208 11.16 ;
     RECT  116.104 32.736 121.208 32.76 ;
     RECT  121.165 39.312 121.208 75.288 ;
     RECT  119.981 77.568 121.208 77.592 ;
     RECT  121.208 1.968 121.312 101.532 ;
     RECT  121.312 1.968 121.504 101.262 ;
     RECT  121.504 77.568 121.619 77.592 ;
     RECT  121.504 39.312 121.709 75.144 ;
     RECT  121.709 39.312 121.889 74.664 ;
     RECT  99.965 0.096 122.029 0.552 ;
     RECT  121.504 1.968 122.029 1.992 ;
     RECT  121.504 11.136 122.243 11.16 ;
     RECT  121.889 39.552 123.325 74.664 ;
     RECT  123.325 39.504 123.397 74.712 ;
     RECT  123.397 39.312 123.509 74.712 ;
     RECT  123.509 39.456 123.685 74.712 ;
     RECT  123.685 39.456 124.085 75.288 ;
     RECT  124.085 39.552 124.157 75.288 ;
     RECT  124.157 39.552 124.589 74.616 ;
     RECT  124.589 39.552 125.165 50.232 ;
     RECT  125.165 39.552 125.233 50.136 ;
     RECT  124.589 51.36 125.413 74.616 ;
     RECT  125.233 39.36 125.561 50.136 ;
     RECT  125.413 51.36 126.169 74.712 ;
     RECT  125.561 39.6 126.205 50.136 ;
     RECT  126.169 51.216 126.205 74.712 ;
     RECT  122.029 0.096 126.608 1.992 ;
     RECT  121.504 32.736 126.608 32.76 ;
     RECT  126.205 39.6 126.608 74.712 ;
     RECT  126.608 0.096 126.712 101.532 ;
     RECT  126.712 0.096 126.904 101.262 ;
     RECT  126.904 40.368 127.001 74.712 ;
     RECT  127.001 40.896 127.397 74.712 ;
     RECT  127.397 40.896 127.612 74.568 ;
     RECT  127.612 40.896 127.685 74.376 ;
     RECT  127.685 60.096 127.793 74.376 ;
     RECT  127.685 40.896 128.293 59.016 ;
     RECT  128.396 39.264 128.483 39.288 ;
     RECT  128.293 40.416 128.581 59.016 ;
     RECT  127.793 60.336 128.677 74.376 ;
     RECT  128.677 60.336 128.765 75.096 ;
     RECT  128.581 39.504 128.801 59.016 ;
     RECT  128.801 54.912 128.833 59.016 ;
     RECT  128.765 60.336 128.833 74.616 ;
     RECT  128.833 60.288 128.905 74.616 ;
     RECT  128.833 54.912 129.049 59.256 ;
     RECT  128.905 60.24 129.049 74.616 ;
     RECT  128.801 39.504 129.107 53.832 ;
     RECT  129.049 54.912 129.269 74.616 ;
     RECT  129.107 39.504 129.665 39.528 ;
     RECT  129.107 40.704 129.913 53.832 ;
     RECT  129.269 54.912 129.913 74.088 ;
     RECT  129.913 40.704 130.525 74.088 ;
     RECT  130.525 40.704 130.561 74.136 ;
     RECT  130.561 40.464 130.709 74.136 ;
     RECT  130.709 40.464 130.817 45.192 ;
     RECT  130.709 46.272 131.276 74.136 ;
     RECT  130.817 44.112 131.929 45.192 ;
     RECT  131.276 46.272 131.929 74.808 ;
     RECT  126.904 0.096 132.008 1.992 ;
     RECT  126.904 32.736 132.008 32.76 ;
     RECT  130.817 40.464 132.008 43.128 ;
     RECT  131.929 44.112 132.008 74.808 ;
     RECT  132.008 0.096 132.112 101.532 ;
     RECT  132.112 0.096 132.304 101.262 ;
     RECT  132.304 40.416 132.419 53.544 ;
     RECT  132.304 55.488 133.139 74.712 ;
     RECT  133.139 55.488 133.297 74.088 ;
     RECT  132.419 40.944 133.441 53.544 ;
     RECT  133.441 40.944 133.484 53.928 ;
     RECT  133.484 40.944 133.571 53.976 ;
     RECT  133.297 55.152 133.657 74.088 ;
     RECT  133.571 40.944 133.765 53.928 ;
     RECT  133.765 40.416 134.093 53.928 ;
     RECT  133.657 55.008 134.125 74.088 ;
     RECT  134.093 40.416 134.201 41.496 ;
     RECT  134.125 55.008 134.293 74.136 ;
     RECT  134.293 54.96 134.435 74.136 ;
     RECT  132.304 0.096 134.813 1.992 ;
     RECT  134.093 42.576 134.845 53.928 ;
     RECT  134.435 54.96 134.845 74.04 ;
     RECT  134.845 42.576 135.065 74.04 ;
     RECT  134.201 40.56 135.109 41.496 ;
     RECT  135.065 42.576 135.109 73.56 ;
     RECT  135.109 40.56 135.137 73.56 ;
     RECT  135.137 46.176 135.217 73.56 ;
     RECT  135.217 46.176 135.469 72.984 ;
     RECT  135.137 40.56 135.569 44.952 ;
     RECT  135.469 46.176 135.641 72.888 ;
     RECT  135.569 40.56 135.857 44.856 ;
     RECT  132.304 32.736 135.929 32.76 ;
     RECT  135.641 46.176 136.837 72.792 ;
     RECT  136.837 45.456 136.885 72.792 ;
     RECT  135.857 40.56 137.005 43.896 ;
     RECT  137.005 40.56 137.113 44.424 ;
     RECT  136.885 45.456 137.113 72.84 ;
     RECT  134.813 0.528 137.408 1.992 ;
     RECT  137.113 40.56 137.408 72.84 ;
     RECT  137.408 0.528 137.512 101.532 ;
     RECT  137.512 0.528 137.704 101.262 ;
     RECT  137.704 40.848 137.981 73.512 ;
     RECT  137.981 42.72 137.987 73.512 ;
     RECT  137.704 99.744 138.025 99.768 ;
     RECT  137.987 43.296 138.305 73.512 ;
     RECT  138.305 54.864 138.323 73.512 ;
     RECT  138.305 43.296 138.413 53.832 ;
     RECT  138.413 43.296 138.773 44.136 ;
     RECT  137.704 0.528 138.881 1.992 ;
     RECT  138.323 54.96 138.985 73.512 ;
     RECT  138.773 43.296 138.997 44.04 ;
     RECT  138.985 54.96 139.013 73.56 ;
     RECT  138.997 42.72 139.043 44.04 ;
     RECT  139.013 54.96 139.097 74.088 ;
     RECT  139.043 42.72 139.169 43.896 ;
     RECT  138.413 45.168 139.309 53.832 ;
     RECT  139.097 54.96 139.309 73.512 ;
     RECT  138.881 0.528 139.385 1.416 ;
     RECT  137.981 40.848 139.489 41.736 ;
     RECT  139.309 45.168 139.523 73.512 ;
     RECT  139.453 98.64 139.608 98.664 ;
     RECT  139.489 40.608 139.661 41.736 ;
     RECT  139.045 75.84 139.669 75.864 ;
     RECT  139.523 45.168 139.921 73.272 ;
     RECT  139.661 40.608 139.925 42.312 ;
     RECT  139.608 98.064 140.033 98.664 ;
     RECT  139.921 44.928 140.065 73.272 ;
     RECT  139.669 75.84 140.141 76.104 ;
     RECT  139.169 43.296 140.209 43.896 ;
     RECT  140.065 44.88 140.209 73.272 ;
     RECT  140.033 98.64 140.209 98.664 ;
     RECT  140.209 98.64 140.389 98.76 ;
     RECT  140.209 43.296 140.393 73.272 ;
     RECT  140.141 76.08 140.429 76.104 ;
     RECT  139.925 41.424 140.465 42.312 ;
     RECT  140.393 43.344 140.465 73.272 ;
     RECT  140.465 43.344 140.573 45 ;
     RECT  140.573 43.344 140.645 44.952 ;
     RECT  140.645 43.344 140.681 44.808 ;
     RECT  140.465 45.984 140.725 73.272 ;
     RECT  140.725 45.984 140.771 73.8 ;
     RECT  140.173 95.76 140.821 95.784 ;
     RECT  140.771 45.984 140.825 55.848 ;
     RECT  140.389 97.488 140.867 97.512 ;
     RECT  140.677 77.952 140.869 77.976 ;
     RECT  140.771 56.88 140.915 73.8 ;
     RECT  140.821 95.136 140.929 95.784 ;
     RECT  140.929 94.512 141.037 95.784 ;
     RECT  140.869 77.952 141.085 78.648 ;
     RECT  140.389 98.64 141.145 99.144 ;
     RECT  141.037 94.512 141.212 96.6 ;
     RECT  140.681 43.344 141.221 44.76 ;
     RECT  141.361 102.528 141.397 102.552 ;
     RECT  139.385 0.816 141.461 1.416 ;
     RECT  141.461 0.144 141.505 1.416 ;
     RECT  140.825 45.984 141.545 55.752 ;
     RECT  141.145 98.544 141.589 99.144 ;
     RECT  140.465 41.424 141.649 42.168 ;
     RECT  141.589 98.544 141.649 100.056 ;
     RECT  141.397 102.528 141.649 102.648 ;
     RECT  141.649 41.424 141.692 42.312 ;
     RECT  141.221 43.344 141.692 43.944 ;
     RECT  141.505 0.048 141.721 1.416 ;
     RECT  140.915 56.88 141.725 73.512 ;
     RECT  141.212 94.272 141.725 96.6 ;
     RECT  141.692 41.424 141.733 43.944 ;
     RECT  141.545 45.984 141.757 51.768 ;
     RECT  141.649 98.352 141.925 100.056 ;
     RECT  141.325 101.424 141.925 101.448 ;
     RECT  141.925 98.352 141.973 101.448 ;
     RECT  141.649 102.528 141.973 102.744 ;
     RECT  141.725 94.272 141.98 96.504 ;
     RECT  141.973 98.352 142.001 102.744 ;
     RECT  141.98 94.032 142.009 96.504 ;
     RECT  141.545 52.992 142.127 55.752 ;
     RECT  141.725 56.88 142.127 73.272 ;
     RECT  141.757 45.168 142.189 51.768 ;
     RECT  141.085 77.952 142.453 77.976 ;
     RECT  142.165 82.224 142.477 82.248 ;
     RECT  141.733 41.232 142.508 43.944 ;
     RECT  142.189 45.12 142.508 51.768 ;
     RECT  142.001 98.352 142.657 103.512 ;
     RECT  142.508 41.232 142.685 51.768 ;
     RECT  142.127 52.992 142.685 73.272 ;
     RECT  142.009 93.84 142.693 96.504 ;
     RECT  142.657 98.016 142.693 103.512 ;
     RECT  141.721 0.048 142.808 1.704 ;
     RECT  142.685 41.232 142.808 73.272 ;
     RECT  142.453 77.28 142.808 77.976 ;
     RECT  142.477 82.224 142.808 82.536 ;
     RECT  142.801 83.808 142.808 83.832 ;
     RECT  142.693 93.84 142.808 103.512 ;
     RECT  142.808 0.048 142.912 103.512 ;
     RECT  142.912 2.418 143.027 103.512 ;
     RECT  143.027 2.418 143.104 101.448 ;
     RECT  143.104 93.84 143.129 96.504 ;
     RECT  143.129 93.84 143.219 96.312 ;
     RECT  143.027 102.528 143.267 103.512 ;
     RECT  143.104 97.488 143.273 100.056 ;
     RECT  143.267 102.576 143.273 103.512 ;
     RECT  143.104 83.808 143.315 84.264 ;
     RECT  143.104 86.064 143.353 86.184 ;
     RECT  143.104 81.84 143.363 82.536 ;
     RECT  143.315 83.808 143.363 84.168 ;
     RECT  143.104 41.472 143.417 44.424 ;
     RECT  143.353 86.064 143.459 86.088 ;
     RECT  143.219 93.84 143.459 94.632 ;
     RECT  143.104 101.328 143.561 101.448 ;
     RECT  143.561 101.424 143.597 101.448 ;
     RECT  143.417 41.472 143.699 42.456 ;
     RECT  143.104 45.552 143.699 46.872 ;
     RECT  143.459 94.608 143.813 94.632 ;
     RECT  143.273 102.576 143.849 103.464 ;
     RECT  143.104 77.28 143.885 78.072 ;
     RECT  143.699 41.472 143.987 42.216 ;
     RECT  143.849 102.576 144.029 102.6 ;
     RECT  143.987 42.144 144.101 42.168 ;
     RECT  143.417 43.488 144.133 44.424 ;
     RECT  144.133 43.488 144.169 44.472 ;
     RECT  143.699 45.984 144.169 46.872 ;
     RECT  143.104 47.856 144.169 73.272 ;
     RECT  143.363 83.808 144.179 83.832 ;
     RECT  143.104 79.824 144.181 80.232 ;
     RECT  143.363 81.84 144.209 82.056 ;
     RECT  144.209 81.84 144.227 81.864 ;
     RECT  143.219 95.616 144.287 96.312 ;
     RECT  143.273 97.632 144.287 100.056 ;
     RECT  144.181 79.776 144.313 80.232 ;
     RECT  144.287 95.616 144.316 100.056 ;
     RECT  142.912 0.048 144.317 1.224 ;
     RECT  144.169 45.984 144.323 73.272 ;
     RECT  144.316 98.112 144.353 100.056 ;
     RECT  144.169 43.488 144.461 45 ;
     RECT  144.313 79.776 144.469 80.424 ;
     RECT  144.353 99.744 144.497 100.056 ;
     RECT  144.316 95.616 144.515 96.888 ;
     RECT  144.323 52.368 144.524 73.272 ;
     RECT  143.885 77.472 144.533 78.072 ;
     RECT  144.469 79.776 144.641 80.712 ;
     RECT  144.613 78.096 144.709 78.12 ;
     RECT  144.709 78.096 144.755 78.36 ;
     RECT  144.515 95.856 144.785 96.888 ;
     RECT  144.755 78.336 144.853 78.36 ;
     RECT  144.641 79.776 144.853 80.424 ;
     RECT  144.785 96.672 144.893 96.888 ;
     RECT  144.497 99.744 144.893 99.96 ;
     RECT  144.893 96.672 144.899 96.696 ;
     RECT  144.323 45.984 144.965 51.384 ;
     RECT  144.524 52.368 145.001 73.368 ;
     RECT  144.317 0.048 145.073 1.176 ;
     RECT  144.353 98.112 145.073 98.664 ;
     RECT  144.853 78.336 145.181 80.424 ;
     RECT  145.181 79.2 145.187 80.424 ;
     RECT  144.965 45.984 145.253 49.704 ;
     RECT  144.893 99.744 145.541 99.768 ;
     RECT  145.253 45.984 145.613 49.608 ;
     RECT  145.073 98.64 145.619 98.664 ;
     RECT  145.001 52.368 145.715 65.16 ;
     RECT  144.461 43.488 145.717 43.56 ;
     RECT  145.717 43.296 145.789 43.56 ;
     RECT  144.461 44.64 145.789 45 ;
     RECT  145.613 45.984 145.789 47.4 ;
     RECT  144.965 50.784 145.789 51.384 ;
     RECT  145.715 52.368 145.789 65.016 ;
     RECT  145.187 79.2 145.793 79.848 ;
     RECT  145.789 43.296 145.801 47.4 ;
     RECT  145.793 79.824 145.811 79.848 ;
     RECT  145.801 43.488 145.973 47.4 ;
     RECT  145.789 50.784 146.009 65.016 ;
     RECT  146.009 50.784 146.041 64.92 ;
     RECT  145.073 0.816 146.045 1.176 ;
     RECT  145.001 66.72 146.077 73.368 ;
     RECT  146.077 66.624 146.149 73.368 ;
     RECT  146.149 66.096 146.236 73.368 ;
     RECT  146.236 66.192 146.339 73.368 ;
     RECT  146.339 66.192 146.369 72.936 ;
     RECT  146.045 0.816 146.405 0.84 ;
     RECT  145.613 48.48 146.473 49.608 ;
     RECT  146.041 50.592 146.473 64.92 ;
     RECT  146.369 66.192 146.549 72.84 ;
     RECT  145.973 43.584 146.585 47.4 ;
     RECT  146.585 45.888 146.837 47.4 ;
     RECT  146.473 48.48 146.909 64.92 ;
     RECT  146.549 66.336 146.981 72.84 ;
     RECT  146.909 48.48 147.013 63.288 ;
     RECT  146.837 45.888 147.097 46.008 ;
     RECT  146.909 64.32 147.337 64.92 ;
     RECT  147.337 64.32 147.553 65.256 ;
     RECT  146.981 66.336 147.553 72.792 ;
     RECT  146.837 47.376 147.625 47.4 ;
     RECT  147.013 48.384 147.625 63.288 ;
     RECT  147.625 47.376 148.057 63.288 ;
     RECT  147.553 64.32 148.057 72.792 ;
     RECT  148.057 47.376 148.093 72.792 ;
     RECT  146.585 43.584 148.208 43.608 ;
     RECT  147.097 45.984 148.208 46.008 ;
     RECT  148.093 47.328 148.208 72.792 ;
     RECT  145.724 74.832 148.208 74.856 ;
     RECT  148.208 2.148 148.312 101.532 ;
     RECT  148.312 2.418 148.504 101.262 ;
     RECT  148.504 43.584 148.643 43.608 ;
     RECT  148.504 45.936 148.643 48.936 ;
     RECT  148.504 50.064 148.673 58.728 ;
     RECT  148.504 59.856 148.781 72.408 ;
     RECT  148.643 46.032 148.817 48.936 ;
     RECT  148.817 46.416 148.853 48.936 ;
     RECT  148.853 46.416 148.925 47.496 ;
     RECT  148.673 50.064 148.925 55.56 ;
     RECT  148.853 48.912 148.989 48.936 ;
     RECT  148.925 50.064 148.997 55.224 ;
     RECT  148.997 50.832 149.069 55.224 ;
     RECT  148.925 46.416 149.393 47.256 ;
     RECT  149.069 50.832 149.609 50.856 ;
     RECT  148.673 56.688 149.749 58.728 ;
     RECT  148.781 60 149.749 72.408 ;
     RECT  149.069 52.032 149.893 55.224 ;
     RECT  149.749 56.256 149.893 72.408 ;
     RECT  149.393 47.232 150.083 47.256 ;
     RECT  149.893 52.032 150.109 72.408 ;
     RECT  150.109 51.312 150.113 72.408 ;
     RECT  150.284 47.856 150.325 47.88 ;
     RECT  150.325 47.856 150.371 48.264 ;
     RECT  150.109 49.968 150.371 49.992 ;
     RECT  148.504 74.832 150.469 74.856 ;
     RECT  150.469 74.688 150.509 74.856 ;
     RECT  150.371 48.144 150.581 48.264 ;
     RECT  150.581 48.24 150.617 48.264 ;
     RECT  150.113 51.312 151.085 72.264 ;
     RECT  151.085 51.312 151.109 64.488 ;
     RECT  151.109 51.264 151.193 64.488 ;
     RECT  151.193 51.312 151.445 64.488 ;
     RECT  151.085 65.76 151.621 72.264 ;
     RECT  151.445 51.888 151.661 64.488 ;
     RECT  151.661 51.888 151.697 59.16 ;
     RECT  151.697 51.888 152.021 57.672 ;
     RECT  151.621 65.76 152.057 72.408 ;
     RECT  151.661 60.528 152.492 64.488 ;
     RECT  152.057 65.76 152.492 72.264 ;
     RECT  151.697 58.656 152.665 59.16 ;
     RECT  152.021 52.32 152.737 57.672 ;
     RECT  152.665 58.656 152.737 59.448 ;
     RECT  152.737 52.32 152.773 59.448 ;
     RECT  152.773 52.32 153.109 59.544 ;
     RECT  152.492 60.528 153.109 72.264 ;
     RECT  153.109 52.32 153.385 72.264 ;
     RECT  153.385 52.32 153.565 72.456 ;
     RECT  153.565 51.744 153.608 72.456 ;
     RECT  150.509 74.688 153.608 74.712 ;
     RECT  153.608 2.148 153.712 101.532 ;
     RECT  153.712 2.418 153.904 101.262 ;
     RECT  153.904 58.752 153.929 59.256 ;
     RECT  153.904 51.744 154.001 57.432 ;
     RECT  153.929 58.752 154.001 59.208 ;
     RECT  154.001 51.744 154.289 57.384 ;
     RECT  153.904 74.688 154.451 74.712 ;
     RECT  153.904 63.744 154.739 72.456 ;
     RECT  154.739 63.744 154.829 72.264 ;
     RECT  154.001 58.752 154.969 59.112 ;
     RECT  153.904 60.288 154.969 60.312 ;
     RECT  153.904 61.44 154.969 62.568 ;
     RECT  154.829 63.744 154.969 68.472 ;
     RECT  154.969 61.44 154.973 68.472 ;
     RECT  154.969 58.752 155.029 60.312 ;
     RECT  154.973 61.44 155.029 68.28 ;
     RECT  155.029 58.752 155.185 68.28 ;
     RECT  155.185 58.512 155.189 68.28 ;
     RECT  155.189 58.512 155.225 68.088 ;
     RECT  154.289 52.176 155.257 57.384 ;
     RECT  155.225 58.512 155.257 67.896 ;
     RECT  155.257 52.176 155.693 67.896 ;
     RECT  154.829 69.456 155.693 72.264 ;
     RECT  155.693 52.368 155.729 67.896 ;
     RECT  155.729 65.808 155.765 67.896 ;
     RECT  155.693 69.456 155.765 71.928 ;
     RECT  155.765 69.456 155.801 71.784 ;
     RECT  155.765 65.808 155.939 67.848 ;
     RECT  155.801 69.456 156.181 71.304 ;
     RECT  156.181 69.312 156.193 71.304 ;
     RECT  155.729 52.368 156.485 64.584 ;
     RECT  156.193 68.976 156.701 71.304 ;
     RECT  156.485 52.416 156.733 64.584 ;
     RECT  156.733 52.416 156.745 64.824 ;
     RECT  156.745 52.608 156.949 64.824 ;
     RECT  155.939 65.952 156.949 67.848 ;
     RECT  156.701 68.976 157.817 71.208 ;
     RECT  156.949 52.608 157.853 67.848 ;
     RECT  157.853 65.952 157.921 67.848 ;
     RECT  157.817 68.976 157.921 71.16 ;
     RECT  157.853 52.608 157.993 64.968 ;
     RECT  157.993 52.56 158.471 64.968 ;
     RECT  158.471 52.512 159.008 64.968 ;
     RECT  157.921 65.952 159.008 71.16 ;
     RECT  159.008 2.148 159.112 101.532 ;
     RECT  159.112 2.418 159.304 101.262 ;
     RECT  159.304 52.416 159.437 69.576 ;
     RECT  159.437 52.416 160.163 68.232 ;
     RECT  160.163 52.416 160.229 60.696 ;
     RECT  160.229 60.672 160.373 60.696 ;
     RECT  159.437 69.264 160.405 69.576 ;
     RECT  159.304 70.56 160.405 70.92 ;
     RECT  160.163 61.68 160.621 68.232 ;
     RECT  160.405 69.264 160.621 70.92 ;
     RECT  160.621 61.68 160.625 70.92 ;
     RECT  160.625 63.744 160.643 70.92 ;
     RECT  160.229 52.416 160.769 59.544 ;
     RECT  160.625 61.68 160.841 62.52 ;
     RECT  160.841 61.92 160.949 62.52 ;
     RECT  160.643 63.84 161.233 70.92 ;
     RECT  160.769 52.464 161.269 59.544 ;
     RECT  160.949 62.016 161.561 62.52 ;
     RECT  161.561 62.208 161.773 62.52 ;
     RECT  161.269 52.464 161.809 60.264 ;
     RECT  161.809 52.464 162.085 60.408 ;
     RECT  161.233 63.84 162.085 71.208 ;
     RECT  162.085 52.464 162.131 61.032 ;
     RECT  162.131 52.464 162.515 59.64 ;
     RECT  162.515 52.464 162.637 57.096 ;
     RECT  162.131 60.96 162.673 61.032 ;
     RECT  161.773 62.208 162.673 62.712 ;
     RECT  162.085 63.744 162.749 71.208 ;
     RECT  162.673 60.96 162.764 62.712 ;
     RECT  162.749 63.744 162.764 70.776 ;
     RECT  162.764 60.96 162.965 70.776 ;
     RECT  162.637 52.416 162.995 57.096 ;
     RECT  162.965 60.96 163.037 70.248 ;
     RECT  163.037 61.536 163.043 70.248 ;
     RECT  163.043 61.536 163.109 70.056 ;
     RECT  163.109 61.632 163.145 70.056 ;
     RECT  162.515 58.128 163.501 59.64 ;
     RECT  162.995 53.232 163.525 57.096 ;
     RECT  163.501 58.128 163.525 60.408 ;
     RECT  163.525 53.232 164.005 60.408 ;
     RECT  164.005 53.232 164.252 60.456 ;
     RECT  163.145 61.68 164.252 70.056 ;
     RECT  164.252 53.232 164.408 70.056 ;
     RECT  164.408 2.148 164.512 101.532 ;
     RECT  164.512 2.418 164.704 101.262 ;
     RECT  164.704 55.248 164.909 70.488 ;
     RECT  164.704 53.376 165.053 54.168 ;
     RECT  165.053 53.808 165.125 54.168 ;
     RECT  164.909 55.44 165.125 70.488 ;
     RECT  165.125 69.984 165.203 70.488 ;
     RECT  165.125 55.44 165.341 68.952 ;
     RECT  165.203 69.984 165.341 70.152 ;
     RECT  165.341 61.392 165.557 68.952 ;
     RECT  165.341 55.44 165.593 60.312 ;
     RECT  165.557 61.392 165.923 67.848 ;
     RECT  165.125 54.144 165.949 54.168 ;
     RECT  165.949 54.144 165.989 54.696 ;
     RECT  165.923 61.392 165.989 67.128 ;
     RECT  165.341 69.984 166.061 70.008 ;
     RECT  165.989 54.672 166.115 54.696 ;
     RECT  165.593 55.824 166.241 60.312 ;
     RECT  166.241 56.496 166.355 60.312 ;
     RECT  166.355 59.952 166.357 60.312 ;
     RECT  165.989 61.392 166.357 66.84 ;
     RECT  166.355 56.736 166.396 58.728 ;
     RECT  166.357 59.952 166.403 66.84 ;
     RECT  166.396 56.736 166.673 57.432 ;
     RECT  166.396 58.608 166.709 58.728 ;
     RECT  166.403 59.952 166.781 61.416 ;
     RECT  165.557 68.928 166.849 68.952 ;
     RECT  166.849 68.208 166.957 68.952 ;
     RECT  166.403 62.448 167.029 66.84 ;
     RECT  166.957 68.208 167.029 69.624 ;
     RECT  166.781 60.624 167.033 61.416 ;
     RECT  167.029 62.448 167.141 69.624 ;
     RECT  167.141 62.448 167.285 67.416 ;
     RECT  167.285 62.448 167.357 62.472 ;
     RECT  167.141 68.928 167.42 69.624 ;
     RECT  167.285 63.504 167.429 67.416 ;
     RECT  167.42 68.928 167.429 69.816 ;
     RECT  167.429 69.792 167.507 69.816 ;
     RECT  167.033 60.624 167.749 61.128 ;
     RECT  167.749 60.384 167.789 61.128 ;
     RECT  167.429 63.504 167.795 67.32 ;
     RECT  166.673 57.024 167.825 57.432 ;
     RECT  166.709 58.704 167.897 58.728 ;
     RECT  167.789 60.384 167.897 60.408 ;
     RECT  167.795 63.792 167.933 67.32 ;
     RECT  167.825 57.024 168.149 57.048 ;
     RECT  167.933 64.368 168.371 65.544 ;
     RECT  167.933 66.72 168.509 66.744 ;
     RECT  168.371 64.944 168.689 65.544 ;
     RECT  168.689 65.52 169.808 65.544 ;
     RECT  169.808 2.148 169.912 101.532 ;
     RECT  169.912 2.418 170.104 101.262 ;
    LAYER M5 ;
     RECT  79.056 0.016 82.104 0.037 ;
     RECT  61.392 0.016 62.904 0.179 ;
     RECT  79.056 0.037 82.2 0.179 ;
     RECT  141.264 0.016 142.776 0.227 ;
     RECT  61.44 0.179 62.904 0.229 ;
     RECT  61.44 0.229 62.952 0.515 ;
     RECT  141.264 0.227 142.728 0.851 ;
     RECT  98.256 0.016 99.768 1.139 ;
     RECT  61.44 0.515 62.904 1.619 ;
     RECT  85.2 0.016 86.712 1.763 ;
     RECT  88.656 0.016 96.312 1.763 ;
     RECT  79.056 0.179 82.104 1.859 ;
     RECT  88.704 1.763 96.312 1.859 ;
     RECT  80.784 1.859 82.104 1.907 ;
     RECT  85.248 1.763 86.52 2.003 ;
     RECT  79.056 1.859 79.752 2.137 ;
     RECT  141.312 0.851 142.728 2.137 ;
     RECT  2.4 2.137 2.52 2.151 ;
     RECT  7.8 2.137 7.92 2.151 ;
     RECT  13.2 2.137 13.32 2.151 ;
     RECT  18.6 2.137 18.72 2.151 ;
     RECT  24 2.137 24.12 2.151 ;
     RECT  29.4 2.137 29.52 2.151 ;
     RECT  34.8 2.137 34.92 2.151 ;
     RECT  40.2 2.137 40.32 2.151 ;
     RECT  45.6 2.137 45.72 2.151 ;
     RECT  51 2.137 51.12 2.151 ;
     RECT  56.4 2.137 56.52 2.151 ;
     RECT  67.2 2.137 67.32 2.151 ;
     RECT  72.6 2.137 72.72 2.151 ;
     RECT  83.4 2.137 83.52 2.151 ;
     RECT  98.304 1.139 99.768 2.151 ;
     RECT  105 2.137 105.12 2.151 ;
     RECT  110.4 2.137 110.52 2.151 ;
     RECT  115.8 2.137 115.92 2.151 ;
     RECT  121.2 2.137 121.32 2.151 ;
     RECT  126.6 2.137 126.72 2.151 ;
     RECT  132 2.137 132.12 2.151 ;
     RECT  137.4 2.137 137.52 2.151 ;
     RECT  141.312 2.137 142.92 2.151 ;
     RECT  148.2 2.137 148.32 2.151 ;
     RECT  153.6 2.137 153.72 2.151 ;
     RECT  159 2.137 159.12 2.151 ;
     RECT  164.4 2.137 164.52 2.151 ;
     RECT  169.8 2.137 169.92 2.151 ;
     RECT  78 2.137 79.752 2.195 ;
     RECT  78 2.195 79.608 2.243 ;
     RECT  78 2.243 79.512 2.291 ;
     RECT  98.304 2.151 99.912 2.291 ;
     RECT  81.024 1.907 82.104 2.339 ;
     RECT  81.12 2.339 82.104 2.387 ;
     RECT  88.8 1.859 96.312 2.435 ;
     RECT  88.8 2.435 96.072 2.483 ;
     RECT  98.352 2.291 99.912 2.867 ;
     RECT  85.248 2.003 86.328 2.963 ;
     RECT  78 2.291 79.128 3.443 ;
     RECT  85.248 2.963 85.752 3.443 ;
     RECT  88.8 2.483 95.976 3.443 ;
     RECT  81.408 2.387 82.104 3.539 ;
     RECT  85.584 3.443 85.752 3.539 ;
     RECT  88.8 3.443 95.784 3.539 ;
     RECT  88.8 3.539 95.112 4.019 ;
     RECT  61.536 1.619 62.904 4.259 ;
     RECT  88.8 4.019 94.728 4.309 ;
     RECT  85.584 3.539 85.656 4.499 ;
     RECT  85.632 4.499 85.656 4.595 ;
     RECT  88.704 4.309 94.728 4.595 ;
     RECT  88.8 4.595 94.728 5.747 ;
     RECT  98.4 2.867 99.912 5.747 ;
     RECT  88.8 5.747 94.512 6.419 ;
     RECT  90.288 6.419 94.512 6.803 ;
     RECT  90.912 6.803 94.512 6.851 ;
     RECT  81.408 3.539 82.008 7.475 ;
     RECT  121.2 2.151 121.512 11.125 ;
     RECT  61.8 4.259 62.904 11.699 ;
     RECT  91.872 6.851 94.512 13.379 ;
     RECT  81.408 7.475 81.912 14.291 ;
     RECT  98.928 5.747 99.912 23.317 ;
     RECT  91.872 13.379 93 23.365 ;
     RECT  91.632 23.365 93 23.893 ;
     RECT  91.632 23.893 93.192 24.181 ;
     RECT  94.2 13.379 94.512 24.181 ;
     RECT  98.928 23.317 100.248 24.419 ;
     RECT  78 3.443 78.312 25.813 ;
     RECT  91.632 24.181 94.512 31.333 ;
     RECT  91.296 31.333 94.512 31.715 ;
     RECT  81.456 14.291 81.912 31.955 ;
     RECT  81.456 31.955 81.72 32.003 ;
     RECT  115.8 2.151 116.112 32.245 ;
     RECT  0.288 32.293 0.312 32.435 ;
     RECT  67.2 2.151 67.512 32.437 ;
     RECT  69.36 32.341 69.384 32.437 ;
     RECT  68.64 32.437 69.384 32.483 ;
     RECT  61.8 11.699 62.424 32.917 ;
     RECT  56.4 2.151 56.712 33.013 ;
     RECT  61.392 32.917 62.424 33.013 ;
     RECT  72.6 2.151 72.912 33.013 ;
     RECT  74.208 32.965 74.232 33.013 ;
     RECT  96.048 32.533 96.072 33.059 ;
     RECT  81.456 32.003 81.48 33.107 ;
     RECT  98.928 24.419 99.912 33.107 ;
     RECT  63.888 32.869 63.912 33.397 ;
     RECT  75.456 26.677 75.48 33.443 ;
     RECT  63.888 33.397 64.824 33.539 ;
     RECT  51 2.151 51.312 33.589 ;
     RECT  68.64 32.483 68.664 33.589 ;
     RECT  71.664 33.013 72.912 33.589 ;
     RECT  70.8 33.589 72.912 33.637 ;
     RECT  73.92 33.013 74.232 33.637 ;
     RECT  99.12 33.107 99.912 33.683 ;
     RECT  47.664 33.589 47.688 33.925 ;
     RECT  47.664 33.925 48.6 34.115 ;
     RECT  45.6 2.151 45.912 34.117 ;
     RECT  47.664 34.115 47.688 34.117 ;
     RECT  52.896 33.589 52.92 34.165 ;
     RECT  54.144 32.869 54.168 34.165 ;
     RECT  56.4 33.013 57.048 34.165 ;
     RECT  66.576 32.437 67.512 34.165 ;
     RECT  83.4 2.151 83.712 34.165 ;
     RECT  68.64 33.589 69.48 34.547 ;
     RECT  70.8 33.637 74.232 34.643 ;
     RECT  45.6 34.117 46.008 34.741 ;
     RECT  47.328 34.117 47.688 34.741 ;
     RECT  52.896 34.165 54.168 34.741 ;
     RECT  60.144 33.013 60.168 34.741 ;
     RECT  73.92 34.643 74.232 34.741 ;
     RECT  75.504 33.637 75.528 34.741 ;
     RECT  80.88 34.357 80.904 34.741 ;
     RECT  88.8 6.419 89.112 34.741 ;
     RECT  118.224 24.181 118.248 34.789 ;
     RECT  118.224 34.789 118.344 34.835 ;
     RECT  79.776 3.925 79.8 35.029 ;
     RECT  99.6 33.683 99.912 35.029 ;
     RECT  99.6 35.029 100.872 35.219 ;
     RECT  52.896 34.741 54.696 35.315 ;
     RECT  45.6 34.741 47.688 35.317 ;
     RECT  55.872 34.165 57.048 35.317 ;
     RECT  86.256 35.269 86.28 35.317 ;
     RECT  91.296 31.715 93 35.317 ;
     RECT  99.6 35.219 100.632 35.317 ;
     RECT  109.344 34.741 109.368 35.317 ;
     RECT  110.4 2.151 110.712 35.317 ;
     RECT  63.888 33.539 63.912 35.557 ;
     RECT  109.344 35.317 110.712 35.605 ;
     RECT  82.512 34.165 83.712 35.699 ;
     RECT  59.76 34.741 60.168 35.701 ;
     RECT  61.392 33.013 62.616 35.701 ;
     RECT  50.064 33.589 51.864 35.845 ;
     RECT  75.504 34.741 76.056 35.845 ;
     RECT  77.472 25.813 78.312 35.845 ;
     RECT  80.88 34.741 81.144 35.891 ;
     RECT  79.488 35.029 79.8 36.275 ;
     RECT  49.632 35.845 51.864 36.277 ;
     RECT  99.456 35.317 100.632 36.373 ;
     RECT  102.384 35.077 102.408 36.373 ;
     RECT  109.344 35.605 111.48 36.373 ;
     RECT  59.76 35.701 62.616 36.421 ;
     RECT  63.888 35.557 64.2 36.421 ;
     RECT  88.704 34.741 89.112 36.421 ;
     RECT  96.144 35.605 96.168 36.421 ;
     RECT  55.872 35.317 57.144 36.469 ;
     RECT  69.216 34.547 69.48 36.469 ;
     RECT  52.992 35.315 54.696 36.515 ;
     RECT  69.216 36.469 69.528 36.661 ;
     RECT  70.8 34.643 72.912 36.661 ;
     RECT  45.504 35.317 47.688 36.757 ;
     RECT  112.896 35.317 112.92 36.805 ;
     RECT  108.72 36.373 111.48 36.851 ;
     RECT  73.92 34.741 74.52 36.949 ;
     RECT  75.504 35.845 78.312 36.949 ;
     RECT  99.456 36.373 102.408 36.949 ;
     RECT  103.824 34.741 103.848 36.949 ;
     RECT  105 2.151 105.312 36.949 ;
     RECT  43.248 34.501 43.272 36.997 ;
     RECT  44.4 34.501 44.424 36.997 ;
     RECT  58.752 35.605 58.776 36.997 ;
     RECT  59.76 36.421 64.2 36.997 ;
     RECT  106.32 35.077 106.344 36.997 ;
     RECT  45.504 36.757 47.784 37.043 ;
     RECT  49.056 36.277 51.864 37.043 ;
     RECT  115.44 32.245 116.112 37.045 ;
     RECT  47.328 37.043 47.784 37.091 ;
     RECT  55.872 36.469 57.384 37.091 ;
     RECT  94.2 31.715 94.512 37.141 ;
     RECT  39.168 36.997 39.192 37.189 ;
     RECT  94.2 37.141 94.632 37.237 ;
     RECT  99.456 36.949 103.848 37.429 ;
     RECT  104.88 36.949 105.312 37.429 ;
     RECT  99.456 37.429 105.312 37.475 ;
     RECT  43.248 36.997 44.424 37.477 ;
     RECT  45.504 37.043 46.296 37.477 ;
     RECT  83.088 35.699 83.712 37.477 ;
     RECT  81.12 35.891 81.144 37.525 ;
     RECT  82.896 37.477 83.712 37.525 ;
     RECT  29.4 2.151 29.712 37.573 ;
     RECT  34.8 2.151 35.112 37.573 ;
     RECT  41.856 36.661 41.88 37.573 ;
     RECT  69.216 36.661 72.912 37.573 ;
     RECT  73.92 36.949 78.312 37.573 ;
     RECT  90.96 35.317 93 37.573 ;
     RECT  94.2 37.237 94.68 37.573 ;
     RECT  99.456 37.475 103.08 37.573 ;
     RECT  104.256 37.475 105.312 37.573 ;
     RECT  106.32 36.997 106.872 37.573 ;
     RECT  94.08 37.573 94.68 37.621 ;
     RECT  93.984 37.621 94.68 37.667 ;
     RECT  49.632 37.043 51.864 37.717 ;
     RECT  52.992 36.515 54.408 37.717 ;
     RECT  115.056 37.045 116.112 37.861 ;
     RECT  93.984 37.667 94.632 37.907 ;
     RECT  49.632 37.717 54.408 38.005 ;
     RECT  98.208 37.861 98.232 38.147 ;
     RECT  34.8 37.573 35.208 38.149 ;
     RECT  38.352 37.189 39.192 38.149 ;
     RECT  40.2 2.151 40.512 38.149 ;
     RECT  43.248 37.477 46.296 38.149 ;
     RECT  79.488 36.275 79.512 38.149 ;
     RECT  86.256 35.317 87.144 38.149 ;
     RECT  88.368 36.421 89.112 38.149 ;
     RECT  118.32 34.835 118.344 38.149 ;
     RECT  43.248 38.149 46.44 38.197 ;
     RECT  49.392 38.005 54.408 38.243 ;
     RECT  38.352 38.149 40.512 38.245 ;
     RECT  112.896 36.805 113.16 38.485 ;
     RECT  118.32 38.149 118.44 38.533 ;
     RECT  95.664 36.421 96.168 38.579 ;
     RECT  50.544 38.243 54.408 38.629 ;
     RECT  24 2.151 24.312 38.677 ;
     RECT  41.616 37.573 41.88 38.677 ;
     RECT  29.4 37.573 30.264 38.725 ;
     RECT  31.584 38.149 31.608 38.725 ;
     RECT  34.08 38.149 35.208 38.725 ;
     RECT  36.528 38.149 36.552 38.725 ;
     RECT  58.752 36.997 64.2 38.725 ;
     RECT  65.808 34.165 67.512 38.725 ;
     RECT  97.152 35.605 97.176 38.725 ;
     RECT  112.8 38.485 113.16 38.725 ;
     RECT  81.12 37.525 83.712 38.819 ;
     RECT  112.8 38.725 114.024 39.107 ;
     RECT  43.152 38.197 46.44 39.109 ;
     RECT  47.424 37.091 47.784 39.109 ;
     RECT  96.048 38.579 96.168 39.109 ;
     RECT  97.152 38.725 97.8 39.109 ;
     RECT  81.12 38.819 81.912 39.251 ;
     RECT  58.752 38.725 67.512 39.299 ;
     RECT  24 38.677 25.08 39.301 ;
     RECT  28.656 38.725 31.608 39.301 ;
     RECT  34.08 38.725 36.552 39.301 ;
     RECT  37.728 38.245 40.512 39.301 ;
     RECT  49.392 38.243 49.416 39.301 ;
     RECT  50.544 38.629 54.84 39.301 ;
     RECT  79.488 38.149 79.656 39.301 ;
     RECT  85.008 35.605 85.032 39.301 ;
     RECT  86.256 38.149 89.112 39.301 ;
     RECT  117.648 38.533 118.44 39.301 ;
     RECT  119.52 39.061 119.544 39.301 ;
     RECT  81.12 39.251 81.672 39.349 ;
     RECT  121.2 11.125 122.232 39.397 ;
     RECT  69.216 37.573 78.312 39.443 ;
     RECT  80.928 39.349 81.672 39.539 ;
     RECT  82.896 38.819 83.712 39.541 ;
     RECT  85.008 39.301 89.448 39.541 ;
     RECT  117.648 39.301 119.544 39.541 ;
     RECT  121.056 39.397 122.232 39.589 ;
     RECT  126.6 2.151 126.912 39.589 ;
     RECT  90.72 37.573 93 39.637 ;
     RECT  93.984 37.907 94.512 39.637 ;
     RECT  117.648 39.541 119.736 39.683 ;
     RECT  82.896 39.541 89.448 39.731 ;
     RECT  96.048 39.109 97.8 39.733 ;
     RECT  58.896 39.299 67.512 39.779 ;
     RECT  69.216 39.443 69.48 39.779 ;
     RECT  70.8 39.443 78.312 39.779 ;
     RECT  109.008 36.851 111.48 39.829 ;
     RECT  117.648 39.683 119.544 39.875 ;
     RECT  28.368 39.301 31.608 39.877 ;
     RECT  34.08 39.301 40.512 39.877 ;
     RECT  120.96 39.589 122.232 39.877 ;
     RECT  123.408 39.301 123.432 39.877 ;
     RECT  96.048 39.733 98.088 40.165 ;
     RECT  99.216 37.573 103.08 40.165 ;
     RECT  81.024 39.539 81.672 40.355 ;
     RECT  86.688 39.731 89.448 40.357 ;
     RECT  90.72 39.637 94.512 40.357 ;
     RECT  28.224 39.877 31.944 40.405 ;
     RECT  64.176 39.779 67.512 40.405 ;
     RECT  113.136 39.107 114.024 40.405 ;
     RECT  115.056 37.861 116.28 40.405 ;
     RECT  120.96 39.877 123.432 40.405 ;
     RECT  128.448 39.253 128.472 40.405 ;
     RECT  132 2.151 132.312 40.405 ;
     RECT  128.448 40.405 129.096 40.451 ;
     RECT  79.488 39.301 79.848 40.499 ;
     RECT  120.864 40.405 123.432 40.595 ;
     RECT  113.136 40.405 116.28 40.835 ;
     RECT  114.48 40.835 116.28 40.933 ;
     RECT  117.648 39.875 119.256 40.933 ;
     RECT  64.176 40.405 67.8 40.981 ;
     RECT  69.216 39.779 69.432 40.981 ;
     RECT  109.008 39.829 112.056 40.981 ;
     RECT  125.712 39.589 126.912 40.981 ;
     RECT  132 40.405 132.408 40.981 ;
     RECT  133.776 40.405 133.8 40.981 ;
     RECT  137.4 2.151 137.712 40.981 ;
     RECT  82.896 39.731 85.512 41.029 ;
     RECT  24 39.301 26.376 41.075 ;
     RECT  58.896 39.779 62.952 41.075 ;
     RECT  86.688 40.357 94.512 41.075 ;
     RECT  96.048 40.165 103.08 41.075 ;
     RECT  113.136 40.835 113.352 41.075 ;
     RECT  49.392 39.301 54.84 41.077 ;
     RECT  56.064 37.091 57.384 41.077 ;
     RECT  82.896 41.029 85.656 41.123 ;
     RECT  135.648 40.981 135.672 41.173 ;
     RECT  136.896 40.981 137.712 41.173 ;
     RECT  70.944 39.779 78.312 41.221 ;
     RECT  131.76 40.981 133.8 41.221 ;
     RECT  49.392 41.077 57.384 41.267 ;
     RECT  41.52 38.677 41.88 41.317 ;
     RECT  43.152 39.109 47.784 41.317 ;
     RECT  141.312 2.151 143.112 41.461 ;
     RECT  33.12 39.877 40.512 41.555 ;
     RECT  41.52 41.317 47.784 41.555 ;
     RECT  18.6 2.151 18.912 41.557 ;
     RECT  20.208 41.509 20.232 41.557 ;
     RECT  64.176 40.981 69.432 41.557 ;
     RECT  141.312 41.461 143.976 41.557 ;
     RECT  114.48 40.933 119.256 41.651 ;
     RECT  120.864 40.595 123.384 41.651 ;
     RECT  49.392 41.267 54.84 41.653 ;
     RECT  13.2 2.151 13.512 41.701 ;
     RECT  55.968 41.267 57.384 41.795 ;
     RECT  37.728 41.555 40.512 41.797 ;
     RECT  41.52 41.555 41.88 41.797 ;
     RECT  79.488 40.499 79.656 41.797 ;
     RECT  129.072 40.451 129.096 41.797 ;
     RECT  79.44 41.797 79.656 41.843 ;
     RECT  25.44 41.075 26.376 41.891 ;
     RECT  123.36 41.651 123.384 41.893 ;
     RECT  108.576 40.981 112.056 41.939 ;
     RECT  131.76 41.221 134.664 41.941 ;
     RECT  135.648 41.173 137.712 41.941 ;
     RECT  9.12 41.845 9.144 41.987 ;
     RECT  49.008 41.653 54.84 41.987 ;
     RECT  131.76 41.941 137.712 41.987 ;
     RECT  70.944 41.221 78.456 41.989 ;
     RECT  79.44 41.843 79.512 41.989 ;
     RECT  86.688 41.075 89.448 42.037 ;
     RECT  90.72 41.075 94.512 42.037 ;
     RECT  18.6 41.557 20.232 42.085 ;
     RECT  24 41.075 24.312 42.085 ;
     RECT  83.088 41.123 85.656 42.085 ;
     RECT  43.008 41.555 47.784 42.131 ;
     RECT  12.048 40.981 12.072 42.133 ;
     RECT  13.104 41.701 13.512 42.133 ;
     RECT  64.176 41.557 69.96 42.133 ;
     RECT  70.944 41.989 79.512 42.133 ;
     RECT  82.704 42.085 85.656 42.133 ;
     RECT  86.688 42.037 94.512 42.133 ;
     RECT  139.008 40.981 139.032 42.133 ;
     RECT  49.92 41.987 54.84 42.179 ;
     RECT  64.176 42.133 79.512 42.179 ;
     RECT  131.76 41.987 135.144 42.227 ;
     RECT  136.224 41.987 137.712 42.275 ;
     RECT  7.8 2.151 8.112 42.469 ;
     RECT  120.864 41.651 122.232 42.563 ;
     RECT  27.552 40.405 31.944 42.565 ;
     RECT  33.12 41.555 36.552 42.565 ;
     RECT  7.8 42.469 8.328 42.611 ;
     RECT  9.504 42.085 9.528 42.613 ;
     RECT  27.552 42.565 36.552 42.613 ;
     RECT  58.896 41.075 60.072 42.613 ;
     RECT  12.048 42.133 13.512 42.709 ;
     RECT  23.616 42.085 24.312 42.709 ;
     RECT  96.144 41.075 103.08 42.709 ;
     RECT  136.368 42.275 137.712 42.709 ;
     RECT  61.056 41.075 62.952 42.755 ;
     RECT  82.704 42.133 94.512 42.757 ;
     RECT  95.52 42.709 103.08 42.757 ;
     RECT  130.56 42.229 130.584 42.805 ;
     RECT  16.56 41.557 16.584 42.901 ;
     RECT  18.48 42.085 21.192 42.901 ;
     RECT  82.704 42.757 103.08 42.901 ;
     RECT  104.256 37.573 107.16 42.901 ;
     RECT  16.56 42.901 21.192 42.949 ;
     RECT  22.176 39.877 22.2 42.949 ;
     RECT  16.56 42.949 22.2 42.995 ;
     RECT  6.336 42.613 6.36 43.141 ;
     RECT  114.48 41.651 119.16 43.141 ;
     RECT  123.36 41.893 123.672 43.189 ;
     RECT  108.576 41.939 109.032 43.237 ;
     RECT  110.016 41.939 112.056 43.237 ;
     RECT  123.36 43.189 123.816 43.285 ;
     RECT  43.008 42.131 44.472 43.331 ;
     RECT  123.264 43.285 123.816 43.331 ;
     RECT  131.808 42.227 135.144 43.331 ;
     RECT  123.264 43.331 123.672 43.379 ;
     RECT  55.968 41.795 57.192 43.381 ;
     RECT  128.976 41.797 129.096 43.381 ;
     RECT  23.616 42.709 24.408 43.429 ;
     RECT  25.44 41.891 25.704 43.429 ;
     RECT  23.616 43.429 25.704 43.477 ;
     RECT  45.504 42.131 47.784 43.523 ;
     RECT  58.656 42.613 60.072 43.523 ;
     RECT  140.688 41.557 143.976 43.523 ;
     RECT  71.712 42.179 79.512 43.525 ;
     RECT  12.048 42.709 13.608 43.571 ;
     RECT  148.2 2.151 148.512 43.573 ;
     RECT  37.728 41.797 41.88 43.619 ;
     RECT  125.712 40.981 127.704 43.669 ;
     RECT  81.024 40.355 81.624 43.765 ;
     RECT  82.704 42.901 107.16 43.765 ;
     RECT  27.552 42.613 36.744 43.811 ;
     RECT  81.024 43.765 107.16 43.811 ;
     RECT  9.504 42.613 9.96 43.861 ;
     RECT  12.336 43.571 13.608 43.861 ;
     RECT  14.784 42.709 14.808 43.861 ;
     RECT  27.6 43.811 36.744 43.861 ;
     RECT  61.056 42.755 62.664 43.861 ;
     RECT  12.336 43.861 15.528 43.907 ;
     RECT  136.368 42.709 137.976 44.005 ;
     RECT  139.008 42.133 139.704 44.005 ;
     RECT  108.576 43.237 112.056 44.053 ;
     RECT  113.328 41.075 113.352 44.053 ;
     RECT  108.576 44.053 113.352 44.099 ;
     RECT  64.176 42.179 70.248 44.197 ;
     RECT  23.568 43.477 25.704 44.293 ;
     RECT  16.56 42.995 19.032 44.339 ;
     RECT  140.688 43.523 143.688 44.339 ;
     RECT  49.92 42.179 54.696 44.341 ;
     RECT  55.968 43.381 57.432 44.341 ;
     RECT  49.92 44.341 57.432 44.389 ;
     RECT  58.656 43.523 59.976 44.389 ;
     RECT  61.008 43.861 62.664 44.437 ;
     RECT  63.84 44.197 70.248 44.437 ;
     RECT  108.576 44.099 112.92 44.437 ;
     RECT  23.568 44.293 25.944 44.531 ;
     RECT  120.912 42.563 122.232 44.533 ;
     RECT  123.264 43.379 123.576 44.533 ;
     RECT  27.6 43.861 36.792 44.581 ;
     RECT  128.976 43.381 129.432 44.629 ;
     RECT  49.92 44.389 59.976 44.677 ;
     RECT  49.92 44.677 60.024 44.773 ;
     RECT  81.264 43.811 101.016 44.819 ;
     RECT  49.68 44.773 60.024 44.867 ;
     RECT  45.504 43.523 47.688 44.869 ;
     RECT  7.8 42.611 8.232 44.965 ;
     RECT  9.504 43.861 10.248 44.965 ;
     RECT  49.68 44.867 59.976 44.965 ;
     RECT  114.432 43.141 119.16 44.965 ;
     RECT  145.728 43.285 145.752 44.965 ;
     RECT  20.112 42.995 21.912 45.059 ;
     RECT  131.808 43.331 132.648 45.059 ;
     RECT  43.008 43.331 44.424 45.109 ;
     RECT  45.504 44.869 47.88 45.109 ;
     RECT  71.712 43.525 79.656 45.155 ;
     RECT  23.568 44.531 24.552 45.157 ;
     RECT  124.848 43.669 127.704 45.253 ;
     RECT  128.976 44.629 129.48 45.253 ;
     RECT  5.52 43.141 6.36 45.301 ;
     RECT  124.848 45.253 129.48 45.491 ;
     RECT  12.336 43.907 13.848 45.541 ;
     RECT  43.008 45.109 47.88 45.541 ;
     RECT  49.056 44.965 59.976 45.541 ;
     RECT  4.992 45.301 6.36 45.589 ;
     RECT  71.712 45.155 76.344 45.635 ;
     RECT  15.504 43.907 15.528 45.685 ;
     RECT  16.56 44.339 16.584 45.685 ;
     RECT  15.504 45.685 16.584 45.829 ;
     RECT  17.568 44.339 19.032 45.829 ;
     RECT  37.872 43.619 41.88 45.829 ;
     RECT  43.008 45.541 59.976 45.829 ;
     RECT  61.008 44.437 70.248 45.829 ;
     RECT  15.504 45.829 19.032 45.875 ;
     RECT  7.8 44.965 10.248 45.877 ;
     RECT  11.712 45.541 13.992 45.877 ;
     RECT  27.6 44.581 36.888 45.877 ;
     RECT  37.872 45.829 59.976 45.877 ;
     RECT  145.632 44.965 146.28 45.877 ;
     RECT  7.8 45.877 13.992 45.923 ;
     RECT  20.448 45.059 21.912 45.923 ;
     RECT  61.008 45.829 70.584 45.923 ;
     RECT  81.264 44.819 96.744 45.925 ;
     RECT  97.776 44.819 101.016 45.925 ;
     RECT  27.6 45.877 59.976 46.019 ;
     RECT  37.872 46.019 59.976 46.067 ;
     RECT  20.448 45.923 20.472 46.069 ;
     RECT  22.944 45.157 24.552 46.069 ;
     RECT  25.536 44.531 25.944 46.069 ;
     RECT  131.808 45.059 132.456 46.069 ;
     RECT  133.632 43.331 135.144 46.069 ;
     RECT  27.6 46.019 36.888 46.117 ;
     RECT  81.264 45.925 101.016 46.117 ;
     RECT  129.072 45.491 129.48 46.117 ;
     RECT  130.56 42.805 130.824 46.117 ;
     RECT  145.632 45.877 147.048 46.163 ;
     RECT  114.432 44.965 119.832 46.165 ;
     RECT  61.056 45.923 70.584 46.211 ;
     RECT  81.216 46.117 101.016 46.357 ;
     RECT  102 43.811 107.16 46.357 ;
     RECT  108.336 44.437 112.92 46.357 ;
     RECT  63.84 46.211 70.584 46.403 ;
     RECT  140.736 44.339 143.688 46.453 ;
     RECT  136.368 44.005 139.704 46.499 ;
     RECT  140.736 46.453 144.552 46.499 ;
     RECT  120.912 44.533 123.576 46.597 ;
     RECT  18.48 45.875 19.032 46.693 ;
     RECT  20.112 46.069 20.472 46.693 ;
     RECT  64.128 46.403 70.584 46.741 ;
     RECT  71.712 45.635 75.816 46.741 ;
     RECT  27.456 46.117 36.888 46.787 ;
     RECT  64.128 46.741 75.816 46.787 ;
     RECT  4.992 45.589 6.408 46.885 ;
     RECT  15.504 45.875 16.92 46.931 ;
     RECT  27.456 46.787 36.744 46.933 ;
     RECT  37.872 46.067 59.352 47.027 ;
     RECT  120.912 46.597 123.672 47.027 ;
     RECT  22.944 46.069 25.944 47.029 ;
     RECT  27.168 46.933 36.744 47.029 ;
     RECT  2.4 2.151 2.712 47.173 ;
     RECT  3.696 44.965 3.72 47.173 ;
     RECT  21.888 45.923 21.912 47.173 ;
     RECT  61.248 46.211 62.664 47.173 ;
     RECT  114.336 46.165 119.832 47.173 ;
     RECT  21.744 47.173 21.912 47.219 ;
     RECT  77.472 45.155 79.656 47.221 ;
     RECT  4.896 46.885 6.408 47.269 ;
     RECT  7.8 45.923 9.96 47.269 ;
     RECT  18.48 46.693 20.472 47.269 ;
     RECT  77.472 47.221 79.848 47.269 ;
     RECT  81.216 46.357 112.92 47.269 ;
     RECT  148.2 43.573 148.632 47.269 ;
     RECT  18.48 47.269 20.52 47.315 ;
     RECT  124.848 45.491 127.704 47.315 ;
     RECT  71.472 46.787 75.816 47.317 ;
     RECT  77.472 47.269 112.92 47.317 ;
     RECT  145.632 46.163 145.752 47.317 ;
     RECT  146.736 46.163 147.048 47.317 ;
     RECT  121.056 47.027 123.672 47.507 ;
     RECT  58.752 47.027 59.352 47.509 ;
     RECT  20.448 47.315 20.52 47.557 ;
     RECT  21.744 47.219 21.768 47.557 ;
     RECT  121.056 47.507 123.432 47.651 ;
     RECT  18.48 47.315 19.464 47.749 ;
     RECT  136.608 46.499 139.704 47.749 ;
     RECT  140.736 46.499 143.112 47.749 ;
     RECT  11.184 45.923 13.992 47.845 ;
     RECT  69.216 46.787 70.296 47.845 ;
     RECT  131.808 46.069 135.144 47.845 ;
     RECT  136.608 47.749 143.112 47.845 ;
     RECT  150.048 47.221 150.072 47.845 ;
     RECT  71.472 47.317 112.92 47.891 ;
     RECT  18.336 47.749 19.464 47.893 ;
     RECT  131.808 47.845 143.112 47.893 ;
     RECT  144.528 46.499 144.552 47.893 ;
     RECT  37.872 47.027 57.672 47.939 ;
     RECT  99.6 47.891 112.92 47.939 ;
     RECT  104.688 47.939 107.016 47.987 ;
     RECT  64.128 46.787 67.848 48.085 ;
     RECT  69.168 47.845 70.296 48.085 ;
     RECT  71.472 47.891 98.616 48.085 ;
     RECT  15.504 46.931 16.824 48.133 ;
     RECT  18.048 47.893 19.464 48.133 ;
     RECT  63.984 48.085 67.848 48.227 ;
     RECT  131.808 47.893 144.552 48.325 ;
     RECT  145.632 47.317 147.048 48.325 ;
     RECT  131.808 48.325 147.048 48.371 ;
     RECT  144.672 48.371 147.048 48.373 ;
     RECT  148.2 47.269 148.824 48.373 ;
     RECT  144.672 48.373 148.824 48.419 ;
     RECT  11.184 47.845 14.088 48.421 ;
     RECT  15.504 48.133 19.464 48.421 ;
     RECT  61.056 47.173 62.664 48.421 ;
     RECT  64.08 48.227 67.848 48.421 ;
     RECT  129.072 46.117 130.824 48.421 ;
     RECT  131.808 48.371 143.688 48.421 ;
     RECT  37.872 47.939 49.272 48.515 ;
     RECT  43.008 48.515 49.272 48.611 ;
     RECT  60.528 48.421 62.664 48.659 ;
     RECT  22.944 47.029 36.744 48.661 ;
     RECT  37.872 48.515 41.88 48.661 ;
     RECT  50.256 47.939 57.672 48.805 ;
     RECT  99.6 47.939 103.704 48.899 ;
     RECT  58.752 47.509 59.544 48.901 ;
     RECT  60.528 48.659 62.472 48.901 ;
     RECT  64.08 48.421 68.088 48.901 ;
     RECT  69.168 48.085 98.616 48.901 ;
     RECT  147.888 48.419 148.824 48.901 ;
     RECT  22.944 48.661 41.88 48.947 ;
     RECT  20.448 47.557 21.768 48.949 ;
     RECT  104.688 47.987 106.536 48.949 ;
     RECT  108.048 47.939 112.056 48.949 ;
     RECT  114.336 47.173 120.072 48.995 ;
     RECT  37.056 48.947 41.88 49.043 ;
     RECT  64.08 48.901 98.616 49.043 ;
     RECT  64.08 49.043 68.088 49.091 ;
     RECT  129.072 48.421 143.688 49.091 ;
     RECT  104.688 48.949 112.488 49.141 ;
     RECT  121.2 47.651 123.432 49.189 ;
     RECT  50.256 48.805 57.72 49.333 ;
     RECT  58.752 48.901 62.472 49.333 ;
     RECT  140.448 49.091 143.688 49.333 ;
     RECT  144.672 48.419 146.856 49.333 ;
     RECT  140.448 49.333 146.856 49.379 ;
     RECT  4.896 47.269 9.96 49.381 ;
     RECT  11.184 48.421 19.464 49.381 ;
     RECT  124.848 47.315 127.656 49.429 ;
     RECT  37.392 49.043 41.88 49.477 ;
     RECT  129.072 49.091 139.464 49.477 ;
     RECT  4.896 49.381 19.464 49.523 ;
     RECT  124.416 49.429 127.656 49.523 ;
     RECT  144.144 49.379 146.856 49.525 ;
     RECT  147.888 48.901 148.968 49.525 ;
     RECT  126.096 49.523 127.656 49.619 ;
     RECT  37.392 49.477 41.928 49.669 ;
     RECT  43.008 48.611 48.216 49.669 ;
     RECT  104.688 49.141 113.112 49.811 ;
     RECT  124.416 49.523 124.968 49.859 ;
     RECT  11.088 49.523 19.464 49.909 ;
     RECT  20.448 48.949 21.96 49.909 ;
     RECT  11.088 49.909 21.96 49.955 ;
     RECT  37.392 49.669 48.216 49.957 ;
     RECT  49.248 48.611 49.272 49.957 ;
     RECT  69.168 49.043 98.616 50.003 ;
     RECT  128.832 49.477 139.464 50.101 ;
     RECT  140.448 49.379 143.112 50.101 ;
     RECT  11.088 49.955 20.472 50.195 ;
     RECT  50.256 49.333 62.472 50.195 ;
     RECT  126.096 49.619 127.608 50.195 ;
     RECT  69.168 50.003 96.84 50.339 ;
     RECT  69.168 50.339 79.416 50.389 ;
     RECT  126.096 50.195 127.56 50.435 ;
     RECT  144.144 49.525 148.968 50.435 ;
     RECT  99.6 48.899 103.608 50.533 ;
     RECT  80.496 50.339 96.84 50.771 ;
     RECT  97.872 50.003 98.616 50.771 ;
     RECT  22.944 48.947 36.024 50.773 ;
     RECT  37.392 49.957 49.272 50.773 ;
     RECT  2.4 47.173 3.72 50.963 ;
     RECT  22.944 50.773 49.272 50.963 ;
     RECT  124.416 49.859 124.44 50.965 ;
     RECT  128.832 50.101 143.112 51.011 ;
     RECT  97.872 50.771 98.328 51.059 ;
     RECT  99.6 50.533 103.704 51.061 ;
     RECT  98.064 51.059 98.328 51.107 ;
     RECT  4.896 49.523 9.96 51.109 ;
     RECT  11.088 50.195 16.008 51.109 ;
     RECT  150.048 47.845 150.36 51.253 ;
     RECT  17.136 50.195 20.472 51.347 ;
     RECT  118.992 48.995 120.072 51.349 ;
     RECT  121.056 49.189 123.432 51.349 ;
     RECT  128.832 51.011 139.704 51.349 ;
     RECT  99.504 51.061 103.704 51.445 ;
     RECT  104.688 49.811 109.272 51.445 ;
     RECT  124.416 50.965 124.488 51.445 ;
     RECT  124.416 51.445 124.584 51.587 ;
     RECT  128.544 51.349 139.704 51.587 ;
     RECT  114.336 48.995 117.816 51.589 ;
     RECT  118.992 51.349 123.432 51.589 ;
     RECT  22.944 50.963 36.024 51.635 ;
     RECT  114.336 51.589 123.432 51.635 ;
     RECT  64.08 49.091 67.896 51.683 ;
     RECT  99.504 51.445 109.272 51.683 ;
     RECT  153.6 2.151 153.912 51.733 ;
     RECT  17.232 51.347 20.472 51.781 ;
     RECT  58.656 50.195 62.472 51.781 ;
     RECT  17.232 51.781 20.52 51.829 ;
     RECT  21.744 49.955 21.96 51.829 ;
     RECT  37.248 50.963 49.272 51.829 ;
     RECT  50.256 50.195 57.672 51.829 ;
     RECT  121.056 51.635 123.432 51.829 ;
     RECT  124.416 51.587 124.488 51.829 ;
     RECT  37.248 51.829 57.672 51.875 ;
     RECT  126.096 50.435 127.512 51.877 ;
     RECT  22.944 51.635 26.952 51.923 ;
     RECT  126.096 51.877 127.56 51.923 ;
     RECT  128.88 51.587 139.704 51.923 ;
     RECT  28.032 51.635 36.024 51.971 ;
     RECT  80.496 50.771 94.92 52.019 ;
     RECT  2.4 50.963 2.712 52.021 ;
     RECT  3.696 50.963 3.72 52.021 ;
     RECT  121.056 51.829 124.488 52.067 ;
     RECT  145.632 50.435 148.968 52.117 ;
     RECT  150.048 51.253 151.176 52.117 ;
     RECT  4.896 51.109 16.008 52.163 ;
     RECT  87.456 52.019 94.92 52.307 ;
     RECT  135.888 51.923 139.704 52.307 ;
     RECT  153.6 51.733 154.2 52.309 ;
     RECT  4.896 52.163 13.656 52.405 ;
     RECT  153.36 52.309 154.2 52.405 ;
     RECT  159 2.151 159.312 52.405 ;
     RECT  64.08 51.683 67.704 52.499 ;
     RECT  114.336 51.635 120.072 52.499 ;
     RECT  58.656 51.781 62.616 52.693 ;
     RECT  4.848 52.405 13.656 52.739 ;
     RECT  37.248 51.875 52.296 52.739 ;
     RECT  104.688 51.683 109.272 52.741 ;
     RECT  110.256 49.811 113.112 52.741 ;
     RECT  145.632 52.117 151.176 52.789 ;
     RECT  156.672 52.405 156.696 52.885 ;
     RECT  64.08 52.499 67.656 52.931 ;
     RECT  145.632 52.789 151.752 52.931 ;
     RECT  156.576 52.885 156.696 52.931 ;
     RECT  17.232 51.829 21.96 52.933 ;
     RECT  37.248 52.739 41.112 52.981 ;
     RECT  33.84 51.971 36.024 53.029 ;
     RECT  37.056 52.981 41.112 53.029 ;
     RECT  140.832 51.011 143.112 53.029 ;
     RECT  144.144 50.435 144.312 53.029 ;
     RECT  145.632 52.931 151.176 53.029 ;
     RECT  159 52.405 160.152 53.029 ;
     RECT  80.496 52.019 86.472 53.075 ;
     RECT  104.688 52.741 113.112 53.075 ;
     RECT  140.832 53.029 151.176 53.075 ;
     RECT  99.504 51.683 103.704 53.267 ;
     RECT  161.76 52.453 161.784 53.269 ;
     RECT  140.832 53.075 148.872 53.363 ;
     RECT  96.24 50.771 96.84 53.365 ;
     RECT  144.288 53.363 148.872 53.411 ;
     RECT  155.376 52.885 155.4 53.413 ;
     RECT  156.576 52.931 156.6 53.413 ;
     RECT  153.024 52.405 154.2 53.459 ;
     RECT  155.376 53.413 156.6 53.459 ;
     RECT  96.24 53.365 96.888 53.461 ;
     RECT  161.616 53.269 161.784 53.509 ;
     RECT  162.96 52.405 162.984 53.509 ;
     RECT  42.48 52.739 52.296 53.557 ;
     RECT  53.28 51.875 57.672 53.557 ;
     RECT  42.48 53.557 57.672 53.603 ;
     RECT  58.656 52.693 62.664 53.603 ;
     RECT  69.072 50.389 79.416 53.603 ;
     RECT  139.488 52.307 139.704 53.603 ;
     RECT  114.528 52.499 120.072 53.653 ;
     RECT  121.056 52.067 124.44 53.653 ;
     RECT  144.288 53.411 144.312 53.699 ;
     RECT  114.528 53.653 124.44 53.891 ;
     RECT  139.632 53.603 139.704 53.941 ;
     RECT  140.832 53.363 143.112 53.941 ;
     RECT  155.616 53.459 156.6 53.941 ;
     RECT  101.952 53.267 103.704 54.035 ;
     RECT  4.848 52.739 10.008 54.037 ;
     RECT  4.848 54.037 10.056 54.085 ;
     RECT  11.184 52.739 13.656 54.085 ;
     RECT  28.032 51.971 32.76 54.085 ;
     RECT  150.048 53.075 151.176 54.085 ;
     RECT  47.328 53.603 57.672 54.131 ;
     RECT  26.928 51.923 26.952 54.179 ;
     RECT  33.84 53.029 41.112 54.179 ;
     RECT  69.072 53.603 74.088 54.179 ;
     RECT  158.448 53.029 160.152 54.179 ;
     RECT  153.12 53.459 154.2 54.227 ;
     RECT  47.328 54.131 57.624 54.275 ;
     RECT  96.24 53.461 96.984 54.371 ;
     RECT  161.616 53.509 162.984 54.371 ;
     RECT  139.632 53.941 143.112 54.469 ;
     RECT  99.504 53.267 100.728 54.563 ;
     RECT  104.832 53.075 113.112 54.563 ;
     RECT  145.632 53.411 148.872 54.563 ;
     RECT  17.136 52.933 21.96 54.565 ;
     RECT  2.4 52.021 3.72 54.613 ;
     RECT  4.848 54.085 13.656 54.613 ;
     RECT  135.888 52.307 138.312 54.613 ;
     RECT  139.632 54.469 144.024 54.659 ;
     RECT  155.616 53.941 156.84 54.661 ;
     RECT  42.48 53.603 45.912 54.707 ;
     RECT  75.6 53.603 79.416 54.709 ;
     RECT  80.496 53.075 81.24 54.709 ;
     RECT  164.4 2.151 164.712 54.709 ;
     RECT  2.4 54.613 13.656 54.755 ;
     RECT  27.936 54.085 32.76 54.755 ;
     RECT  135.84 54.613 138.312 54.755 ;
     RECT  87.456 52.307 94.872 54.853 ;
     RECT  96.24 54.371 96.84 54.853 ;
     RECT  69.408 54.179 74.088 54.899 ;
     RECT  75.6 54.709 81.24 54.947 ;
     RECT  64.08 52.931 64.44 54.997 ;
     RECT  65.472 52.931 67.656 54.997 ;
     RECT  14.784 52.163 16.008 55.141 ;
     RECT  17.136 54.565 22.056 55.141 ;
     RECT  152.16 55.141 152.184 55.189 ;
     RECT  153.36 54.227 154.2 55.189 ;
     RECT  107.136 54.563 113.112 55.235 ;
     RECT  5.328 54.755 13.656 55.237 ;
     RECT  118.896 53.891 124.44 55.237 ;
     RECT  126.432 51.923 127.56 55.237 ;
     RECT  155.616 54.661 157.512 55.237 ;
     RECT  159 54.179 160.152 55.237 ;
     RECT  98.304 51.107 98.328 55.285 ;
     RECT  5.328 55.237 13.704 55.331 ;
     RECT  47.328 54.275 48.216 55.331 ;
     RECT  69.408 54.899 69.912 55.331 ;
     RECT  75.6 54.947 78.936 55.331 ;
     RECT  149.952 54.085 151.176 55.331 ;
     RECT  42.48 54.707 43.368 55.333 ;
     RECT  33.84 54.179 40.512 55.381 ;
     RECT  82.224 53.075 86.472 55.381 ;
     RECT  87.456 54.853 96.84 55.381 ;
     RECT  128.88 51.923 134.712 55.381 ;
     RECT  109.2 55.235 113.112 55.427 ;
     RECT  146.304 54.563 148.872 55.427 ;
     RECT  41.904 55.333 43.368 55.429 ;
     RECT  118.896 55.237 125.16 55.475 ;
     RECT  33.84 55.381 40.632 55.477 ;
     RECT  41.856 55.429 43.368 55.477 ;
     RECT  64.08 54.997 67.656 55.477 ;
     RECT  126.432 55.237 127.656 55.523 ;
     RECT  164.304 54.709 164.712 55.525 ;
     RECT  166.08 54.661 166.104 55.525 ;
     RECT  23.328 51.923 25.56 55.573 ;
     RECT  26.88 54.517 26.904 55.573 ;
     RECT  23.328 55.573 26.904 55.619 ;
     RECT  118.896 55.475 120.072 55.621 ;
     RECT  64.08 55.477 68.232 55.715 ;
     RECT  126.432 55.523 127.512 55.715 ;
     RECT  28.32 54.755 32.76 55.717 ;
     RECT  33.84 55.477 43.368 55.717 ;
     RECT  28.32 55.717 43.368 55.763 ;
     RECT  2.4 54.755 3.96 55.813 ;
     RECT  5.328 55.331 10.632 55.813 ;
     RECT  97.872 55.285 98.328 55.813 ;
     RECT  164.304 55.525 166.104 55.813 ;
     RECT  28.32 55.763 40.512 55.859 ;
     RECT  14.784 55.141 22.056 55.907 ;
     RECT  28.32 55.859 37.272 55.907 ;
     RECT  126.6 55.715 127.512 55.907 ;
     RECT  139.92 54.659 144.024 55.907 ;
     RECT  104.832 54.563 105.864 55.955 ;
     RECT  121.056 55.475 125.16 55.955 ;
     RECT  155.616 55.237 160.152 55.955 ;
     RECT  17.136 55.907 22.056 56.099 ;
     RECT  11.856 55.331 13.704 56.101 ;
     RECT  14.784 55.907 15.912 56.101 ;
     RECT  22.032 56.099 22.056 56.101 ;
     RECT  22.032 56.101 22.344 56.149 ;
     RECT  23.328 55.619 26.088 56.149 ;
     RECT  41.52 55.763 43.368 56.195 ;
     RECT  150.192 55.331 151.176 56.195 ;
     RECT  114.528 53.891 117.816 56.197 ;
     RECT  118.8 55.621 120.072 56.197 ;
     RECT  114.528 56.197 120.072 56.243 ;
     RECT  155.616 55.955 156.84 56.293 ;
     RECT  128.64 55.381 134.712 56.387 ;
     RECT  59.52 53.603 62.664 56.389 ;
     RECT  150.192 56.195 151.032 56.389 ;
     RECT  164.304 55.813 166.2 56.389 ;
     RECT  107.136 55.235 107.976 56.437 ;
     RECT  109.2 55.427 112.536 56.437 ;
     RECT  17.136 56.099 20.808 56.483 ;
     RECT  41.904 56.195 43.368 56.483 ;
     RECT  47.52 55.331 48.216 56.483 ;
     RECT  80.496 54.947 81.24 56.483 ;
     RECT  107.136 56.437 112.536 56.483 ;
     RECT  117.936 56.243 120.072 56.483 ;
     RECT  128.64 56.387 132.312 56.483 ;
     RECT  75.6 55.331 75.624 56.485 ;
     RECT  76.656 55.331 78.936 56.485 ;
     RECT  164.064 56.389 166.2 56.485 ;
     RECT  82.224 55.381 96.84 56.531 ;
     RECT  135.888 54.755 138.312 56.531 ;
     RECT  75.264 56.485 78.936 56.627 ;
     RECT  107.136 56.483 112.44 56.627 ;
     RECT  126.6 55.907 127.08 56.675 ;
     RECT  147.12 55.427 148.872 56.677 ;
     RECT  149.904 56.389 151.032 56.677 ;
     RECT  2.4 55.813 10.632 56.723 ;
     RECT  70.992 54.899 74.088 56.723 ;
     RECT  135.888 56.531 138.216 56.723 ;
     RECT  59.52 56.389 62.952 56.725 ;
     RECT  64.08 55.715 67.512 56.725 ;
     RECT  2.4 56.723 8.28 56.771 ;
     RECT  145.92 56.389 145.944 56.821 ;
     RECT  164.064 56.485 166.344 56.821 ;
     RECT  47.52 56.483 48.12 56.867 ;
     RECT  163.536 56.821 166.344 56.867 ;
     RECT  49.248 54.275 57.624 56.869 ;
     RECT  33.072 55.907 36.744 57.011 ;
     RECT  44.544 54.707 45.912 57.013 ;
     RECT  59.52 56.725 67.512 57.013 ;
     RECT  99.504 54.563 100.68 57.013 ;
     RECT  102.24 54.035 103.704 57.013 ;
     RECT  6.624 56.771 8.28 57.059 ;
     RECT  28.32 55.907 32.04 57.059 ;
     RECT  42.48 56.483 43.272 57.059 ;
     RECT  47.52 56.867 47.976 57.059 ;
     RECT  49.248 56.869 57.72 57.059 ;
     RECT  82.224 56.531 86.472 57.059 ;
     RECT  97.872 55.813 98.376 57.059 ;
     RECT  99.504 57.013 103.704 57.059 ;
     RECT  107.136 56.627 107.976 57.059 ;
     RECT  121.056 55.955 125.112 57.059 ;
     RECT  152.16 55.189 154.2 57.059 ;
     RECT  166.176 56.867 166.344 57.059 ;
     RECT  9.648 56.723 10.632 57.061 ;
     RECT  11.856 56.101 15.912 57.061 ;
     RECT  70.992 56.723 73.944 57.107 ;
     RECT  157.92 55.955 160.152 57.107 ;
     RECT  69.408 55.331 69.432 57.109 ;
     RECT  28.608 57.059 32.04 57.155 ;
     RECT  69.312 57.109 69.432 57.155 ;
     RECT  99.6 57.059 103.704 57.157 ;
     RECT  105 55.955 105.72 57.157 ;
     RECT  9.648 57.061 15.912 57.203 ;
     RECT  99.6 57.157 105.72 57.203 ;
     RECT  155.568 56.293 156.84 57.203 ;
     RECT  44.544 57.013 46.2 57.205 ;
     RECT  124.272 57.059 125.112 57.205 ;
     RECT  126.6 56.675 126.912 57.205 ;
     RECT  28.848 57.155 32.04 57.251 ;
     RECT  69.312 57.155 69.336 57.251 ;
     RECT  2.4 56.771 5.352 57.299 ;
     RECT  155.568 57.203 156.6 57.299 ;
     RECT  59.52 57.013 67.704 57.395 ;
     RECT  147.12 56.677 151.032 57.395 ;
     RECT  155.952 57.299 156.6 57.395 ;
     RECT  64.368 57.395 67.704 57.443 ;
     RECT  163.536 56.867 164.712 57.443 ;
     RECT  80.496 56.483 80.664 57.445 ;
     RECT  133.392 56.387 134.712 57.445 ;
     RECT  99.6 57.203 105.48 57.491 ;
     RECT  31.056 57.251 32.04 57.493 ;
     RECT  31.056 57.493 32.472 57.539 ;
     RECT  64.368 57.443 67.656 57.539 ;
     RECT  84.96 57.059 86.472 57.541 ;
     RECT  87.456 56.531 96.84 57.541 ;
     RECT  161.616 54.371 162.504 57.541 ;
     RECT  84.96 57.541 96.84 57.587 ;
     RECT  9.648 57.203 10.632 57.635 ;
     RECT  11.856 57.203 15.912 57.635 ;
     RECT  22.032 56.149 26.088 57.635 ;
     RECT  33.744 57.011 36.744 57.635 ;
     RECT  38.448 55.859 40.512 57.635 ;
     RECT  86.592 57.587 96.84 57.635 ;
     RECT  121.056 57.059 123.192 57.635 ;
     RECT  130.032 56.483 132.312 57.635 ;
     RECT  133.392 57.445 134.856 57.635 ;
     RECT  82.224 57.059 83.712 57.683 ;
     RECT  122.496 57.635 123.192 57.683 ;
     RECT  50.88 57.059 53.064 57.731 ;
     RECT  99.6 57.491 103.704 57.827 ;
     RECT  23.328 57.635 26.088 57.875 ;
     RECT  145.92 56.821 145.992 57.877 ;
     RECT  147.12 57.395 150.216 57.877 ;
     RECT  140.64 55.907 144.024 57.925 ;
     RECT  107.136 57.059 107.832 58.019 ;
     RECT  135.888 56.723 138.168 58.019 ;
     RECT  50.88 57.731 52.872 58.021 ;
     RECT  99.6 57.827 102.84 58.067 ;
     RECT  17.136 56.483 20.184 58.115 ;
     RECT  44.544 57.205 46.536 58.115 ;
     RECT  59.52 57.395 62.952 58.115 ;
     RECT  76.656 56.627 78.936 58.115 ;
     RECT  140.64 57.925 144.744 58.115 ;
     RECT  145.92 57.877 150.216 58.115 ;
     RECT  157.92 57.107 157.944 58.115 ;
     RECT  28.848 57.251 29.712 58.117 ;
     RECT  159 57.107 160.152 58.117 ;
     RECT  166.32 57.059 166.344 58.117 ;
     RECT  33.744 57.635 35.352 58.163 ;
     RECT  49.248 57.059 49.272 58.163 ;
     RECT  76.656 58.115 78.312 58.163 ;
     RECT  84.96 57.587 85.512 58.163 ;
     RECT  86.592 57.635 95.496 58.163 ;
     RECT  98.352 57.059 98.376 58.163 ;
     RECT  107.136 58.019 107.736 58.163 ;
     RECT  117.936 56.483 119.256 58.163 ;
     RECT  134.352 57.635 134.856 58.163 ;
     RECT  136.032 58.019 138.168 58.163 ;
     RECT  80.4 57.445 80.664 58.213 ;
     RECT  109.248 56.627 112.44 58.213 ;
     RECT  128.64 56.483 128.664 58.213 ;
     RECT  107.232 58.163 107.736 58.259 ;
     RECT  2.4 57.299 3.048 58.309 ;
     RECT  68.976 57.301 69 58.355 ;
     RECT  128.64 58.213 128.952 58.355 ;
     RECT  7.44 57.059 8.28 58.357 ;
     RECT  9.648 57.635 10.392 58.357 ;
     RECT  109.248 58.213 112.872 58.357 ;
     RECT  161.424 57.541 162.504 58.357 ;
     RECT  7.44 58.357 10.392 58.403 ;
     RECT  31.056 57.539 31.08 58.403 ;
     RECT  55.584 57.059 57.72 58.403 ;
     RECT  145.92 58.115 146.472 58.403 ;
     RECT  161.424 58.357 162.744 58.403 ;
     RECT  49.008 58.213 49.032 58.451 ;
     RECT  80.4 58.213 80.952 58.451 ;
     RECT  99.6 58.067 100.92 58.451 ;
     RECT  107.328 58.259 107.736 58.451 ;
     RECT  109.104 58.357 112.872 58.451 ;
     RECT  7.44 58.403 8.112 58.453 ;
     RECT  131.904 57.635 132.312 58.453 ;
     RECT  1.68 58.309 3.048 58.499 ;
     RECT  9.12 58.403 10.392 58.499 ;
     RECT  161.424 58.403 161.64 58.547 ;
     RECT  6.864 58.453 8.112 58.643 ;
     RECT  17.232 58.115 20.184 58.643 ;
     RECT  70.992 57.107 73.608 58.645 ;
     RECT  121.056 57.635 121.512 58.645 ;
     RECT  124.272 57.205 126.912 58.645 ;
     RECT  32.448 57.539 32.472 58.691 ;
     RECT  2.4 58.499 3.048 58.739 ;
     RECT  4.8 57.299 5.352 58.739 ;
     RECT  15.264 57.635 15.288 58.739 ;
     RECT  23.616 57.875 26.088 58.739 ;
     RECT  47.952 57.059 47.976 58.739 ;
     RECT  128.64 58.355 128.664 58.739 ;
     RECT  137.4 58.163 138.168 58.739 ;
     RECT  147.456 58.115 150.216 58.739 ;
     RECT  161.424 58.547 161.496 58.739 ;
     RECT  11.856 57.635 14.088 58.741 ;
     RECT  39.024 57.635 40.512 58.787 ;
     RECT  102.24 58.067 102.84 58.787 ;
     RECT  107.712 58.451 107.736 58.787 ;
     RECT  114.528 56.243 116.952 58.787 ;
     RECT  118.8 58.163 119.256 58.787 ;
     RECT  43.248 57.059 43.272 58.789 ;
     RECT  33.744 58.163 33.768 58.835 ;
     RECT  75.264 56.627 75.288 58.835 ;
     RECT  80.4 58.451 80.664 58.837 ;
     RECT  115.8 58.787 116.952 58.837 ;
     RECT  130.08 57.635 130.68 58.837 ;
     RECT  70.08 58.645 73.608 58.883 ;
     RECT  164.064 57.443 164.712 58.885 ;
     RECT  24 58.739 26.088 58.931 ;
     RECT  43.248 58.789 43.608 58.931 ;
     RECT  96.816 57.635 96.84 58.933 ;
     RECT  17.232 58.643 18.912 58.979 ;
     RECT  99.6 58.451 100.824 58.979 ;
     RECT  11.856 58.741 14.328 59.027 ;
     RECT  7.44 58.643 8.112 59.075 ;
     RECT  64.368 57.539 67.512 59.075 ;
     RECT  120.336 58.645 121.512 59.075 ;
     RECT  28.656 58.117 29.712 59.123 ;
     RECT  96.672 58.933 96.84 59.123 ;
     RECT  65.568 59.075 67.512 59.125 ;
     RECT  90.672 58.163 95.496 59.125 ;
     RECT  0.384 58.789 0.408 59.171 ;
     RECT  115.8 58.837 117.672 59.171 ;
     RECT  137.4 58.739 138.12 59.171 ;
     RECT  166.032 58.117 166.344 59.171 ;
     RECT  71.088 58.883 73.608 59.219 ;
     RECT  85.008 58.163 85.32 59.219 ;
     RECT  131.904 58.453 132.552 59.219 ;
     RECT  79.968 58.837 80.664 59.267 ;
     RECT  20.16 58.643 20.184 59.315 ;
     RECT  24 58.931 25.896 59.315 ;
     RECT  72.6 59.219 73.608 59.315 ;
     RECT  82.848 57.683 83.712 59.315 ;
     RECT  90.672 59.125 95.736 59.315 ;
     RECT  96.816 59.123 96.84 59.315 ;
     RECT  109.104 58.451 112.44 59.315 ;
     RECT  115.8 59.171 116.952 59.315 ;
     RECT  124.272 58.645 127.08 59.315 ;
     RECT  130.08 58.837 130.872 59.315 ;
     RECT  134.304 58.645 134.328 59.315 ;
     RECT  140.64 58.115 144.024 59.315 ;
     RECT  149.904 58.739 150.216 59.315 ;
     RECT  161.472 58.739 161.496 59.315 ;
     RECT  44.976 58.115 46.536 59.363 ;
     RECT  50.832 58.021 52.872 59.363 ;
     RECT  56.4 58.403 57.72 59.363 ;
     RECT  115.8 59.315 116.808 59.363 ;
     RECT  80.4 59.267 80.664 59.411 ;
     RECT  95.712 59.315 95.736 59.411 ;
     RECT  136.032 58.163 136.2 59.411 ;
     RECT  159 58.117 160.2 59.411 ;
     RECT  15.504 58.981 15.528 59.459 ;
     RECT  24 59.315 25.656 59.459 ;
     RECT  122.784 57.683 123.192 59.459 ;
     RECT  140.64 59.315 143.112 59.459 ;
     RECT  147.456 58.739 148.728 59.459 ;
     RECT  71.088 59.219 71.112 59.507 ;
     RECT  83.4 59.315 83.712 59.557 ;
     RECT  114.528 58.787 114.552 59.603 ;
     RECT  39.024 58.787 39.048 59.605 ;
     RECT  11.856 59.027 13.512 59.699 ;
     RECT  145.968 58.403 146.472 59.699 ;
     RECT  45.456 59.363 46.536 59.749 ;
     RECT  60 58.115 62.952 59.749 ;
     RECT  31.488 59.269 31.512 59.795 ;
     RECT  65.568 59.125 68.232 59.843 ;
     RECT  76.944 58.163 78.312 59.843 ;
     RECT  83.4 59.557 84.504 59.843 ;
     RECT  9.648 58.499 10.392 59.891 ;
     RECT  17.904 58.979 18.912 59.891 ;
     RECT  166.032 59.171 166.056 59.891 ;
     RECT  126.288 59.315 127.08 59.939 ;
     RECT  11.856 59.699 11.88 59.987 ;
     RECT  104.88 57.491 105.48 60.037 ;
     RECT  43.344 59.989 43.368 60.131 ;
     RECT  112.176 59.315 112.44 60.133 ;
     RECT  130.848 59.315 130.872 60.181 ;
     RECT  132 59.219 132.552 60.181 ;
     RECT  136.08 59.411 136.2 60.181 ;
     RECT  137.4 59.171 137.712 60.181 ;
     RECT  121.056 59.075 121.512 60.277 ;
     RECT  45.456 59.749 47.4 60.325 ;
     RECT  13.2 59.699 13.512 60.373 ;
     RECT  41.904 59.605 41.928 60.373 ;
     RECT  52.848 59.363 52.872 60.373 ;
     RECT  70.08 58.883 70.104 60.373 ;
     RECT  80.64 59.411 80.664 60.373 ;
     RECT  102.24 58.787 102.264 60.373 ;
     RECT  129.216 59.605 129.24 60.373 ;
     RECT  145.968 59.699 145.992 60.373 ;
     RECT  159 59.411 159.624 60.373 ;
     RECT  162.72 58.403 162.744 60.373 ;
     RECT  164.016 58.885 164.712 60.373 ;
     RECT  126.288 59.939 127.032 60.419 ;
     RECT  22.032 57.635 22.344 60.421 ;
     RECT  24 59.459 24.408 60.421 ;
     RECT  25.632 59.459 25.656 60.421 ;
     RECT  90.672 59.315 94.512 60.421 ;
     RECT  59.232 59.749 62.952 60.467 ;
     RECT  155.952 57.395 155.976 60.467 ;
     RECT  56.4 59.363 57.288 60.469 ;
     RECT  99.6 58.979 99.912 60.469 ;
     RECT  102.24 60.373 102.408 60.517 ;
     RECT  112.176 60.133 112.536 60.517 ;
     RECT  5.712 59.029 5.736 60.563 ;
     RECT  122.784 59.459 122.808 60.563 ;
     RECT  99.6 60.469 100.632 60.611 ;
     RECT  40.08 58.787 40.512 60.613 ;
     RECT  70.08 60.373 71.016 60.659 ;
     RECT  103.728 60.133 103.752 60.661 ;
     RECT  115.8 59.363 116.664 60.661 ;
     RECT  158.16 60.373 159.624 60.661 ;
     RECT  112.176 60.517 112.68 60.707 ;
     RECT  99.6 60.611 100.584 60.709 ;
     RECT  114.48 60.373 114.504 60.709 ;
     RECT  124.272 59.315 125.112 60.709 ;
     RECT  126.288 60.419 126.912 60.709 ;
     RECT  101.712 60.517 102.408 60.755 ;
     RECT  50.832 59.363 51.312 60.757 ;
     RECT  61.056 60.467 62.952 60.757 ;
     RECT  64.368 59.075 64.392 60.757 ;
     RECT  106.848 60.373 106.872 60.757 ;
     RECT  124.272 60.709 126.912 60.757 ;
     RECT  59.472 60.467 60.024 60.803 ;
     RECT  109.488 59.315 110.712 60.805 ;
     RECT  120.336 60.277 121.512 60.853 ;
     RECT  133.92 59.941 133.944 60.853 ;
     RECT  55.776 60.469 57.288 60.947 ;
     RECT  61.056 60.757 64.392 60.947 ;
     RECT  9.648 59.891 10.056 60.949 ;
     RECT  16.368 59.653 16.392 60.949 ;
     RECT  29.4 59.123 29.712 60.949 ;
     RECT  77.184 59.843 78.312 60.949 ;
     RECT  83.4 59.843 83.712 60.949 ;
     RECT  115.8 60.661 117.192 60.949 ;
     RECT  153.072 57.059 153.912 60.949 ;
     RECT  158.16 60.661 160.008 60.949 ;
     RECT  18.6 59.891 18.912 60.997 ;
     RECT  70.992 60.659 71.016 60.997 ;
     RECT  86.592 58.163 89.112 60.997 ;
     RECT  133.92 60.853 134.424 61.043 ;
     RECT  38.64 59.605 39.048 61.045 ;
     RECT  40.08 60.613 40.632 61.045 ;
     RECT  106.848 60.757 107.016 61.091 ;
     RECT  7.8 59.075 8.112 61.093 ;
     RECT  38.64 61.045 40.632 61.093 ;
     RECT  41.904 60.373 42.6 61.093 ;
     RECT  70.992 60.997 71.496 61.139 ;
     RECT  86.496 60.997 89.112 61.141 ;
     RECT  9.648 60.949 10.776 61.187 ;
     RECT  13.2 60.373 13.752 61.189 ;
     RECT  45.456 60.325 47.496 61.235 ;
     RECT  58.464 60.997 58.488 61.235 ;
     RECT  18.6 60.997 19.512 61.331 ;
     RECT  38.64 61.093 42.6 61.331 ;
     RECT  7.296 61.093 8.112 61.429 ;
     RECT  104.784 60.037 105.48 61.429 ;
     RECT  106.848 61.091 106.872 61.429 ;
     RECT  104.784 61.429 106.872 61.475 ;
     RECT  99.36 60.709 100.584 61.477 ;
     RECT  141.456 59.459 143.112 61.477 ;
     RECT  150.192 59.315 150.216 61.477 ;
     RECT  156.864 60.949 160.008 61.477 ;
     RECT  16.368 60.949 17.208 61.525 ;
     RECT  20.736 60.949 20.76 61.525 ;
     RECT  72.6 59.315 73.272 61.525 ;
     RECT  86.352 61.141 89.112 61.525 ;
     RECT  103.68 60.661 103.752 61.525 ;
     RECT  104.784 61.475 106.296 61.525 ;
     RECT  130.848 60.181 132.552 61.525 ;
     RECT  133.92 61.043 133.944 61.525 ;
     RECT  155.04 61.189 155.064 61.525 ;
     RECT  156.864 61.477 160.152 61.525 ;
     RECT  162.096 60.373 164.712 61.525 ;
     RECT  13.2 61.189 14.52 61.573 ;
     RECT  66 59.843 68.232 61.573 ;
     RECT  69.552 61.525 69.576 61.573 ;
     RECT  145.152 60.373 145.992 61.573 ;
     RECT  22.032 60.421 22.776 61.619 ;
     RECT  98.688 61.477 100.584 61.621 ;
     RECT  108.816 60.805 110.712 61.621 ;
     RECT  112.176 60.707 112.584 61.621 ;
     RECT  50.832 60.757 51.432 61.667 ;
     RECT  13.104 61.573 14.52 61.763 ;
     RECT  28.656 60.949 29.712 61.763 ;
     RECT  50.88 61.667 51.432 61.765 ;
     RECT  52.848 60.373 53.064 61.765 ;
     RECT  108.816 61.621 112.584 61.765 ;
     RECT  113.952 60.709 114.504 61.765 ;
     RECT  9.648 61.187 10.056 61.811 ;
     RECT  66 61.573 69.576 61.859 ;
     RECT  41.616 61.331 42.6 61.861 ;
     RECT  108.816 61.765 114.504 61.907 ;
     RECT  29.4 61.763 29.712 61.909 ;
     RECT  96.672 61.621 96.696 61.909 ;
     RECT  96.576 61.909 96.696 61.955 ;
     RECT  96.576 61.955 96.6 61.957 ;
     RECT  29.4 61.909 29.976 62.005 ;
     RECT  50.88 61.765 53.064 62.005 ;
     RECT  140.544 61.477 143.112 62.005 ;
     RECT  155.04 61.525 160.152 62.005 ;
     RECT  85.632 61.525 89.112 62.051 ;
     RECT  96.48 61.957 96.6 62.051 ;
     RECT  11.808 60.373 11.832 62.053 ;
     RECT  80.64 60.373 81.528 62.053 ;
     RECT  72.144 61.525 73.272 62.099 ;
     RECT  54.192 57.059 54.6 62.101 ;
     RECT  74.688 60.469 74.712 62.101 ;
     RECT  112.176 61.907 114.504 62.101 ;
     RECT  115.8 60.949 117.672 62.101 ;
     RECT  130.848 61.525 133.944 62.101 ;
     RECT  22.32 61.619 22.776 62.195 ;
     RECT  29.4 62.005 30.216 62.195 ;
     RECT  112.176 62.101 117.672 62.195 ;
     RECT  130.8 62.101 133.944 62.195 ;
     RECT  7.296 61.429 8.52 62.245 ;
     RECT  9.648 61.811 9.96 62.245 ;
     RECT  70.992 61.139 71.016 62.293 ;
     RECT  72.144 62.099 72.912 62.293 ;
     RECT  16.368 61.525 17.592 62.341 ;
     RECT  80.64 62.053 81.576 62.341 ;
     RECT  115.104 62.195 117.672 62.341 ;
     RECT  118.8 58.787 119.016 62.341 ;
     RECT  15.984 62.341 17.592 62.387 ;
     RECT  54.096 62.101 54.6 62.389 ;
     RECT  7.296 62.245 9.96 62.435 ;
     RECT  31.584 62.293 31.8 62.435 ;
     RECT  24 60.421 25.656 62.437 ;
     RECT  98.064 61.621 100.584 62.437 ;
     RECT  24 62.437 25.992 62.485 ;
     RECT  54.096 62.389 55.272 62.485 ;
     RECT  56.304 60.947 57.288 62.485 ;
     RECT  41.616 61.861 43.032 62.531 ;
     RECT  45.456 61.235 45.912 62.533 ;
     RECT  24 62.485 26.76 62.579 ;
     RECT  47.472 61.235 47.496 62.581 ;
     RECT  98.064 62.437 100.872 62.581 ;
     RECT  139.104 60.373 139.128 62.581 ;
     RECT  140.544 62.005 143.352 62.581 ;
     RECT  49.008 62.485 49.032 62.627 ;
     RECT  130.8 62.195 130.872 62.629 ;
     RECT  103.68 61.525 106.296 62.675 ;
     RECT  26.736 62.579 26.76 62.677 ;
     RECT  76.368 60.949 78.408 62.677 ;
     RECT  80.352 62.341 81.576 62.677 ;
     RECT  90.672 60.421 94.968 62.677 ;
     RECT  128.64 60.373 129.24 62.677 ;
     RECT  132 62.195 133.944 62.677 ;
     RECT  148.2 59.459 148.728 62.677 ;
     RECT  13.2 61.763 14.52 62.723 ;
     RECT  17.184 62.387 17.592 62.723 ;
     RECT  26.736 62.677 26.856 62.723 ;
     RECT  155.04 62.005 160.632 62.723 ;
     RECT  120.336 60.853 122.28 62.725 ;
     RECT  123.36 60.757 126.912 62.725 ;
     RECT  26.832 62.723 26.856 62.819 ;
     RECT  155.328 62.723 160.632 62.819 ;
     RECT  50.88 62.005 53.112 62.821 ;
     RECT  54.096 62.485 57.288 62.821 ;
     RECT  47.472 62.581 47.832 62.867 ;
     RECT  98.016 62.581 100.872 62.869 ;
     RECT  120.336 62.725 126.912 62.869 ;
     RECT  145.008 61.573 145.992 62.869 ;
     RECT  24 62.579 25.656 62.963 ;
     RECT  36.576 60.949 36.6 63.011 ;
     RECT  4.128 60.949 4.152 63.059 ;
     RECT  97.968 62.869 100.872 63.107 ;
     RECT  145.008 62.869 146.52 63.107 ;
     RECT  45.264 62.533 45.912 63.109 ;
     RECT  47.472 62.867 47.496 63.109 ;
     RECT  120.288 62.869 126.912 63.109 ;
     RECT  69.552 61.859 69.576 63.203 ;
     RECT  139.104 62.581 143.352 63.203 ;
     RECT  145.008 63.107 146.184 63.203 ;
     RECT  29.4 62.195 29.976 63.205 ;
     RECT  64.08 60.947 64.392 63.205 ;
     RECT  66 61.859 68.232 63.205 ;
     RECT  70.992 62.293 72.912 63.205 ;
     RECT  107.472 62.677 107.496 63.205 ;
     RECT  112.176 62.195 113.976 63.205 ;
     RECT  115.104 62.341 119.016 63.205 ;
     RECT  148.2 62.677 148.824 63.205 ;
     RECT  98.016 63.107 100.872 63.251 ;
     RECT  22.32 62.195 22.392 63.253 ;
     RECT  11.424 62.053 11.832 63.299 ;
     RECT  141.648 63.203 143.352 63.299 ;
     RECT  45.264 63.109 47.496 63.395 ;
     RECT  33.024 60.949 33.048 63.445 ;
     RECT  38.64 61.331 40.512 63.445 ;
     RECT  32.832 63.445 33.048 63.491 ;
     RECT  139.104 63.203 140.568 63.491 ;
     RECT  15.984 62.387 16.008 63.493 ;
     RECT  65.808 63.205 68.232 63.493 ;
     RECT  38.64 63.445 40.632 63.587 ;
     RECT  15.984 63.493 16.248 63.635 ;
     RECT  65.808 63.493 68.568 63.635 ;
     RECT  11.424 63.299 11.448 63.685 ;
     RECT  99.36 63.251 100.872 63.731 ;
     RECT  155.328 62.819 157.608 63.731 ;
     RECT  7.296 62.435 8.52 63.733 ;
     RECT  99.36 63.731 100.728 63.779 ;
     RECT  141.648 63.299 143.112 63.779 ;
     RECT  158.688 62.819 160.632 63.779 ;
     RECT  162.096 61.525 165.288 63.779 ;
     RECT  27.312 63.109 27.336 63.781 ;
     RECT  34.8 58.163 35.352 63.781 ;
     RECT  41.616 62.531 42.6 63.781 ;
     RECT  79.776 62.677 81.576 63.781 ;
     RECT  82.656 60.949 83.712 63.781 ;
     RECT  130.752 62.629 130.872 63.781 ;
     RECT  136.08 60.181 137.712 63.781 ;
     RECT  152.208 60.949 153.912 63.781 ;
     RECT  166.368 60.949 166.392 63.781 ;
     RECT  9.744 62.435 9.96 63.829 ;
     RECT  166.368 63.781 166.488 63.829 ;
     RECT  167.76 60.373 167.784 63.829 ;
     RECT  74.688 62.101 74.76 63.925 ;
     RECT  13.2 62.723 13.896 63.973 ;
     RECT  34.176 63.781 35.352 63.973 ;
     RECT  36.672 63.781 36.696 63.973 ;
     RECT  9.744 63.829 10.248 64.019 ;
     RECT  11.376 63.685 11.448 64.019 ;
     RECT  19.968 61.525 20.76 64.019 ;
     RECT  164.208 63.779 165.288 64.019 ;
     RECT  61.056 60.947 62.952 64.021 ;
     RECT  64.08 63.205 64.584 64.021 ;
     RECT  79.776 63.781 83.712 64.069 ;
     RECT  85.632 62.051 87.48 64.117 ;
     RECT  88.608 62.051 89.112 64.117 ;
     RECT  34.176 63.973 36.696 64.165 ;
     RECT  90.528 62.677 94.968 64.165 ;
     RECT  96.48 62.051 96.504 64.165 ;
     RECT  108.816 61.907 110.712 64.165 ;
     RECT  79.776 64.069 84.504 64.211 ;
     RECT  146.16 63.203 146.184 64.213 ;
     RECT  4.176 63.109 4.2 64.259 ;
     RECT  107.472 63.205 107.784 64.261 ;
     RECT  41.568 63.781 42.6 64.307 ;
     RECT  7.152 63.733 8.52 64.309 ;
     RECT  70.08 63.205 72.912 64.355 ;
     RECT  79.776 64.211 83.832 64.355 ;
     RECT  85.632 64.117 89.112 64.355 ;
     RECT  120.288 63.109 127.176 64.355 ;
     RECT  70.416 64.355 72.912 64.357 ;
     RECT  90.528 64.165 96.504 64.357 ;
     RECT  166.368 63.829 167.784 64.357 ;
     RECT  139.44 63.491 140.568 64.405 ;
     RECT  26.784 63.781 27.336 64.451 ;
     RECT  150.192 61.477 150.456 64.499 ;
     RECT  26.784 64.451 26.808 64.547 ;
     RECT  103.872 62.675 106.296 64.549 ;
     RECT  12.48 63.973 13.896 64.595 ;
     RECT  147.84 63.205 148.824 64.595 ;
     RECT  11.376 64.019 11.4 64.643 ;
     RECT  147.84 64.595 148.68 64.645 ;
     RECT  145.008 63.203 145.176 64.741 ;
     RECT  146.16 64.213 146.232 64.741 ;
     RECT  22.32 63.253 22.776 64.789 ;
     RECT  85.68 64.355 89.112 64.789 ;
     RECT  90.528 64.357 96.6 64.789 ;
     RECT  123.36 64.355 127.176 64.835 ;
     RECT  6.96 64.309 8.52 64.837 ;
     RECT  29.4 63.205 30.072 64.837 ;
     RECT  74.688 63.925 74.952 64.837 ;
     RECT  76.032 62.677 78.408 64.837 ;
     RECT  79.776 64.355 82.104 64.837 ;
     RECT  128.64 62.677 129.672 64.883 ;
     RECT  157.584 63.731 157.608 64.885 ;
     RECT  158.688 63.779 160.536 64.885 ;
     RECT  164.208 64.019 165.192 64.885 ;
     RECT  9.936 64.019 10.248 64.933 ;
     RECT  15.984 63.635 16.008 64.933 ;
     RECT  98.016 63.251 98.184 64.933 ;
     RECT  112.176 63.205 119.016 64.933 ;
     RECT  85.68 64.789 96.6 64.979 ;
     RECT  19.968 64.019 19.992 64.981 ;
     RECT  21.648 64.789 22.776 64.981 ;
     RECT  24 62.963 25.512 64.981 ;
     RECT  152.112 63.781 153.912 64.981 ;
     RECT  155.328 63.731 155.928 64.981 ;
     RECT  158.688 64.885 160.776 65.027 ;
     RECT  32.832 63.491 32.856 65.029 ;
     RECT  34.176 64.165 37.656 65.029 ;
     RECT  17.376 62.723 17.592 65.123 ;
     RECT  45.264 63.395 47.352 65.125 ;
     RECT  107.472 64.261 107.832 65.125 ;
     RECT  108.816 64.165 111.192 65.125 ;
     RECT  107.472 65.125 111.192 65.171 ;
     RECT  132 62.677 134.568 65.171 ;
     RECT  65.808 63.635 68.232 65.173 ;
     RECT  69.312 65.077 69.336 65.173 ;
     RECT  49.296 62.677 49.32 65.221 ;
     RECT  49.296 65.221 49.608 65.267 ;
     RECT  162.096 63.779 162.984 65.269 ;
     RECT  85.68 64.979 91.656 65.315 ;
     RECT  139.44 64.405 141.144 65.315 ;
     RECT  21.648 64.981 25.512 65.317 ;
     RECT  157.392 64.885 157.608 65.317 ;
     RECT  21.648 65.317 25.656 65.363 ;
     RECT  157.344 65.317 157.608 65.411 ;
     RECT  15.936 64.933 16.008 65.413 ;
     RECT  17.376 65.123 17.4 65.413 ;
     RECT  15.936 65.413 17.4 65.459 ;
     RECT  65.808 65.173 69.336 65.461 ;
     RECT  70.416 64.357 73.368 65.461 ;
     RECT  83.28 64.355 83.832 65.461 ;
     RECT  145.008 64.741 146.232 65.461 ;
     RECT  65.808 65.461 73.368 65.507 ;
     RECT  9.936 64.933 10.536 65.509 ;
     RECT  18.6 61.331 18.912 65.509 ;
     RECT  19.968 64.981 20.568 65.509 ;
     RECT  65.808 65.507 68.664 65.509 ;
     RECT  92.688 64.979 96.6 65.509 ;
     RECT  142.176 63.779 143.112 65.509 ;
     RECT  162 65.269 162.984 65.509 ;
     RECT  98.016 64.933 98.232 65.555 ;
     RECT  150.24 64.499 150.456 65.557 ;
     RECT  6.816 64.837 8.52 65.603 ;
     RECT  120.288 64.355 122.328 65.603 ;
     RECT  32.832 65.029 37.656 65.651 ;
     RECT  164.16 64.885 165.192 65.651 ;
     RECT  74.688 64.837 78.408 65.795 ;
     RECT  21.648 65.363 24.648 65.843 ;
     RECT  152.112 64.981 155.928 65.843 ;
     RECT  149.76 65.557 150.456 65.939 ;
     RECT  147.648 64.645 148.68 66.037 ;
     RECT  149.76 65.939 149.784 66.037 ;
     RECT  61.056 64.021 64.584 66.085 ;
     RECT  65.664 65.509 68.664 66.085 ;
     RECT  75.936 65.795 78.408 66.085 ;
     RECT  79.488 64.837 82.104 66.085 ;
     RECT  102.24 60.755 102.408 66.085 ;
     RECT  103.728 64.549 106.296 66.085 ;
     RECT  107.472 65.171 108.552 66.085 ;
     RECT  136.08 63.781 137.928 66.085 ;
     RECT  139.44 65.315 139.464 66.085 ;
     RECT  151.056 66.037 151.08 66.085 ;
     RECT  152.112 65.843 155.64 66.085 ;
     RECT  112.176 64.933 119.112 66.131 ;
     RECT  120.288 65.603 122.28 66.133 ;
     RECT  9.696 65.509 10.536 66.179 ;
     RECT  50.88 62.821 57.288 66.179 ;
     RECT  123.36 64.835 123.72 66.179 ;
     RECT  98.208 65.555 98.232 66.181 ;
     RECT  164.256 65.651 165.192 66.181 ;
     RECT  166.368 64.357 168.36 66.181 ;
     RECT  34.176 65.651 37.656 66.227 ;
     RECT  98.208 66.181 98.376 66.227 ;
     RECT  164.256 66.181 168.36 66.227 ;
     RECT  9.696 66.179 10.44 66.323 ;
     RECT  34.704 66.227 37.656 66.323 ;
     RECT  41.568 64.307 42.504 66.325 ;
     RECT  135.84 66.085 139.464 66.325 ;
     RECT  140.544 65.315 141.144 66.325 ;
     RECT  7.152 65.603 8.52 66.371 ;
     RECT  18.6 65.509 20.568 66.371 ;
     RECT  28.512 64.837 30.072 66.373 ;
     RECT  135.84 66.325 141.144 66.373 ;
     RECT  69.744 65.507 73.368 66.419 ;
     RECT  12.528 64.595 13.896 66.469 ;
     RECT  49.584 65.267 49.608 66.469 ;
     RECT  50.88 66.179 51.312 66.469 ;
     RECT  75.936 66.085 82.104 66.469 ;
     RECT  83.184 65.461 84.168 66.469 ;
     RECT  130.752 63.781 130.92 66.469 ;
     RECT  132 65.171 133.944 66.469 ;
     RECT  135.84 66.373 141.192 66.469 ;
     RECT  142.176 65.509 143.256 66.469 ;
     RECT  157.344 65.411 157.512 66.469 ;
     RECT  12.144 66.469 13.896 66.515 ;
     RECT  34.704 66.323 36.696 66.515 ;
     RECT  75.936 66.469 84.168 66.515 ;
     RECT  41.568 66.325 42.648 66.611 ;
     RECT  50.832 66.469 51.312 66.611 ;
     RECT  52.512 66.179 57.288 66.613 ;
     RECT  85.968 65.315 91.656 66.661 ;
     RECT  92.688 65.509 96.744 66.661 ;
     RECT  5.328 64.885 5.352 66.755 ;
     RECT  7.152 66.371 8.112 66.755 ;
     RECT  21.648 65.843 24.552 66.755 ;
     RECT  28.512 66.373 30.408 66.755 ;
     RECT  52.512 66.613 58.104 66.755 ;
     RECT  112.176 66.131 114.312 66.755 ;
     RECT  167.088 66.227 168.36 66.755 ;
     RECT  74.688 65.795 74.952 66.757 ;
     RECT  75.936 66.515 81.576 66.757 ;
     RECT  157.344 66.469 157.608 66.757 ;
     RECT  52.512 66.755 54.216 66.803 ;
     RECT  112.176 66.755 113.976 66.803 ;
     RECT  162 65.509 163.032 66.803 ;
     RECT  59.472 60.803 59.496 66.901 ;
     RECT  124.704 64.835 127.176 66.901 ;
     RECT  128.64 64.883 129 66.901 ;
     RECT  130.752 66.469 133.944 66.901 ;
     RECT  157.248 66.757 157.608 66.901 ;
     RECT  158.688 65.027 160.536 66.901 ;
     RECT  70.416 66.419 73.368 67.093 ;
     RECT  74.688 66.757 81.576 67.093 ;
     RECT  167.376 66.755 167.88 67.139 ;
     RECT  123.696 66.179 123.72 67.141 ;
     RECT  124.704 66.901 129 67.141 ;
     RECT  135.84 66.469 143.256 67.187 ;
     RECT  15.936 65.459 16.584 67.189 ;
     RECT  18.6 66.371 18.912 67.189 ;
     RECT  34.704 66.515 35.64 67.237 ;
     RECT  85.968 66.661 96.744 67.237 ;
     RECT  98.352 66.227 98.376 67.237 ;
     RECT  107.28 66.085 108.552 67.237 ;
     RECT  109.584 65.171 111.192 67.237 ;
     RECT  147.648 66.037 149.784 67.237 ;
     RECT  52.512 66.803 54.12 67.283 ;
     RECT  151.056 66.085 155.64 67.283 ;
     RECT  157.248 66.901 160.536 67.283 ;
     RECT  34.224 67.237 35.64 67.331 ;
     RECT  49.056 66.469 49.608 67.331 ;
     RECT  61.056 66.085 68.664 67.331 ;
     RECT  115.344 66.131 119.112 67.331 ;
     RECT  167.472 67.139 167.88 67.331 ;
     RECT  120.192 66.133 122.28 67.333 ;
     RECT  123.696 67.141 129 67.333 ;
     RECT  15.936 67.189 16.824 67.427 ;
     RECT  19.968 66.371 20.568 67.427 ;
     RECT  9.696 66.323 10.008 67.429 ;
     RECT  38.64 63.587 40.512 67.429 ;
     RECT  85.872 67.237 96.744 67.475 ;
     RECT  141.168 67.187 143.256 67.475 ;
     RECT  107.28 67.237 111.192 67.477 ;
     RECT  112.176 66.803 113.544 67.477 ;
     RECT  130.704 66.901 133.944 67.477 ;
     RECT  99.36 63.779 100.632 67.525 ;
     RECT  31.584 62.435 31.608 67.571 ;
     RECT  144.672 65.461 146.232 67.571 ;
     RECT  34.224 67.331 35.112 67.573 ;
     RECT  33.984 67.573 35.112 67.763 ;
     RECT  7.44 66.755 8.112 67.765 ;
     RECT  37.872 67.429 40.512 67.765 ;
     RECT  41.568 66.611 42.504 67.765 ;
     RECT  70.416 67.093 81.576 67.765 ;
     RECT  82.608 66.515 84.168 67.765 ;
     RECT  97.728 67.237 98.376 67.765 ;
     RECT  99.36 67.525 101.016 67.765 ;
     RECT  135.84 67.187 139.944 67.765 ;
     RECT  120.192 67.333 129 67.811 ;
     RECT  13.2 66.515 13.896 67.813 ;
     RECT  9.456 67.429 10.008 67.859 ;
     RECT  52.704 67.283 54.12 67.859 ;
     RECT  107.28 67.477 113.544 67.859 ;
     RECT  147.552 67.237 149.784 67.859 ;
     RECT  164.256 66.227 165.912 67.859 ;
     RECT  65.664 67.331 68.664 67.907 ;
     RECT  13.2 67.813 14.376 67.955 ;
     RECT  70.416 67.765 84.168 67.955 ;
     RECT  59.472 66.901 59.832 67.957 ;
     RECT  72.24 67.955 84.168 68.003 ;
     RECT  21.648 66.755 21.672 68.005 ;
     RECT  21.648 68.005 21.864 68.051 ;
     RECT  29.28 66.755 30.408 68.053 ;
     RECT  85.92 67.475 96.744 68.099 ;
     RECT  125.76 67.811 129 68.291 ;
     RECT  36.672 66.515 36.696 68.341 ;
     RECT  37.872 67.765 42.504 68.341 ;
     RECT  75.504 68.003 84.168 68.341 ;
     RECT  109.968 67.859 113.544 68.341 ;
     RECT  135.696 67.765 139.944 68.341 ;
     RECT  141.168 67.475 141.192 68.341 ;
     RECT  4.32 66.085 4.344 68.387 ;
     RECT  36.672 68.341 42.504 68.387 ;
     RECT  59.472 67.957 60.024 68.387 ;
     RECT  130.704 67.477 134.616 68.387 ;
     RECT  23.376 66.755 24.552 68.435 ;
     RECT  120.192 67.811 124.728 68.435 ;
     RECT  151.056 67.283 154.824 68.435 ;
     RECT  55.248 66.755 58.104 68.483 ;
     RECT  109.968 68.341 114.36 68.483 ;
     RECT  102.24 66.085 106.296 68.579 ;
     RECT  29.232 68.053 30.408 68.581 ;
     RECT  102.24 68.579 103.752 68.627 ;
     RECT  38.64 68.387 42.504 68.629 ;
     RECT  43.872 63.205 43.896 68.629 ;
     RECT  70.416 67.955 71.256 68.629 ;
     RECT  19.968 67.427 19.992 68.675 ;
     RECT  69.696 68.629 71.256 68.675 ;
     RECT  17.856 67.189 18.912 68.773 ;
     RECT  19.92 68.725 19.944 68.773 ;
     RECT  28.656 68.581 30.408 68.773 ;
     RECT  115.344 67.331 119.016 68.773 ;
     RECT  130.704 68.387 134.088 68.773 ;
     RECT  28.656 68.773 30.84 68.819 ;
     RECT  60 68.387 60.024 68.821 ;
     RECT  61.248 67.331 64.584 68.821 ;
     RECT  45.024 65.125 47.352 68.867 ;
     RECT  162.096 66.803 163.032 68.867 ;
     RECT  52.704 67.859 53.544 68.915 ;
     RECT  107.28 67.859 108.792 68.915 ;
     RECT  130.32 68.773 134.088 68.915 ;
     RECT  30.816 68.819 30.84 68.917 ;
     RECT  32.832 65.651 32.856 68.917 ;
     RECT  65.664 67.907 65.928 68.917 ;
     RECT  108.48 68.915 108.792 68.917 ;
     RECT  6.864 67.765 8.112 68.963 ;
     RECT  17.856 68.773 19.944 68.963 ;
     RECT  157.248 67.283 159.864 68.963 ;
     RECT  67.056 67.907 68.664 68.965 ;
     RECT  69.696 68.675 69.72 68.965 ;
     RECT  156.24 67.765 156.264 69.011 ;
     RECT  144.912 67.571 146.232 69.013 ;
     RECT  130.32 68.915 133.944 69.059 ;
     RECT  30.816 68.917 32.856 69.061 ;
     RECT  72.24 68.003 74.472 69.061 ;
     RECT  75.504 68.341 84.408 69.061 ;
     RECT  85.92 68.099 96.6 69.107 ;
     RECT  108.48 68.917 108.888 69.109 ;
     RECT  25.632 65.363 25.656 69.155 ;
     RECT  72.24 69.061 84.408 69.155 ;
     RECT  110.304 68.483 114.36 69.155 ;
     RECT  60 68.821 64.584 69.157 ;
     RECT  65.664 68.917 66.024 69.157 ;
     RECT  60 69.157 66.024 69.203 ;
     RECT  30.816 69.061 33.048 69.251 ;
     RECT  67.056 68.965 69.72 69.251 ;
     RECT  108.48 69.109 108.936 69.251 ;
     RECT  144.912 69.013 146.376 69.251 ;
     RECT  32.112 69.251 33.048 69.299 ;
     RECT  50.88 66.611 51.312 69.301 ;
     RECT  52.704 68.915 53.304 69.301 ;
     RECT  67.056 69.251 68.664 69.301 ;
     RECT  71.232 68.675 71.256 69.301 ;
     RECT  72.24 69.155 79.56 69.301 ;
     RECT  135.696 68.341 141.192 69.301 ;
     RECT  135.168 69.301 141.192 69.347 ;
     RECT  136.512 69.347 141.192 69.349 ;
     RECT  142.272 67.475 143.256 69.349 ;
     RECT  159 68.963 159.864 69.349 ;
     RECT  80.88 69.155 84.408 69.443 ;
     RECT  120.192 68.435 124.584 69.443 ;
     RECT  164.304 67.859 165.912 69.491 ;
     RECT  61.248 69.203 66.024 69.493 ;
     RECT  67.008 69.301 68.664 69.493 ;
     RECT  50.88 69.301 53.304 69.539 ;
     RECT  97.728 67.765 101.016 69.539 ;
     RECT  104.88 68.579 106.296 69.539 ;
     RECT  125.76 68.291 128.76 69.539 ;
     RECT  21.84 68.051 21.864 69.587 ;
     RECT  24 68.435 24.552 69.587 ;
     RECT  32.112 69.299 32.856 69.587 ;
     RECT  55.296 68.483 58.104 69.587 ;
     RECT  130.32 69.059 130.728 69.587 ;
     RECT  157.248 68.963 157.944 69.587 ;
     RECT  159 69.349 160.728 69.587 ;
     RECT  147.552 67.859 149.064 69.635 ;
     RECT  147.888 69.635 149.064 69.637 ;
     RECT  17.856 68.963 18.912 69.683 ;
     RECT  71.232 69.301 79.56 69.683 ;
     RECT  157.248 69.587 157.272 69.683 ;
     RECT  9.456 67.859 9.48 69.685 ;
     RECT  122.928 69.443 124.584 69.685 ;
     RECT  12.144 66.515 12.168 69.731 ;
     RECT  36.672 68.387 37.56 69.731 ;
     RECT  144.912 69.251 146.328 69.733 ;
     RECT  9.456 69.685 9.576 69.779 ;
     RECT  9.552 69.779 9.576 69.827 ;
     RECT  167.472 67.331 167.496 69.827 ;
     RECT  71.232 69.683 74.472 69.925 ;
     RECT  37.056 69.731 37.56 69.971 ;
     RECT  70.704 69.925 74.472 69.971 ;
     RECT  144.528 69.733 146.328 69.973 ;
     RECT  13.2 67.955 13.896 70.019 ;
     RECT  28.656 68.819 29.712 70.019 ;
     RECT  122.928 69.685 124.776 70.019 ;
     RECT  136.512 69.349 143.256 70.019 ;
     RECT  164.4 69.491 165.912 70.019 ;
     RECT  30.816 69.251 30.84 70.067 ;
     RECT  159 69.587 160.44 70.067 ;
     RECT  123.84 70.019 124.776 70.069 ;
     RECT  125.76 69.539 128.712 70.069 ;
     RECT  108.48 69.251 108.888 70.117 ;
     RECT  16.8 67.427 16.824 70.163 ;
     RECT  19.92 68.963 19.944 70.163 ;
     RECT  82.08 69.443 84.408 70.163 ;
     RECT  102.24 68.627 103.272 70.163 ;
     RECT  80.88 69.443 80.904 70.211 ;
     RECT  147.888 69.637 149.496 70.211 ;
     RECT  82.512 70.163 84.408 70.259 ;
     RECT  163.008 68.867 163.032 70.259 ;
     RECT  13.2 70.019 13.512 70.261 ;
     RECT  61.248 69.493 68.664 70.261 ;
     RECT  5.232 70.261 5.256 70.357 ;
     RECT  110.4 69.155 114.36 70.357 ;
     RECT  115.344 68.773 119.16 70.357 ;
     RECT  5.136 70.357 5.256 70.403 ;
     RECT  110.4 70.357 119.16 70.405 ;
     RECT  120.192 69.443 121.752 70.405 ;
     RECT  131.904 69.059 133.944 70.405 ;
     RECT  135.168 69.347 135.192 70.405 ;
     RECT  151.824 68.435 154.824 70.405 ;
     RECT  87.696 69.107 96.6 70.451 ;
     RECT  151.632 70.405 154.824 70.451 ;
     RECT  9.744 70.357 9.768 70.453 ;
     RECT  5.136 70.403 5.16 70.499 ;
     RECT  13.104 70.261 13.512 70.499 ;
     RECT  136.512 70.019 143.208 70.499 ;
     RECT  164.4 70.019 165.192 70.499 ;
     RECT  34.224 67.763 35.112 70.547 ;
     RECT  85.92 69.107 86.136 70.547 ;
     RECT  48.576 68.869 48.6 70.549 ;
     RECT  49.584 67.331 49.608 70.549 ;
     RECT  60 69.203 60.024 70.597 ;
     RECT  61.008 70.261 68.664 70.597 ;
     RECT  9.744 70.453 9.864 70.643 ;
     RECT  48.576 70.549 49.608 70.691 ;
     RECT  108.384 70.117 108.888 70.691 ;
     RECT  32.832 69.587 32.856 70.739 ;
     RECT  51 69.539 53.304 70.739 ;
     RECT  152.88 70.451 154.728 70.739 ;
     RECT  71.808 69.971 74.472 70.741 ;
     RECT  75.504 69.683 79.56 70.741 ;
     RECT  71.808 70.741 79.56 70.787 ;
     RECT  49.584 70.691 49.608 70.837 ;
     RECT  51 70.739 52.008 70.837 ;
     RECT  49.584 70.837 52.008 70.883 ;
     RECT  159 70.067 159.864 70.931 ;
     RECT  151.632 70.451 151.848 71.027 ;
     RECT  24 69.587 24.312 71.029 ;
     RECT  0.144 60.325 0.168 71.123 ;
     RECT  24 71.029 25.128 71.125 ;
     RECT  56.304 69.587 58.104 71.221 ;
     RECT  82.512 70.259 84.072 71.221 ;
     RECT  24 71.125 25.224 71.267 ;
     RECT  50.016 70.883 52.008 71.267 ;
     RECT  56.304 71.221 58.68 71.315 ;
     RECT  76.32 70.787 79.56 71.315 ;
     RECT  97.728 69.539 100.92 71.315 ;
     RECT  136.56 70.499 143.208 71.315 ;
     RECT  156.192 69.301 156.216 71.315 ;
     RECT  131.904 70.405 135.192 71.365 ;
     RECT  108.48 70.691 108.888 71.603 ;
     RECT  123.84 70.069 128.712 71.605 ;
     RECT  130.32 69.587 130.344 71.605 ;
     RECT  77.472 71.315 79.56 71.651 ;
     RECT  38.64 68.629 43.896 71.747 ;
     RECT  102.432 70.163 103.272 71.797 ;
     RECT  71.808 70.787 75.288 71.843 ;
     RECT  107.28 68.915 107.304 71.843 ;
     RECT  123.84 71.605 130.344 71.939 ;
     RECT  37.536 69.971 37.56 72.179 ;
     RECT  71.808 71.843 73.8 72.229 ;
     RECT  110.4 70.405 121.752 72.323 ;
     RECT  102.048 71.797 103.704 72.325 ;
     RECT  104.88 69.539 105.96 72.325 ;
     RECT  144.384 69.973 146.328 72.325 ;
     RECT  80.88 71.221 80.904 72.373 ;
     RECT  82.512 71.221 85.032 72.373 ;
     RECT  56.4 71.315 58.68 72.419 ;
     RECT  148.08 70.211 149.496 72.419 ;
     RECT  151.632 71.027 151.656 72.419 ;
     RECT  87.696 70.451 96.168 72.467 ;
     RECT  123.84 71.939 130.008 72.467 ;
     RECT  153.6 70.739 154.728 72.467 ;
     RECT  48.576 70.691 48.6 72.563 ;
     RECT  87.744 72.467 96.168 72.563 ;
     RECT  125.328 72.467 130.008 72.563 ;
     RECT  131.904 71.365 135.432 72.611 ;
     RECT  112.08 72.323 121.752 72.659 ;
     RECT  136.896 71.315 143.208 72.707 ;
     RECT  139.056 72.707 143.208 72.805 ;
     RECT  136.896 72.707 137.976 72.851 ;
     RECT  102.048 72.325 105.96 72.899 ;
     RECT  70.704 69.971 70.728 72.947 ;
     RECT  97.728 71.315 100.68 72.949 ;
     RECT  45.312 68.867 47.352 72.995 ;
     RECT  69.696 69.251 69.72 72.995 ;
     RECT  71.712 72.229 73.8 72.995 ;
     RECT  77.472 71.651 78.408 72.995 ;
     RECT  80.88 72.373 85.032 72.995 ;
     RECT  102.048 72.899 103.272 72.995 ;
     RECT  112.08 72.659 121.608 72.995 ;
     RECT  134.112 72.611 135.432 72.995 ;
     RECT  144.336 72.325 146.328 72.995 ;
     RECT  50.016 71.267 51.624 73.043 ;
     RECT  104.352 72.899 105.96 73.043 ;
     RECT  126.6 72.563 130.008 73.043 ;
     RECT  112.656 72.995 114.36 73.091 ;
     RECT  123.84 72.467 123.96 73.093 ;
     RECT  60 70.597 68.664 73.139 ;
     RECT  123.696 73.093 123.96 73.139 ;
     RECT  126.6 73.043 129.384 73.235 ;
     RECT  57.744 72.419 57.768 73.283 ;
     RECT  87.744 72.563 89.208 73.283 ;
     RECT  134.112 72.995 135.192 73.379 ;
     RECT  144.576 72.995 146.328 73.379 ;
     RECT  131.904 72.611 133.128 73.429 ;
     RECT  76.32 71.315 76.344 73.523 ;
     RECT  38.64 71.747 40.728 73.571 ;
     RECT  45.36 72.995 47.352 73.571 ;
     RECT  53.28 70.739 53.304 73.571 ;
     RECT  55.296 69.587 55.32 73.571 ;
     RECT  80.88 72.995 81.72 73.571 ;
     RECT  86.112 70.547 86.136 73.571 ;
     RECT  108.48 71.603 108.792 73.571 ;
     RECT  134.4 73.379 135.192 73.571 ;
     RECT  39.648 73.571 40.728 73.811 ;
     RECT  125.328 72.563 125.352 73.811 ;
     RECT  81.696 73.571 81.72 74.051 ;
     RECT  67.008 73.139 68.664 74.053 ;
     RECT  112.752 73.091 114.36 74.053 ;
     RECT  75.264 71.843 75.288 74.147 ;
     RECT  102.048 72.995 102.936 74.147 ;
     RECT  134.4 73.571 134.424 74.147 ;
     RECT  51 73.043 51.624 74.195 ;
     RECT  115.344 72.995 121.608 74.483 ;
     RECT  83.4 72.995 85.032 74.579 ;
     RECT  104.88 73.043 105.96 74.579 ;
     RECT  108.672 73.571 108.696 74.579 ;
     RECT  126.6 73.235 127.56 74.579 ;
     RECT  78 72.995 78.408 74.723 ;
     RECT  85.008 74.579 85.032 74.723 ;
     RECT  97.488 72.949 100.68 74.723 ;
     RECT  102.048 74.147 102.072 74.723 ;
     RECT  105 74.579 105.96 74.723 ;
     RECT  131.328 73.429 133.128 74.723 ;
     RECT  153.6 72.467 154.44 74.723 ;
     RECT  72.336 72.995 73.512 74.819 ;
     RECT  120.336 74.483 121.608 74.819 ;
     RECT  131.328 74.723 132.312 74.819 ;
     RECT  38.64 73.571 38.664 74.867 ;
     RECT  79.536 71.651 79.56 74.963 ;
     RECT  128.688 73.235 128.712 75.107 ;
     RECT  123.696 73.139 123.864 75.155 ;
     RECT  87.744 73.283 89.112 75.299 ;
     RECT  98.16 74.723 100.68 75.299 ;
     RECT  123.696 75.155 123.72 75.299 ;
     RECT  98.16 75.299 98.376 75.875 ;
     RECT  139.056 72.805 143.256 75.875 ;
     RECT  139.488 75.875 143.256 76.115 ;
     RECT  41.712 71.747 43.656 76.309 ;
     RECT  60 73.139 66.024 76.933 ;
     RECT  67.008 74.053 68.76 76.933 ;
     RECT  98.352 75.875 98.376 76.933 ;
     RECT  41.712 76.309 43.944 76.979 ;
     RECT  98.16 76.933 98.376 76.979 ;
     RECT  90.24 72.563 96.168 77.267 ;
     RECT  121.2 74.819 121.608 77.603 ;
     RECT  90.288 77.267 96.168 77.989 ;
     RECT  40.2 73.811 40.728 78.037 ;
     RECT  41.712 76.979 43.8 78.037 ;
     RECT  45.36 73.571 46.536 78.037 ;
     RECT  140.88 76.115 143.256 78.037 ;
     RECT  144.576 73.379 145.8 78.037 ;
     RECT  140.88 78.037 145.8 78.659 ;
     RECT  88.128 75.299 89.112 79.283 ;
     RECT  90.288 77.989 96.792 79.283 ;
     RECT  90.288 79.283 96.744 79.667 ;
     RECT  141.024 78.659 145.8 79.859 ;
     RECT  40.2 78.037 43.8 80.773 ;
     RECT  45.312 78.037 46.536 80.773 ;
     RECT  93.408 79.667 96.744 80.963 ;
     RECT  40.2 80.773 46.536 81.059 ;
     RECT  72.6 74.819 73.512 81.203 ;
     RECT  98.16 76.979 98.184 81.539 ;
     RECT  90.288 79.667 92.376 81.829 ;
     RECT  93.408 80.963 96.696 81.829 ;
     RECT  115.344 74.483 119.016 81.875 ;
     RECT  60 76.933 68.76 82.405 ;
     RECT  60 82.405 69.384 82.691 ;
     RECT  90.288 81.829 96.696 82.691 ;
     RECT  60.144 82.691 68.808 82.931 ;
     RECT  93.408 82.691 96.696 83.267 ;
     RECT  90.288 82.691 92.376 83.749 ;
     RECT  93.408 83.267 95.64 83.749 ;
     RECT  141.024 79.859 145.608 83.843 ;
     RECT  141.024 83.843 143.352 84.179 ;
     RECT  141.024 84.179 143.304 86.053 ;
     RECT  60.144 82.931 68.76 88.019 ;
     RECT  40.2 81.059 43.656 93.539 ;
     RECT  60.144 88.019 68.712 93.779 ;
     RECT  141.024 86.053 143.448 93.875 ;
     RECT  112.608 74.053 114.36 95.125 ;
     RECT  115.392 81.875 119.016 95.125 ;
     RECT  141.024 93.875 143.208 95.125 ;
     RECT  60.144 93.779 63.24 95.173 ;
     RECT  64.368 93.779 68.712 95.173 ;
     RECT  112.608 95.125 119.016 95.219 ;
     RECT  144.48 83.843 145.608 95.605 ;
     RECT  90.288 83.749 95.64 95.651 ;
     RECT  40.2 93.539 43.608 95.699 ;
     RECT  60.144 95.173 68.712 96.037 ;
     RECT  140.832 95.125 143.208 96.277 ;
     RECT  144.24 95.605 145.608 96.277 ;
     RECT  90.288 95.651 92.616 96.419 ;
     RECT  44.736 81.059 46.536 96.515 ;
     RECT  140.832 96.277 145.608 96.707 ;
     RECT  93.696 95.651 95.64 96.755 ;
     RECT  93.696 96.755 95.304 96.947 ;
     RECT  60.096 96.037 68.712 96.949 ;
     RECT  112.608 95.219 113.64 96.995 ;
     RECT  40.2 95.699 43.368 97.523 ;
     RECT  114.624 95.219 119.016 97.523 ;
     RECT  140.832 96.707 144.36 97.523 ;
     RECT  112.608 96.995 113.112 97.811 ;
     RECT  90.288 96.419 91.8 97.861 ;
     RECT  93.744 96.947 95.304 97.909 ;
     RECT  41.568 97.523 41.736 98.099 ;
     RECT  90.288 97.861 92.04 98.099 ;
     RECT  114.624 97.523 118.872 98.099 ;
     RECT  139.488 76.115 139.704 98.099 ;
     RECT  93.744 97.909 95.448 98.197 ;
     RECT  43.728 98.053 43.752 98.293 ;
     RECT  44.736 96.515 46.008 98.293 ;
     RECT  59.904 96.949 68.712 98.339 ;
     RECT  59.904 98.339 68.04 98.483 ;
     RECT  41.712 98.099 41.736 98.675 ;
     RECT  91.248 98.099 92.04 98.675 ;
     RECT  112.608 97.811 112.632 98.675 ;
     RECT  139.488 98.099 139.512 98.675 ;
     RECT  141.6 97.523 144.36 98.675 ;
     RECT  145.584 96.707 145.608 98.675 ;
     RECT  59.904 98.483 59.928 98.771 ;
     RECT  91.536 98.675 92.04 98.819 ;
     RECT  91.632 98.819 92.04 99.011 ;
     RECT  117.456 98.099 118.872 99.155 ;
     RECT  43.728 98.293 46.008 99.157 ;
     RECT  114.624 98.099 116.232 99.301 ;
     RECT  92.016 99.011 92.04 99.397 ;
     RECT  93.024 98.197 95.448 99.397 ;
     RECT  114.624 99.301 116.28 99.589 ;
     RECT  43.584 99.157 46.008 99.733 ;
     RECT  42.912 99.733 46.008 99.779 ;
     RECT  60.912 98.483 68.04 99.779 ;
     RECT  92.016 99.397 95.448 99.779 ;
     RECT  118.368 99.155 118.872 99.779 ;
     RECT  137.4 72.851 137.976 99.779 ;
     RECT  141.6 98.675 144.024 99.779 ;
     RECT  60.912 99.779 67.512 99.827 ;
     RECT  60.912 99.827 63.48 99.875 ;
     RECT  114.432 99.589 116.28 99.923 ;
     RECT  42.912 99.779 43.992 99.925 ;
     RECT  141.6 99.779 143.544 100.067 ;
     RECT  45.6 99.779 46.008 100.355 ;
     RECT  118.848 99.779 118.872 100.355 ;
     RECT  96.672 83.267 96.696 100.499 ;
     RECT  42.72 99.925 43.992 100.885 ;
     RECT  115.008 99.923 116.28 100.885 ;
     RECT  61.008 99.875 63.48 100.931 ;
     RECT  42.672 100.885 44.136 100.981 ;
     RECT  61.104 100.931 63.48 101.027 ;
     RECT  115.008 100.885 116.376 101.413 ;
     RECT  141.936 100.067 143.544 101.413 ;
     RECT  2.4 58.739 2.712 101.529 ;
     RECT  7.8 68.963 8.112 101.529 ;
     RECT  13.2 70.499 13.512 101.529 ;
     RECT  18.6 69.683 18.912 101.529 ;
     RECT  24 71.267 24.312 101.529 ;
     RECT  29.4 70.019 29.712 101.529 ;
     RECT  34.8 70.547 35.112 101.529 ;
     RECT  40.2 97.523 40.512 101.529 ;
     RECT  45.6 100.355 45.912 101.529 ;
     RECT  51 74.195 51.312 101.529 ;
     RECT  56.4 72.419 56.712 101.529 ;
     RECT  64.848 99.827 67.512 101.529 ;
     RECT  72.6 81.203 72.912 101.529 ;
     RECT  78 74.723 78.312 101.529 ;
     RECT  83.4 74.579 83.712 101.529 ;
     RECT  88.8 79.283 89.112 101.529 ;
     RECT  92.016 99.779 94.512 101.529 ;
     RECT  99.6 75.299 99.912 101.529 ;
     RECT  105 74.723 105.312 101.529 ;
     RECT  110.4 72.323 110.712 101.529 ;
     RECT  121.2 77.603 121.512 101.529 ;
     RECT  126.6 74.579 126.912 101.529 ;
     RECT  132 74.819 132.312 101.529 ;
     RECT  137.4 99.779 137.712 101.529 ;
     RECT  148.2 72.419 148.512 101.529 ;
     RECT  153.6 74.723 153.912 101.529 ;
     RECT  159 70.931 159.312 101.529 ;
     RECT  164.4 70.499 164.712 101.529 ;
     RECT  169.8 2.151 170.112 101.529 ;
     RECT  2.4 101.529 2.52 101.543 ;
     RECT  7.8 101.529 7.92 101.543 ;
     RECT  13.2 101.529 13.32 101.543 ;
     RECT  18.6 101.529 18.72 101.543 ;
     RECT  24 101.529 24.12 101.543 ;
     RECT  29.4 101.529 29.52 101.543 ;
     RECT  34.8 101.529 34.92 101.543 ;
     RECT  40.2 101.529 40.32 101.543 ;
     RECT  45.6 101.529 45.72 101.543 ;
     RECT  51 101.529 51.12 101.543 ;
     RECT  56.4 101.529 56.52 101.543 ;
     RECT  64.848 101.529 67.32 101.543 ;
     RECT  72.6 101.529 72.72 101.543 ;
     RECT  78 101.529 78.12 101.543 ;
     RECT  83.4 101.529 83.52 101.543 ;
     RECT  88.8 101.529 88.92 101.543 ;
     RECT  92.016 101.529 94.32 101.543 ;
     RECT  99.6 101.529 99.72 101.543 ;
     RECT  105 101.529 105.12 101.543 ;
     RECT  110.4 101.529 110.52 101.543 ;
     RECT  121.2 101.529 121.32 101.543 ;
     RECT  126.6 101.529 126.72 101.543 ;
     RECT  132 101.529 132.12 101.543 ;
     RECT  137.4 101.529 137.52 101.543 ;
     RECT  148.2 101.529 148.32 101.543 ;
     RECT  153.6 101.529 153.72 101.543 ;
     RECT  159 101.529 159.12 101.543 ;
     RECT  164.4 101.529 164.52 101.543 ;
     RECT  169.8 101.529 169.92 101.543 ;
     RECT  61.68 101.027 63.48 101.699 ;
     RECT  114.912 101.413 116.376 102.037 ;
     RECT  141.792 101.413 143.544 102.565 ;
     RECT  64.848 101.543 66.504 103.331 ;
     RECT  141.744 102.565 143.544 103.331 ;
     RECT  141.744 103.331 143.4 103.427 ;
     RECT  61.872 101.699 63.48 103.475 ;
     RECT  64.848 103.331 66.456 103.523 ;
     RECT  92.016 101.543 93.72 103.523 ;
     RECT  42.672 100.981 44.184 103.632 ;
     RECT  61.872 103.475 63.384 103.632 ;
     RECT  64.944 103.523 66.456 103.632 ;
     RECT  92.208 103.523 93.72 103.632 ;
     RECT  114.864 102.037 116.376 103.632 ;
     RECT  141.744 103.427 143.256 103.632 ;
     RECT  79.752 1.859 80.784 1.907 ;
     RECT  79.752 1.907 81.024 2.195 ;
     RECT  82.104 2.137 83.4 3.539 ;
     RECT  79.608 2.195 81.024 2.243 ;
     RECT  79.512 2.243 81.024 2.291 ;
     RECT  78.312 3.443 79.128 3.925 ;
     RECT  82.008 3.539 83.4 7.475 ;
     RECT  78.312 3.925 79.776 35.029 ;
     RECT  89.112 6.419 90.288 6.803 ;
     RECT  81.912 7.475 83.4 31.955 ;
     RECT  93 13.379 94.2 23.893 ;
     RECT  93.192 23.893 94.2 24.181 ;
     RECT  93 31.715 94.2 37.573 ;
     RECT  67.512 32.437 68.64 34.547 ;
     RECT  68.664 32.483 69.384 33.589 ;
     RECT  62.424 32.869 63.888 33.013 ;
     RECT  72.912 32.965 74.208 33.013 ;
     RECT  74.232 32.965 75.456 33.443 ;
     RECT  60.168 33.013 61.392 35.701 ;
     RECT  62.616 33.013 63.888 36.421 ;
     RECT  72.912 33.013 73.92 33.637 ;
     RECT  74.232 33.443 75.48 33.637 ;
     RECT  51.864 33.589 52.896 35.315 ;
     RECT  52.92 33.589 54.144 34.165 ;
     RECT  69.48 33.589 70.8 36.469 ;
     RECT  74.232 33.637 75.504 34.741 ;
     RECT  48.6 33.925 50.064 34.115 ;
     RECT  46.008 34.117 47.328 34.741 ;
     RECT  79.8 34.357 80.88 35.891 ;
     RECT  43.272 34.501 44.4 36.997 ;
     RECT  44.424 34.501 45.6 35.317 ;
     RECT  72.912 34.643 73.92 37.573 ;
     RECT  54.696 34.741 55.872 36.515 ;
     RECT  74.52 34.741 75.504 36.949 ;
     RECT  76.056 34.741 77.472 35.845 ;
     RECT  81.144 34.741 82.512 35.699 ;
     RECT  103.848 34.741 105 36.949 ;
     RECT  109.368 34.741 110.4 35.317 ;
     RECT  78.312 35.029 79.488 41.221 ;
     RECT  100.872 35.077 102.384 35.219 ;
     RECT  102.408 35.077 103.824 36.949 ;
     RECT  105.312 35.077 106.32 37.573 ;
     RECT  100.632 35.219 102.384 36.373 ;
     RECT  51.864 35.315 52.992 37.717 ;
     RECT  44.424 35.317 45.504 37.477 ;
     RECT  58.776 35.605 59.76 36.997 ;
     RECT  83.712 35.605 85.008 39.541 ;
     RECT  85.032 35.605 86.256 39.301 ;
     RECT  96.168 35.605 97.152 39.109 ;
     RECT  111.48 35.605 112.896 38.485 ;
     RECT  79.8 35.891 81.12 36.275 ;
     RECT  47.688 36.277 49.056 36.757 ;
     RECT  87.144 36.421 88.368 38.149 ;
     RECT  94.512 36.421 95.664 37.141 ;
     RECT  57.384 36.469 58.752 39.299 ;
     RECT  69.528 36.469 70.8 36.661 ;
     RECT  54.408 36.515 55.872 37.091 ;
     RECT  40.512 36.661 41.856 37.573 ;
     RECT  41.88 36.661 43.248 38.197 ;
     RECT  47.784 36.757 49.056 37.043 ;
     RECT  103.848 36.949 104.88 37.429 ;
     RECT  39.192 36.997 40.2 38.149 ;
     RECT  46.296 37.043 47.328 37.091 ;
     RECT  49.392 37.043 49.632 38.005 ;
     RECT  46.296 37.091 47.424 38.149 ;
     RECT  94.632 37.141 95.664 37.237 ;
     RECT  94.68 37.237 95.664 37.667 ;
     RECT  103.08 37.475 104.256 42.901 ;
     RECT  40.512 37.573 41.616 38.677 ;
     RECT  93 37.573 94.08 37.621 ;
     RECT  93 37.621 93.984 39.637 ;
     RECT  94.632 37.667 95.664 37.907 ;
     RECT  97.176 37.861 98.208 38.147 ;
     RECT  98.232 37.861 99.216 38.147 ;
     RECT  94.512 37.907 95.664 38.579 ;
     RECT  97.176 38.147 99.216 38.725 ;
     RECT  30.264 38.149 31.584 38.725 ;
     RECT  35.208 38.149 36.528 38.725 ;
     RECT  46.44 38.149 47.424 39.109 ;
     RECT  79.656 38.149 81.12 39.301 ;
     RECT  41.88 38.197 43.152 41.317 ;
     RECT  49.416 38.243 50.544 39.301 ;
     RECT  36.552 38.245 37.728 39.301 ;
     RECT  111.48 38.485 112.8 39.107 ;
     RECT  116.28 38.533 117.648 40.933 ;
     RECT  54.84 38.629 56.064 41.077 ;
     RECT  40.512 38.677 41.52 41.797 ;
     RECT  97.8 38.725 99.216 39.733 ;
     RECT  114.024 38.725 115.056 40.405 ;
     RECT  81.912 38.819 82.896 39.251 ;
     RECT  118.44 39.061 119.52 39.301 ;
     RECT  111.48 39.107 113.136 39.829 ;
     RECT  81.672 39.251 82.896 40.355 ;
     RECT  57.384 39.299 58.896 41.795 ;
     RECT  79.848 39.301 81.12 39.349 ;
     RECT  89.448 39.301 90.72 40.357 ;
     RECT  122.232 39.301 123.408 39.877 ;
     RECT  79.848 39.349 80.928 39.539 ;
     RECT  119.544 39.397 121.056 39.541 ;
     RECT  69.48 39.443 70.8 39.779 ;
     RECT  79.848 39.539 81.024 40.499 ;
     RECT  119.736 39.541 121.056 39.589 ;
     RECT  119.736 39.589 120.96 39.683 ;
     RECT  119.544 39.683 120.96 39.875 ;
     RECT  85.512 39.731 86.688 41.029 ;
     RECT  98.088 39.733 99.216 40.165 ;
     RECT  62.952 39.779 64.176 42.755 ;
     RECT  69.432 39.779 70.944 41.557 ;
     RECT  112.056 39.829 113.136 41.075 ;
     RECT  120.864 39.875 120.96 40.405 ;
     RECT  31.944 39.877 33.12 42.565 ;
     RECT  81.624 40.355 82.896 41.123 ;
     RECT  26.376 40.405 27.552 41.891 ;
     RECT  67.8 40.405 69.216 40.981 ;
     RECT  132.408 40.405 133.776 40.981 ;
     RECT  128.448 40.451 129.072 40.981 ;
     RECT  79.656 40.499 81.024 41.843 ;
     RECT  123.384 40.595 123.432 41.893 ;
     RECT  113.352 40.835 114.48 43.141 ;
     RECT  12.072 40.981 13.2 41.701 ;
     RECT  107.16 40.981 108.576 44.437 ;
     RECT  127.704 40.981 129.072 41.797 ;
     RECT  135.672 40.981 136.896 41.173 ;
     RECT  137.712 40.981 139.008 42.709 ;
     RECT  85.656 41.029 86.688 42.133 ;
     RECT  24.312 41.075 25.44 42.709 ;
     RECT  60.072 41.075 61.056 43.523 ;
     RECT  89.448 41.075 90.72 42.037 ;
     RECT  112.056 41.075 113.328 44.053 ;
     RECT  81.624 41.123 83.088 42.085 ;
     RECT  78.456 41.221 79.488 41.797 ;
     RECT  134.664 41.221 135.648 41.941 ;
     RECT  54.84 41.267 55.968 42.179 ;
     RECT  18.912 41.509 20.208 41.557 ;
     RECT  36.552 41.555 37.728 42.613 ;
     RECT  41.88 41.555 43.008 45.829 ;
     RECT  69.96 41.557 70.944 42.133 ;
     RECT  122.232 41.651 123.36 43.285 ;
     RECT  47.784 41.653 49.008 41.987 ;
     RECT  12.072 41.701 13.104 42.133 ;
     RECT  57.192 41.795 58.896 42.613 ;
     RECT  78.456 41.797 79.44 41.989 ;
     RECT  127.704 41.797 128.976 45.253 ;
     RECT  79.512 41.843 81.024 43.525 ;
     RECT  8.112 41.845 9.12 41.987 ;
     RECT  109.032 41.939 110.016 43.237 ;
     RECT  8.112 41.987 9.144 42.085 ;
     RECT  135.144 41.987 136.224 42.275 ;
     RECT  8.112 42.085 9.504 42.469 ;
     RECT  21.192 42.085 22.176 42.949 ;
     RECT  22.2 42.085 23.616 42.995 ;
     RECT  81.624 42.085 82.704 43.765 ;
     RECT  44.472 42.131 45.504 43.331 ;
     RECT  139.704 42.133 140.688 44.339 ;
     RECT  54.696 42.179 55.968 44.341 ;
     RECT  70.248 42.179 71.712 45.829 ;
     RECT  131.76 42.227 131.808 42.229 ;
     RECT  129.096 42.229 130.56 43.381 ;
     RECT  130.584 42.229 131.808 42.805 ;
     RECT  135.144 42.275 136.368 46.499 ;
     RECT  8.328 42.469 9.504 42.611 ;
     RECT  8.232 42.611 9.504 44.965 ;
     RECT  6.36 42.613 7.8 45.589 ;
     RECT  36.744 42.613 37.728 43.619 ;
     RECT  57.192 42.613 58.656 43.381 ;
     RECT  13.608 42.709 14.784 43.861 ;
     RECT  24.408 42.709 25.44 43.429 ;
     RECT  94.512 42.709 95.52 42.757 ;
     RECT  137.976 42.709 139.008 44.005 ;
     RECT  62.664 42.755 64.176 44.197 ;
     RECT  130.824 42.805 131.808 48.421 ;
     RECT  19.032 42.995 20.112 45.059 ;
     RECT  23.568 42.995 23.616 43.477 ;
     RECT  113.352 43.141 114.432 44.099 ;
     RECT  122.232 43.285 123.264 44.533 ;
     RECT  44.424 43.331 45.504 45.109 ;
     RECT  123.672 43.331 123.816 43.379 ;
     RECT  132.648 43.331 133.632 45.059 ;
     RECT  123.576 43.379 123.816 43.669 ;
     RECT  57.432 43.381 58.656 44.389 ;
     RECT  129.432 43.381 130.56 44.629 ;
     RECT  47.688 43.523 47.784 44.869 ;
     RECT  59.976 43.523 61.056 43.861 ;
     RECT  79.656 43.525 81.024 43.811 ;
     RECT  36.744 43.619 37.872 43.861 ;
     RECT  123.576 43.669 124.848 46.597 ;
     RECT  101.016 43.811 102 46.357 ;
     RECT  15.528 43.861 16.56 45.685 ;
     RECT  36.792 43.861 37.872 44.581 ;
     RECT  59.976 43.861 61.008 44.677 ;
     RECT  112.92 44.099 114.432 46.165 ;
     RECT  62.664 44.197 63.84 44.437 ;
     RECT  16.584 44.339 17.568 45.829 ;
     RECT  139.704 44.339 140.736 47.749 ;
     RECT  107.16 44.437 108.336 46.357 ;
     RECT  24.552 44.531 25.536 46.069 ;
     RECT  36.888 44.581 37.872 45.877 ;
     RECT  129.48 44.629 130.56 46.117 ;
     RECT  60.024 44.677 61.008 44.867 ;
     RECT  96.744 44.819 97.776 45.925 ;
     RECT  59.976 44.867 61.008 45.923 ;
     RECT  2.712 44.965 3.696 47.173 ;
     RECT  47.88 44.965 49.056 45.541 ;
     RECT  119.832 44.965 120.912 47.027 ;
     RECT  19.032 45.059 20.448 46.069 ;
     RECT  132.456 45.059 133.632 46.069 ;
     RECT  76.344 45.155 77.472 45.635 ;
     RECT  21.912 45.157 22.944 47.219 ;
     RECT  3.72 45.301 4.992 46.885 ;
     RECT  127.704 45.491 129.072 47.315 ;
     RECT  10.248 45.541 11.712 45.877 ;
     RECT  13.992 45.541 15.504 47.845 ;
     RECT  6.408 45.589 7.8 47.269 ;
     RECT  70.584 45.829 71.712 46.741 ;
     RECT  147.048 45.877 148.2 48.373 ;
     RECT  9.96 45.923 11.184 49.381 ;
     RECT  20.472 45.923 21.888 47.173 ;
     RECT  59.976 45.923 61.056 46.067 ;
     RECT  36.888 46.019 37.872 46.787 ;
     RECT  59.352 46.067 61.056 46.211 ;
     RECT  19.032 46.069 20.112 46.693 ;
     RECT  25.944 46.117 27.456 46.933 ;
     RECT  145.752 46.163 146.736 47.317 ;
     RECT  112.92 46.165 114.336 47.939 ;
     RECT  59.352 46.211 61.248 47.173 ;
     RECT  62.664 46.211 63.84 46.403 ;
     RECT  62.664 46.403 64.128 48.085 ;
     RECT  144.552 46.453 145.632 48.325 ;
     RECT  135.144 46.499 136.608 47.845 ;
     RECT  143.112 46.499 144.528 47.893 ;
     RECT  123.672 46.597 124.848 47.507 ;
     RECT  36.744 46.787 37.872 48.661 ;
     RECT  67.848 46.787 69.216 47.845 ;
     RECT  70.296 46.787 71.472 48.085 ;
     RECT  3.72 46.885 4.896 52.405 ;
     RECT  16.824 46.931 16.92 47.749 ;
     RECT  25.944 46.933 27.168 47.029 ;
     RECT  57.672 47.027 58.752 48.805 ;
     RECT  119.832 47.027 121.056 47.173 ;
     RECT  20.472 47.173 21.744 47.269 ;
     RECT  59.352 47.173 61.056 47.509 ;
     RECT  120.072 47.173 121.056 47.651 ;
     RECT  21.768 47.219 22.944 48.949 ;
     RECT  79.848 47.221 81.216 47.269 ;
     RECT  148.632 47.221 150.048 47.269 ;
     RECT  20.52 47.269 21.744 47.557 ;
     RECT  148.824 47.269 150.048 48.901 ;
     RECT  19.464 47.315 20.448 49.909 ;
     RECT  127.656 47.315 129.072 49.477 ;
     RECT  123.432 47.507 124.848 49.429 ;
     RECT  59.544 47.509 61.056 48.421 ;
     RECT  120.072 47.651 121.2 49.189 ;
     RECT  16.824 47.749 18.336 47.893 ;
     RECT  14.088 47.845 15.504 48.421 ;
     RECT  67.848 47.845 69.168 48.421 ;
     RECT  98.616 47.891 99.6 50.771 ;
     RECT  16.824 47.893 18.048 48.133 ;
     RECT  49.272 47.939 50.256 51.829 ;
     RECT  103.704 47.939 104.688 48.899 ;
     RECT  107.016 47.939 108.048 47.987 ;
     RECT  112.056 47.939 114.336 48.949 ;
     RECT  106.536 47.987 108.048 48.949 ;
     RECT  62.664 48.085 63.984 48.227 ;
     RECT  62.664 48.227 64.08 48.659 ;
     RECT  143.688 48.371 144.672 49.333 ;
     RECT  146.856 48.419 147.888 49.525 ;
     RECT  59.544 48.421 60.528 48.901 ;
     RECT  68.088 48.421 69.168 48.901 ;
     RECT  41.88 48.515 43.008 49.477 ;
     RECT  48.216 48.611 49.248 49.957 ;
     RECT  57.72 48.805 58.752 49.333 ;
     RECT  103.608 48.899 104.688 50.533 ;
     RECT  148.968 48.901 150.048 52.117 ;
     RECT  36.024 48.947 37.056 49.043 ;
     RECT  21.96 48.949 22.944 51.923 ;
     RECT  112.488 48.949 114.336 49.141 ;
     RECT  117.816 48.995 118.992 51.589 ;
     RECT  36.024 49.043 37.392 50.773 ;
     RECT  68.088 49.043 69.168 49.091 ;
     RECT  67.896 49.091 69.168 50.389 ;
     RECT  139.464 49.091 140.448 50.101 ;
     RECT  113.112 49.141 114.336 52.499 ;
     RECT  120.072 49.189 121.056 51.349 ;
     RECT  143.112 49.379 144.144 53.029 ;
     RECT  123.432 49.429 124.416 51.829 ;
     RECT  41.928 49.477 43.008 49.669 ;
     RECT  127.656 49.477 128.832 49.619 ;
     RECT  9.96 49.523 11.088 51.109 ;
     RECT  124.968 49.523 126.096 49.859 ;
     RECT  127.608 49.619 128.832 50.195 ;
     RECT  109.272 49.811 110.256 52.741 ;
     RECT  124.44 49.859 124.488 50.965 ;
     RECT  20.472 49.955 21.744 51.781 ;
     RECT  96.84 50.003 97.872 51.059 ;
     RECT  16.008 50.195 17.136 51.347 ;
     RECT  57.672 50.195 58.656 53.603 ;
     RECT  127.56 50.195 128.832 50.435 ;
     RECT  79.416 50.339 80.496 54.709 ;
     RECT  67.896 50.389 69.072 51.683 ;
     RECT  127.512 50.435 128.832 51.349 ;
     RECT  144.312 50.435 145.632 53.029 ;
     RECT  103.704 50.533 104.688 51.445 ;
     RECT  94.92 50.771 96.24 52.307 ;
     RECT  98.328 50.771 99.6 51.061 ;
     RECT  2.712 50.963 3.696 52.021 ;
     RECT  36.024 50.963 37.248 52.981 ;
     RECT  139.704 51.011 140.832 53.941 ;
     RECT  96.84 51.059 98.064 51.107 ;
     RECT  98.328 51.061 99.504 55.813 ;
     RECT  96.84 51.107 98.304 53.365 ;
     RECT  16.008 51.347 17.232 52.933 ;
     RECT  127.512 51.349 128.544 51.587 ;
     RECT  124.584 51.445 126.096 51.587 ;
     RECT  127.512 51.587 128.88 51.877 ;
     RECT  26.952 51.635 28.032 54.085 ;
     RECT  120.072 51.635 121.056 53.653 ;
     RECT  67.704 51.683 69.072 52.499 ;
     RECT  103.704 51.683 104.688 53.075 ;
     RECT  20.52 51.781 21.744 51.829 ;
     RECT  62.616 51.781 64.08 52.693 ;
     RECT  52.296 51.875 53.28 53.557 ;
     RECT  127.56 51.877 128.88 55.237 ;
     RECT  21.96 51.923 23.328 54.565 ;
     RECT  25.56 51.923 26.928 54.179 ;
     RECT  134.712 51.923 135.888 54.613 ;
     RECT  32.76 51.971 33.84 55.717 ;
     RECT  86.472 52.019 87.456 55.381 ;
     RECT  13.656 52.163 14.784 55.237 ;
     RECT  94.872 52.307 96.24 54.853 ;
     RECT  138.312 52.307 139.488 53.603 ;
     RECT  3.72 52.405 4.848 54.613 ;
     RECT  162.984 52.405 164.4 54.371 ;
     RECT  161.784 52.453 162.96 53.509 ;
     RECT  67.656 52.499 69.072 54.179 ;
     RECT  113.112 52.499 114.528 55.427 ;
     RECT  62.664 52.693 64.08 56.389 ;
     RECT  10.008 52.739 11.184 54.037 ;
     RECT  41.112 52.739 42.48 54.179 ;
     RECT  151.752 52.789 153.024 52.931 ;
     RECT  154.2 52.885 155.376 53.459 ;
     RECT  155.4 52.885 156.576 53.413 ;
     RECT  64.44 52.931 65.472 54.997 ;
     RECT  156.6 52.931 156.696 53.941 ;
     RECT  16.008 52.933 17.136 55.141 ;
     RECT  36.024 52.981 37.056 53.029 ;
     RECT  81.24 53.075 82.224 56.483 ;
     RECT  103.704 53.075 104.832 55.955 ;
     RECT  148.872 53.075 150.048 54.085 ;
     RECT  100.728 53.267 101.952 54.035 ;
     RECT  160.152 53.269 161.616 57.541 ;
     RECT  143.112 53.363 144.288 53.699 ;
     RECT  96.888 53.365 98.304 53.461 ;
     RECT  144.312 53.411 145.632 53.699 ;
     RECT  154.2 53.459 155.616 56.293 ;
     RECT  96.984 53.461 98.304 54.371 ;
     RECT  45.912 53.603 47.328 55.331 ;
     RECT  74.088 53.603 75.6 56.485 ;
     RECT  138.312 53.603 139.632 54.659 ;
     RECT  143.112 53.699 144.024 54.469 ;
     RECT  117.816 53.891 118.896 55.621 ;
     RECT  100.728 54.035 102.24 54.563 ;
     RECT  10.056 54.037 11.184 54.085 ;
     RECT  26.952 54.085 27.936 54.179 ;
     RECT  148.872 54.085 149.952 55.331 ;
     RECT  25.56 54.179 27.936 54.517 ;
     RECT  40.512 54.179 42.48 55.333 ;
     RECT  67.656 54.179 69.408 55.477 ;
     RECT  158.448 54.179 159 54.661 ;
     RECT  153.12 54.227 153.36 55.141 ;
     RECT  48.216 54.275 49.248 56.483 ;
     RECT  96.84 54.371 98.304 55.285 ;
     RECT  164.304 54.371 164.4 54.709 ;
     RECT  25.56 54.517 26.88 55.573 ;
     RECT  26.904 54.517 27.936 54.755 ;
     RECT  105.864 54.563 107.136 55.955 ;
     RECT  22.056 54.565 23.328 56.101 ;
     RECT  134.712 54.613 135.84 54.755 ;
     RECT  157.512 54.661 159 55.237 ;
     RECT  164.712 54.661 166.08 55.525 ;
     RECT  43.368 54.707 44.544 56.483 ;
     RECT  3.96 54.755 5.328 55.813 ;
     RECT  26.904 54.755 28.32 55.619 ;
     RECT  134.712 54.755 135.888 57.445 ;
     RECT  69.912 54.899 70.992 55.331 ;
     RECT  151.176 55.141 152.16 56.195 ;
     RECT  152.184 55.141 153.36 55.189 ;
     RECT  107.976 55.235 109.2 56.437 ;
     RECT  13.704 55.237 14.784 56.101 ;
     RECT  125.16 55.237 126.432 55.715 ;
     RECT  127.656 55.237 128.88 55.381 ;
     RECT  96.84 55.285 97.872 57.059 ;
     RECT  10.632 55.331 11.856 57.061 ;
     RECT  75.624 55.331 76.656 56.485 ;
     RECT  148.872 55.331 150.192 56.389 ;
     RECT  40.512 55.333 41.904 55.381 ;
     RECT  40.632 55.381 41.904 55.429 ;
     RECT  127.656 55.381 128.64 55.523 ;
     RECT  146.304 55.427 147.12 56.389 ;
     RECT  40.632 55.429 41.856 55.477 ;
     RECT  120.072 55.475 121.056 56.483 ;
     RECT  68.232 55.477 69.408 55.715 ;
     RECT  127.512 55.523 128.64 55.907 ;
     RECT  117.816 55.621 118.8 56.197 ;
     RECT  67.512 55.715 67.704 57.013 ;
     RECT  69.312 55.715 69.408 57.109 ;
     RECT  125.16 55.715 126.6 55.955 ;
     RECT  40.512 55.763 41.52 56.195 ;
     RECT  98.376 55.813 99.504 57.059 ;
     RECT  37.272 55.859 38.448 55.907 ;
     RECT  15.912 55.907 17.136 57.635 ;
     RECT  32.04 55.907 33.072 57.011 ;
     RECT  103.704 55.955 105 57.157 ;
     RECT  105.72 55.955 107.136 57.203 ;
     RECT  125.112 55.955 126.6 57.205 ;
     RECT  156.84 55.955 157.92 57.203 ;
     RECT  20.808 56.099 22.032 56.483 ;
     RECT  22.344 56.101 23.328 56.149 ;
     RECT  40.512 56.195 41.904 56.483 ;
     RECT  151.032 56.195 152.16 57.059 ;
     RECT  116.952 56.243 117.936 58.163 ;
     RECT  154.2 56.293 155.568 57.059 ;
     RECT  132.312 56.387 133.392 57.635 ;
     RECT  62.952 56.389 64.08 56.725 ;
     RECT  145.944 56.389 147.12 56.821 ;
     RECT  148.872 56.389 149.904 56.677 ;
     RECT  43.272 56.483 44.544 58.115 ;
     RECT  48.12 56.483 49.248 56.867 ;
     RECT  128.664 56.483 130.032 57.635 ;
     RECT  74.088 56.485 75.264 56.723 ;
     RECT  86.472 56.531 87.456 57.541 ;
     RECT  75.288 56.627 76.656 58.163 ;
     RECT  107.976 56.627 109.248 57.059 ;
     RECT  8.28 56.723 9.648 58.357 ;
     RECT  73.944 56.723 75.264 57.107 ;
     RECT  5.352 56.771 6.624 57.059 ;
     RECT  145.992 56.821 147.12 57.877 ;
     RECT  162.504 56.821 163.536 57.443 ;
     RECT  47.976 56.867 49.248 58.163 ;
     RECT  164.712 56.867 166.176 57.059 ;
     RECT  32.04 57.011 33.744 57.493 ;
     RECT  46.2 57.013 47.52 57.059 ;
     RECT  5.352 57.059 7.44 58.453 ;
     RECT  46.2 57.059 47.952 57.205 ;
     RECT  50.832 57.059 50.88 58.021 ;
     RECT  53.064 57.059 54.192 57.731 ;
     RECT  54.6 57.059 55.584 58.403 ;
     RECT  83.712 57.059 84.96 58.163 ;
     RECT  96.84 57.059 98.352 58.163 ;
     RECT  98.376 57.059 99.6 58.163 ;
     RECT  107.832 57.059 109.248 58.019 ;
     RECT  123.192 57.059 124.272 59.459 ;
     RECT  164.712 57.059 166.32 58.117 ;
     RECT  157.944 57.107 159 58.115 ;
     RECT  28.656 57.155 28.848 58.117 ;
     RECT  10.632 57.203 11.856 57.635 ;
     RECT  156.6 57.203 157.92 57.395 ;
     RECT  46.536 57.205 47.952 58.739 ;
     RECT  29.712 57.251 31.056 58.403 ;
     RECT  67.704 57.301 68.976 57.443 ;
     RECT  62.952 57.395 64.368 60.757 ;
     RECT  67.656 57.443 68.976 57.539 ;
     RECT  162.504 57.443 164.064 58.357 ;
     RECT  78.936 57.445 80.4 58.115 ;
     RECT  134.856 57.445 135.888 58.019 ;
     RECT  103.704 57.491 104.88 57.827 ;
     RECT  32.472 57.493 33.744 58.691 ;
     RECT  31.08 57.539 32.448 58.403 ;
     RECT  67.512 57.539 68.976 58.355 ;
     RECT  160.152 57.541 161.424 58.117 ;
     RECT  85.512 57.587 86.592 58.163 ;
     RECT  10.392 57.635 11.856 59.891 ;
     RECT  14.088 57.635 15.264 58.739 ;
     RECT  15.288 57.635 15.528 58.739 ;
     RECT  22.344 57.635 23.328 57.875 ;
     RECT  95.496 57.635 96.816 58.933 ;
     RECT  121.512 57.635 122.496 57.683 ;
     RECT  128.664 57.635 130.08 58.213 ;
     RECT  130.68 57.635 131.904 58.837 ;
     RECT  132.312 57.635 132.552 58.453 ;
     RECT  134.304 57.635 134.352 58.163 ;
     RECT  121.512 57.683 122.784 60.563 ;
     RECT  52.872 57.731 54.192 60.373 ;
     RECT  22.344 57.875 23.616 58.739 ;
     RECT  144.744 57.925 145.92 58.115 ;
     RECT  107.736 58.019 109.248 58.357 ;
     RECT  134.856 58.019 136.032 58.163 ;
     RECT  100.92 58.067 102.24 58.451 ;
     RECT  43.272 58.115 44.976 58.789 ;
     RECT  79.968 58.115 80.4 58.837 ;
     RECT  146.472 58.115 147.456 59.459 ;
     RECT  160.2 58.117 161.424 58.739 ;
     RECT  164.712 58.117 166.032 59.891 ;
     RECT  33.768 58.163 34.8 58.835 ;
     RECT  47.976 58.163 49.032 58.213 ;
     RECT  83.712 58.163 85.008 59.219 ;
     RECT  85.32 58.163 86.592 59.219 ;
     RECT  116.952 58.163 118.8 58.837 ;
     RECT  134.304 58.163 134.328 58.645 ;
     RECT  136.2 58.163 137.4 60.181 ;
     RECT  47.976 58.213 49.008 58.451 ;
     RECT  128.952 58.213 130.08 58.355 ;
     RECT  67.512 58.355 68.232 59.125 ;
     RECT  128.664 58.355 130.08 58.739 ;
     RECT  107.736 58.357 109.104 58.787 ;
     RECT  162.744 58.357 164.064 58.885 ;
     RECT  8.112 58.403 9.12 58.499 ;
     RECT  31.488 58.403 32.448 58.691 ;
     RECT  161.64 58.403 162.72 58.547 ;
     RECT  100.824 58.451 102.24 58.979 ;
     RECT  5.352 58.453 6.864 58.643 ;
     RECT  161.496 58.547 162.72 59.315 ;
     RECT  5.352 58.643 5.736 58.739 ;
     RECT  18.912 58.643 20.16 59.315 ;
     RECT  119.256 58.645 120.336 58.787 ;
     RECT  31.488 58.691 31.512 59.269 ;
     RECT  5.712 58.739 5.736 59.029 ;
     RECT  14.088 58.739 15.528 58.741 ;
     RECT  46.536 58.739 47.4 59.749 ;
     RECT  129.216 58.739 130.08 59.315 ;
     RECT  148.728 58.739 149.904 59.315 ;
     RECT  160.2 58.739 161.472 59.315 ;
     RECT  14.328 58.741 15.528 58.981 ;
     RECT  39.048 58.787 40.08 61.045 ;
     RECT  102.264 58.787 102.84 60.133 ;
     RECT  114.552 58.787 115.8 59.603 ;
     RECT  119.016 58.787 120.336 59.075 ;
     RECT  43.608 58.789 44.976 58.931 ;
     RECT  117.672 58.837 118.8 59.171 ;
     RECT  130.872 58.837 131.904 59.219 ;
     RECT  70.104 58.883 71.088 59.507 ;
     RECT  162.744 58.885 164.016 60.373 ;
     RECT  43.248 58.931 43.368 59.605 ;
     RECT  95.496 58.933 96.672 59.123 ;
     RECT  17.232 58.979 17.904 59.653 ;
     RECT  99.912 58.979 100.632 60.469 ;
     RECT  14.328 58.981 15.504 59.027 ;
     RECT  13.512 59.027 13.752 60.373 ;
     RECT  64.392 59.075 65.568 59.843 ;
     RECT  119.016 59.075 121.056 60.277 ;
     RECT  95.496 59.123 96.816 59.125 ;
     RECT  95.736 59.125 96.816 59.315 ;
     RECT  116.952 59.171 117.192 59.315 ;
     RECT  137.712 59.171 138.12 60.373 ;
     RECT  71.112 59.219 72.6 59.507 ;
     RECT  83.712 59.219 84.504 59.557 ;
     RECT  130.872 59.219 132 60.181 ;
     RECT  73.272 59.315 73.608 60.469 ;
     RECT  94.512 59.315 95.712 59.411 ;
     RECT  109.104 59.315 109.488 60.805 ;
     RECT  110.712 59.315 112.176 61.621 ;
     RECT  116.808 59.315 117.192 59.363 ;
     RECT  125.112 59.315 126.288 60.709 ;
     RECT  129.216 59.315 129.24 59.605 ;
     RECT  148.728 59.315 150.192 62.677 ;
     RECT  162.096 59.315 162.72 60.373 ;
     RECT  51.312 59.363 52.848 60.757 ;
     RECT  116.664 59.363 117.192 60.661 ;
     RECT  94.512 59.411 94.968 60.421 ;
     RECT  159.624 59.411 160.008 60.661 ;
     RECT  24.408 59.459 25.632 60.421 ;
     RECT  122.808 59.459 124.272 60.563 ;
     RECT  70.104 59.507 72.6 60.373 ;
     RECT  114.528 59.603 115.8 60.373 ;
     RECT  40.512 59.605 41.904 60.613 ;
     RECT  41.928 59.605 43.368 59.989 ;
     RECT  16.392 59.653 17.904 59.891 ;
     RECT  11.88 59.699 13.2 59.987 ;
     RECT  76.944 59.843 77.184 60.949 ;
     RECT  10.056 59.891 11.856 59.987 ;
     RECT  16.392 59.891 18.6 60.949 ;
     RECT  132.552 59.941 133.92 61.525 ;
     RECT  10.056 59.987 13.2 60.373 ;
     RECT  41.928 59.989 43.344 60.131 ;
     RECT  41.928 60.131 42.6 60.373 ;
     RECT  102.264 60.133 103.728 60.373 ;
     RECT  103.752 60.133 104.784 61.525 ;
     RECT  119.016 60.277 120.336 62.869 ;
     RECT  10.056 60.373 11.808 60.949 ;
     RECT  11.832 60.373 13.2 61.573 ;
     RECT  53.064 60.373 54.192 62.005 ;
     RECT  71.016 60.373 72.6 60.997 ;
     RECT  102.408 60.373 103.728 60.661 ;
     RECT  105.48 60.373 106.848 61.429 ;
     RECT  114.504 60.373 115.8 62.101 ;
     RECT  137.712 60.373 139.104 63.491 ;
     RECT  22.776 60.421 24 62.195 ;
     RECT  59.232 60.467 59.472 60.997 ;
     RECT  60.024 60.467 61.056 60.803 ;
     RECT  155.952 60.467 155.976 60.949 ;
     RECT  54.6 60.469 55.776 60.947 ;
     RECT  73.272 60.469 74.688 62.099 ;
     RECT  100.632 60.517 101.712 60.611 ;
     RECT  121.512 60.563 124.272 60.757 ;
     RECT  100.584 60.611 101.712 60.755 ;
     RECT  40.632 60.613 41.904 61.093 ;
     RECT  70.08 60.659 70.992 61.525 ;
     RECT  102.408 60.661 103.68 62.675 ;
     RECT  112.584 60.707 112.68 60.709 ;
     RECT  112.584 60.709 113.952 61.765 ;
     RECT  51.432 60.757 52.848 61.765 ;
     RECT  121.512 60.757 123.36 60.853 ;
     RECT  122.28 60.853 123.36 62.725 ;
     RECT  54.6 60.947 56.304 62.389 ;
     RECT  62.952 60.947 64.08 64.021 ;
     RECT  2.712 60.949 4.128 63.059 ;
     RECT  10.776 60.949 11.808 61.187 ;
     RECT  17.208 60.949 18.6 61.525 ;
     RECT  20.76 60.949 22.032 61.619 ;
     RECT  35.352 60.949 36.576 63.011 ;
     RECT  81.528 60.949 82.656 62.053 ;
     RECT  117.672 60.949 118.8 62.341 ;
     RECT  155.952 60.949 156.864 61.189 ;
     RECT  166.392 60.949 167.76 63.781 ;
     RECT  19.512 60.997 20.736 61.331 ;
     RECT  57.288 60.997 58.464 61.235 ;
     RECT  58.488 60.997 59.472 61.235 ;
     RECT  71.496 60.997 72.6 61.139 ;
     RECT  71.016 61.139 72.6 61.525 ;
     RECT  10.056 61.187 11.808 61.811 ;
     RECT  153.912 61.189 155.04 62.723 ;
     RECT  155.064 61.189 156.864 61.525 ;
     RECT  18.912 61.331 20.736 61.525 ;
     RECT  40.512 61.331 41.616 63.445 ;
     RECT  8.52 61.429 9.648 62.245 ;
     RECT  106.296 61.475 106.872 62.677 ;
     RECT  139.128 61.477 140.544 62.581 ;
     RECT  17.592 61.525 18.6 65.123 ;
     RECT  18.912 61.525 19.968 65.509 ;
     RECT  68.232 61.525 69.552 61.573 ;
     RECT  69.576 61.525 70.992 63.203 ;
     RECT  71.016 61.525 72.144 62.293 ;
     RECT  165.288 61.525 166.368 64.019 ;
     RECT  11.832 61.573 13.104 61.763 ;
     RECT  96.696 61.621 98.064 61.955 ;
     RECT  11.832 61.763 13.2 63.299 ;
     RECT  9.96 61.811 11.808 62.053 ;
     RECT  68.232 61.859 69.552 63.203 ;
     RECT  110.712 61.907 112.176 64.165 ;
     RECT  96.6 61.955 98.064 62.051 ;
     RECT  94.968 61.957 96.48 64.165 ;
     RECT  53.112 62.005 54.192 62.101 ;
     RECT  160.632 62.005 162.096 63.779 ;
     RECT  87.48 62.051 88.608 64.117 ;
     RECT  96.504 62.051 98.064 62.581 ;
     RECT  9.96 62.053 11.424 63.685 ;
     RECT  81.576 62.053 82.656 63.781 ;
     RECT  53.112 62.101 54.096 62.821 ;
     RECT  22.392 62.195 24 63.253 ;
     RECT  29.976 62.195 30.216 62.293 ;
     RECT  113.976 62.195 115.104 63.205 ;
     RECT  130.872 62.195 132 63.781 ;
     RECT  29.976 62.293 31.584 63.205 ;
     RECT  31.8 62.293 33.024 62.435 ;
     RECT  14.52 62.341 15.984 62.723 ;
     RECT  16.008 62.387 17.184 62.723 ;
     RECT  55.272 62.389 56.304 62.485 ;
     RECT  8.52 62.435 9.744 64.019 ;
     RECT  31.608 62.435 33.024 63.445 ;
     RECT  100.872 62.437 102.24 63.731 ;
     RECT  47.496 62.485 49.008 62.581 ;
     RECT  42.6 62.531 43.032 63.205 ;
     RECT  25.656 62.579 26.736 62.723 ;
     RECT  47.832 62.581 49.008 62.627 ;
     RECT  96.504 62.581 98.016 62.869 ;
     RECT  47.832 62.627 49.032 62.677 ;
     RECT  129.24 62.629 130.752 62.677 ;
     RECT  102.408 62.675 103.872 64.549 ;
     RECT  47.832 62.677 49.296 62.867 ;
     RECT  74.76 62.677 76.032 63.925 ;
     RECT  78.408 62.677 79.776 64.837 ;
     RECT  89.112 62.677 90.528 64.789 ;
     RECT  106.296 62.677 107.472 66.085 ;
     RECT  107.496 62.677 108.816 63.205 ;
     RECT  129.672 62.677 130.752 64.883 ;
     RECT  134.568 62.677 136.08 65.171 ;
     RECT  148.824 62.677 150.192 64.499 ;
     RECT  16.008 62.723 17.376 63.493 ;
     RECT  25.656 62.723 26.832 62.819 ;
     RECT  153.912 62.723 155.328 64.981 ;
     RECT  25.656 62.819 26.856 62.963 ;
     RECT  157.608 62.819 158.688 65.411 ;
     RECT  96.504 62.869 97.968 63.107 ;
     RECT  119.016 62.869 120.288 64.933 ;
     RECT  25.512 62.963 26.856 63.109 ;
     RECT  35.352 63.011 36.6 63.781 ;
     RECT  2.712 63.059 4.152 63.109 ;
     RECT  96.504 63.107 98.016 64.357 ;
     RECT  146.184 63.107 146.232 64.213 ;
     RECT  2.712 63.109 4.176 64.259 ;
     RECT  25.512 63.109 27.312 63.781 ;
     RECT  127.176 63.109 128.64 66.901 ;
     RECT  68.232 63.203 70.992 63.205 ;
     RECT  140.568 63.203 141.648 63.779 ;
     RECT  145.176 63.203 146.16 64.741 ;
     RECT  30.072 63.205 31.584 66.373 ;
     RECT  42.6 63.205 43.872 64.307 ;
     RECT  43.896 63.205 45.264 65.125 ;
     RECT  64.584 63.205 65.808 65.509 ;
     RECT  68.232 63.205 70.08 63.493 ;
     RECT  107.784 63.205 108.816 64.261 ;
     RECT  98.184 63.251 99.36 64.933 ;
     RECT  22.776 63.253 24 64.981 ;
     RECT  11.448 63.299 13.2 63.973 ;
     RECT  31.608 63.445 32.832 67.571 ;
     RECT  40.632 63.445 41.616 63.587 ;
     RECT  32.856 63.491 33.048 63.781 ;
     RECT  137.712 63.491 139.44 63.781 ;
     RECT  16.248 63.493 17.376 63.635 ;
     RECT  68.568 63.493 70.08 63.635 ;
     RECT  40.512 63.587 41.616 63.781 ;
     RECT  16.008 63.635 17.376 65.413 ;
     RECT  68.232 63.635 70.08 64.355 ;
     RECT  9.96 63.685 11.376 63.829 ;
     RECT  100.728 63.731 102.24 63.779 ;
     RECT  155.928 63.731 157.584 64.885 ;
     RECT  140.568 63.779 142.176 64.405 ;
     RECT  160.536 63.779 162.096 64.885 ;
     RECT  162.984 63.779 164.208 64.885 ;
     RECT  25.512 63.781 26.784 64.547 ;
     RECT  32.856 63.781 34.176 65.029 ;
     RECT  35.352 63.781 36.672 63.973 ;
     RECT  40.512 63.781 41.568 67.765 ;
     RECT  130.92 63.781 132 66.469 ;
     RECT  137.928 63.781 139.44 66.085 ;
     RECT  166.488 63.781 167.76 63.829 ;
     RECT  10.248 63.829 11.376 64.643 ;
     RECT  74.952 63.925 76.032 64.837 ;
     RECT  11.448 63.973 12.48 64.019 ;
     RECT  8.52 64.019 9.936 65.509 ;
     RECT  11.4 64.019 12.48 64.595 ;
     RECT  19.992 64.019 20.76 64.789 ;
     RECT  165.192 64.019 166.368 66.181 ;
     RECT  84.504 64.069 85.632 64.211 ;
     RECT  37.656 64.165 38.64 66.323 ;
     RECT  111.192 64.165 112.176 67.477 ;
     RECT  83.832 64.211 85.632 64.355 ;
     RECT  107.832 64.261 108.816 65.125 ;
     RECT  42.504 64.307 43.872 66.325 ;
     RECT  68.232 64.355 70.416 65.077 ;
     RECT  82.104 64.355 83.28 65.461 ;
     RECT  83.832 64.355 85.68 65.315 ;
     RECT  122.328 64.355 123.36 65.603 ;
     RECT  73.368 64.357 74.688 67.093 ;
     RECT  96.6 64.357 98.016 65.509 ;
     RECT  168.36 64.357 169.8 66.755 ;
     RECT  141.144 64.405 142.176 66.373 ;
     RECT  148.824 64.499 150.24 64.595 ;
     RECT  25.512 64.547 25.656 65.317 ;
     RECT  102.408 64.549 103.728 66.085 ;
     RECT  11.4 64.595 12.528 64.643 ;
     RECT  148.68 64.595 150.24 65.557 ;
     RECT  10.248 64.643 10.536 64.933 ;
     RECT  146.232 64.645 147.648 67.237 ;
     RECT  19.992 64.789 21.648 64.981 ;
     RECT  123.72 64.835 124.704 67.141 ;
     RECT  78.408 64.837 79.488 66.085 ;
     RECT  5.352 64.885 6.816 65.603 ;
     RECT  155.928 64.885 157.392 65.317 ;
     RECT  160.776 64.885 162.096 65.027 ;
     RECT  162.984 64.885 164.16 65.509 ;
     RECT  98.232 64.933 99.36 66.181 ;
     RECT  119.112 64.933 120.288 66.133 ;
     RECT  91.656 64.979 92.688 66.661 ;
     RECT  20.568 64.981 21.648 67.427 ;
     RECT  160.536 65.027 162.096 65.269 ;
     RECT  68.232 65.077 69.312 65.173 ;
     RECT  69.336 65.077 70.416 65.461 ;
     RECT  17.4 65.123 18.6 65.459 ;
     RECT  43.896 65.125 45.024 68.867 ;
     RECT  108.552 65.171 109.584 67.237 ;
     RECT  135.84 65.171 136.08 66.085 ;
     RECT  49.608 65.221 50.88 66.469 ;
     RECT  49.296 65.267 49.584 66.469 ;
     RECT  160.536 65.269 162 66.803 ;
     RECT  83.832 65.315 84.168 65.461 ;
     RECT  139.464 65.315 140.544 66.325 ;
     RECT  155.928 65.317 157.344 65.843 ;
     RECT  24.648 65.363 25.632 65.843 ;
     RECT  157.512 65.411 158.688 66.469 ;
     RECT  82.104 65.461 83.184 66.469 ;
     RECT  68.664 65.507 69.744 66.419 ;
     RECT  8.52 65.509 9.696 66.371 ;
     RECT  64.584 65.509 65.664 66.085 ;
     RECT  96.744 65.509 98.016 65.555 ;
     RECT  143.256 65.509 144.672 67.571 ;
     RECT  163.032 65.509 164.16 65.651 ;
     RECT  96.744 65.555 98.208 66.227 ;
     RECT  148.68 65.557 149.76 66.037 ;
     RECT  122.28 65.603 123.36 66.179 ;
     RECT  32.856 65.651 34.176 66.227 ;
     RECT  163.032 65.651 164.256 67.859 ;
     RECT  74.952 65.795 75.936 66.757 ;
     RECT  24.552 65.843 25.632 69.155 ;
     RECT  157.248 65.843 157.344 66.757 ;
     RECT  149.784 65.939 150.456 66.037 ;
     RECT  149.784 66.037 151.056 67.859 ;
     RECT  151.08 66.037 152.112 66.085 ;
     RECT  4.344 66.085 5.328 66.755 ;
     RECT  106.296 66.085 107.28 69.539 ;
     RECT  114.312 66.131 115.344 66.755 ;
     RECT  119.112 66.133 120.192 67.331 ;
     RECT  51.312 66.179 52.512 67.283 ;
     RECT  122.28 66.179 123.696 67.333 ;
     RECT  98.376 66.181 99.36 67.765 ;
     RECT  32.856 66.227 34.704 67.237 ;
     RECT  96.744 66.227 98.352 67.237 ;
     RECT  165.912 66.227 167.088 66.755 ;
     RECT  36.696 66.323 38.64 67.429 ;
     RECT  42.648 66.325 43.872 66.611 ;
     RECT  8.112 66.371 9.696 67.429 ;
     RECT  18.912 66.371 19.968 68.675 ;
     RECT  30.408 66.373 31.584 67.571 ;
     RECT  141.192 66.373 142.176 66.469 ;
     RECT  49.608 66.469 50.832 66.611 ;
     RECT  157.608 66.469 158.688 66.901 ;
     RECT  12.168 66.515 13.2 69.731 ;
     RECT  35.64 66.515 36.672 67.331 ;
     RECT  81.576 66.515 82.608 67.765 ;
     RECT  42.504 66.611 43.872 68.629 ;
     RECT  49.608 66.611 50.88 69.539 ;
     RECT  58.104 66.613 59.472 68.387 ;
     RECT  7.152 66.755 7.44 67.765 ;
     RECT  21.672 66.755 23.376 68.005 ;
     RECT  29.232 66.755 29.28 68.053 ;
     RECT  54.216 66.755 55.248 66.803 ;
     RECT  113.976 66.755 115.344 66.803 ;
     RECT  165.912 66.755 167.376 67.139 ;
     RECT  54.12 66.803 55.248 67.859 ;
     RECT  59.832 66.901 61.056 67.331 ;
     RECT  139.944 67.187 141.168 68.341 ;
     RECT  16.824 67.189 17.856 69.683 ;
     RECT  32.856 67.237 34.224 67.573 ;
     RECT  96.744 67.237 97.728 68.099 ;
     RECT  146.232 67.237 147.552 69.013 ;
     RECT  51.312 67.283 52.704 69.301 ;
     RECT  154.824 67.283 155.64 67.765 ;
     RECT  59.832 67.331 61.248 67.957 ;
     RECT  64.584 67.331 65.664 69.157 ;
     RECT  119.016 67.331 120.192 68.773 ;
     RECT  8.112 67.429 9.456 69.779 ;
     RECT  36.696 67.429 37.872 68.341 ;
     RECT  85.872 67.475 85.92 68.341 ;
     RECT  141.192 67.475 142.272 69.349 ;
     RECT  134.616 67.477 135.84 67.765 ;
     RECT  101.016 67.525 102.24 69.539 ;
     RECT  30.408 67.571 32.832 68.773 ;
     RECT  32.856 67.573 33.984 67.763 ;
     RECT  32.856 67.763 34.224 69.061 ;
     RECT  134.616 67.765 135.696 68.387 ;
     RECT  154.824 67.765 156.24 69.011 ;
     RECT  156.264 67.765 157.248 69.011 ;
     RECT  124.728 67.811 125.76 68.435 ;
     RECT  108.792 67.859 109.968 68.483 ;
     RECT  163.032 67.859 164.304 69.491 ;
     RECT  65.928 67.907 67.056 68.917 ;
     RECT  71.256 67.955 72.24 69.301 ;
     RECT  60.024 67.957 61.248 68.821 ;
     RECT  74.472 68.003 75.504 69.061 ;
     RECT  21.864 68.005 23.376 68.435 ;
     RECT  96.6 68.099 97.728 70.451 ;
     RECT  84.408 68.341 85.92 70.259 ;
     RECT  114.36 68.341 115.344 70.357 ;
     RECT  37.56 68.387 38.64 72.179 ;
     RECT  134.088 68.387 135.696 68.915 ;
     RECT  124.584 68.435 125.76 69.685 ;
     RECT  108.792 68.483 110.304 68.917 ;
     RECT  103.752 68.579 104.88 68.627 ;
     RECT  68.664 68.629 69.696 68.965 ;
     RECT  18.912 68.675 19.944 68.725 ;
     RECT  69.72 68.675 71.232 69.925 ;
     RECT  18.912 68.725 19.92 68.773 ;
     RECT  30.84 68.773 32.832 68.917 ;
     RECT  119.16 68.773 120.192 70.405 ;
     RECT  29.712 68.819 30.816 70.067 ;
     RECT  43.896 68.867 45.312 71.747 ;
     RECT  47.352 68.869 48.576 72.563 ;
     RECT  48.6 68.869 49.584 70.549 ;
     RECT  107.304 68.915 108.48 70.117 ;
     RECT  133.944 68.915 135.696 69.301 ;
     RECT  66.024 68.917 67.056 69.301 ;
     RECT  108.888 68.917 110.304 69.109 ;
     RECT  18.912 68.963 19.92 70.163 ;
     RECT  157.944 68.963 159 69.587 ;
     RECT  154.824 69.011 157.248 69.301 ;
     RECT  146.376 69.013 147.552 69.251 ;
     RECT  130.728 69.059 131.904 69.587 ;
     RECT  33.048 69.061 34.224 69.299 ;
     RECT  108.936 69.109 110.304 69.155 ;
     RECT  79.56 69.155 80.88 70.211 ;
     RECT  108.936 69.155 110.4 69.251 ;
     RECT  60.024 69.203 61.248 70.261 ;
     RECT  30.84 69.251 32.112 69.587 ;
     RECT  68.664 69.251 69.696 72.995 ;
     RECT  108.888 69.251 110.4 71.603 ;
     RECT  146.328 69.251 147.552 69.635 ;
     RECT  32.856 69.299 34.224 70.547 ;
     RECT  66.024 69.301 67.008 69.493 ;
     RECT  133.944 69.301 135.168 70.405 ;
     RECT  154.824 69.301 156.192 70.451 ;
     RECT  156.216 69.301 157.248 69.683 ;
     RECT  135.192 69.347 136.512 70.499 ;
     RECT  80.904 69.443 82.08 70.163 ;
     RECT  121.752 69.443 122.928 70.019 ;
     RECT  163.032 69.491 164.4 70.259 ;
     RECT  49.608 69.539 51 70.837 ;
     RECT  100.92 69.539 102.24 70.163 ;
     RECT  105.96 69.539 107.28 71.843 ;
     RECT  24.312 69.587 24.552 71.029 ;
     RECT  55.32 69.587 56.304 71.315 ;
     RECT  74.472 69.683 75.504 70.741 ;
     RECT  124.776 69.685 125.76 70.069 ;
     RECT  13.104 69.731 13.2 70.261 ;
     RECT  143.256 69.733 144.528 69.973 ;
     RECT  8.112 69.779 9.552 69.827 ;
     RECT  69.72 69.925 70.704 72.947 ;
     RECT  70.728 69.971 71.808 72.229 ;
     RECT  143.256 69.973 144.384 70.019 ;
     RECT  143.208 70.019 144.384 72.325 ;
     RECT  107.304 70.117 108.384 70.691 ;
     RECT  100.92 70.163 102.432 71.315 ;
     RECT  79.56 70.211 80.904 71.221 ;
     RECT  84.072 70.259 85.92 70.547 ;
     RECT  60.024 70.261 61.008 70.597 ;
     RECT  151.848 70.451 152.88 70.739 ;
     RECT  154.728 70.451 156.192 71.315 ;
     RECT  135.192 70.499 136.56 71.315 ;
     RECT  84.072 70.547 86.112 71.221 ;
     RECT  48.6 70.691 49.584 70.883 ;
     RECT  107.304 70.691 108.48 71.843 ;
     RECT  52.008 70.739 53.28 71.267 ;
     RECT  75.288 70.787 76.32 73.523 ;
     RECT  48.6 70.883 50.016 72.563 ;
     RECT  58.68 71.221 60 72.419 ;
     RECT  79.56 71.221 80.88 73.571 ;
     RECT  85.032 71.221 86.112 73.571 ;
     RECT  55.32 71.315 56.4 73.571 ;
     RECT  76.344 71.315 77.472 72.995 ;
     RECT  100.68 71.315 102.432 71.797 ;
     RECT  135.192 71.315 136.896 71.365 ;
     RECT  135.432 71.365 136.896 72.851 ;
     RECT  78.408 71.651 79.536 74.723 ;
     RECT  40.728 71.747 41.712 78.037 ;
     RECT  100.68 71.797 102.048 74.723 ;
     RECT  103.704 71.797 104.88 72.325 ;
     RECT  73.8 71.843 75.264 72.995 ;
     RECT  70.728 72.229 71.712 72.947 ;
     RECT  110.712 72.323 112.08 72.995 ;
     RECT  143.208 72.325 144.336 72.805 ;
     RECT  56.712 72.419 57.744 73.283 ;
     RECT  123.96 72.467 125.328 73.139 ;
     RECT  89.208 72.563 90.24 73.283 ;
     RECT  125.352 72.563 126.6 73.811 ;
     RECT  133.128 72.611 134.112 73.379 ;
     RECT  137.976 72.707 139.056 75.875 ;
     RECT  143.256 72.805 144.336 72.995 ;
     RECT  103.272 72.899 104.352 72.995 ;
     RECT  96.168 72.949 97.488 74.723 ;
     RECT  68.664 72.995 68.76 74.053 ;
     RECT  102.936 72.995 104.352 73.043 ;
     RECT  112.608 72.995 112.656 73.091 ;
     RECT  114.36 72.995 115.344 81.875 ;
     RECT  143.256 72.995 144.576 78.037 ;
     RECT  112.608 73.091 112.752 74.053 ;
     RECT  66.024 73.139 67.008 76.933 ;
     RECT  123.864 73.139 125.328 73.811 ;
     RECT  127.56 73.235 128.688 74.579 ;
     RECT  89.112 73.283 90.24 77.267 ;
     RECT  133.128 73.379 134.4 74.147 ;
     RECT  38.664 73.571 39.648 73.811 ;
     RECT  119.016 74.483 120.336 74.819 ;
     RECT  83.712 74.579 85.008 74.723 ;
     RECT  78.312 74.723 79.536 74.963 ;
     RECT  98.376 75.299 99.6 76.979 ;
     RECT  98.16 75.875 98.352 76.933 ;
     RECT  137.976 75.875 139.488 98.675 ;
     RECT  139.704 76.115 140.88 78.659 ;
     RECT  43.944 76.309 45.36 76.979 ;
     RECT  43.8 76.979 45.36 78.037 ;
     RECT  98.184 76.979 99.6 81.539 ;
     RECT  89.112 77.267 90.288 98.099 ;
     RECT  96.792 77.989 98.16 79.283 ;
     RECT  43.8 78.037 45.312 80.773 ;
     RECT  139.704 78.659 141.024 95.125 ;
     RECT  96.744 79.283 98.16 80.963 ;
     RECT  92.376 79.667 93.408 81.829 ;
     RECT  96.696 80.963 98.16 81.539 ;
     RECT  43.656 81.059 44.736 93.539 ;
     RECT  114.36 81.875 115.392 95.125 ;
     RECT  92.376 82.691 93.408 83.749 ;
     RECT  95.64 83.267 96.672 96.755 ;
     RECT  143.352 83.843 144.48 84.179 ;
     RECT  143.304 84.179 144.48 86.053 ;
     RECT  143.448 86.053 144.48 93.875 ;
     RECT  43.608 93.539 44.736 95.699 ;
     RECT  63.24 93.779 64.368 95.173 ;
     RECT  143.208 93.875 144.48 95.605 ;
     RECT  139.704 95.125 140.832 97.523 ;
     RECT  113.64 95.219 114.624 96.995 ;
     RECT  143.208 95.605 144.24 96.277 ;
     RECT  92.616 95.651 93.696 96.419 ;
     RECT  43.368 95.699 44.736 97.523 ;
     RECT  91.8 96.419 92.04 97.861 ;
     RECT  144.36 96.707 145.584 98.675 ;
     RECT  95.304 96.755 96.672 97.909 ;
     RECT  93.696 96.947 93.744 98.197 ;
     RECT  113.112 96.995 114.624 97.811 ;
     RECT  40.512 97.523 41.568 98.099 ;
     RECT  43.728 97.523 44.736 98.053 ;
     RECT  95.448 97.909 96.672 99.779 ;
     RECT  43.752 98.053 44.736 98.293 ;
     RECT  40.512 98.099 41.712 98.675 ;
     RECT  116.232 98.099 117.456 99.155 ;
     RECT  92.04 98.197 93.024 99.397 ;
     RECT  59.928 98.483 60.912 98.771 ;
     RECT  116.232 99.155 116.28 99.301 ;
     RECT  43.992 99.779 45.6 100.885 ;
     RECT  63.48 99.827 64.848 103.475 ;
     RECT  114.912 99.923 115.008 101.413 ;
     RECT  141.792 100.067 141.936 101.413 ;
     RECT  44.136 100.885 45.6 100.981 ;
     RECT  44.184 100.981 45.6 101.543 ;
     RECT  63.384 103.475 64.848 103.523 ;
  END
END ot_hgi_qdq_fr_retire
END LIBRARY
